VERSION 5.8 ;
BUSBITCHARS "[]" ;
DIVIDERCHAR "/" ;
UNITS
    DATABASE MICRONS 1000 ;
END UNITS

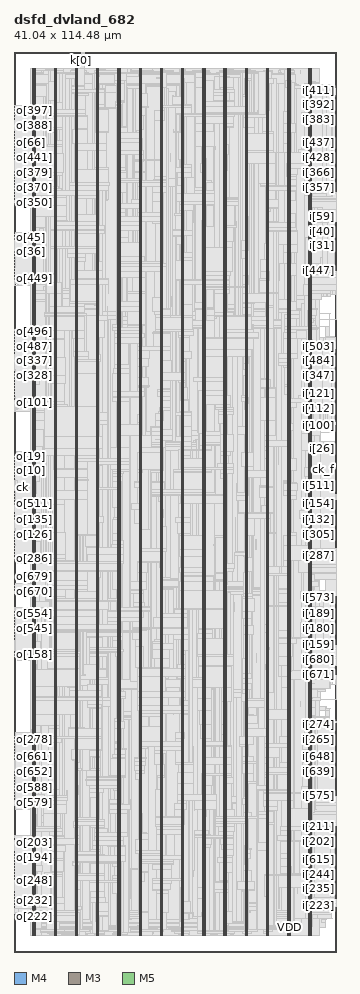
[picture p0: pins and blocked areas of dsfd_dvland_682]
MACRO dsfd_dvland_682
  FOREIGN dsfd_dvland_682 0 0 ;
  CLASS BLOCK ;
  SIZE 41.04 BY 114.48 ;
  PIN ck
    DIRECTION INPUT ;
    USE SIGNAL ;
    PORT
      LAYER M4 ;
        RECT  0 60.048 0.084 60.072 ;
    END
  END ck
  PIN ck_f
    DIRECTION INPUT ;
    USE SIGNAL ;
    PORT
      LAYER M4 ;
        RECT  40.956 61.392 41.04 61.416 ;
    END
  END ck_f
  PIN fault
    DIRECTION OUTPUT ;
    USE SIGNAL ;
    PORT
      LAYER M4 ;
        RECT  0 60.144 0.084 60.168 ;
    END
  END fault
  PIN i[0]
    DIRECTION INPUT ;
    USE SIGNAL ;
    PORT
      LAYER M4 ;
        RECT  40.956 61.488 41.04 61.512 ;
    END
  END i[0]
  PIN i[100]
    DIRECTION INPUT ;
    USE SIGNAL ;
    PORT
      LAYER M4 ;
        RECT  40.956 68.016 41.04 68.04 ;
    END
  END i[100]
  PIN i[101]
    DIRECTION INPUT ;
    USE SIGNAL ;
    PORT
      LAYER M4 ;
        RECT  40.956 68.112 41.04 68.136 ;
    END
  END i[101]
  PIN i[102]
    DIRECTION INPUT ;
    USE SIGNAL ;
    PORT
      LAYER M4 ;
        RECT  40.956 68.208 41.04 68.232 ;
    END
  END i[102]
  PIN i[103]
    DIRECTION INPUT ;
    USE SIGNAL ;
    PORT
      LAYER M4 ;
        RECT  40.956 68.304 41.04 68.328 ;
    END
  END i[103]
  PIN i[104]
    DIRECTION INPUT ;
    USE SIGNAL ;
    PORT
      LAYER M4 ;
        RECT  40.956 68.4 41.04 68.424 ;
    END
  END i[104]
  PIN i[105]
    DIRECTION INPUT ;
    USE SIGNAL ;
    PORT
      LAYER M4 ;
        RECT  40.956 68.496 41.04 68.52 ;
    END
  END i[105]
  PIN i[106]
    DIRECTION INPUT ;
    USE SIGNAL ;
    PORT
      LAYER M4 ;
        RECT  40.956 68.592 41.04 68.616 ;
    END
  END i[106]
  PIN i[107]
    DIRECTION INPUT ;
    USE SIGNAL ;
    PORT
      LAYER M4 ;
        RECT  40.956 68.688 41.04 68.712 ;
    END
  END i[107]
  PIN i[108]
    DIRECTION INPUT ;
    USE SIGNAL ;
    PORT
      LAYER M4 ;
        RECT  40.956 68.784 41.04 68.808 ;
    END
  END i[108]
  PIN i[109]
    DIRECTION INPUT ;
    USE SIGNAL ;
    PORT
      LAYER M4 ;
        RECT  40.956 68.88 41.04 68.904 ;
    END
  END i[109]
  PIN i[10]
    DIRECTION INPUT ;
    USE SIGNAL ;
    PORT
      LAYER M4 ;
        RECT  40.956 62.448 41.04 62.472 ;
    END
  END i[10]
  PIN i[110]
    DIRECTION INPUT ;
    USE SIGNAL ;
    PORT
      LAYER M4 ;
        RECT  40.956 68.976 41.04 69 ;
    END
  END i[110]
  PIN i[111]
    DIRECTION INPUT ;
    USE SIGNAL ;
    PORT
      LAYER M4 ;
        RECT  40.956 69.072 41.04 69.096 ;
    END
  END i[111]
  PIN i[112]
    DIRECTION INPUT ;
    USE SIGNAL ;
    PORT
      LAYER M4 ;
        RECT  40.956 69.168 41.04 69.192 ;
    END
  END i[112]
  PIN i[113]
    DIRECTION INPUT ;
    USE SIGNAL ;
    PORT
      LAYER M4 ;
        RECT  40.956 69.264 41.04 69.288 ;
    END
  END i[113]
  PIN i[114]
    DIRECTION INPUT ;
    USE SIGNAL ;
    PORT
      LAYER M4 ;
        RECT  40.956 69.36 41.04 69.384 ;
    END
  END i[114]
  PIN i[115]
    DIRECTION INPUT ;
    USE SIGNAL ;
    PORT
      LAYER M4 ;
        RECT  40.956 69.456 41.04 69.48 ;
    END
  END i[115]
  PIN i[116]
    DIRECTION INPUT ;
    USE SIGNAL ;
    PORT
      LAYER M4 ;
        RECT  40.956 69.552 41.04 69.576 ;
    END
  END i[116]
  PIN i[117]
    DIRECTION INPUT ;
    USE SIGNAL ;
    PORT
      LAYER M4 ;
        RECT  40.956 69.648 41.04 69.672 ;
    END
  END i[117]
  PIN i[118]
    DIRECTION INPUT ;
    USE SIGNAL ;
    PORT
      LAYER M4 ;
        RECT  40.956 69.744 41.04 69.768 ;
    END
  END i[118]
  PIN i[119]
    DIRECTION INPUT ;
    USE SIGNAL ;
    PORT
      LAYER M4 ;
        RECT  40.956 69.84 41.04 69.864 ;
    END
  END i[119]
  PIN i[11]
    DIRECTION INPUT ;
    USE SIGNAL ;
    PORT
      LAYER M4 ;
        RECT  40.956 62.544 41.04 62.568 ;
    END
  END i[11]
  PIN i[120]
    DIRECTION INPUT ;
    USE SIGNAL ;
    PORT
      LAYER M4 ;
        RECT  40.956 69.936 41.04 69.96 ;
    END
  END i[120]
  PIN i[121]
    DIRECTION INPUT ;
    USE SIGNAL ;
    PORT
      LAYER M4 ;
        RECT  40.956 70.032 41.04 70.056 ;
    END
  END i[121]
  PIN i[122]
    DIRECTION INPUT ;
    USE SIGNAL ;
    PORT
      LAYER M4 ;
        RECT  40.956 70.128 41.04 70.152 ;
    END
  END i[122]
  PIN i[123]
    DIRECTION INPUT ;
    USE SIGNAL ;
    PORT
      LAYER M4 ;
        RECT  40.956 70.224 41.04 70.248 ;
    END
  END i[123]
  PIN i[124]
    DIRECTION INPUT ;
    USE SIGNAL ;
    PORT
      LAYER M4 ;
        RECT  40.956 70.32 41.04 70.344 ;
    END
  END i[124]
  PIN i[125]
    DIRECTION INPUT ;
    USE SIGNAL ;
    PORT
      LAYER M4 ;
        RECT  40.956 70.416 41.04 70.44 ;
    END
  END i[125]
  PIN i[126]
    DIRECTION INPUT ;
    USE SIGNAL ;
    PORT
      LAYER M4 ;
        RECT  40.956 70.512 41.04 70.536 ;
    END
  END i[126]
  PIN i[127]
    DIRECTION INPUT ;
    USE SIGNAL ;
    PORT
      LAYER M4 ;
        RECT  40.956 54.48 41.04 54.504 ;
    END
  END i[127]
  PIN i[128]
    DIRECTION INPUT ;
    USE SIGNAL ;
    PORT
      LAYER M4 ;
        RECT  40.956 54.576 41.04 54.6 ;
    END
  END i[128]
  PIN i[129]
    DIRECTION INPUT ;
    USE SIGNAL ;
    PORT
      LAYER M4 ;
        RECT  40.956 54.672 41.04 54.696 ;
    END
  END i[129]
  PIN i[12]
    DIRECTION INPUT ;
    USE SIGNAL ;
    PORT
      LAYER M4 ;
        RECT  40.956 62.64 41.04 62.664 ;
    END
  END i[12]
  PIN i[130]
    DIRECTION INPUT ;
    USE SIGNAL ;
    PORT
      LAYER M4 ;
        RECT  40.956 54.768 41.04 54.792 ;
    END
  END i[130]
  PIN i[131]
    DIRECTION INPUT ;
    USE SIGNAL ;
    PORT
      LAYER M4 ;
        RECT  40.956 54.864 41.04 54.888 ;
    END
  END i[131]
  PIN i[132]
    DIRECTION INPUT ;
    USE SIGNAL ;
    PORT
      LAYER M4 ;
        RECT  40.956 54.96 41.04 54.984 ;
    END
  END i[132]
  PIN i[133]
    DIRECTION INPUT ;
    USE SIGNAL ;
    PORT
      LAYER M4 ;
        RECT  40.956 55.056 41.04 55.08 ;
    END
  END i[133]
  PIN i[134]
    DIRECTION INPUT ;
    USE SIGNAL ;
    PORT
      LAYER M4 ;
        RECT  40.956 55.152 41.04 55.176 ;
    END
  END i[134]
  PIN i[135]
    DIRECTION INPUT ;
    USE SIGNAL ;
    PORT
      LAYER M4 ;
        RECT  40.956 55.248 41.04 55.272 ;
    END
  END i[135]
  PIN i[136]
    DIRECTION INPUT ;
    USE SIGNAL ;
    PORT
      LAYER M4 ;
        RECT  40.956 55.344 41.04 55.368 ;
    END
  END i[136]
  PIN i[137]
    DIRECTION INPUT ;
    USE SIGNAL ;
    PORT
      LAYER M4 ;
        RECT  40.956 55.44 41.04 55.464 ;
    END
  END i[137]
  PIN i[138]
    DIRECTION INPUT ;
    USE SIGNAL ;
    PORT
      LAYER M4 ;
        RECT  40.956 55.536 41.04 55.56 ;
    END
  END i[138]
  PIN i[139]
    DIRECTION INPUT ;
    USE SIGNAL ;
    PORT
      LAYER M4 ;
        RECT  40.956 55.632 41.04 55.656 ;
    END
  END i[139]
  PIN i[13]
    DIRECTION INPUT ;
    USE SIGNAL ;
    PORT
      LAYER M4 ;
        RECT  40.956 62.736 41.04 62.76 ;
    END
  END i[13]
  PIN i[140]
    DIRECTION INPUT ;
    USE SIGNAL ;
    PORT
      LAYER M4 ;
        RECT  40.956 55.728 41.04 55.752 ;
    END
  END i[140]
  PIN i[141]
    DIRECTION INPUT ;
    USE SIGNAL ;
    PORT
      LAYER M4 ;
        RECT  40.956 55.824 41.04 55.848 ;
    END
  END i[141]
  PIN i[142]
    DIRECTION INPUT ;
    USE SIGNAL ;
    PORT
      LAYER M4 ;
        RECT  40.956 55.92 41.04 55.944 ;
    END
  END i[142]
  PIN i[143]
    DIRECTION INPUT ;
    USE SIGNAL ;
    PORT
      LAYER M4 ;
        RECT  40.956 56.016 41.04 56.04 ;
    END
  END i[143]
  PIN i[144]
    DIRECTION INPUT ;
    USE SIGNAL ;
    PORT
      LAYER M4 ;
        RECT  40.956 56.112 41.04 56.136 ;
    END
  END i[144]
  PIN i[145]
    DIRECTION INPUT ;
    USE SIGNAL ;
    PORT
      LAYER M4 ;
        RECT  40.956 56.208 41.04 56.232 ;
    END
  END i[145]
  PIN i[146]
    DIRECTION INPUT ;
    USE SIGNAL ;
    PORT
      LAYER M4 ;
        RECT  40.956 56.304 41.04 56.328 ;
    END
  END i[146]
  PIN i[147]
    DIRECTION INPUT ;
    USE SIGNAL ;
    PORT
      LAYER M4 ;
        RECT  40.956 56.4 41.04 56.424 ;
    END
  END i[147]
  PIN i[148]
    DIRECTION INPUT ;
    USE SIGNAL ;
    PORT
      LAYER M4 ;
        RECT  40.956 56.496 41.04 56.52 ;
    END
  END i[148]
  PIN i[149]
    DIRECTION INPUT ;
    USE SIGNAL ;
    PORT
      LAYER M4 ;
        RECT  40.956 56.592 41.04 56.616 ;
    END
  END i[149]
  PIN i[14]
    DIRECTION INPUT ;
    USE SIGNAL ;
    PORT
      LAYER M4 ;
        RECT  40.956 62.832 41.04 62.856 ;
    END
  END i[14]
  PIN i[150]
    DIRECTION INPUT ;
    USE SIGNAL ;
    PORT
      LAYER M4 ;
        RECT  40.956 56.688 41.04 56.712 ;
    END
  END i[150]
  PIN i[151]
    DIRECTION INPUT ;
    USE SIGNAL ;
    PORT
      LAYER M4 ;
        RECT  40.956 56.784 41.04 56.808 ;
    END
  END i[151]
  PIN i[152]
    DIRECTION INPUT ;
    USE SIGNAL ;
    PORT
      LAYER M4 ;
        RECT  40.956 56.88 41.04 56.904 ;
    END
  END i[152]
  PIN i[153]
    DIRECTION INPUT ;
    USE SIGNAL ;
    PORT
      LAYER M4 ;
        RECT  40.956 56.976 41.04 57 ;
    END
  END i[153]
  PIN i[154]
    DIRECTION INPUT ;
    USE SIGNAL ;
    PORT
      LAYER M4 ;
        RECT  40.956 57.072 41.04 57.096 ;
    END
  END i[154]
  PIN i[155]
    DIRECTION INPUT ;
    USE SIGNAL ;
    PORT
      LAYER M4 ;
        RECT  40.956 57.168 41.04 57.192 ;
    END
  END i[155]
  PIN i[156]
    DIRECTION INPUT ;
    USE SIGNAL ;
    PORT
      LAYER M4 ;
        RECT  40.956 57.264 41.04 57.288 ;
    END
  END i[156]
  PIN i[157]
    DIRECTION INPUT ;
    USE SIGNAL ;
    PORT
      LAYER M4 ;
        RECT  40.956 57.36 41.04 57.384 ;
    END
  END i[157]
  PIN i[158]
    DIRECTION INPUT ;
    USE SIGNAL ;
    PORT
      LAYER M4 ;
        RECT  40.956 57.456 41.04 57.48 ;
    END
  END i[158]
  PIN i[159]
    DIRECTION INPUT ;
    USE SIGNAL ;
    PORT
      LAYER M4 ;
        RECT  40.956 39.12 41.04 39.144 ;
    END
  END i[159]
  PIN i[15]
    DIRECTION INPUT ;
    USE SIGNAL ;
    PORT
      LAYER M4 ;
        RECT  40.956 62.928 41.04 62.952 ;
    END
  END i[15]
  PIN i[160]
    DIRECTION INPUT ;
    USE SIGNAL ;
    PORT
      LAYER M4 ;
        RECT  40.956 39.216 41.04 39.24 ;
    END
  END i[160]
  PIN i[161]
    DIRECTION INPUT ;
    USE SIGNAL ;
    PORT
      LAYER M4 ;
        RECT  40.956 39.312 41.04 39.336 ;
    END
  END i[161]
  PIN i[162]
    DIRECTION INPUT ;
    USE SIGNAL ;
    PORT
      LAYER M4 ;
        RECT  40.956 39.408 41.04 39.432 ;
    END
  END i[162]
  PIN i[163]
    DIRECTION INPUT ;
    USE SIGNAL ;
    PORT
      LAYER M4 ;
        RECT  40.956 39.504 41.04 39.528 ;
    END
  END i[163]
  PIN i[164]
    DIRECTION INPUT ;
    USE SIGNAL ;
    PORT
      LAYER M4 ;
        RECT  40.956 39.6 41.04 39.624 ;
    END
  END i[164]
  PIN i[165]
    DIRECTION INPUT ;
    USE SIGNAL ;
    PORT
      LAYER M4 ;
        RECT  40.956 39.696 41.04 39.72 ;
    END
  END i[165]
  PIN i[166]
    DIRECTION INPUT ;
    USE SIGNAL ;
    PORT
      LAYER M4 ;
        RECT  40.956 39.792 41.04 39.816 ;
    END
  END i[166]
  PIN i[167]
    DIRECTION INPUT ;
    USE SIGNAL ;
    PORT
      LAYER M4 ;
        RECT  40.956 39.888 41.04 39.912 ;
    END
  END i[167]
  PIN i[168]
    DIRECTION INPUT ;
    USE SIGNAL ;
    PORT
      LAYER M4 ;
        RECT  40.956 39.984 41.04 40.008 ;
    END
  END i[168]
  PIN i[169]
    DIRECTION INPUT ;
    USE SIGNAL ;
    PORT
      LAYER M4 ;
        RECT  40.956 40.08 41.04 40.104 ;
    END
  END i[169]
  PIN i[16]
    DIRECTION INPUT ;
    USE SIGNAL ;
    PORT
      LAYER M4 ;
        RECT  40.956 63.024 41.04 63.048 ;
    END
  END i[16]
  PIN i[170]
    DIRECTION INPUT ;
    USE SIGNAL ;
    PORT
      LAYER M4 ;
        RECT  40.956 40.176 41.04 40.2 ;
    END
  END i[170]
  PIN i[171]
    DIRECTION INPUT ;
    USE SIGNAL ;
    PORT
      LAYER M4 ;
        RECT  40.956 40.272 41.04 40.296 ;
    END
  END i[171]
  PIN i[172]
    DIRECTION INPUT ;
    USE SIGNAL ;
    PORT
      LAYER M4 ;
        RECT  40.956 40.368 41.04 40.392 ;
    END
  END i[172]
  PIN i[173]
    DIRECTION INPUT ;
    USE SIGNAL ;
    PORT
      LAYER M4 ;
        RECT  40.956 40.464 41.04 40.488 ;
    END
  END i[173]
  PIN i[174]
    DIRECTION INPUT ;
    USE SIGNAL ;
    PORT
      LAYER M4 ;
        RECT  40.956 40.56 41.04 40.584 ;
    END
  END i[174]
  PIN i[175]
    DIRECTION INPUT ;
    USE SIGNAL ;
    PORT
      LAYER M4 ;
        RECT  40.956 40.656 41.04 40.68 ;
    END
  END i[175]
  PIN i[176]
    DIRECTION INPUT ;
    USE SIGNAL ;
    PORT
      LAYER M4 ;
        RECT  40.956 40.752 41.04 40.776 ;
    END
  END i[176]
  PIN i[177]
    DIRECTION INPUT ;
    USE SIGNAL ;
    PORT
      LAYER M4 ;
        RECT  40.956 40.848 41.04 40.872 ;
    END
  END i[177]
  PIN i[178]
    DIRECTION INPUT ;
    USE SIGNAL ;
    PORT
      LAYER M4 ;
        RECT  40.956 40.944 41.04 40.968 ;
    END
  END i[178]
  PIN i[179]
    DIRECTION INPUT ;
    USE SIGNAL ;
    PORT
      LAYER M4 ;
        RECT  40.956 41.04 41.04 41.064 ;
    END
  END i[179]
  PIN i[17]
    DIRECTION INPUT ;
    USE SIGNAL ;
    PORT
      LAYER M4 ;
        RECT  40.956 63.12 41.04 63.144 ;
    END
  END i[17]
  PIN i[180]
    DIRECTION INPUT ;
    USE SIGNAL ;
    PORT
      LAYER M4 ;
        RECT  40.956 41.136 41.04 41.16 ;
    END
  END i[180]
  PIN i[181]
    DIRECTION INPUT ;
    USE SIGNAL ;
    PORT
      LAYER M4 ;
        RECT  40.956 41.232 41.04 41.256 ;
    END
  END i[181]
  PIN i[182]
    DIRECTION INPUT ;
    USE SIGNAL ;
    PORT
      LAYER M4 ;
        RECT  40.956 41.328 41.04 41.352 ;
    END
  END i[182]
  PIN i[183]
    DIRECTION INPUT ;
    USE SIGNAL ;
    PORT
      LAYER M4 ;
        RECT  40.956 41.424 41.04 41.448 ;
    END
  END i[183]
  PIN i[184]
    DIRECTION INPUT ;
    USE SIGNAL ;
    PORT
      LAYER M4 ;
        RECT  40.956 41.52 41.04 41.544 ;
    END
  END i[184]
  PIN i[185]
    DIRECTION INPUT ;
    USE SIGNAL ;
    PORT
      LAYER M4 ;
        RECT  40.956 41.616 41.04 41.64 ;
    END
  END i[185]
  PIN i[186]
    DIRECTION INPUT ;
    USE SIGNAL ;
    PORT
      LAYER M4 ;
        RECT  40.956 41.712 41.04 41.736 ;
    END
  END i[186]
  PIN i[187]
    DIRECTION INPUT ;
    USE SIGNAL ;
    PORT
      LAYER M4 ;
        RECT  40.956 41.808 41.04 41.832 ;
    END
  END i[187]
  PIN i[188]
    DIRECTION INPUT ;
    USE SIGNAL ;
    PORT
      LAYER M4 ;
        RECT  40.956 41.904 41.04 41.928 ;
    END
  END i[188]
  PIN i[189]
    DIRECTION INPUT ;
    USE SIGNAL ;
    PORT
      LAYER M4 ;
        RECT  40.956 42 41.04 42.024 ;
    END
  END i[189]
  PIN i[18]
    DIRECTION INPUT ;
    USE SIGNAL ;
    PORT
      LAYER M4 ;
        RECT  40.956 63.216 41.04 63.24 ;
    END
  END i[18]
  PIN i[190]
    DIRECTION INPUT ;
    USE SIGNAL ;
    PORT
      LAYER M4 ;
        RECT  40.956 42.096 41.04 42.12 ;
    END
  END i[190]
  PIN i[191]
    DIRECTION INPUT ;
    USE SIGNAL ;
    PORT
      LAYER M4 ;
        RECT  40.956 13.008 41.04 13.032 ;
    END
  END i[191]
  PIN i[192]
    DIRECTION INPUT ;
    USE SIGNAL ;
    PORT
      LAYER M4 ;
        RECT  40.956 13.104 41.04 13.128 ;
    END
  END i[192]
  PIN i[193]
    DIRECTION INPUT ;
    USE SIGNAL ;
    PORT
      LAYER M4 ;
        RECT  40.956 13.2 41.04 13.224 ;
    END
  END i[193]
  PIN i[194]
    DIRECTION INPUT ;
    USE SIGNAL ;
    PORT
      LAYER M4 ;
        RECT  40.956 13.296 41.04 13.32 ;
    END
  END i[194]
  PIN i[195]
    DIRECTION INPUT ;
    USE SIGNAL ;
    PORT
      LAYER M4 ;
        RECT  40.956 13.392 41.04 13.416 ;
    END
  END i[195]
  PIN i[196]
    DIRECTION INPUT ;
    USE SIGNAL ;
    PORT
      LAYER M4 ;
        RECT  40.956 13.488 41.04 13.512 ;
    END
  END i[196]
  PIN i[197]
    DIRECTION INPUT ;
    USE SIGNAL ;
    PORT
      LAYER M4 ;
        RECT  40.956 13.584 41.04 13.608 ;
    END
  END i[197]
  PIN i[198]
    DIRECTION INPUT ;
    USE SIGNAL ;
    PORT
      LAYER M4 ;
        RECT  40.956 13.68 41.04 13.704 ;
    END
  END i[198]
  PIN i[199]
    DIRECTION INPUT ;
    USE SIGNAL ;
    PORT
      LAYER M4 ;
        RECT  40.956 13.776 41.04 13.8 ;
    END
  END i[199]
  PIN i[19]
    DIRECTION INPUT ;
    USE SIGNAL ;
    PORT
      LAYER M4 ;
        RECT  40.956 63.312 41.04 63.336 ;
    END
  END i[19]
  PIN i[1]
    DIRECTION INPUT ;
    USE SIGNAL ;
    PORT
      LAYER M4 ;
        RECT  40.956 61.584 41.04 61.608 ;
    END
  END i[1]
  PIN i[200]
    DIRECTION INPUT ;
    USE SIGNAL ;
    PORT
      LAYER M4 ;
        RECT  40.956 13.872 41.04 13.896 ;
    END
  END i[200]
  PIN i[201]
    DIRECTION INPUT ;
    USE SIGNAL ;
    PORT
      LAYER M4 ;
        RECT  40.956 13.968 41.04 13.992 ;
    END
  END i[201]
  PIN i[202]
    DIRECTION INPUT ;
    USE SIGNAL ;
    PORT
      LAYER M4 ;
        RECT  40.956 14.064 41.04 14.088 ;
    END
  END i[202]
  PIN i[203]
    DIRECTION INPUT ;
    USE SIGNAL ;
    PORT
      LAYER M4 ;
        RECT  40.956 14.16 41.04 14.184 ;
    END
  END i[203]
  PIN i[204]
    DIRECTION INPUT ;
    USE SIGNAL ;
    PORT
      LAYER M4 ;
        RECT  40.956 14.256 41.04 14.28 ;
    END
  END i[204]
  PIN i[205]
    DIRECTION INPUT ;
    USE SIGNAL ;
    PORT
      LAYER M4 ;
        RECT  40.956 14.352 41.04 14.376 ;
    END
  END i[205]
  PIN i[206]
    DIRECTION INPUT ;
    USE SIGNAL ;
    PORT
      LAYER M4 ;
        RECT  40.956 14.448 41.04 14.472 ;
    END
  END i[206]
  PIN i[207]
    DIRECTION INPUT ;
    USE SIGNAL ;
    PORT
      LAYER M4 ;
        RECT  40.956 14.544 41.04 14.568 ;
    END
  END i[207]
  PIN i[208]
    DIRECTION INPUT ;
    USE SIGNAL ;
    PORT
      LAYER M4 ;
        RECT  40.956 14.64 41.04 14.664 ;
    END
  END i[208]
  PIN i[209]
    DIRECTION INPUT ;
    USE SIGNAL ;
    PORT
      LAYER M4 ;
        RECT  40.956 14.736 41.04 14.76 ;
    END
  END i[209]
  PIN i[20]
    DIRECTION INPUT ;
    USE SIGNAL ;
    PORT
      LAYER M4 ;
        RECT  40.956 63.408 41.04 63.432 ;
    END
  END i[20]
  PIN i[210]
    DIRECTION INPUT ;
    USE SIGNAL ;
    PORT
      LAYER M4 ;
        RECT  40.956 14.832 41.04 14.856 ;
    END
  END i[210]
  PIN i[211]
    DIRECTION INPUT ;
    USE SIGNAL ;
    PORT
      LAYER M4 ;
        RECT  40.956 14.928 41.04 14.952 ;
    END
  END i[211]
  PIN i[212]
    DIRECTION INPUT ;
    USE SIGNAL ;
    PORT
      LAYER M4 ;
        RECT  40.956 15.024 41.04 15.048 ;
    END
  END i[212]
  PIN i[213]
    DIRECTION INPUT ;
    USE SIGNAL ;
    PORT
      LAYER M4 ;
        RECT  40.956 15.12 41.04 15.144 ;
    END
  END i[213]
  PIN i[214]
    DIRECTION INPUT ;
    USE SIGNAL ;
    PORT
      LAYER M4 ;
        RECT  40.956 15.216 41.04 15.24 ;
    END
  END i[214]
  PIN i[215]
    DIRECTION INPUT ;
    USE SIGNAL ;
    PORT
      LAYER M4 ;
        RECT  40.956 15.312 41.04 15.336 ;
    END
  END i[215]
  PIN i[216]
    DIRECTION INPUT ;
    USE SIGNAL ;
    PORT
      LAYER M4 ;
        RECT  40.956 15.408 41.04 15.432 ;
    END
  END i[216]
  PIN i[217]
    DIRECTION INPUT ;
    USE SIGNAL ;
    PORT
      LAYER M4 ;
        RECT  40.956 15.504 41.04 15.528 ;
    END
  END i[217]
  PIN i[218]
    DIRECTION INPUT ;
    USE SIGNAL ;
    PORT
      LAYER M4 ;
        RECT  40.956 15.6 41.04 15.624 ;
    END
  END i[218]
  PIN i[219]
    DIRECTION INPUT ;
    USE SIGNAL ;
    PORT
      LAYER M4 ;
        RECT  40.956 15.696 41.04 15.72 ;
    END
  END i[219]
  PIN i[21]
    DIRECTION INPUT ;
    USE SIGNAL ;
    PORT
      LAYER M4 ;
        RECT  40.956 63.504 41.04 63.528 ;
    END
  END i[21]
  PIN i[220]
    DIRECTION INPUT ;
    USE SIGNAL ;
    PORT
      LAYER M4 ;
        RECT  40.956 15.792 41.04 15.816 ;
    END
  END i[220]
  PIN i[221]
    DIRECTION INPUT ;
    USE SIGNAL ;
    PORT
      LAYER M4 ;
        RECT  40.956 15.888 41.04 15.912 ;
    END
  END i[221]
  PIN i[222]
    DIRECTION INPUT ;
    USE SIGNAL ;
    PORT
      LAYER M4 ;
        RECT  40.956 15.984 41.04 16.008 ;
    END
  END i[222]
  PIN i[223]
    DIRECTION INPUT ;
    USE SIGNAL ;
    PORT
      LAYER M4 ;
        RECT  40.956 6.864 41.04 6.888 ;
    END
  END i[223]
  PIN i[224]
    DIRECTION INPUT ;
    USE SIGNAL ;
    PORT
      LAYER M4 ;
        RECT  40.956 6.96 41.04 6.984 ;
    END
  END i[224]
  PIN i[225]
    DIRECTION INPUT ;
    USE SIGNAL ;
    PORT
      LAYER M4 ;
        RECT  40.956 7.056 41.04 7.08 ;
    END
  END i[225]
  PIN i[226]
    DIRECTION INPUT ;
    USE SIGNAL ;
    PORT
      LAYER M4 ;
        RECT  40.956 7.152 41.04 7.176 ;
    END
  END i[226]
  PIN i[227]
    DIRECTION INPUT ;
    USE SIGNAL ;
    PORT
      LAYER M4 ;
        RECT  40.956 7.248 41.04 7.272 ;
    END
  END i[227]
  PIN i[228]
    DIRECTION INPUT ;
    USE SIGNAL ;
    PORT
      LAYER M4 ;
        RECT  40.956 7.344 41.04 7.368 ;
    END
  END i[228]
  PIN i[229]
    DIRECTION INPUT ;
    USE SIGNAL ;
    PORT
      LAYER M4 ;
        RECT  40.956 7.44 41.04 7.464 ;
    END
  END i[229]
  PIN i[22]
    DIRECTION INPUT ;
    USE SIGNAL ;
    PORT
      LAYER M4 ;
        RECT  40.956 63.6 41.04 63.624 ;
    END
  END i[22]
  PIN i[230]
    DIRECTION INPUT ;
    USE SIGNAL ;
    PORT
      LAYER M4 ;
        RECT  40.956 7.536 41.04 7.56 ;
    END
  END i[230]
  PIN i[231]
    DIRECTION INPUT ;
    USE SIGNAL ;
    PORT
      LAYER M4 ;
        RECT  40.956 7.632 41.04 7.656 ;
    END
  END i[231]
  PIN i[232]
    DIRECTION INPUT ;
    USE SIGNAL ;
    PORT
      LAYER M4 ;
        RECT  40.956 7.728 41.04 7.752 ;
    END
  END i[232]
  PIN i[233]
    DIRECTION INPUT ;
    USE SIGNAL ;
    PORT
      LAYER M4 ;
        RECT  40.956 7.824 41.04 7.848 ;
    END
  END i[233]
  PIN i[234]
    DIRECTION INPUT ;
    USE SIGNAL ;
    PORT
      LAYER M4 ;
        RECT  40.956 7.92 41.04 7.944 ;
    END
  END i[234]
  PIN i[235]
    DIRECTION INPUT ;
    USE SIGNAL ;
    PORT
      LAYER M4 ;
        RECT  40.956 8.016 41.04 8.04 ;
    END
  END i[235]
  PIN i[236]
    DIRECTION INPUT ;
    USE SIGNAL ;
    PORT
      LAYER M4 ;
        RECT  40.956 8.112 41.04 8.136 ;
    END
  END i[236]
  PIN i[237]
    DIRECTION INPUT ;
    USE SIGNAL ;
    PORT
      LAYER M4 ;
        RECT  40.956 8.208 41.04 8.232 ;
    END
  END i[237]
  PIN i[238]
    DIRECTION INPUT ;
    USE SIGNAL ;
    PORT
      LAYER M4 ;
        RECT  40.956 8.304 41.04 8.328 ;
    END
  END i[238]
  PIN i[239]
    DIRECTION INPUT ;
    USE SIGNAL ;
    PORT
      LAYER M4 ;
        RECT  40.956 8.4 41.04 8.424 ;
    END
  END i[239]
  PIN i[23]
    DIRECTION INPUT ;
    USE SIGNAL ;
    PORT
      LAYER M4 ;
        RECT  40.956 63.696 41.04 63.72 ;
    END
  END i[23]
  PIN i[240]
    DIRECTION INPUT ;
    USE SIGNAL ;
    PORT
      LAYER M4 ;
        RECT  40.956 8.496 41.04 8.52 ;
    END
  END i[240]
  PIN i[241]
    DIRECTION INPUT ;
    USE SIGNAL ;
    PORT
      LAYER M4 ;
        RECT  40.956 8.592 41.04 8.616 ;
    END
  END i[241]
  PIN i[242]
    DIRECTION INPUT ;
    USE SIGNAL ;
    PORT
      LAYER M4 ;
        RECT  40.956 8.688 41.04 8.712 ;
    END
  END i[242]
  PIN i[243]
    DIRECTION INPUT ;
    USE SIGNAL ;
    PORT
      LAYER M4 ;
        RECT  40.956 8.784 41.04 8.808 ;
    END
  END i[243]
  PIN i[244]
    DIRECTION INPUT ;
    USE SIGNAL ;
    PORT
      LAYER M4 ;
        RECT  40.956 8.88 41.04 8.904 ;
    END
  END i[244]
  PIN i[245]
    DIRECTION INPUT ;
    USE SIGNAL ;
    PORT
      LAYER M4 ;
        RECT  40.956 8.976 41.04 9 ;
    END
  END i[245]
  PIN i[246]
    DIRECTION INPUT ;
    USE SIGNAL ;
    PORT
      LAYER M4 ;
        RECT  40.956 9.072 41.04 9.096 ;
    END
  END i[246]
  PIN i[247]
    DIRECTION INPUT ;
    USE SIGNAL ;
    PORT
      LAYER M4 ;
        RECT  40.956 9.168 41.04 9.192 ;
    END
  END i[247]
  PIN i[248]
    DIRECTION INPUT ;
    USE SIGNAL ;
    PORT
      LAYER M4 ;
        RECT  40.956 9.264 41.04 9.288 ;
    END
  END i[248]
  PIN i[249]
    DIRECTION INPUT ;
    USE SIGNAL ;
    PORT
      LAYER M4 ;
        RECT  40.956 9.36 41.04 9.384 ;
    END
  END i[249]
  PIN i[24]
    DIRECTION INPUT ;
    USE SIGNAL ;
    PORT
      LAYER M4 ;
        RECT  40.956 63.792 41.04 63.816 ;
    END
  END i[24]
  PIN i[250]
    DIRECTION INPUT ;
    USE SIGNAL ;
    PORT
      LAYER M4 ;
        RECT  40.956 9.456 41.04 9.48 ;
    END
  END i[250]
  PIN i[251]
    DIRECTION INPUT ;
    USE SIGNAL ;
    PORT
      LAYER M4 ;
        RECT  40.956 9.552 41.04 9.576 ;
    END
  END i[251]
  PIN i[252]
    DIRECTION INPUT ;
    USE SIGNAL ;
    PORT
      LAYER M4 ;
        RECT  40.956 9.648 41.04 9.672 ;
    END
  END i[252]
  PIN i[253]
    DIRECTION INPUT ;
    USE SIGNAL ;
    PORT
      LAYER M4 ;
        RECT  40.956 9.744 41.04 9.768 ;
    END
  END i[253]
  PIN i[254]
    DIRECTION INPUT ;
    USE SIGNAL ;
    PORT
      LAYER M4 ;
        RECT  40.956 9.84 41.04 9.864 ;
    END
  END i[254]
  PIN i[255]
    DIRECTION INPUT ;
    USE SIGNAL ;
    PORT
      LAYER M4 ;
        RECT  40.956 26.064 41.04 26.088 ;
    END
  END i[255]
  PIN i[256]
    DIRECTION INPUT ;
    USE SIGNAL ;
    PORT
      LAYER M4 ;
        RECT  40.956 26.16 41.04 26.184 ;
    END
  END i[256]
  PIN i[257]
    DIRECTION INPUT ;
    USE SIGNAL ;
    PORT
      LAYER M4 ;
        RECT  40.956 26.256 41.04 26.28 ;
    END
  END i[257]
  PIN i[258]
    DIRECTION INPUT ;
    USE SIGNAL ;
    PORT
      LAYER M4 ;
        RECT  40.956 26.352 41.04 26.376 ;
    END
  END i[258]
  PIN i[259]
    DIRECTION INPUT ;
    USE SIGNAL ;
    PORT
      LAYER M4 ;
        RECT  40.956 26.448 41.04 26.472 ;
    END
  END i[259]
  PIN i[25]
    DIRECTION INPUT ;
    USE SIGNAL ;
    PORT
      LAYER M4 ;
        RECT  40.956 63.888 41.04 63.912 ;
    END
  END i[25]
  PIN i[260]
    DIRECTION INPUT ;
    USE SIGNAL ;
    PORT
      LAYER M4 ;
        RECT  40.956 26.544 41.04 26.568 ;
    END
  END i[260]
  PIN i[261]
    DIRECTION INPUT ;
    USE SIGNAL ;
    PORT
      LAYER M4 ;
        RECT  40.956 26.64 41.04 26.664 ;
    END
  END i[261]
  PIN i[262]
    DIRECTION INPUT ;
    USE SIGNAL ;
    PORT
      LAYER M4 ;
        RECT  40.956 26.736 41.04 26.76 ;
    END
  END i[262]
  PIN i[263]
    DIRECTION INPUT ;
    USE SIGNAL ;
    PORT
      LAYER M4 ;
        RECT  40.956 26.832 41.04 26.856 ;
    END
  END i[263]
  PIN i[264]
    DIRECTION INPUT ;
    USE SIGNAL ;
    PORT
      LAYER M4 ;
        RECT  40.956 26.928 41.04 26.952 ;
    END
  END i[264]
  PIN i[265]
    DIRECTION INPUT ;
    USE SIGNAL ;
    PORT
      LAYER M4 ;
        RECT  40.956 27.024 41.04 27.048 ;
    END
  END i[265]
  PIN i[266]
    DIRECTION INPUT ;
    USE SIGNAL ;
    PORT
      LAYER M4 ;
        RECT  40.956 27.12 41.04 27.144 ;
    END
  END i[266]
  PIN i[267]
    DIRECTION INPUT ;
    USE SIGNAL ;
    PORT
      LAYER M4 ;
        RECT  40.956 27.216 41.04 27.24 ;
    END
  END i[267]
  PIN i[268]
    DIRECTION INPUT ;
    USE SIGNAL ;
    PORT
      LAYER M4 ;
        RECT  40.956 27.312 41.04 27.336 ;
    END
  END i[268]
  PIN i[269]
    DIRECTION INPUT ;
    USE SIGNAL ;
    PORT
      LAYER M4 ;
        RECT  40.956 27.408 41.04 27.432 ;
    END
  END i[269]
  PIN i[26]
    DIRECTION INPUT ;
    USE SIGNAL ;
    PORT
      LAYER M4 ;
        RECT  40.956 63.984 41.04 64.008 ;
    END
  END i[26]
  PIN i[270]
    DIRECTION INPUT ;
    USE SIGNAL ;
    PORT
      LAYER M4 ;
        RECT  40.956 27.504 41.04 27.528 ;
    END
  END i[270]
  PIN i[271]
    DIRECTION INPUT ;
    USE SIGNAL ;
    PORT
      LAYER M4 ;
        RECT  40.956 27.6 41.04 27.624 ;
    END
  END i[271]
  PIN i[272]
    DIRECTION INPUT ;
    USE SIGNAL ;
    PORT
      LAYER M4 ;
        RECT  40.956 27.696 41.04 27.72 ;
    END
  END i[272]
  PIN i[273]
    DIRECTION INPUT ;
    USE SIGNAL ;
    PORT
      LAYER M4 ;
        RECT  40.956 27.792 41.04 27.816 ;
    END
  END i[273]
  PIN i[274]
    DIRECTION INPUT ;
    USE SIGNAL ;
    PORT
      LAYER M4 ;
        RECT  40.956 27.888 41.04 27.912 ;
    END
  END i[274]
  PIN i[275]
    DIRECTION INPUT ;
    USE SIGNAL ;
    PORT
      LAYER M4 ;
        RECT  40.956 27.984 41.04 28.008 ;
    END
  END i[275]
  PIN i[276]
    DIRECTION INPUT ;
    USE SIGNAL ;
    PORT
      LAYER M4 ;
        RECT  40.956 28.08 41.04 28.104 ;
    END
  END i[276]
  PIN i[277]
    DIRECTION INPUT ;
    USE SIGNAL ;
    PORT
      LAYER M4 ;
        RECT  40.956 28.176 41.04 28.2 ;
    END
  END i[277]
  PIN i[278]
    DIRECTION INPUT ;
    USE SIGNAL ;
    PORT
      LAYER M4 ;
        RECT  40.956 28.272 41.04 28.296 ;
    END
  END i[278]
  PIN i[279]
    DIRECTION INPUT ;
    USE SIGNAL ;
    PORT
      LAYER M4 ;
        RECT  40.956 28.368 41.04 28.392 ;
    END
  END i[279]
  PIN i[27]
    DIRECTION INPUT ;
    USE SIGNAL ;
    PORT
      LAYER M4 ;
        RECT  40.956 64.08 41.04 64.104 ;
    END
  END i[27]
  PIN i[280]
    DIRECTION INPUT ;
    USE SIGNAL ;
    PORT
      LAYER M4 ;
        RECT  40.956 28.464 41.04 28.488 ;
    END
  END i[280]
  PIN i[281]
    DIRECTION INPUT ;
    USE SIGNAL ;
    PORT
      LAYER M4 ;
        RECT  40.956 28.56 41.04 28.584 ;
    END
  END i[281]
  PIN i[282]
    DIRECTION INPUT ;
    USE SIGNAL ;
    PORT
      LAYER M4 ;
        RECT  40.956 28.656 41.04 28.68 ;
    END
  END i[282]
  PIN i[283]
    DIRECTION INPUT ;
    USE SIGNAL ;
    PORT
      LAYER M4 ;
        RECT  40.956 28.752 41.04 28.776 ;
    END
  END i[283]
  PIN i[284]
    DIRECTION INPUT ;
    USE SIGNAL ;
    PORT
      LAYER M4 ;
        RECT  40.956 28.848 41.04 28.872 ;
    END
  END i[284]
  PIN i[285]
    DIRECTION INPUT ;
    USE SIGNAL ;
    PORT
      LAYER M4 ;
        RECT  40.956 28.944 41.04 28.968 ;
    END
  END i[285]
  PIN i[286]
    DIRECTION INPUT ;
    USE SIGNAL ;
    PORT
      LAYER M4 ;
        RECT  40.956 29.04 41.04 29.064 ;
    END
  END i[286]
  PIN i[287]
    DIRECTION INPUT ;
    USE SIGNAL ;
    PORT
      LAYER M4 ;
        RECT  40.956 51.408 41.04 51.432 ;
    END
  END i[287]
  PIN i[288]
    DIRECTION INPUT ;
    USE SIGNAL ;
    PORT
      LAYER M4 ;
        RECT  40.956 51.504 41.04 51.528 ;
    END
  END i[288]
  PIN i[289]
    DIRECTION INPUT ;
    USE SIGNAL ;
    PORT
      LAYER M4 ;
        RECT  40.956 51.6 41.04 51.624 ;
    END
  END i[289]
  PIN i[28]
    DIRECTION INPUT ;
    USE SIGNAL ;
    PORT
      LAYER M4 ;
        RECT  40.956 64.176 41.04 64.2 ;
    END
  END i[28]
  PIN i[290]
    DIRECTION INPUT ;
    USE SIGNAL ;
    PORT
      LAYER M4 ;
        RECT  40.956 51.696 41.04 51.72 ;
    END
  END i[290]
  PIN i[291]
    DIRECTION INPUT ;
    USE SIGNAL ;
    PORT
      LAYER M4 ;
        RECT  40.956 51.792 41.04 51.816 ;
    END
  END i[291]
  PIN i[292]
    DIRECTION INPUT ;
    USE SIGNAL ;
    PORT
      LAYER M4 ;
        RECT  40.956 51.888 41.04 51.912 ;
    END
  END i[292]
  PIN i[293]
    DIRECTION INPUT ;
    USE SIGNAL ;
    PORT
      LAYER M4 ;
        RECT  40.956 51.984 41.04 52.008 ;
    END
  END i[293]
  PIN i[294]
    DIRECTION INPUT ;
    USE SIGNAL ;
    PORT
      LAYER M4 ;
        RECT  40.956 52.08 41.04 52.104 ;
    END
  END i[294]
  PIN i[295]
    DIRECTION INPUT ;
    USE SIGNAL ;
    PORT
      LAYER M4 ;
        RECT  40.956 52.176 41.04 52.2 ;
    END
  END i[295]
  PIN i[296]
    DIRECTION INPUT ;
    USE SIGNAL ;
    PORT
      LAYER M4 ;
        RECT  40.956 52.272 41.04 52.296 ;
    END
  END i[296]
  PIN i[297]
    DIRECTION INPUT ;
    USE SIGNAL ;
    PORT
      LAYER M4 ;
        RECT  40.956 52.368 41.04 52.392 ;
    END
  END i[297]
  PIN i[298]
    DIRECTION INPUT ;
    USE SIGNAL ;
    PORT
      LAYER M4 ;
        RECT  40.956 52.464 41.04 52.488 ;
    END
  END i[298]
  PIN i[299]
    DIRECTION INPUT ;
    USE SIGNAL ;
    PORT
      LAYER M4 ;
        RECT  40.956 52.56 41.04 52.584 ;
    END
  END i[299]
  PIN i[29]
    DIRECTION INPUT ;
    USE SIGNAL ;
    PORT
      LAYER M4 ;
        RECT  40.956 64.272 41.04 64.296 ;
    END
  END i[29]
  PIN i[2]
    DIRECTION INPUT ;
    USE SIGNAL ;
    PORT
      LAYER M4 ;
        RECT  40.956 61.68 41.04 61.704 ;
    END
  END i[2]
  PIN i[300]
    DIRECTION INPUT ;
    USE SIGNAL ;
    PORT
      LAYER M4 ;
        RECT  40.956 52.656 41.04 52.68 ;
    END
  END i[300]
  PIN i[301]
    DIRECTION INPUT ;
    USE SIGNAL ;
    PORT
      LAYER M4 ;
        RECT  40.956 52.752 41.04 52.776 ;
    END
  END i[301]
  PIN i[302]
    DIRECTION INPUT ;
    USE SIGNAL ;
    PORT
      LAYER M4 ;
        RECT  40.956 52.848 41.04 52.872 ;
    END
  END i[302]
  PIN i[303]
    DIRECTION INPUT ;
    USE SIGNAL ;
    PORT
      LAYER M4 ;
        RECT  40.956 52.944 41.04 52.968 ;
    END
  END i[303]
  PIN i[304]
    DIRECTION INPUT ;
    USE SIGNAL ;
    PORT
      LAYER M4 ;
        RECT  40.956 53.04 41.04 53.064 ;
    END
  END i[304]
  PIN i[305]
    DIRECTION INPUT ;
    USE SIGNAL ;
    PORT
      LAYER M4 ;
        RECT  40.956 53.136 41.04 53.16 ;
    END
  END i[305]
  PIN i[306]
    DIRECTION INPUT ;
    USE SIGNAL ;
    PORT
      LAYER M4 ;
        RECT  40.956 53.232 41.04 53.256 ;
    END
  END i[306]
  PIN i[307]
    DIRECTION INPUT ;
    USE SIGNAL ;
    PORT
      LAYER M4 ;
        RECT  40.956 53.328 41.04 53.352 ;
    END
  END i[307]
  PIN i[308]
    DIRECTION INPUT ;
    USE SIGNAL ;
    PORT
      LAYER M4 ;
        RECT  40.956 53.424 41.04 53.448 ;
    END
  END i[308]
  PIN i[309]
    DIRECTION INPUT ;
    USE SIGNAL ;
    PORT
      LAYER M4 ;
        RECT  40.956 53.52 41.04 53.544 ;
    END
  END i[309]
  PIN i[30]
    DIRECTION INPUT ;
    USE SIGNAL ;
    PORT
      LAYER M4 ;
        RECT  40.956 64.368 41.04 64.392 ;
    END
  END i[30]
  PIN i[310]
    DIRECTION INPUT ;
    USE SIGNAL ;
    PORT
      LAYER M4 ;
        RECT  40.956 53.616 41.04 53.64 ;
    END
  END i[310]
  PIN i[311]
    DIRECTION INPUT ;
    USE SIGNAL ;
    PORT
      LAYER M4 ;
        RECT  40.956 53.712 41.04 53.736 ;
    END
  END i[311]
  PIN i[312]
    DIRECTION INPUT ;
    USE SIGNAL ;
    PORT
      LAYER M4 ;
        RECT  40.956 53.808 41.04 53.832 ;
    END
  END i[312]
  PIN i[313]
    DIRECTION INPUT ;
    USE SIGNAL ;
    PORT
      LAYER M4 ;
        RECT  40.956 53.904 41.04 53.928 ;
    END
  END i[313]
  PIN i[314]
    DIRECTION INPUT ;
    USE SIGNAL ;
    PORT
      LAYER M4 ;
        RECT  40.956 54 41.04 54.024 ;
    END
  END i[314]
  PIN i[315]
    DIRECTION INPUT ;
    USE SIGNAL ;
    PORT
      LAYER M4 ;
        RECT  40.956 54.096 41.04 54.12 ;
    END
  END i[315]
  PIN i[316]
    DIRECTION INPUT ;
    USE SIGNAL ;
    PORT
      LAYER M4 ;
        RECT  40.956 54.192 41.04 54.216 ;
    END
  END i[316]
  PIN i[317]
    DIRECTION INPUT ;
    USE SIGNAL ;
    PORT
      LAYER M4 ;
        RECT  40.956 54.288 41.04 54.312 ;
    END
  END i[317]
  PIN i[318]
    DIRECTION INPUT ;
    USE SIGNAL ;
    PORT
      LAYER M4 ;
        RECT  40.956 54.384 41.04 54.408 ;
    END
  END i[318]
  PIN i[319]
    DIRECTION INPUT ;
    USE SIGNAL ;
    PORT
      LAYER M4 ;
        RECT  40.956 70.608 41.04 70.632 ;
    END
  END i[319]
  PIN i[31]
    DIRECTION INPUT ;
    USE SIGNAL ;
    PORT
      LAYER M4 ;
        RECT  40.956 89.808 41.04 89.832 ;
    END
  END i[31]
  PIN i[320]
    DIRECTION INPUT ;
    USE SIGNAL ;
    PORT
      LAYER M4 ;
        RECT  40.956 70.704 41.04 70.728 ;
    END
  END i[320]
  PIN i[321]
    DIRECTION INPUT ;
    USE SIGNAL ;
    PORT
      LAYER M4 ;
        RECT  40.956 70.8 41.04 70.824 ;
    END
  END i[321]
  PIN i[322]
    DIRECTION INPUT ;
    USE SIGNAL ;
    PORT
      LAYER M4 ;
        RECT  40.956 70.896 41.04 70.92 ;
    END
  END i[322]
  PIN i[323]
    DIRECTION INPUT ;
    USE SIGNAL ;
    PORT
      LAYER M4 ;
        RECT  40.956 70.992 41.04 71.016 ;
    END
  END i[323]
  PIN i[324]
    DIRECTION INPUT ;
    USE SIGNAL ;
    PORT
      LAYER M4 ;
        RECT  40.956 71.088 41.04 71.112 ;
    END
  END i[324]
  PIN i[325]
    DIRECTION INPUT ;
    USE SIGNAL ;
    PORT
      LAYER M4 ;
        RECT  40.956 71.184 41.04 71.208 ;
    END
  END i[325]
  PIN i[326]
    DIRECTION INPUT ;
    USE SIGNAL ;
    PORT
      LAYER M4 ;
        RECT  40.956 71.28 41.04 71.304 ;
    END
  END i[326]
  PIN i[327]
    DIRECTION INPUT ;
    USE SIGNAL ;
    PORT
      LAYER M4 ;
        RECT  40.956 71.376 41.04 71.4 ;
    END
  END i[327]
  PIN i[328]
    DIRECTION INPUT ;
    USE SIGNAL ;
    PORT
      LAYER M4 ;
        RECT  40.956 71.472 41.04 71.496 ;
    END
  END i[328]
  PIN i[329]
    DIRECTION INPUT ;
    USE SIGNAL ;
    PORT
      LAYER M4 ;
        RECT  40.956 71.568 41.04 71.592 ;
    END
  END i[329]
  PIN i[32]
    DIRECTION INPUT ;
    USE SIGNAL ;
    PORT
      LAYER M4 ;
        RECT  40.956 89.904 41.04 89.928 ;
    END
  END i[32]
  PIN i[330]
    DIRECTION INPUT ;
    USE SIGNAL ;
    PORT
      LAYER M4 ;
        RECT  40.956 71.664 41.04 71.688 ;
    END
  END i[330]
  PIN i[331]
    DIRECTION INPUT ;
    USE SIGNAL ;
    PORT
      LAYER M4 ;
        RECT  40.956 71.76 41.04 71.784 ;
    END
  END i[331]
  PIN i[332]
    DIRECTION INPUT ;
    USE SIGNAL ;
    PORT
      LAYER M4 ;
        RECT  40.956 71.856 41.04 71.88 ;
    END
  END i[332]
  PIN i[333]
    DIRECTION INPUT ;
    USE SIGNAL ;
    PORT
      LAYER M4 ;
        RECT  40.956 71.952 41.04 71.976 ;
    END
  END i[333]
  PIN i[334]
    DIRECTION INPUT ;
    USE SIGNAL ;
    PORT
      LAYER M4 ;
        RECT  40.956 72.048 41.04 72.072 ;
    END
  END i[334]
  PIN i[335]
    DIRECTION INPUT ;
    USE SIGNAL ;
    PORT
      LAYER M4 ;
        RECT  40.956 72.144 41.04 72.168 ;
    END
  END i[335]
  PIN i[336]
    DIRECTION INPUT ;
    USE SIGNAL ;
    PORT
      LAYER M4 ;
        RECT  40.956 72.24 41.04 72.264 ;
    END
  END i[336]
  PIN i[337]
    DIRECTION INPUT ;
    USE SIGNAL ;
    PORT
      LAYER M4 ;
        RECT  40.956 72.336 41.04 72.36 ;
    END
  END i[337]
  PIN i[338]
    DIRECTION INPUT ;
    USE SIGNAL ;
    PORT
      LAYER M4 ;
        RECT  40.956 72.432 41.04 72.456 ;
    END
  END i[338]
  PIN i[339]
    DIRECTION INPUT ;
    USE SIGNAL ;
    PORT
      LAYER M4 ;
        RECT  40.956 72.528 41.04 72.552 ;
    END
  END i[339]
  PIN i[33]
    DIRECTION INPUT ;
    USE SIGNAL ;
    PORT
      LAYER M4 ;
        RECT  40.956 90 41.04 90.024 ;
    END
  END i[33]
  PIN i[340]
    DIRECTION INPUT ;
    USE SIGNAL ;
    PORT
      LAYER M4 ;
        RECT  40.956 72.624 41.04 72.648 ;
    END
  END i[340]
  PIN i[341]
    DIRECTION INPUT ;
    USE SIGNAL ;
    PORT
      LAYER M4 ;
        RECT  40.956 72.72 41.04 72.744 ;
    END
  END i[341]
  PIN i[342]
    DIRECTION INPUT ;
    USE SIGNAL ;
    PORT
      LAYER M4 ;
        RECT  40.956 72.816 41.04 72.84 ;
    END
  END i[342]
  PIN i[343]
    DIRECTION INPUT ;
    USE SIGNAL ;
    PORT
      LAYER M4 ;
        RECT  40.956 72.912 41.04 72.936 ;
    END
  END i[343]
  PIN i[344]
    DIRECTION INPUT ;
    USE SIGNAL ;
    PORT
      LAYER M4 ;
        RECT  40.956 73.008 41.04 73.032 ;
    END
  END i[344]
  PIN i[345]
    DIRECTION INPUT ;
    USE SIGNAL ;
    PORT
      LAYER M4 ;
        RECT  40.956 73.104 41.04 73.128 ;
    END
  END i[345]
  PIN i[346]
    DIRECTION INPUT ;
    USE SIGNAL ;
    PORT
      LAYER M4 ;
        RECT  40.956 73.2 41.04 73.224 ;
    END
  END i[346]
  PIN i[347]
    DIRECTION INPUT ;
    USE SIGNAL ;
    PORT
      LAYER M4 ;
        RECT  40.956 73.296 41.04 73.32 ;
    END
  END i[347]
  PIN i[348]
    DIRECTION INPUT ;
    USE SIGNAL ;
    PORT
      LAYER M4 ;
        RECT  40.956 73.392 41.04 73.416 ;
    END
  END i[348]
  PIN i[349]
    DIRECTION INPUT ;
    USE SIGNAL ;
    PORT
      LAYER M4 ;
        RECT  40.956 73.488 41.04 73.512 ;
    END
  END i[349]
  PIN i[34]
    DIRECTION INPUT ;
    USE SIGNAL ;
    PORT
      LAYER M4 ;
        RECT  40.956 90.096 41.04 90.12 ;
    END
  END i[34]
  PIN i[350]
    DIRECTION INPUT ;
    USE SIGNAL ;
    PORT
      LAYER M4 ;
        RECT  40.956 73.584 41.04 73.608 ;
    END
  END i[350]
  PIN i[351]
    DIRECTION INPUT ;
    USE SIGNAL ;
    PORT
      LAYER M4 ;
        RECT  40.956 96.72 41.04 96.744 ;
    END
  END i[351]
  PIN i[352]
    DIRECTION INPUT ;
    USE SIGNAL ;
    PORT
      LAYER M4 ;
        RECT  40.956 96.816 41.04 96.84 ;
    END
  END i[352]
  PIN i[353]
    DIRECTION INPUT ;
    USE SIGNAL ;
    PORT
      LAYER M4 ;
        RECT  40.956 96.912 41.04 96.936 ;
    END
  END i[353]
  PIN i[354]
    DIRECTION INPUT ;
    USE SIGNAL ;
    PORT
      LAYER M4 ;
        RECT  40.956 97.008 41.04 97.032 ;
    END
  END i[354]
  PIN i[355]
    DIRECTION INPUT ;
    USE SIGNAL ;
    PORT
      LAYER M4 ;
        RECT  40.956 97.104 41.04 97.128 ;
    END
  END i[355]
  PIN i[356]
    DIRECTION INPUT ;
    USE SIGNAL ;
    PORT
      LAYER M4 ;
        RECT  40.956 97.2 41.04 97.224 ;
    END
  END i[356]
  PIN i[357]
    DIRECTION INPUT ;
    USE SIGNAL ;
    PORT
      LAYER M4 ;
        RECT  40.956 97.296 41.04 97.32 ;
    END
  END i[357]
  PIN i[358]
    DIRECTION INPUT ;
    USE SIGNAL ;
    PORT
      LAYER M4 ;
        RECT  40.956 97.392 41.04 97.416 ;
    END
  END i[358]
  PIN i[359]
    DIRECTION INPUT ;
    USE SIGNAL ;
    PORT
      LAYER M4 ;
        RECT  40.956 97.488 41.04 97.512 ;
    END
  END i[359]
  PIN i[35]
    DIRECTION INPUT ;
    USE SIGNAL ;
    PORT
      LAYER M4 ;
        RECT  40.956 90.192 41.04 90.216 ;
    END
  END i[35]
  PIN i[360]
    DIRECTION INPUT ;
    USE SIGNAL ;
    PORT
      LAYER M4 ;
        RECT  40.956 97.584 41.04 97.608 ;
    END
  END i[360]
  PIN i[361]
    DIRECTION INPUT ;
    USE SIGNAL ;
    PORT
      LAYER M4 ;
        RECT  40.956 97.68 41.04 97.704 ;
    END
  END i[361]
  PIN i[362]
    DIRECTION INPUT ;
    USE SIGNAL ;
    PORT
      LAYER M4 ;
        RECT  40.956 97.776 41.04 97.8 ;
    END
  END i[362]
  PIN i[363]
    DIRECTION INPUT ;
    USE SIGNAL ;
    PORT
      LAYER M4 ;
        RECT  40.956 97.872 41.04 97.896 ;
    END
  END i[363]
  PIN i[364]
    DIRECTION INPUT ;
    USE SIGNAL ;
    PORT
      LAYER M4 ;
        RECT  40.956 97.968 41.04 97.992 ;
    END
  END i[364]
  PIN i[365]
    DIRECTION INPUT ;
    USE SIGNAL ;
    PORT
      LAYER M4 ;
        RECT  40.956 98.064 41.04 98.088 ;
    END
  END i[365]
  PIN i[366]
    DIRECTION INPUT ;
    USE SIGNAL ;
    PORT
      LAYER M4 ;
        RECT  40.956 98.16 41.04 98.184 ;
    END
  END i[366]
  PIN i[367]
    DIRECTION INPUT ;
    USE SIGNAL ;
    PORT
      LAYER M4 ;
        RECT  40.956 98.256 41.04 98.28 ;
    END
  END i[367]
  PIN i[368]
    DIRECTION INPUT ;
    USE SIGNAL ;
    PORT
      LAYER M4 ;
        RECT  40.956 98.352 41.04 98.376 ;
    END
  END i[368]
  PIN i[369]
    DIRECTION INPUT ;
    USE SIGNAL ;
    PORT
      LAYER M4 ;
        RECT  40.956 98.448 41.04 98.472 ;
    END
  END i[369]
  PIN i[36]
    DIRECTION INPUT ;
    USE SIGNAL ;
    PORT
      LAYER M4 ;
        RECT  40.956 90.288 41.04 90.312 ;
    END
  END i[36]
  PIN i[370]
    DIRECTION INPUT ;
    USE SIGNAL ;
    PORT
      LAYER M4 ;
        RECT  40.956 98.544 41.04 98.568 ;
    END
  END i[370]
  PIN i[371]
    DIRECTION INPUT ;
    USE SIGNAL ;
    PORT
      LAYER M4 ;
        RECT  40.956 98.64 41.04 98.664 ;
    END
  END i[371]
  PIN i[372]
    DIRECTION INPUT ;
    USE SIGNAL ;
    PORT
      LAYER M4 ;
        RECT  40.956 98.736 41.04 98.76 ;
    END
  END i[372]
  PIN i[373]
    DIRECTION INPUT ;
    USE SIGNAL ;
    PORT
      LAYER M4 ;
        RECT  40.956 98.832 41.04 98.856 ;
    END
  END i[373]
  PIN i[374]
    DIRECTION INPUT ;
    USE SIGNAL ;
    PORT
      LAYER M4 ;
        RECT  40.956 98.928 41.04 98.952 ;
    END
  END i[374]
  PIN i[375]
    DIRECTION INPUT ;
    USE SIGNAL ;
    PORT
      LAYER M4 ;
        RECT  40.956 99.024 41.04 99.048 ;
    END
  END i[375]
  PIN i[376]
    DIRECTION INPUT ;
    USE SIGNAL ;
    PORT
      LAYER M4 ;
        RECT  40.956 99.12 41.04 99.144 ;
    END
  END i[376]
  PIN i[377]
    DIRECTION INPUT ;
    USE SIGNAL ;
    PORT
      LAYER M4 ;
        RECT  40.956 99.216 41.04 99.24 ;
    END
  END i[377]
  PIN i[378]
    DIRECTION INPUT ;
    USE SIGNAL ;
    PORT
      LAYER M4 ;
        RECT  40.956 99.312 41.04 99.336 ;
    END
  END i[378]
  PIN i[379]
    DIRECTION INPUT ;
    USE SIGNAL ;
    PORT
      LAYER M4 ;
        RECT  40.956 99.408 41.04 99.432 ;
    END
  END i[379]
  PIN i[37]
    DIRECTION INPUT ;
    USE SIGNAL ;
    PORT
      LAYER M4 ;
        RECT  40.956 90.384 41.04 90.408 ;
    END
  END i[37]
  PIN i[380]
    DIRECTION INPUT ;
    USE SIGNAL ;
    PORT
      LAYER M4 ;
        RECT  40.956 99.504 41.04 99.528 ;
    END
  END i[380]
  PIN i[381]
    DIRECTION INPUT ;
    USE SIGNAL ;
    PORT
      LAYER M4 ;
        RECT  40.956 99.6 41.04 99.624 ;
    END
  END i[381]
  PIN i[382]
    DIRECTION INPUT ;
    USE SIGNAL ;
    PORT
      LAYER M4 ;
        RECT  40.956 99.696 41.04 99.72 ;
    END
  END i[382]
  PIN i[383]
    DIRECTION INPUT ;
    USE SIGNAL ;
    PORT
      LAYER M4 ;
        RECT  40.956 105.936 41.04 105.96 ;
    END
  END i[383]
  PIN i[384]
    DIRECTION INPUT ;
    USE SIGNAL ;
    PORT
      LAYER M4 ;
        RECT  40.956 106.032 41.04 106.056 ;
    END
  END i[384]
  PIN i[385]
    DIRECTION INPUT ;
    USE SIGNAL ;
    PORT
      LAYER M4 ;
        RECT  40.956 106.128 41.04 106.152 ;
    END
  END i[385]
  PIN i[386]
    DIRECTION INPUT ;
    USE SIGNAL ;
    PORT
      LAYER M4 ;
        RECT  40.956 106.224 41.04 106.248 ;
    END
  END i[386]
  PIN i[387]
    DIRECTION INPUT ;
    USE SIGNAL ;
    PORT
      LAYER M4 ;
        RECT  40.956 106.32 41.04 106.344 ;
    END
  END i[387]
  PIN i[388]
    DIRECTION INPUT ;
    USE SIGNAL ;
    PORT
      LAYER M4 ;
        RECT  40.956 106.416 41.04 106.44 ;
    END
  END i[388]
  PIN i[389]
    DIRECTION INPUT ;
    USE SIGNAL ;
    PORT
      LAYER M4 ;
        RECT  40.956 106.512 41.04 106.536 ;
    END
  END i[389]
  PIN i[38]
    DIRECTION INPUT ;
    USE SIGNAL ;
    PORT
      LAYER M4 ;
        RECT  40.956 90.48 41.04 90.504 ;
    END
  END i[38]
  PIN i[390]
    DIRECTION INPUT ;
    USE SIGNAL ;
    PORT
      LAYER M4 ;
        RECT  40.956 106.608 41.04 106.632 ;
    END
  END i[390]
  PIN i[391]
    DIRECTION INPUT ;
    USE SIGNAL ;
    PORT
      LAYER M4 ;
        RECT  40.956 106.704 41.04 106.728 ;
    END
  END i[391]
  PIN i[392]
    DIRECTION INPUT ;
    USE SIGNAL ;
    PORT
      LAYER M4 ;
        RECT  40.956 106.8 41.04 106.824 ;
    END
  END i[392]
  PIN i[393]
    DIRECTION INPUT ;
    USE SIGNAL ;
    PORT
      LAYER M4 ;
        RECT  40.956 106.896 41.04 106.92 ;
    END
  END i[393]
  PIN i[394]
    DIRECTION INPUT ;
    USE SIGNAL ;
    PORT
      LAYER M4 ;
        RECT  40.956 106.992 41.04 107.016 ;
    END
  END i[394]
  PIN i[395]
    DIRECTION INPUT ;
    USE SIGNAL ;
    PORT
      LAYER M4 ;
        RECT  40.956 107.088 41.04 107.112 ;
    END
  END i[395]
  PIN i[396]
    DIRECTION INPUT ;
    USE SIGNAL ;
    PORT
      LAYER M4 ;
        RECT  40.956 107.184 41.04 107.208 ;
    END
  END i[396]
  PIN i[397]
    DIRECTION INPUT ;
    USE SIGNAL ;
    PORT
      LAYER M4 ;
        RECT  40.956 107.28 41.04 107.304 ;
    END
  END i[397]
  PIN i[398]
    DIRECTION INPUT ;
    USE SIGNAL ;
    PORT
      LAYER M4 ;
        RECT  40.956 107.376 41.04 107.4 ;
    END
  END i[398]
  PIN i[399]
    DIRECTION INPUT ;
    USE SIGNAL ;
    PORT
      LAYER M4 ;
        RECT  40.956 107.472 41.04 107.496 ;
    END
  END i[399]
  PIN i[39]
    DIRECTION INPUT ;
    USE SIGNAL ;
    PORT
      LAYER M4 ;
        RECT  40.956 90.576 41.04 90.6 ;
    END
  END i[39]
  PIN i[3]
    DIRECTION INPUT ;
    USE SIGNAL ;
    PORT
      LAYER M4 ;
        RECT  40.956 61.776 41.04 61.8 ;
    END
  END i[3]
  PIN i[400]
    DIRECTION INPUT ;
    USE SIGNAL ;
    PORT
      LAYER M4 ;
        RECT  40.956 107.568 41.04 107.592 ;
    END
  END i[400]
  PIN i[401]
    DIRECTION INPUT ;
    USE SIGNAL ;
    PORT
      LAYER M4 ;
        RECT  40.956 107.664 41.04 107.688 ;
    END
  END i[401]
  PIN i[402]
    DIRECTION INPUT ;
    USE SIGNAL ;
    PORT
      LAYER M4 ;
        RECT  40.956 107.76 41.04 107.784 ;
    END
  END i[402]
  PIN i[403]
    DIRECTION INPUT ;
    USE SIGNAL ;
    PORT
      LAYER M4 ;
        RECT  40.956 107.856 41.04 107.88 ;
    END
  END i[403]
  PIN i[404]
    DIRECTION INPUT ;
    USE SIGNAL ;
    PORT
      LAYER M4 ;
        RECT  40.956 107.952 41.04 107.976 ;
    END
  END i[404]
  PIN i[405]
    DIRECTION INPUT ;
    USE SIGNAL ;
    PORT
      LAYER M4 ;
        RECT  40.956 108.048 41.04 108.072 ;
    END
  END i[405]
  PIN i[406]
    DIRECTION INPUT ;
    USE SIGNAL ;
    PORT
      LAYER M4 ;
        RECT  40.956 108.144 41.04 108.168 ;
    END
  END i[406]
  PIN i[407]
    DIRECTION INPUT ;
    USE SIGNAL ;
    PORT
      LAYER M4 ;
        RECT  40.956 108.24 41.04 108.264 ;
    END
  END i[407]
  PIN i[408]
    DIRECTION INPUT ;
    USE SIGNAL ;
    PORT
      LAYER M4 ;
        RECT  40.956 108.336 41.04 108.36 ;
    END
  END i[408]
  PIN i[409]
    DIRECTION INPUT ;
    USE SIGNAL ;
    PORT
      LAYER M4 ;
        RECT  40.956 108.432 41.04 108.456 ;
    END
  END i[409]
  PIN i[40]
    DIRECTION INPUT ;
    USE SIGNAL ;
    PORT
      LAYER M4 ;
        RECT  40.956 90.672 41.04 90.696 ;
    END
  END i[40]
  PIN i[410]
    DIRECTION INPUT ;
    USE SIGNAL ;
    PORT
      LAYER M4 ;
        RECT  40.956 108.528 41.04 108.552 ;
    END
  END i[410]
  PIN i[411]
    DIRECTION INPUT ;
    USE SIGNAL ;
    PORT
      LAYER M4 ;
        RECT  40.956 108.624 41.04 108.648 ;
    END
  END i[411]
  PIN i[412]
    DIRECTION INPUT ;
    USE SIGNAL ;
    PORT
      LAYER M4 ;
        RECT  40.956 108.72 41.04 108.744 ;
    END
  END i[412]
  PIN i[413]
    DIRECTION INPUT ;
    USE SIGNAL ;
    PORT
      LAYER M4 ;
        RECT  40.956 108.816 41.04 108.84 ;
    END
  END i[413]
  PIN i[414]
    DIRECTION INPUT ;
    USE SIGNAL ;
    PORT
      LAYER M4 ;
        RECT  40.956 108.912 41.04 108.936 ;
    END
  END i[414]
  PIN i[415]
    DIRECTION INPUT ;
    USE SIGNAL ;
    PORT
      LAYER M4 ;
        RECT  40.956 99.792 41.04 99.816 ;
    END
  END i[415]
  PIN i[416]
    DIRECTION INPUT ;
    USE SIGNAL ;
    PORT
      LAYER M4 ;
        RECT  40.956 99.888 41.04 99.912 ;
    END
  END i[416]
  PIN i[417]
    DIRECTION INPUT ;
    USE SIGNAL ;
    PORT
      LAYER M4 ;
        RECT  40.956 99.984 41.04 100.008 ;
    END
  END i[417]
  PIN i[418]
    DIRECTION INPUT ;
    USE SIGNAL ;
    PORT
      LAYER M4 ;
        RECT  40.956 100.08 41.04 100.104 ;
    END
  END i[418]
  PIN i[419]
    DIRECTION INPUT ;
    USE SIGNAL ;
    PORT
      LAYER M4 ;
        RECT  40.956 100.176 41.04 100.2 ;
    END
  END i[419]
  PIN i[41]
    DIRECTION INPUT ;
    USE SIGNAL ;
    PORT
      LAYER M4 ;
        RECT  40.956 90.768 41.04 90.792 ;
    END
  END i[41]
  PIN i[420]
    DIRECTION INPUT ;
    USE SIGNAL ;
    PORT
      LAYER M4 ;
        RECT  40.956 100.272 41.04 100.296 ;
    END
  END i[420]
  PIN i[421]
    DIRECTION INPUT ;
    USE SIGNAL ;
    PORT
      LAYER M4 ;
        RECT  40.956 100.368 41.04 100.392 ;
    END
  END i[421]
  PIN i[422]
    DIRECTION INPUT ;
    USE SIGNAL ;
    PORT
      LAYER M4 ;
        RECT  40.956 100.464 41.04 100.488 ;
    END
  END i[422]
  PIN i[423]
    DIRECTION INPUT ;
    USE SIGNAL ;
    PORT
      LAYER M4 ;
        RECT  40.956 100.56 41.04 100.584 ;
    END
  END i[423]
  PIN i[424]
    DIRECTION INPUT ;
    USE SIGNAL ;
    PORT
      LAYER M4 ;
        RECT  40.956 100.656 41.04 100.68 ;
    END
  END i[424]
  PIN i[425]
    DIRECTION INPUT ;
    USE SIGNAL ;
    PORT
      LAYER M4 ;
        RECT  40.956 100.752 41.04 100.776 ;
    END
  END i[425]
  PIN i[426]
    DIRECTION INPUT ;
    USE SIGNAL ;
    PORT
      LAYER M4 ;
        RECT  40.956 100.848 41.04 100.872 ;
    END
  END i[426]
  PIN i[427]
    DIRECTION INPUT ;
    USE SIGNAL ;
    PORT
      LAYER M4 ;
        RECT  40.956 100.944 41.04 100.968 ;
    END
  END i[427]
  PIN i[428]
    DIRECTION INPUT ;
    USE SIGNAL ;
    PORT
      LAYER M4 ;
        RECT  40.956 101.04 41.04 101.064 ;
    END
  END i[428]
  PIN i[429]
    DIRECTION INPUT ;
    USE SIGNAL ;
    PORT
      LAYER M4 ;
        RECT  40.956 101.136 41.04 101.16 ;
    END
  END i[429]
  PIN i[42]
    DIRECTION INPUT ;
    USE SIGNAL ;
    PORT
      LAYER M4 ;
        RECT  40.956 90.864 41.04 90.888 ;
    END
  END i[42]
  PIN i[430]
    DIRECTION INPUT ;
    USE SIGNAL ;
    PORT
      LAYER M4 ;
        RECT  40.956 101.232 41.04 101.256 ;
    END
  END i[430]
  PIN i[431]
    DIRECTION INPUT ;
    USE SIGNAL ;
    PORT
      LAYER M4 ;
        RECT  40.956 101.328 41.04 101.352 ;
    END
  END i[431]
  PIN i[432]
    DIRECTION INPUT ;
    USE SIGNAL ;
    PORT
      LAYER M4 ;
        RECT  40.956 101.424 41.04 101.448 ;
    END
  END i[432]
  PIN i[433]
    DIRECTION INPUT ;
    USE SIGNAL ;
    PORT
      LAYER M4 ;
        RECT  40.956 101.52 41.04 101.544 ;
    END
  END i[433]
  PIN i[434]
    DIRECTION INPUT ;
    USE SIGNAL ;
    PORT
      LAYER M4 ;
        RECT  40.956 101.616 41.04 101.64 ;
    END
  END i[434]
  PIN i[435]
    DIRECTION INPUT ;
    USE SIGNAL ;
    PORT
      LAYER M4 ;
        RECT  40.956 101.712 41.04 101.736 ;
    END
  END i[435]
  PIN i[436]
    DIRECTION INPUT ;
    USE SIGNAL ;
    PORT
      LAYER M4 ;
        RECT  40.956 101.808 41.04 101.832 ;
    END
  END i[436]
  PIN i[437]
    DIRECTION INPUT ;
    USE SIGNAL ;
    PORT
      LAYER M4 ;
        RECT  40.956 101.904 41.04 101.928 ;
    END
  END i[437]
  PIN i[438]
    DIRECTION INPUT ;
    USE SIGNAL ;
    PORT
      LAYER M4 ;
        RECT  40.956 102 41.04 102.024 ;
    END
  END i[438]
  PIN i[439]
    DIRECTION INPUT ;
    USE SIGNAL ;
    PORT
      LAYER M4 ;
        RECT  40.956 102.096 41.04 102.12 ;
    END
  END i[439]
  PIN i[43]
    DIRECTION INPUT ;
    USE SIGNAL ;
    PORT
      LAYER M4 ;
        RECT  40.956 90.96 41.04 90.984 ;
    END
  END i[43]
  PIN i[440]
    DIRECTION INPUT ;
    USE SIGNAL ;
    PORT
      LAYER M4 ;
        RECT  40.956 102.192 41.04 102.216 ;
    END
  END i[440]
  PIN i[441]
    DIRECTION INPUT ;
    USE SIGNAL ;
    PORT
      LAYER M4 ;
        RECT  40.956 102.288 41.04 102.312 ;
    END
  END i[441]
  PIN i[442]
    DIRECTION INPUT ;
    USE SIGNAL ;
    PORT
      LAYER M4 ;
        RECT  40.956 102.384 41.04 102.408 ;
    END
  END i[442]
  PIN i[443]
    DIRECTION INPUT ;
    USE SIGNAL ;
    PORT
      LAYER M4 ;
        RECT  40.956 102.48 41.04 102.504 ;
    END
  END i[443]
  PIN i[444]
    DIRECTION INPUT ;
    USE SIGNAL ;
    PORT
      LAYER M4 ;
        RECT  40.956 102.576 41.04 102.6 ;
    END
  END i[444]
  PIN i[445]
    DIRECTION INPUT ;
    USE SIGNAL ;
    PORT
      LAYER M4 ;
        RECT  40.956 102.672 41.04 102.696 ;
    END
  END i[445]
  PIN i[446]
    DIRECTION INPUT ;
    USE SIGNAL ;
    PORT
      LAYER M4 ;
        RECT  40.956 102.768 41.04 102.792 ;
    END
  END i[446]
  PIN i[447]
    DIRECTION INPUT ;
    USE SIGNAL ;
    PORT
      LAYER M4 ;
        RECT  40.956 86.736 41.04 86.76 ;
    END
  END i[447]
  PIN i[448]
    DIRECTION INPUT ;
    USE SIGNAL ;
    PORT
      LAYER M4 ;
        RECT  40.956 86.832 41.04 86.856 ;
    END
  END i[448]
  PIN i[449]
    DIRECTION INPUT ;
    USE SIGNAL ;
    PORT
      LAYER M4 ;
        RECT  40.956 86.928 41.04 86.952 ;
    END
  END i[449]
  PIN i[44]
    DIRECTION INPUT ;
    USE SIGNAL ;
    PORT
      LAYER M4 ;
        RECT  40.956 91.056 41.04 91.08 ;
    END
  END i[44]
  PIN i[450]
    DIRECTION INPUT ;
    USE SIGNAL ;
    PORT
      LAYER M4 ;
        RECT  40.956 87.024 41.04 87.048 ;
    END
  END i[450]
  PIN i[451]
    DIRECTION INPUT ;
    USE SIGNAL ;
    PORT
      LAYER M4 ;
        RECT  40.956 87.12 41.04 87.144 ;
    END
  END i[451]
  PIN i[452]
    DIRECTION INPUT ;
    USE SIGNAL ;
    PORT
      LAYER M4 ;
        RECT  40.956 87.216 41.04 87.24 ;
    END
  END i[452]
  PIN i[453]
    DIRECTION INPUT ;
    USE SIGNAL ;
    PORT
      LAYER M4 ;
        RECT  40.956 87.312 41.04 87.336 ;
    END
  END i[453]
  PIN i[454]
    DIRECTION INPUT ;
    USE SIGNAL ;
    PORT
      LAYER M4 ;
        RECT  40.956 87.408 41.04 87.432 ;
    END
  END i[454]
  PIN i[455]
    DIRECTION INPUT ;
    USE SIGNAL ;
    PORT
      LAYER M4 ;
        RECT  40.956 87.504 41.04 87.528 ;
    END
  END i[455]
  PIN i[456]
    DIRECTION INPUT ;
    USE SIGNAL ;
    PORT
      LAYER M4 ;
        RECT  40.956 87.6 41.04 87.624 ;
    END
  END i[456]
  PIN i[457]
    DIRECTION INPUT ;
    USE SIGNAL ;
    PORT
      LAYER M4 ;
        RECT  40.956 87.696 41.04 87.72 ;
    END
  END i[457]
  PIN i[458]
    DIRECTION INPUT ;
    USE SIGNAL ;
    PORT
      LAYER M4 ;
        RECT  40.956 87.792 41.04 87.816 ;
    END
  END i[458]
  PIN i[459]
    DIRECTION INPUT ;
    USE SIGNAL ;
    PORT
      LAYER M4 ;
        RECT  40.956 87.888 41.04 87.912 ;
    END
  END i[459]
  PIN i[45]
    DIRECTION INPUT ;
    USE SIGNAL ;
    PORT
      LAYER M4 ;
        RECT  40.956 91.152 41.04 91.176 ;
    END
  END i[45]
  PIN i[460]
    DIRECTION INPUT ;
    USE SIGNAL ;
    PORT
      LAYER M4 ;
        RECT  40.956 87.984 41.04 88.008 ;
    END
  END i[460]
  PIN i[461]
    DIRECTION INPUT ;
    USE SIGNAL ;
    PORT
      LAYER M4 ;
        RECT  40.956 88.08 41.04 88.104 ;
    END
  END i[461]
  PIN i[462]
    DIRECTION INPUT ;
    USE SIGNAL ;
    PORT
      LAYER M4 ;
        RECT  40.956 88.176 41.04 88.2 ;
    END
  END i[462]
  PIN i[463]
    DIRECTION INPUT ;
    USE SIGNAL ;
    PORT
      LAYER M4 ;
        RECT  40.956 88.272 41.04 88.296 ;
    END
  END i[463]
  PIN i[464]
    DIRECTION INPUT ;
    USE SIGNAL ;
    PORT
      LAYER M4 ;
        RECT  40.956 88.368 41.04 88.392 ;
    END
  END i[464]
  PIN i[465]
    DIRECTION INPUT ;
    USE SIGNAL ;
    PORT
      LAYER M4 ;
        RECT  40.956 88.464 41.04 88.488 ;
    END
  END i[465]
  PIN i[466]
    DIRECTION INPUT ;
    USE SIGNAL ;
    PORT
      LAYER M4 ;
        RECT  40.956 88.56 41.04 88.584 ;
    END
  END i[466]
  PIN i[467]
    DIRECTION INPUT ;
    USE SIGNAL ;
    PORT
      LAYER M4 ;
        RECT  40.956 88.656 41.04 88.68 ;
    END
  END i[467]
  PIN i[468]
    DIRECTION INPUT ;
    USE SIGNAL ;
    PORT
      LAYER M4 ;
        RECT  40.956 88.752 41.04 88.776 ;
    END
  END i[468]
  PIN i[469]
    DIRECTION INPUT ;
    USE SIGNAL ;
    PORT
      LAYER M4 ;
        RECT  40.956 88.848 41.04 88.872 ;
    END
  END i[469]
  PIN i[46]
    DIRECTION INPUT ;
    USE SIGNAL ;
    PORT
      LAYER M4 ;
        RECT  40.956 91.248 41.04 91.272 ;
    END
  END i[46]
  PIN i[470]
    DIRECTION INPUT ;
    USE SIGNAL ;
    PORT
      LAYER M4 ;
        RECT  40.956 88.944 41.04 88.968 ;
    END
  END i[470]
  PIN i[471]
    DIRECTION INPUT ;
    USE SIGNAL ;
    PORT
      LAYER M4 ;
        RECT  40.956 89.04 41.04 89.064 ;
    END
  END i[471]
  PIN i[472]
    DIRECTION INPUT ;
    USE SIGNAL ;
    PORT
      LAYER M4 ;
        RECT  40.956 89.136 41.04 89.16 ;
    END
  END i[472]
  PIN i[473]
    DIRECTION INPUT ;
    USE SIGNAL ;
    PORT
      LAYER M4 ;
        RECT  40.956 89.232 41.04 89.256 ;
    END
  END i[473]
  PIN i[474]
    DIRECTION INPUT ;
    USE SIGNAL ;
    PORT
      LAYER M4 ;
        RECT  40.956 89.328 41.04 89.352 ;
    END
  END i[474]
  PIN i[475]
    DIRECTION INPUT ;
    USE SIGNAL ;
    PORT
      LAYER M4 ;
        RECT  40.956 89.424 41.04 89.448 ;
    END
  END i[475]
  PIN i[476]
    DIRECTION INPUT ;
    USE SIGNAL ;
    PORT
      LAYER M4 ;
        RECT  40.956 89.52 41.04 89.544 ;
    END
  END i[476]
  PIN i[477]
    DIRECTION INPUT ;
    USE SIGNAL ;
    PORT
      LAYER M4 ;
        RECT  40.956 89.616 41.04 89.64 ;
    END
  END i[477]
  PIN i[478]
    DIRECTION INPUT ;
    USE SIGNAL ;
    PORT
      LAYER M4 ;
        RECT  40.956 89.712 41.04 89.736 ;
    END
  END i[478]
  PIN i[479]
    DIRECTION INPUT ;
    USE SIGNAL ;
    PORT
      LAYER M4 ;
        RECT  40.956 73.68 41.04 73.704 ;
    END
  END i[479]
  PIN i[47]
    DIRECTION INPUT ;
    USE SIGNAL ;
    PORT
      LAYER M4 ;
        RECT  40.956 91.344 41.04 91.368 ;
    END
  END i[47]
  PIN i[480]
    DIRECTION INPUT ;
    USE SIGNAL ;
    PORT
      LAYER M4 ;
        RECT  40.956 73.776 41.04 73.8 ;
    END
  END i[480]
  PIN i[481]
    DIRECTION INPUT ;
    USE SIGNAL ;
    PORT
      LAYER M4 ;
        RECT  40.956 73.872 41.04 73.896 ;
    END
  END i[481]
  PIN i[482]
    DIRECTION INPUT ;
    USE SIGNAL ;
    PORT
      LAYER M4 ;
        RECT  40.956 73.968 41.04 73.992 ;
    END
  END i[482]
  PIN i[483]
    DIRECTION INPUT ;
    USE SIGNAL ;
    PORT
      LAYER M4 ;
        RECT  40.956 74.064 41.04 74.088 ;
    END
  END i[483]
  PIN i[484]
    DIRECTION INPUT ;
    USE SIGNAL ;
    PORT
      LAYER M4 ;
        RECT  40.956 74.16 41.04 74.184 ;
    END
  END i[484]
  PIN i[485]
    DIRECTION INPUT ;
    USE SIGNAL ;
    PORT
      LAYER M4 ;
        RECT  40.956 74.256 41.04 74.28 ;
    END
  END i[485]
  PIN i[486]
    DIRECTION INPUT ;
    USE SIGNAL ;
    PORT
      LAYER M4 ;
        RECT  40.956 74.352 41.04 74.376 ;
    END
  END i[486]
  PIN i[487]
    DIRECTION INPUT ;
    USE SIGNAL ;
    PORT
      LAYER M4 ;
        RECT  40.956 74.448 41.04 74.472 ;
    END
  END i[487]
  PIN i[488]
    DIRECTION INPUT ;
    USE SIGNAL ;
    PORT
      LAYER M4 ;
        RECT  40.956 74.544 41.04 74.568 ;
    END
  END i[488]
  PIN i[489]
    DIRECTION INPUT ;
    USE SIGNAL ;
    PORT
      LAYER M4 ;
        RECT  40.956 74.64 41.04 74.664 ;
    END
  END i[489]
  PIN i[48]
    DIRECTION INPUT ;
    USE SIGNAL ;
    PORT
      LAYER M4 ;
        RECT  40.956 91.44 41.04 91.464 ;
    END
  END i[48]
  PIN i[490]
    DIRECTION INPUT ;
    USE SIGNAL ;
    PORT
      LAYER M4 ;
        RECT  40.956 74.736 41.04 74.76 ;
    END
  END i[490]
  PIN i[491]
    DIRECTION INPUT ;
    USE SIGNAL ;
    PORT
      LAYER M4 ;
        RECT  40.956 74.832 41.04 74.856 ;
    END
  END i[491]
  PIN i[492]
    DIRECTION INPUT ;
    USE SIGNAL ;
    PORT
      LAYER M4 ;
        RECT  40.956 74.928 41.04 74.952 ;
    END
  END i[492]
  PIN i[493]
    DIRECTION INPUT ;
    USE SIGNAL ;
    PORT
      LAYER M4 ;
        RECT  40.956 75.024 41.04 75.048 ;
    END
  END i[493]
  PIN i[494]
    DIRECTION INPUT ;
    USE SIGNAL ;
    PORT
      LAYER M4 ;
        RECT  40.956 75.12 41.04 75.144 ;
    END
  END i[494]
  PIN i[495]
    DIRECTION INPUT ;
    USE SIGNAL ;
    PORT
      LAYER M4 ;
        RECT  40.956 75.216 41.04 75.24 ;
    END
  END i[495]
  PIN i[496]
    DIRECTION INPUT ;
    USE SIGNAL ;
    PORT
      LAYER M4 ;
        RECT  40.956 75.312 41.04 75.336 ;
    END
  END i[496]
  PIN i[497]
    DIRECTION INPUT ;
    USE SIGNAL ;
    PORT
      LAYER M4 ;
        RECT  40.956 75.408 41.04 75.432 ;
    END
  END i[497]
  PIN i[498]
    DIRECTION INPUT ;
    USE SIGNAL ;
    PORT
      LAYER M4 ;
        RECT  40.956 75.504 41.04 75.528 ;
    END
  END i[498]
  PIN i[499]
    DIRECTION INPUT ;
    USE SIGNAL ;
    PORT
      LAYER M4 ;
        RECT  40.956 75.6 41.04 75.624 ;
    END
  END i[499]
  PIN i[49]
    DIRECTION INPUT ;
    USE SIGNAL ;
    PORT
      LAYER M4 ;
        RECT  40.956 91.536 41.04 91.56 ;
    END
  END i[49]
  PIN i[4]
    DIRECTION INPUT ;
    USE SIGNAL ;
    PORT
      LAYER M4 ;
        RECT  40.956 61.872 41.04 61.896 ;
    END
  END i[4]
  PIN i[500]
    DIRECTION INPUT ;
    USE SIGNAL ;
    PORT
      LAYER M4 ;
        RECT  40.956 75.696 41.04 75.72 ;
    END
  END i[500]
  PIN i[501]
    DIRECTION INPUT ;
    USE SIGNAL ;
    PORT
      LAYER M4 ;
        RECT  40.956 75.792 41.04 75.816 ;
    END
  END i[501]
  PIN i[502]
    DIRECTION INPUT ;
    USE SIGNAL ;
    PORT
      LAYER M4 ;
        RECT  40.956 75.888 41.04 75.912 ;
    END
  END i[502]
  PIN i[503]
    DIRECTION INPUT ;
    USE SIGNAL ;
    PORT
      LAYER M4 ;
        RECT  40.956 75.984 41.04 76.008 ;
    END
  END i[503]
  PIN i[504]
    DIRECTION INPUT ;
    USE SIGNAL ;
    PORT
      LAYER M4 ;
        RECT  40.956 76.08 41.04 76.104 ;
    END
  END i[504]
  PIN i[505]
    DIRECTION INPUT ;
    USE SIGNAL ;
    PORT
      LAYER M4 ;
        RECT  40.956 76.176 41.04 76.2 ;
    END
  END i[505]
  PIN i[506]
    DIRECTION INPUT ;
    USE SIGNAL ;
    PORT
      LAYER M4 ;
        RECT  40.956 76.272 41.04 76.296 ;
    END
  END i[506]
  PIN i[507]
    DIRECTION INPUT ;
    USE SIGNAL ;
    PORT
      LAYER M4 ;
        RECT  40.956 76.368 41.04 76.392 ;
    END
  END i[507]
  PIN i[508]
    DIRECTION INPUT ;
    USE SIGNAL ;
    PORT
      LAYER M4 ;
        RECT  40.956 76.464 41.04 76.488 ;
    END
  END i[508]
  PIN i[509]
    DIRECTION INPUT ;
    USE SIGNAL ;
    PORT
      LAYER M4 ;
        RECT  40.956 76.56 41.04 76.584 ;
    END
  END i[509]
  PIN i[50]
    DIRECTION INPUT ;
    USE SIGNAL ;
    PORT
      LAYER M4 ;
        RECT  40.956 91.632 41.04 91.656 ;
    END
  END i[50]
  PIN i[510]
    DIRECTION INPUT ;
    USE SIGNAL ;
    PORT
      LAYER M4 ;
        RECT  40.956 76.656 41.04 76.68 ;
    END
  END i[510]
  PIN i[511]
    DIRECTION INPUT ;
    USE SIGNAL ;
    PORT
      LAYER M4 ;
        RECT  40.956 58.32 41.04 58.344 ;
    END
  END i[511]
  PIN i[512]
    DIRECTION INPUT ;
    USE SIGNAL ;
    PORT
      LAYER M4 ;
        RECT  40.956 58.416 41.04 58.44 ;
    END
  END i[512]
  PIN i[513]
    DIRECTION INPUT ;
    USE SIGNAL ;
    PORT
      LAYER M4 ;
        RECT  40.956 58.512 41.04 58.536 ;
    END
  END i[513]
  PIN i[514]
    DIRECTION INPUT ;
    USE SIGNAL ;
    PORT
      LAYER M4 ;
        RECT  40.956 58.608 41.04 58.632 ;
    END
  END i[514]
  PIN i[515]
    DIRECTION INPUT ;
    USE SIGNAL ;
    PORT
      LAYER M4 ;
        RECT  40.956 58.704 41.04 58.728 ;
    END
  END i[515]
  PIN i[516]
    DIRECTION INPUT ;
    USE SIGNAL ;
    PORT
      LAYER M4 ;
        RECT  40.956 58.8 41.04 58.824 ;
    END
  END i[516]
  PIN i[517]
    DIRECTION INPUT ;
    USE SIGNAL ;
    PORT
      LAYER M4 ;
        RECT  40.956 58.896 41.04 58.92 ;
    END
  END i[517]
  PIN i[518]
    DIRECTION INPUT ;
    USE SIGNAL ;
    PORT
      LAYER M4 ;
        RECT  40.956 58.992 41.04 59.016 ;
    END
  END i[518]
  PIN i[519]
    DIRECTION INPUT ;
    USE SIGNAL ;
    PORT
      LAYER M4 ;
        RECT  40.956 59.088 41.04 59.112 ;
    END
  END i[519]
  PIN i[51]
    DIRECTION INPUT ;
    USE SIGNAL ;
    PORT
      LAYER M4 ;
        RECT  40.956 91.728 41.04 91.752 ;
    END
  END i[51]
  PIN i[520]
    DIRECTION INPUT ;
    USE SIGNAL ;
    PORT
      LAYER M4 ;
        RECT  40.956 59.184 41.04 59.208 ;
    END
  END i[520]
  PIN i[521]
    DIRECTION INPUT ;
    USE SIGNAL ;
    PORT
      LAYER M4 ;
        RECT  40.956 59.28 41.04 59.304 ;
    END
  END i[521]
  PIN i[522]
    DIRECTION INPUT ;
    USE SIGNAL ;
    PORT
      LAYER M4 ;
        RECT  40.956 59.376 41.04 59.4 ;
    END
  END i[522]
  PIN i[523]
    DIRECTION INPUT ;
    USE SIGNAL ;
    PORT
      LAYER M4 ;
        RECT  40.956 59.472 41.04 59.496 ;
    END
  END i[523]
  PIN i[524]
    DIRECTION INPUT ;
    USE SIGNAL ;
    PORT
      LAYER M4 ;
        RECT  40.956 59.568 41.04 59.592 ;
    END
  END i[524]
  PIN i[525]
    DIRECTION INPUT ;
    USE SIGNAL ;
    PORT
      LAYER M4 ;
        RECT  40.956 59.664 41.04 59.688 ;
    END
  END i[525]
  PIN i[526]
    DIRECTION INPUT ;
    USE SIGNAL ;
    PORT
      LAYER M4 ;
        RECT  40.956 59.76 41.04 59.784 ;
    END
  END i[526]
  PIN i[527]
    DIRECTION INPUT ;
    USE SIGNAL ;
    PORT
      LAYER M4 ;
        RECT  40.956 59.856 41.04 59.88 ;
    END
  END i[527]
  PIN i[528]
    DIRECTION INPUT ;
    USE SIGNAL ;
    PORT
      LAYER M4 ;
        RECT  40.956 59.952 41.04 59.976 ;
    END
  END i[528]
  PIN i[529]
    DIRECTION INPUT ;
    USE SIGNAL ;
    PORT
      LAYER M4 ;
        RECT  40.956 60.048 41.04 60.072 ;
    END
  END i[529]
  PIN i[52]
    DIRECTION INPUT ;
    USE SIGNAL ;
    PORT
      LAYER M4 ;
        RECT  40.956 91.824 41.04 91.848 ;
    END
  END i[52]
  PIN i[530]
    DIRECTION INPUT ;
    USE SIGNAL ;
    PORT
      LAYER M4 ;
        RECT  40.956 60.144 41.04 60.168 ;
    END
  END i[530]
  PIN i[531]
    DIRECTION INPUT ;
    USE SIGNAL ;
    PORT
      LAYER M4 ;
        RECT  40.956 60.24 41.04 60.264 ;
    END
  END i[531]
  PIN i[532]
    DIRECTION INPUT ;
    USE SIGNAL ;
    PORT
      LAYER M4 ;
        RECT  40.956 60.336 41.04 60.36 ;
    END
  END i[532]
  PIN i[533]
    DIRECTION INPUT ;
    USE SIGNAL ;
    PORT
      LAYER M4 ;
        RECT  40.956 60.432 41.04 60.456 ;
    END
  END i[533]
  PIN i[534]
    DIRECTION INPUT ;
    USE SIGNAL ;
    PORT
      LAYER M4 ;
        RECT  40.956 60.528 41.04 60.552 ;
    END
  END i[534]
  PIN i[535]
    DIRECTION INPUT ;
    USE SIGNAL ;
    PORT
      LAYER M4 ;
        RECT  40.956 60.624 41.04 60.648 ;
    END
  END i[535]
  PIN i[536]
    DIRECTION INPUT ;
    USE SIGNAL ;
    PORT
      LAYER M4 ;
        RECT  40.956 60.72 41.04 60.744 ;
    END
  END i[536]
  PIN i[537]
    DIRECTION INPUT ;
    USE SIGNAL ;
    PORT
      LAYER M4 ;
        RECT  40.956 60.816 41.04 60.84 ;
    END
  END i[537]
  PIN i[538]
    DIRECTION INPUT ;
    USE SIGNAL ;
    PORT
      LAYER M4 ;
        RECT  40.956 60.912 41.04 60.936 ;
    END
  END i[538]
  PIN i[539]
    DIRECTION INPUT ;
    USE SIGNAL ;
    PORT
      LAYER M4 ;
        RECT  40.956 61.008 41.04 61.032 ;
    END
  END i[539]
  PIN i[53]
    DIRECTION INPUT ;
    USE SIGNAL ;
    PORT
      LAYER M4 ;
        RECT  40.956 91.92 41.04 91.944 ;
    END
  END i[53]
  PIN i[540]
    DIRECTION INPUT ;
    USE SIGNAL ;
    PORT
      LAYER M4 ;
        RECT  40.956 61.104 41.04 61.128 ;
    END
  END i[540]
  PIN i[541]
    DIRECTION INPUT ;
    USE SIGNAL ;
    PORT
      LAYER M4 ;
        RECT  40.956 61.2 41.04 61.224 ;
    END
  END i[541]
  PIN i[542]
    DIRECTION INPUT ;
    USE SIGNAL ;
    PORT
      LAYER M4 ;
        RECT  40.956 61.296 41.04 61.32 ;
    END
  END i[542]
  PIN i[543]
    DIRECTION INPUT ;
    USE SIGNAL ;
    PORT
      LAYER M4 ;
        RECT  40.956 42.192 41.04 42.216 ;
    END
  END i[543]
  PIN i[544]
    DIRECTION INPUT ;
    USE SIGNAL ;
    PORT
      LAYER M4 ;
        RECT  40.956 42.288 41.04 42.312 ;
    END
  END i[544]
  PIN i[545]
    DIRECTION INPUT ;
    USE SIGNAL ;
    PORT
      LAYER M4 ;
        RECT  40.956 42.384 41.04 42.408 ;
    END
  END i[545]
  PIN i[546]
    DIRECTION INPUT ;
    USE SIGNAL ;
    PORT
      LAYER M4 ;
        RECT  40.956 42.48 41.04 42.504 ;
    END
  END i[546]
  PIN i[547]
    DIRECTION INPUT ;
    USE SIGNAL ;
    PORT
      LAYER M4 ;
        RECT  40.956 42.576 41.04 42.6 ;
    END
  END i[547]
  PIN i[548]
    DIRECTION INPUT ;
    USE SIGNAL ;
    PORT
      LAYER M4 ;
        RECT  40.956 42.672 41.04 42.696 ;
    END
  END i[548]
  PIN i[549]
    DIRECTION INPUT ;
    USE SIGNAL ;
    PORT
      LAYER M4 ;
        RECT  40.956 42.768 41.04 42.792 ;
    END
  END i[549]
  PIN i[54]
    DIRECTION INPUT ;
    USE SIGNAL ;
    PORT
      LAYER M4 ;
        RECT  40.956 92.016 41.04 92.04 ;
    END
  END i[54]
  PIN i[550]
    DIRECTION INPUT ;
    USE SIGNAL ;
    PORT
      LAYER M4 ;
        RECT  40.956 42.864 41.04 42.888 ;
    END
  END i[550]
  PIN i[551]
    DIRECTION INPUT ;
    USE SIGNAL ;
    PORT
      LAYER M4 ;
        RECT  40.956 42.96 41.04 42.984 ;
    END
  END i[551]
  PIN i[552]
    DIRECTION INPUT ;
    USE SIGNAL ;
    PORT
      LAYER M4 ;
        RECT  40.956 43.056 41.04 43.08 ;
    END
  END i[552]
  PIN i[553]
    DIRECTION INPUT ;
    USE SIGNAL ;
    PORT
      LAYER M4 ;
        RECT  40.956 43.152 41.04 43.176 ;
    END
  END i[553]
  PIN i[554]
    DIRECTION INPUT ;
    USE SIGNAL ;
    PORT
      LAYER M4 ;
        RECT  40.956 43.248 41.04 43.272 ;
    END
  END i[554]
  PIN i[555]
    DIRECTION INPUT ;
    USE SIGNAL ;
    PORT
      LAYER M4 ;
        RECT  40.956 43.344 41.04 43.368 ;
    END
  END i[555]
  PIN i[556]
    DIRECTION INPUT ;
    USE SIGNAL ;
    PORT
      LAYER M4 ;
        RECT  40.956 43.44 41.04 43.464 ;
    END
  END i[556]
  PIN i[557]
    DIRECTION INPUT ;
    USE SIGNAL ;
    PORT
      LAYER M4 ;
        RECT  40.956 43.536 41.04 43.56 ;
    END
  END i[557]
  PIN i[558]
    DIRECTION INPUT ;
    USE SIGNAL ;
    PORT
      LAYER M4 ;
        RECT  40.956 43.632 41.04 43.656 ;
    END
  END i[558]
  PIN i[559]
    DIRECTION INPUT ;
    USE SIGNAL ;
    PORT
      LAYER M4 ;
        RECT  40.956 43.728 41.04 43.752 ;
    END
  END i[559]
  PIN i[55]
    DIRECTION INPUT ;
    USE SIGNAL ;
    PORT
      LAYER M4 ;
        RECT  40.956 92.112 41.04 92.136 ;
    END
  END i[55]
  PIN i[560]
    DIRECTION INPUT ;
    USE SIGNAL ;
    PORT
      LAYER M4 ;
        RECT  40.956 43.824 41.04 43.848 ;
    END
  END i[560]
  PIN i[561]
    DIRECTION INPUT ;
    USE SIGNAL ;
    PORT
      LAYER M4 ;
        RECT  40.956 43.92 41.04 43.944 ;
    END
  END i[561]
  PIN i[562]
    DIRECTION INPUT ;
    USE SIGNAL ;
    PORT
      LAYER M4 ;
        RECT  40.956 44.016 41.04 44.04 ;
    END
  END i[562]
  PIN i[563]
    DIRECTION INPUT ;
    USE SIGNAL ;
    PORT
      LAYER M4 ;
        RECT  40.956 44.112 41.04 44.136 ;
    END
  END i[563]
  PIN i[564]
    DIRECTION INPUT ;
    USE SIGNAL ;
    PORT
      LAYER M4 ;
        RECT  40.956 44.208 41.04 44.232 ;
    END
  END i[564]
  PIN i[565]
    DIRECTION INPUT ;
    USE SIGNAL ;
    PORT
      LAYER M4 ;
        RECT  40.956 44.304 41.04 44.328 ;
    END
  END i[565]
  PIN i[566]
    DIRECTION INPUT ;
    USE SIGNAL ;
    PORT
      LAYER M4 ;
        RECT  40.956 44.4 41.04 44.424 ;
    END
  END i[566]
  PIN i[567]
    DIRECTION INPUT ;
    USE SIGNAL ;
    PORT
      LAYER M4 ;
        RECT  40.956 44.496 41.04 44.52 ;
    END
  END i[567]
  PIN i[568]
    DIRECTION INPUT ;
    USE SIGNAL ;
    PORT
      LAYER M4 ;
        RECT  40.956 44.592 41.04 44.616 ;
    END
  END i[568]
  PIN i[569]
    DIRECTION INPUT ;
    USE SIGNAL ;
    PORT
      LAYER M4 ;
        RECT  40.956 44.688 41.04 44.712 ;
    END
  END i[569]
  PIN i[56]
    DIRECTION INPUT ;
    USE SIGNAL ;
    PORT
      LAYER M4 ;
        RECT  40.956 92.208 41.04 92.232 ;
    END
  END i[56]
  PIN i[570]
    DIRECTION INPUT ;
    USE SIGNAL ;
    PORT
      LAYER M4 ;
        RECT  40.956 44.784 41.04 44.808 ;
    END
  END i[570]
  PIN i[571]
    DIRECTION INPUT ;
    USE SIGNAL ;
    PORT
      LAYER M4 ;
        RECT  40.956 44.88 41.04 44.904 ;
    END
  END i[571]
  PIN i[572]
    DIRECTION INPUT ;
    USE SIGNAL ;
    PORT
      LAYER M4 ;
        RECT  40.956 44.976 41.04 45 ;
    END
  END i[572]
  PIN i[573]
    DIRECTION INPUT ;
    USE SIGNAL ;
    PORT
      LAYER M4 ;
        RECT  40.956 45.072 41.04 45.096 ;
    END
  END i[573]
  PIN i[574]
    DIRECTION INPUT ;
    USE SIGNAL ;
    PORT
      LAYER M4 ;
        RECT  40.956 45.168 41.04 45.192 ;
    END
  END i[574]
  PIN i[575]
    DIRECTION INPUT ;
    USE SIGNAL ;
    PORT
      LAYER M4 ;
        RECT  40.956 19.92 41.04 19.944 ;
    END
  END i[575]
  PIN i[576]
    DIRECTION INPUT ;
    USE SIGNAL ;
    PORT
      LAYER M4 ;
        RECT  40.956 20.016 41.04 20.04 ;
    END
  END i[576]
  PIN i[577]
    DIRECTION INPUT ;
    USE SIGNAL ;
    PORT
      LAYER M4 ;
        RECT  40.956 20.112 41.04 20.136 ;
    END
  END i[577]
  PIN i[578]
    DIRECTION INPUT ;
    USE SIGNAL ;
    PORT
      LAYER M4 ;
        RECT  40.956 20.208 41.04 20.232 ;
    END
  END i[578]
  PIN i[579]
    DIRECTION INPUT ;
    USE SIGNAL ;
    PORT
      LAYER M4 ;
        RECT  40.956 20.304 41.04 20.328 ;
    END
  END i[579]
  PIN i[57]
    DIRECTION INPUT ;
    USE SIGNAL ;
    PORT
      LAYER M4 ;
        RECT  40.956 92.304 41.04 92.328 ;
    END
  END i[57]
  PIN i[580]
    DIRECTION INPUT ;
    USE SIGNAL ;
    PORT
      LAYER M4 ;
        RECT  40.956 20.4 41.04 20.424 ;
    END
  END i[580]
  PIN i[581]
    DIRECTION INPUT ;
    USE SIGNAL ;
    PORT
      LAYER M4 ;
        RECT  40.956 20.496 41.04 20.52 ;
    END
  END i[581]
  PIN i[582]
    DIRECTION INPUT ;
    USE SIGNAL ;
    PORT
      LAYER M4 ;
        RECT  40.956 20.592 41.04 20.616 ;
    END
  END i[582]
  PIN i[583]
    DIRECTION INPUT ;
    USE SIGNAL ;
    PORT
      LAYER M4 ;
        RECT  40.956 20.688 41.04 20.712 ;
    END
  END i[583]
  PIN i[584]
    DIRECTION INPUT ;
    USE SIGNAL ;
    PORT
      LAYER M4 ;
        RECT  40.956 20.784 41.04 20.808 ;
    END
  END i[584]
  PIN i[585]
    DIRECTION INPUT ;
    USE SIGNAL ;
    PORT
      LAYER M4 ;
        RECT  40.956 20.88 41.04 20.904 ;
    END
  END i[585]
  PIN i[586]
    DIRECTION INPUT ;
    USE SIGNAL ;
    PORT
      LAYER M4 ;
        RECT  40.956 20.976 41.04 21 ;
    END
  END i[586]
  PIN i[587]
    DIRECTION INPUT ;
    USE SIGNAL ;
    PORT
      LAYER M4 ;
        RECT  40.956 21.072 41.04 21.096 ;
    END
  END i[587]
  PIN i[588]
    DIRECTION INPUT ;
    USE SIGNAL ;
    PORT
      LAYER M4 ;
        RECT  40.956 21.168 41.04 21.192 ;
    END
  END i[588]
  PIN i[589]
    DIRECTION INPUT ;
    USE SIGNAL ;
    PORT
      LAYER M4 ;
        RECT  40.956 21.264 41.04 21.288 ;
    END
  END i[589]
  PIN i[58]
    DIRECTION INPUT ;
    USE SIGNAL ;
    PORT
      LAYER M4 ;
        RECT  40.956 92.4 41.04 92.424 ;
    END
  END i[58]
  PIN i[590]
    DIRECTION INPUT ;
    USE SIGNAL ;
    PORT
      LAYER M4 ;
        RECT  40.956 21.36 41.04 21.384 ;
    END
  END i[590]
  PIN i[591]
    DIRECTION INPUT ;
    USE SIGNAL ;
    PORT
      LAYER M4 ;
        RECT  40.956 21.456 41.04 21.48 ;
    END
  END i[591]
  PIN i[592]
    DIRECTION INPUT ;
    USE SIGNAL ;
    PORT
      LAYER M4 ;
        RECT  40.956 21.552 41.04 21.576 ;
    END
  END i[592]
  PIN i[593]
    DIRECTION INPUT ;
    USE SIGNAL ;
    PORT
      LAYER M4 ;
        RECT  40.956 21.648 41.04 21.672 ;
    END
  END i[593]
  PIN i[594]
    DIRECTION INPUT ;
    USE SIGNAL ;
    PORT
      LAYER M4 ;
        RECT  40.956 21.744 41.04 21.768 ;
    END
  END i[594]
  PIN i[595]
    DIRECTION INPUT ;
    USE SIGNAL ;
    PORT
      LAYER M4 ;
        RECT  40.956 21.84 41.04 21.864 ;
    END
  END i[595]
  PIN i[596]
    DIRECTION INPUT ;
    USE SIGNAL ;
    PORT
      LAYER M4 ;
        RECT  40.956 21.936 41.04 21.96 ;
    END
  END i[596]
  PIN i[597]
    DIRECTION INPUT ;
    USE SIGNAL ;
    PORT
      LAYER M4 ;
        RECT  40.956 22.032 41.04 22.056 ;
    END
  END i[597]
  PIN i[598]
    DIRECTION INPUT ;
    USE SIGNAL ;
    PORT
      LAYER M4 ;
        RECT  40.956 22.128 41.04 22.152 ;
    END
  END i[598]
  PIN i[599]
    DIRECTION INPUT ;
    USE SIGNAL ;
    PORT
      LAYER M4 ;
        RECT  40.956 22.224 41.04 22.248 ;
    END
  END i[599]
  PIN i[59]
    DIRECTION INPUT ;
    USE SIGNAL ;
    PORT
      LAYER M4 ;
        RECT  40.956 92.496 41.04 92.52 ;
    END
  END i[59]
  PIN i[5]
    DIRECTION INPUT ;
    USE SIGNAL ;
    PORT
      LAYER M4 ;
        RECT  40.956 61.968 41.04 61.992 ;
    END
  END i[5]
  PIN i[600]
    DIRECTION INPUT ;
    USE SIGNAL ;
    PORT
      LAYER M4 ;
        RECT  40.956 22.32 41.04 22.344 ;
    END
  END i[600]
  PIN i[601]
    DIRECTION INPUT ;
    USE SIGNAL ;
    PORT
      LAYER M4 ;
        RECT  40.956 22.416 41.04 22.44 ;
    END
  END i[601]
  PIN i[602]
    DIRECTION INPUT ;
    USE SIGNAL ;
    PORT
      LAYER M4 ;
        RECT  40.956 22.512 41.04 22.536 ;
    END
  END i[602]
  PIN i[603]
    DIRECTION INPUT ;
    USE SIGNAL ;
    PORT
      LAYER M4 ;
        RECT  40.956 22.608 41.04 22.632 ;
    END
  END i[603]
  PIN i[604]
    DIRECTION INPUT ;
    USE SIGNAL ;
    PORT
      LAYER M4 ;
        RECT  40.956 22.704 41.04 22.728 ;
    END
  END i[604]
  PIN i[605]
    DIRECTION INPUT ;
    USE SIGNAL ;
    PORT
      LAYER M4 ;
        RECT  40.956 22.8 41.04 22.824 ;
    END
  END i[605]
  PIN i[606]
    DIRECTION INPUT ;
    USE SIGNAL ;
    PORT
      LAYER M4 ;
        RECT  40.956 22.896 41.04 22.92 ;
    END
  END i[606]
  PIN i[607]
    DIRECTION INPUT ;
    USE SIGNAL ;
    PORT
      LAYER M4 ;
        RECT  40.956 9.936 41.04 9.96 ;
    END
  END i[607]
  PIN i[608]
    DIRECTION INPUT ;
    USE SIGNAL ;
    PORT
      LAYER M4 ;
        RECT  40.956 10.032 41.04 10.056 ;
    END
  END i[608]
  PIN i[609]
    DIRECTION INPUT ;
    USE SIGNAL ;
    PORT
      LAYER M4 ;
        RECT  40.956 10.128 41.04 10.152 ;
    END
  END i[609]
  PIN i[60]
    DIRECTION INPUT ;
    USE SIGNAL ;
    PORT
      LAYER M4 ;
        RECT  40.956 92.592 41.04 92.616 ;
    END
  END i[60]
  PIN i[610]
    DIRECTION INPUT ;
    USE SIGNAL ;
    PORT
      LAYER M4 ;
        RECT  40.956 10.224 41.04 10.248 ;
    END
  END i[610]
  PIN i[611]
    DIRECTION INPUT ;
    USE SIGNAL ;
    PORT
      LAYER M4 ;
        RECT  40.956 10.32 41.04 10.344 ;
    END
  END i[611]
  PIN i[612]
    DIRECTION INPUT ;
    USE SIGNAL ;
    PORT
      LAYER M4 ;
        RECT  40.956 10.416 41.04 10.44 ;
    END
  END i[612]
  PIN i[613]
    DIRECTION INPUT ;
    USE SIGNAL ;
    PORT
      LAYER M4 ;
        RECT  40.956 10.512 41.04 10.536 ;
    END
  END i[613]
  PIN i[614]
    DIRECTION INPUT ;
    USE SIGNAL ;
    PORT
      LAYER M4 ;
        RECT  40.956 10.608 41.04 10.632 ;
    END
  END i[614]
  PIN i[615]
    DIRECTION INPUT ;
    USE SIGNAL ;
    PORT
      LAYER M4 ;
        RECT  40.956 10.704 41.04 10.728 ;
    END
  END i[615]
  PIN i[616]
    DIRECTION INPUT ;
    USE SIGNAL ;
    PORT
      LAYER M4 ;
        RECT  40.956 10.8 41.04 10.824 ;
    END
  END i[616]
  PIN i[617]
    DIRECTION INPUT ;
    USE SIGNAL ;
    PORT
      LAYER M4 ;
        RECT  40.956 10.896 41.04 10.92 ;
    END
  END i[617]
  PIN i[618]
    DIRECTION INPUT ;
    USE SIGNAL ;
    PORT
      LAYER M4 ;
        RECT  40.956 10.992 41.04 11.016 ;
    END
  END i[618]
  PIN i[619]
    DIRECTION INPUT ;
    USE SIGNAL ;
    PORT
      LAYER M4 ;
        RECT  40.956 11.088 41.04 11.112 ;
    END
  END i[619]
  PIN i[61]
    DIRECTION INPUT ;
    USE SIGNAL ;
    PORT
      LAYER M4 ;
        RECT  40.956 92.688 41.04 92.712 ;
    END
  END i[61]
  PIN i[620]
    DIRECTION INPUT ;
    USE SIGNAL ;
    PORT
      LAYER M4 ;
        RECT  40.956 11.184 41.04 11.208 ;
    END
  END i[620]
  PIN i[621]
    DIRECTION INPUT ;
    USE SIGNAL ;
    PORT
      LAYER M4 ;
        RECT  40.956 11.28 41.04 11.304 ;
    END
  END i[621]
  PIN i[622]
    DIRECTION INPUT ;
    USE SIGNAL ;
    PORT
      LAYER M4 ;
        RECT  40.956 11.376 41.04 11.4 ;
    END
  END i[622]
  PIN i[623]
    DIRECTION INPUT ;
    USE SIGNAL ;
    PORT
      LAYER M4 ;
        RECT  40.956 11.472 41.04 11.496 ;
    END
  END i[623]
  PIN i[624]
    DIRECTION INPUT ;
    USE SIGNAL ;
    PORT
      LAYER M4 ;
        RECT  40.956 11.568 41.04 11.592 ;
    END
  END i[624]
  PIN i[625]
    DIRECTION INPUT ;
    USE SIGNAL ;
    PORT
      LAYER M4 ;
        RECT  40.956 11.664 41.04 11.688 ;
    END
  END i[625]
  PIN i[626]
    DIRECTION INPUT ;
    USE SIGNAL ;
    PORT
      LAYER M4 ;
        RECT  40.956 11.76 41.04 11.784 ;
    END
  END i[626]
  PIN i[627]
    DIRECTION INPUT ;
    USE SIGNAL ;
    PORT
      LAYER M4 ;
        RECT  40.956 11.856 41.04 11.88 ;
    END
  END i[627]
  PIN i[628]
    DIRECTION INPUT ;
    USE SIGNAL ;
    PORT
      LAYER M4 ;
        RECT  40.956 11.952 41.04 11.976 ;
    END
  END i[628]
  PIN i[629]
    DIRECTION INPUT ;
    USE SIGNAL ;
    PORT
      LAYER M4 ;
        RECT  40.956 12.048 41.04 12.072 ;
    END
  END i[629]
  PIN i[62]
    DIRECTION INPUT ;
    USE SIGNAL ;
    PORT
      LAYER M4 ;
        RECT  40.956 92.784 41.04 92.808 ;
    END
  END i[62]
  PIN i[630]
    DIRECTION INPUT ;
    USE SIGNAL ;
    PORT
      LAYER M4 ;
        RECT  40.956 12.144 41.04 12.168 ;
    END
  END i[630]
  PIN i[631]
    DIRECTION INPUT ;
    USE SIGNAL ;
    PORT
      LAYER M4 ;
        RECT  40.956 12.24 41.04 12.264 ;
    END
  END i[631]
  PIN i[632]
    DIRECTION INPUT ;
    USE SIGNAL ;
    PORT
      LAYER M4 ;
        RECT  40.956 12.336 41.04 12.36 ;
    END
  END i[632]
  PIN i[633]
    DIRECTION INPUT ;
    USE SIGNAL ;
    PORT
      LAYER M4 ;
        RECT  40.956 12.432 41.04 12.456 ;
    END
  END i[633]
  PIN i[634]
    DIRECTION INPUT ;
    USE SIGNAL ;
    PORT
      LAYER M4 ;
        RECT  40.956 12.528 41.04 12.552 ;
    END
  END i[634]
  PIN i[635]
    DIRECTION INPUT ;
    USE SIGNAL ;
    PORT
      LAYER M4 ;
        RECT  40.956 12.624 41.04 12.648 ;
    END
  END i[635]
  PIN i[636]
    DIRECTION INPUT ;
    USE SIGNAL ;
    PORT
      LAYER M4 ;
        RECT  40.956 12.72 41.04 12.744 ;
    END
  END i[636]
  PIN i[637]
    DIRECTION INPUT ;
    USE SIGNAL ;
    PORT
      LAYER M4 ;
        RECT  40.956 12.816 41.04 12.84 ;
    END
  END i[637]
  PIN i[638]
    DIRECTION INPUT ;
    USE SIGNAL ;
    PORT
      LAYER M4 ;
        RECT  40.956 12.912 41.04 12.936 ;
    END
  END i[638]
  PIN i[639]
    DIRECTION INPUT ;
    USE SIGNAL ;
    PORT
      LAYER M4 ;
        RECT  40.956 22.992 41.04 23.016 ;
    END
  END i[639]
  PIN i[63]
    DIRECTION INPUT ;
    USE SIGNAL ;
    PORT
      LAYER M4 ;
        RECT  40.956 102.864 41.04 102.888 ;
    END
  END i[63]
  PIN i[640]
    DIRECTION INPUT ;
    USE SIGNAL ;
    PORT
      LAYER M4 ;
        RECT  40.956 23.088 41.04 23.112 ;
    END
  END i[640]
  PIN i[641]
    DIRECTION INPUT ;
    USE SIGNAL ;
    PORT
      LAYER M4 ;
        RECT  40.956 23.184 41.04 23.208 ;
    END
  END i[641]
  PIN i[642]
    DIRECTION INPUT ;
    USE SIGNAL ;
    PORT
      LAYER M4 ;
        RECT  40.956 23.28 41.04 23.304 ;
    END
  END i[642]
  PIN i[643]
    DIRECTION INPUT ;
    USE SIGNAL ;
    PORT
      LAYER M4 ;
        RECT  40.956 23.376 41.04 23.4 ;
    END
  END i[643]
  PIN i[644]
    DIRECTION INPUT ;
    USE SIGNAL ;
    PORT
      LAYER M4 ;
        RECT  40.956 23.472 41.04 23.496 ;
    END
  END i[644]
  PIN i[645]
    DIRECTION INPUT ;
    USE SIGNAL ;
    PORT
      LAYER M4 ;
        RECT  40.956 23.568 41.04 23.592 ;
    END
  END i[645]
  PIN i[646]
    DIRECTION INPUT ;
    USE SIGNAL ;
    PORT
      LAYER M4 ;
        RECT  40.956 23.664 41.04 23.688 ;
    END
  END i[646]
  PIN i[647]
    DIRECTION INPUT ;
    USE SIGNAL ;
    PORT
      LAYER M4 ;
        RECT  40.956 23.76 41.04 23.784 ;
    END
  END i[647]
  PIN i[648]
    DIRECTION INPUT ;
    USE SIGNAL ;
    PORT
      LAYER M4 ;
        RECT  40.956 23.856 41.04 23.88 ;
    END
  END i[648]
  PIN i[649]
    DIRECTION INPUT ;
    USE SIGNAL ;
    PORT
      LAYER M4 ;
        RECT  40.956 23.952 41.04 23.976 ;
    END
  END i[649]
  PIN i[64]
    DIRECTION INPUT ;
    USE SIGNAL ;
    PORT
      LAYER M4 ;
        RECT  40.956 102.96 41.04 102.984 ;
    END
  END i[64]
  PIN i[650]
    DIRECTION INPUT ;
    USE SIGNAL ;
    PORT
      LAYER M4 ;
        RECT  40.956 24.048 41.04 24.072 ;
    END
  END i[650]
  PIN i[651]
    DIRECTION INPUT ;
    USE SIGNAL ;
    PORT
      LAYER M4 ;
        RECT  40.956 24.144 41.04 24.168 ;
    END
  END i[651]
  PIN i[652]
    DIRECTION INPUT ;
    USE SIGNAL ;
    PORT
      LAYER M4 ;
        RECT  40.956 24.24 41.04 24.264 ;
    END
  END i[652]
  PIN i[653]
    DIRECTION INPUT ;
    USE SIGNAL ;
    PORT
      LAYER M4 ;
        RECT  40.956 24.336 41.04 24.36 ;
    END
  END i[653]
  PIN i[654]
    DIRECTION INPUT ;
    USE SIGNAL ;
    PORT
      LAYER M4 ;
        RECT  40.956 24.432 41.04 24.456 ;
    END
  END i[654]
  PIN i[655]
    DIRECTION INPUT ;
    USE SIGNAL ;
    PORT
      LAYER M4 ;
        RECT  40.956 24.528 41.04 24.552 ;
    END
  END i[655]
  PIN i[656]
    DIRECTION INPUT ;
    USE SIGNAL ;
    PORT
      LAYER M4 ;
        RECT  40.956 24.624 41.04 24.648 ;
    END
  END i[656]
  PIN i[657]
    DIRECTION INPUT ;
    USE SIGNAL ;
    PORT
      LAYER M4 ;
        RECT  40.956 24.72 41.04 24.744 ;
    END
  END i[657]
  PIN i[658]
    DIRECTION INPUT ;
    USE SIGNAL ;
    PORT
      LAYER M4 ;
        RECT  40.956 24.816 41.04 24.84 ;
    END
  END i[658]
  PIN i[659]
    DIRECTION INPUT ;
    USE SIGNAL ;
    PORT
      LAYER M4 ;
        RECT  40.956 24.912 41.04 24.936 ;
    END
  END i[659]
  PIN i[65]
    DIRECTION INPUT ;
    USE SIGNAL ;
    PORT
      LAYER M4 ;
        RECT  40.956 103.056 41.04 103.08 ;
    END
  END i[65]
  PIN i[660]
    DIRECTION INPUT ;
    USE SIGNAL ;
    PORT
      LAYER M4 ;
        RECT  40.956 25.008 41.04 25.032 ;
    END
  END i[660]
  PIN i[661]
    DIRECTION INPUT ;
    USE SIGNAL ;
    PORT
      LAYER M4 ;
        RECT  40.956 25.104 41.04 25.128 ;
    END
  END i[661]
  PIN i[662]
    DIRECTION INPUT ;
    USE SIGNAL ;
    PORT
      LAYER M4 ;
        RECT  40.956 25.2 41.04 25.224 ;
    END
  END i[662]
  PIN i[663]
    DIRECTION INPUT ;
    USE SIGNAL ;
    PORT
      LAYER M4 ;
        RECT  40.956 25.296 41.04 25.32 ;
    END
  END i[663]
  PIN i[664]
    DIRECTION INPUT ;
    USE SIGNAL ;
    PORT
      LAYER M4 ;
        RECT  40.956 25.392 41.04 25.416 ;
    END
  END i[664]
  PIN i[665]
    DIRECTION INPUT ;
    USE SIGNAL ;
    PORT
      LAYER M4 ;
        RECT  40.956 25.488 41.04 25.512 ;
    END
  END i[665]
  PIN i[666]
    DIRECTION INPUT ;
    USE SIGNAL ;
    PORT
      LAYER M4 ;
        RECT  40.956 25.584 41.04 25.608 ;
    END
  END i[666]
  PIN i[667]
    DIRECTION INPUT ;
    USE SIGNAL ;
    PORT
      LAYER M4 ;
        RECT  40.956 25.68 41.04 25.704 ;
    END
  END i[667]
  PIN i[668]
    DIRECTION INPUT ;
    USE SIGNAL ;
    PORT
      LAYER M4 ;
        RECT  40.956 25.776 41.04 25.8 ;
    END
  END i[668]
  PIN i[669]
    DIRECTION INPUT ;
    USE SIGNAL ;
    PORT
      LAYER M4 ;
        RECT  40.956 25.872 41.04 25.896 ;
    END
  END i[669]
  PIN i[66]
    DIRECTION INPUT ;
    USE SIGNAL ;
    PORT
      LAYER M4 ;
        RECT  40.956 103.152 41.04 103.176 ;
    END
  END i[66]
  PIN i[670]
    DIRECTION INPUT ;
    USE SIGNAL ;
    PORT
      LAYER M4 ;
        RECT  40.956 25.968 41.04 25.992 ;
    END
  END i[670]
  PIN i[671]
    DIRECTION INPUT ;
    USE SIGNAL ;
    PORT
      LAYER M4 ;
        RECT  40.956 35.28 41.04 35.304 ;
    END
  END i[671]
  PIN i[672]
    DIRECTION INPUT ;
    USE SIGNAL ;
    PORT
      LAYER M4 ;
        RECT  40.956 35.376 41.04 35.4 ;
    END
  END i[672]
  PIN i[673]
    DIRECTION INPUT ;
    USE SIGNAL ;
    PORT
      LAYER M4 ;
        RECT  40.956 35.472 41.04 35.496 ;
    END
  END i[673]
  PIN i[674]
    DIRECTION INPUT ;
    USE SIGNAL ;
    PORT
      LAYER M4 ;
        RECT  40.956 35.568 41.04 35.592 ;
    END
  END i[674]
  PIN i[675]
    DIRECTION INPUT ;
    USE SIGNAL ;
    PORT
      LAYER M4 ;
        RECT  40.956 35.664 41.04 35.688 ;
    END
  END i[675]
  PIN i[676]
    DIRECTION INPUT ;
    USE SIGNAL ;
    PORT
      LAYER M4 ;
        RECT  40.956 35.76 41.04 35.784 ;
    END
  END i[676]
  PIN i[677]
    DIRECTION INPUT ;
    USE SIGNAL ;
    PORT
      LAYER M4 ;
        RECT  40.956 35.856 41.04 35.88 ;
    END
  END i[677]
  PIN i[678]
    DIRECTION INPUT ;
    USE SIGNAL ;
    PORT
      LAYER M4 ;
        RECT  40.956 35.952 41.04 35.976 ;
    END
  END i[678]
  PIN i[679]
    DIRECTION INPUT ;
    USE SIGNAL ;
    PORT
      LAYER M4 ;
        RECT  40.956 36.048 41.04 36.072 ;
    END
  END i[679]
  PIN i[67]
    DIRECTION INPUT ;
    USE SIGNAL ;
    PORT
      LAYER M4 ;
        RECT  40.956 103.248 41.04 103.272 ;
    END
  END i[67]
  PIN i[680]
    DIRECTION INPUT ;
    USE SIGNAL ;
    PORT
      LAYER M4 ;
        RECT  40.956 36.144 41.04 36.168 ;
    END
  END i[680]
  PIN i[681]
    DIRECTION INPUT ;
    USE SIGNAL ;
    PORT
      LAYER M4 ;
        RECT  40.956 36.24 41.04 36.264 ;
    END
  END i[681]
  PIN i[68]
    DIRECTION INPUT ;
    USE SIGNAL ;
    PORT
      LAYER M4 ;
        RECT  40.956 103.344 41.04 103.368 ;
    END
  END i[68]
  PIN i[69]
    DIRECTION INPUT ;
    USE SIGNAL ;
    PORT
      LAYER M4 ;
        RECT  40.956 103.44 41.04 103.464 ;
    END
  END i[69]
  PIN i[6]
    DIRECTION INPUT ;
    USE SIGNAL ;
    PORT
      LAYER M4 ;
        RECT  40.956 62.064 41.04 62.088 ;
    END
  END i[6]
  PIN i[70]
    DIRECTION INPUT ;
    USE SIGNAL ;
    PORT
      LAYER M4 ;
        RECT  40.956 103.536 41.04 103.56 ;
    END
  END i[70]
  PIN i[71]
    DIRECTION INPUT ;
    USE SIGNAL ;
    PORT
      LAYER M4 ;
        RECT  40.956 103.632 41.04 103.656 ;
    END
  END i[71]
  PIN i[72]
    DIRECTION INPUT ;
    USE SIGNAL ;
    PORT
      LAYER M4 ;
        RECT  40.956 103.728 41.04 103.752 ;
    END
  END i[72]
  PIN i[73]
    DIRECTION INPUT ;
    USE SIGNAL ;
    PORT
      LAYER M4 ;
        RECT  40.956 103.824 41.04 103.848 ;
    END
  END i[73]
  PIN i[74]
    DIRECTION INPUT ;
    USE SIGNAL ;
    PORT
      LAYER M4 ;
        RECT  40.956 103.92 41.04 103.944 ;
    END
  END i[74]
  PIN i[75]
    DIRECTION INPUT ;
    USE SIGNAL ;
    PORT
      LAYER M4 ;
        RECT  40.956 104.016 41.04 104.04 ;
    END
  END i[75]
  PIN i[76]
    DIRECTION INPUT ;
    USE SIGNAL ;
    PORT
      LAYER M4 ;
        RECT  40.956 104.112 41.04 104.136 ;
    END
  END i[76]
  PIN i[77]
    DIRECTION INPUT ;
    USE SIGNAL ;
    PORT
      LAYER M4 ;
        RECT  40.956 104.208 41.04 104.232 ;
    END
  END i[77]
  PIN i[78]
    DIRECTION INPUT ;
    USE SIGNAL ;
    PORT
      LAYER M4 ;
        RECT  40.956 104.304 41.04 104.328 ;
    END
  END i[78]
  PIN i[79]
    DIRECTION INPUT ;
    USE SIGNAL ;
    PORT
      LAYER M4 ;
        RECT  40.956 104.4 41.04 104.424 ;
    END
  END i[79]
  PIN i[7]
    DIRECTION INPUT ;
    USE SIGNAL ;
    PORT
      LAYER M4 ;
        RECT  40.956 62.16 41.04 62.184 ;
    END
  END i[7]
  PIN i[80]
    DIRECTION INPUT ;
    USE SIGNAL ;
    PORT
      LAYER M4 ;
        RECT  40.956 104.496 41.04 104.52 ;
    END
  END i[80]
  PIN i[81]
    DIRECTION INPUT ;
    USE SIGNAL ;
    PORT
      LAYER M4 ;
        RECT  40.956 104.592 41.04 104.616 ;
    END
  END i[81]
  PIN i[82]
    DIRECTION INPUT ;
    USE SIGNAL ;
    PORT
      LAYER M4 ;
        RECT  40.956 104.688 41.04 104.712 ;
    END
  END i[82]
  PIN i[83]
    DIRECTION INPUT ;
    USE SIGNAL ;
    PORT
      LAYER M4 ;
        RECT  40.956 104.784 41.04 104.808 ;
    END
  END i[83]
  PIN i[84]
    DIRECTION INPUT ;
    USE SIGNAL ;
    PORT
      LAYER M4 ;
        RECT  40.956 104.88 41.04 104.904 ;
    END
  END i[84]
  PIN i[85]
    DIRECTION INPUT ;
    USE SIGNAL ;
    PORT
      LAYER M4 ;
        RECT  40.956 104.976 41.04 105 ;
    END
  END i[85]
  PIN i[86]
    DIRECTION INPUT ;
    USE SIGNAL ;
    PORT
      LAYER M4 ;
        RECT  40.956 105.072 41.04 105.096 ;
    END
  END i[86]
  PIN i[87]
    DIRECTION INPUT ;
    USE SIGNAL ;
    PORT
      LAYER M4 ;
        RECT  40.956 105.168 41.04 105.192 ;
    END
  END i[87]
  PIN i[88]
    DIRECTION INPUT ;
    USE SIGNAL ;
    PORT
      LAYER M4 ;
        RECT  40.956 105.264 41.04 105.288 ;
    END
  END i[88]
  PIN i[89]
    DIRECTION INPUT ;
    USE SIGNAL ;
    PORT
      LAYER M4 ;
        RECT  40.956 105.36 41.04 105.384 ;
    END
  END i[89]
  PIN i[8]
    DIRECTION INPUT ;
    USE SIGNAL ;
    PORT
      LAYER M4 ;
        RECT  40.956 62.256 41.04 62.28 ;
    END
  END i[8]
  PIN i[90]
    DIRECTION INPUT ;
    USE SIGNAL ;
    PORT
      LAYER M4 ;
        RECT  40.956 105.456 41.04 105.48 ;
    END
  END i[90]
  PIN i[91]
    DIRECTION INPUT ;
    USE SIGNAL ;
    PORT
      LAYER M4 ;
        RECT  40.956 105.552 41.04 105.576 ;
    END
  END i[91]
  PIN i[92]
    DIRECTION INPUT ;
    USE SIGNAL ;
    PORT
      LAYER M4 ;
        RECT  40.956 105.648 41.04 105.672 ;
    END
  END i[92]
  PIN i[93]
    DIRECTION INPUT ;
    USE SIGNAL ;
    PORT
      LAYER M4 ;
        RECT  40.956 105.744 41.04 105.768 ;
    END
  END i[93]
  PIN i[94]
    DIRECTION INPUT ;
    USE SIGNAL ;
    PORT
      LAYER M4 ;
        RECT  40.956 105.84 41.04 105.864 ;
    END
  END i[94]
  PIN i[95]
    DIRECTION INPUT ;
    USE SIGNAL ;
    PORT
      LAYER M4 ;
        RECT  40.956 67.536 41.04 67.56 ;
    END
  END i[95]
  PIN i[96]
    DIRECTION INPUT ;
    USE SIGNAL ;
    PORT
      LAYER M4 ;
        RECT  40.956 67.632 41.04 67.656 ;
    END
  END i[96]
  PIN i[97]
    DIRECTION INPUT ;
    USE SIGNAL ;
    PORT
      LAYER M4 ;
        RECT  40.956 67.728 41.04 67.752 ;
    END
  END i[97]
  PIN i[98]
    DIRECTION INPUT ;
    USE SIGNAL ;
    PORT
      LAYER M4 ;
        RECT  40.956 67.824 41.04 67.848 ;
    END
  END i[98]
  PIN i[99]
    DIRECTION INPUT ;
    USE SIGNAL ;
    PORT
      LAYER M4 ;
        RECT  40.956 67.92 41.04 67.944 ;
    END
  END i[99]
  PIN i[9]
    DIRECTION INPUT ;
    USE SIGNAL ;
    PORT
      LAYER M4 ;
        RECT  40.956 62.352 41.04 62.376 ;
    END
  END i[9]
  PIN k[0]
    DIRECTION INPUT ;
    USE SIGNAL ;
    PORT
      LAYER M3 ;
        RECT  8.532 114.443 8.55 114.48 ;
    END
  END k[0]
  PIN k[1]
    DIRECTION INPUT ;
    USE SIGNAL ;
    PORT
      LAYER M3 ;
        RECT  8.604 114.443 8.622 114.48 ;
    END
  END k[1]
  PIN k[2]
    DIRECTION INPUT ;
    USE SIGNAL ;
    PORT
      LAYER M3 ;
        RECT  8.676 114.443 8.694 114.48 ;
    END
  END k[2]
  PIN o[0]
    DIRECTION OUTPUT ;
    USE SIGNAL ;
    PORT
      LAYER M4 ;
        RECT  0 60.24 0.084 60.264 ;
    END
  END o[0]
  PIN o[100]
    DIRECTION OUTPUT ;
    USE SIGNAL ;
    PORT
      LAYER M4 ;
        RECT  0 69.84 0.084 69.864 ;
    END
  END o[100]
  PIN o[101]
    DIRECTION OUTPUT ;
    USE SIGNAL ;
    PORT
      LAYER M4 ;
        RECT  0 69.936 0.084 69.96 ;
    END
  END o[101]
  PIN o[102]
    DIRECTION OUTPUT ;
    USE SIGNAL ;
    PORT
      LAYER M4 ;
        RECT  0 70.032 0.084 70.056 ;
    END
  END o[102]
  PIN o[103]
    DIRECTION OUTPUT ;
    USE SIGNAL ;
    PORT
      LAYER M4 ;
        RECT  0 70.128 0.084 70.152 ;
    END
  END o[103]
  PIN o[104]
    DIRECTION OUTPUT ;
    USE SIGNAL ;
    PORT
      LAYER M4 ;
        RECT  0 70.224 0.084 70.248 ;
    END
  END o[104]
  PIN o[105]
    DIRECTION OUTPUT ;
    USE SIGNAL ;
    PORT
      LAYER M4 ;
        RECT  0 70.32 0.084 70.344 ;
    END
  END o[105]
  PIN o[106]
    DIRECTION OUTPUT ;
    USE SIGNAL ;
    PORT
      LAYER M4 ;
        RECT  0 70.416 0.084 70.44 ;
    END
  END o[106]
  PIN o[107]
    DIRECTION OUTPUT ;
    USE SIGNAL ;
    PORT
      LAYER M4 ;
        RECT  0 70.512 0.084 70.536 ;
    END
  END o[107]
  PIN o[108]
    DIRECTION OUTPUT ;
    USE SIGNAL ;
    PORT
      LAYER M4 ;
        RECT  0 70.608 0.084 70.632 ;
    END
  END o[108]
  PIN o[109]
    DIRECTION OUTPUT ;
    USE SIGNAL ;
    PORT
      LAYER M4 ;
        RECT  0 70.704 0.084 70.728 ;
    END
  END o[109]
  PIN o[10]
    DIRECTION OUTPUT ;
    USE SIGNAL ;
    PORT
      LAYER M4 ;
        RECT  0 61.2 0.084 61.224 ;
    END
  END o[10]
  PIN o[110]
    DIRECTION OUTPUT ;
    USE SIGNAL ;
    PORT
      LAYER M4 ;
        RECT  0 70.8 0.084 70.824 ;
    END
  END o[110]
  PIN o[111]
    DIRECTION OUTPUT ;
    USE SIGNAL ;
    PORT
      LAYER M4 ;
        RECT  0 70.896 0.084 70.92 ;
    END
  END o[111]
  PIN o[112]
    DIRECTION OUTPUT ;
    USE SIGNAL ;
    PORT
      LAYER M4 ;
        RECT  0 70.992 0.084 71.016 ;
    END
  END o[112]
  PIN o[113]
    DIRECTION OUTPUT ;
    USE SIGNAL ;
    PORT
      LAYER M4 ;
        RECT  0 71.088 0.084 71.112 ;
    END
  END o[113]
  PIN o[114]
    DIRECTION OUTPUT ;
    USE SIGNAL ;
    PORT
      LAYER M4 ;
        RECT  0 71.184 0.084 71.208 ;
    END
  END o[114]
  PIN o[115]
    DIRECTION OUTPUT ;
    USE SIGNAL ;
    PORT
      LAYER M4 ;
        RECT  0 71.28 0.084 71.304 ;
    END
  END o[115]
  PIN o[116]
    DIRECTION OUTPUT ;
    USE SIGNAL ;
    PORT
      LAYER M4 ;
        RECT  0 71.376 0.084 71.4 ;
    END
  END o[116]
  PIN o[117]
    DIRECTION OUTPUT ;
    USE SIGNAL ;
    PORT
      LAYER M4 ;
        RECT  0 71.472 0.084 71.496 ;
    END
  END o[117]
  PIN o[118]
    DIRECTION OUTPUT ;
    USE SIGNAL ;
    PORT
      LAYER M4 ;
        RECT  0 71.568 0.084 71.592 ;
    END
  END o[118]
  PIN o[119]
    DIRECTION OUTPUT ;
    USE SIGNAL ;
    PORT
      LAYER M4 ;
        RECT  0 71.664 0.084 71.688 ;
    END
  END o[119]
  PIN o[11]
    DIRECTION OUTPUT ;
    USE SIGNAL ;
    PORT
      LAYER M4 ;
        RECT  0 61.296 0.084 61.32 ;
    END
  END o[11]
  PIN o[120]
    DIRECTION OUTPUT ;
    USE SIGNAL ;
    PORT
      LAYER M4 ;
        RECT  0 71.76 0.084 71.784 ;
    END
  END o[120]
  PIN o[121]
    DIRECTION OUTPUT ;
    USE SIGNAL ;
    PORT
      LAYER M4 ;
        RECT  0 71.856 0.084 71.88 ;
    END
  END o[121]
  PIN o[122]
    DIRECTION OUTPUT ;
    USE SIGNAL ;
    PORT
      LAYER M4 ;
        RECT  0 71.952 0.084 71.976 ;
    END
  END o[122]
  PIN o[123]
    DIRECTION OUTPUT ;
    USE SIGNAL ;
    PORT
      LAYER M4 ;
        RECT  0 72.048 0.084 72.072 ;
    END
  END o[123]
  PIN o[124]
    DIRECTION OUTPUT ;
    USE SIGNAL ;
    PORT
      LAYER M4 ;
        RECT  0 72.144 0.084 72.168 ;
    END
  END o[124]
  PIN o[125]
    DIRECTION OUTPUT ;
    USE SIGNAL ;
    PORT
      LAYER M4 ;
        RECT  0 72.24 0.084 72.264 ;
    END
  END o[125]
  PIN o[126]
    DIRECTION OUTPUT ;
    USE SIGNAL ;
    PORT
      LAYER M4 ;
        RECT  0 53.136 0.084 53.16 ;
    END
  END o[126]
  PIN o[127]
    DIRECTION OUTPUT ;
    USE SIGNAL ;
    PORT
      LAYER M4 ;
        RECT  0 53.232 0.084 53.256 ;
    END
  END o[127]
  PIN o[128]
    DIRECTION OUTPUT ;
    USE SIGNAL ;
    PORT
      LAYER M4 ;
        RECT  0 53.328 0.084 53.352 ;
    END
  END o[128]
  PIN o[129]
    DIRECTION OUTPUT ;
    USE SIGNAL ;
    PORT
      LAYER M4 ;
        RECT  0 53.424 0.084 53.448 ;
    END
  END o[129]
  PIN o[12]
    DIRECTION OUTPUT ;
    USE SIGNAL ;
    PORT
      LAYER M4 ;
        RECT  0 61.392 0.084 61.416 ;
    END
  END o[12]
  PIN o[130]
    DIRECTION OUTPUT ;
    USE SIGNAL ;
    PORT
      LAYER M4 ;
        RECT  0 53.52 0.084 53.544 ;
    END
  END o[130]
  PIN o[131]
    DIRECTION OUTPUT ;
    USE SIGNAL ;
    PORT
      LAYER M4 ;
        RECT  0 53.616 0.084 53.64 ;
    END
  END o[131]
  PIN o[132]
    DIRECTION OUTPUT ;
    USE SIGNAL ;
    PORT
      LAYER M4 ;
        RECT  0 53.712 0.084 53.736 ;
    END
  END o[132]
  PIN o[133]
    DIRECTION OUTPUT ;
    USE SIGNAL ;
    PORT
      LAYER M4 ;
        RECT  0 53.808 0.084 53.832 ;
    END
  END o[133]
  PIN o[134]
    DIRECTION OUTPUT ;
    USE SIGNAL ;
    PORT
      LAYER M4 ;
        RECT  0 53.904 0.084 53.928 ;
    END
  END o[134]
  PIN o[135]
    DIRECTION OUTPUT ;
    USE SIGNAL ;
    PORT
      LAYER M4 ;
        RECT  0 54 0.084 54.024 ;
    END
  END o[135]
  PIN o[136]
    DIRECTION OUTPUT ;
    USE SIGNAL ;
    PORT
      LAYER M4 ;
        RECT  0 54.096 0.084 54.12 ;
    END
  END o[136]
  PIN o[137]
    DIRECTION OUTPUT ;
    USE SIGNAL ;
    PORT
      LAYER M4 ;
        RECT  0 54.192 0.084 54.216 ;
    END
  END o[137]
  PIN o[138]
    DIRECTION OUTPUT ;
    USE SIGNAL ;
    PORT
      LAYER M4 ;
        RECT  0 54.288 0.084 54.312 ;
    END
  END o[138]
  PIN o[139]
    DIRECTION OUTPUT ;
    USE SIGNAL ;
    PORT
      LAYER M4 ;
        RECT  0 54.384 0.084 54.408 ;
    END
  END o[139]
  PIN o[13]
    DIRECTION OUTPUT ;
    USE SIGNAL ;
    PORT
      LAYER M4 ;
        RECT  0 61.488 0.084 61.512 ;
    END
  END o[13]
  PIN o[140]
    DIRECTION OUTPUT ;
    USE SIGNAL ;
    PORT
      LAYER M4 ;
        RECT  0 54.48 0.084 54.504 ;
    END
  END o[140]
  PIN o[141]
    DIRECTION OUTPUT ;
    USE SIGNAL ;
    PORT
      LAYER M4 ;
        RECT  0 54.576 0.084 54.6 ;
    END
  END o[141]
  PIN o[142]
    DIRECTION OUTPUT ;
    USE SIGNAL ;
    PORT
      LAYER M4 ;
        RECT  0 54.672 0.084 54.696 ;
    END
  END o[142]
  PIN o[143]
    DIRECTION OUTPUT ;
    USE SIGNAL ;
    PORT
      LAYER M4 ;
        RECT  0 54.768 0.084 54.792 ;
    END
  END o[143]
  PIN o[144]
    DIRECTION OUTPUT ;
    USE SIGNAL ;
    PORT
      LAYER M4 ;
        RECT  0 54.864 0.084 54.888 ;
    END
  END o[144]
  PIN o[145]
    DIRECTION OUTPUT ;
    USE SIGNAL ;
    PORT
      LAYER M4 ;
        RECT  0 54.96 0.084 54.984 ;
    END
  END o[145]
  PIN o[146]
    DIRECTION OUTPUT ;
    USE SIGNAL ;
    PORT
      LAYER M4 ;
        RECT  0 55.056 0.084 55.08 ;
    END
  END o[146]
  PIN o[147]
    DIRECTION OUTPUT ;
    USE SIGNAL ;
    PORT
      LAYER M4 ;
        RECT  0 55.152 0.084 55.176 ;
    END
  END o[147]
  PIN o[148]
    DIRECTION OUTPUT ;
    USE SIGNAL ;
    PORT
      LAYER M4 ;
        RECT  0 55.248 0.084 55.272 ;
    END
  END o[148]
  PIN o[149]
    DIRECTION OUTPUT ;
    USE SIGNAL ;
    PORT
      LAYER M4 ;
        RECT  0 55.344 0.084 55.368 ;
    END
  END o[149]
  PIN o[14]
    DIRECTION OUTPUT ;
    USE SIGNAL ;
    PORT
      LAYER M4 ;
        RECT  0 61.584 0.084 61.608 ;
    END
  END o[14]
  PIN o[150]
    DIRECTION OUTPUT ;
    USE SIGNAL ;
    PORT
      LAYER M4 ;
        RECT  0 55.44 0.084 55.464 ;
    END
  END o[150]
  PIN o[151]
    DIRECTION OUTPUT ;
    USE SIGNAL ;
    PORT
      LAYER M4 ;
        RECT  0 55.536 0.084 55.56 ;
    END
  END o[151]
  PIN o[152]
    DIRECTION OUTPUT ;
    USE SIGNAL ;
    PORT
      LAYER M4 ;
        RECT  0 55.632 0.084 55.656 ;
    END
  END o[152]
  PIN o[153]
    DIRECTION OUTPUT ;
    USE SIGNAL ;
    PORT
      LAYER M4 ;
        RECT  0 55.728 0.084 55.752 ;
    END
  END o[153]
  PIN o[154]
    DIRECTION OUTPUT ;
    USE SIGNAL ;
    PORT
      LAYER M4 ;
        RECT  0 55.824 0.084 55.848 ;
    END
  END o[154]
  PIN o[155]
    DIRECTION OUTPUT ;
    USE SIGNAL ;
    PORT
      LAYER M4 ;
        RECT  0 55.92 0.084 55.944 ;
    END
  END o[155]
  PIN o[156]
    DIRECTION OUTPUT ;
    USE SIGNAL ;
    PORT
      LAYER M4 ;
        RECT  0 56.016 0.084 56.04 ;
    END
  END o[156]
  PIN o[157]
    DIRECTION OUTPUT ;
    USE SIGNAL ;
    PORT
      LAYER M4 ;
        RECT  0 56.112 0.084 56.136 ;
    END
  END o[157]
  PIN o[158]
    DIRECTION OUTPUT ;
    USE SIGNAL ;
    PORT
      LAYER M4 ;
        RECT  0 37.776 0.084 37.8 ;
    END
  END o[158]
  PIN o[159]
    DIRECTION OUTPUT ;
    USE SIGNAL ;
    PORT
      LAYER M4 ;
        RECT  0 37.872 0.084 37.896 ;
    END
  END o[159]
  PIN o[15]
    DIRECTION OUTPUT ;
    USE SIGNAL ;
    PORT
      LAYER M4 ;
        RECT  0 61.68 0.084 61.704 ;
    END
  END o[15]
  PIN o[160]
    DIRECTION OUTPUT ;
    USE SIGNAL ;
    PORT
      LAYER M4 ;
        RECT  0 37.968 0.084 37.992 ;
    END
  END o[160]
  PIN o[161]
    DIRECTION OUTPUT ;
    USE SIGNAL ;
    PORT
      LAYER M4 ;
        RECT  0 38.064 0.084 38.088 ;
    END
  END o[161]
  PIN o[162]
    DIRECTION OUTPUT ;
    USE SIGNAL ;
    PORT
      LAYER M4 ;
        RECT  0 38.16 0.084 38.184 ;
    END
  END o[162]
  PIN o[163]
    DIRECTION OUTPUT ;
    USE SIGNAL ;
    PORT
      LAYER M4 ;
        RECT  0 38.256 0.084 38.28 ;
    END
  END o[163]
  PIN o[164]
    DIRECTION OUTPUT ;
    USE SIGNAL ;
    PORT
      LAYER M4 ;
        RECT  0 38.352 0.084 38.376 ;
    END
  END o[164]
  PIN o[165]
    DIRECTION OUTPUT ;
    USE SIGNAL ;
    PORT
      LAYER M4 ;
        RECT  0 38.448 0.084 38.472 ;
    END
  END o[165]
  PIN o[166]
    DIRECTION OUTPUT ;
    USE SIGNAL ;
    PORT
      LAYER M4 ;
        RECT  0 38.544 0.084 38.568 ;
    END
  END o[166]
  PIN o[167]
    DIRECTION OUTPUT ;
    USE SIGNAL ;
    PORT
      LAYER M4 ;
        RECT  0 38.64 0.084 38.664 ;
    END
  END o[167]
  PIN o[168]
    DIRECTION OUTPUT ;
    USE SIGNAL ;
    PORT
      LAYER M4 ;
        RECT  0 38.736 0.084 38.76 ;
    END
  END o[168]
  PIN o[169]
    DIRECTION OUTPUT ;
    USE SIGNAL ;
    PORT
      LAYER M4 ;
        RECT  0 38.832 0.084 38.856 ;
    END
  END o[169]
  PIN o[16]
    DIRECTION OUTPUT ;
    USE SIGNAL ;
    PORT
      LAYER M4 ;
        RECT  0 61.776 0.084 61.8 ;
    END
  END o[16]
  PIN o[170]
    DIRECTION OUTPUT ;
    USE SIGNAL ;
    PORT
      LAYER M4 ;
        RECT  0 38.928 0.084 38.952 ;
    END
  END o[170]
  PIN o[171]
    DIRECTION OUTPUT ;
    USE SIGNAL ;
    PORT
      LAYER M4 ;
        RECT  0 39.024 0.084 39.048 ;
    END
  END o[171]
  PIN o[172]
    DIRECTION OUTPUT ;
    USE SIGNAL ;
    PORT
      LAYER M4 ;
        RECT  0 39.12 0.084 39.144 ;
    END
  END o[172]
  PIN o[173]
    DIRECTION OUTPUT ;
    USE SIGNAL ;
    PORT
      LAYER M4 ;
        RECT  0 39.216 0.084 39.24 ;
    END
  END o[173]
  PIN o[174]
    DIRECTION OUTPUT ;
    USE SIGNAL ;
    PORT
      LAYER M4 ;
        RECT  0 39.312 0.084 39.336 ;
    END
  END o[174]
  PIN o[175]
    DIRECTION OUTPUT ;
    USE SIGNAL ;
    PORT
      LAYER M4 ;
        RECT  0 39.408 0.084 39.432 ;
    END
  END o[175]
  PIN o[176]
    DIRECTION OUTPUT ;
    USE SIGNAL ;
    PORT
      LAYER M4 ;
        RECT  0 39.504 0.084 39.528 ;
    END
  END o[176]
  PIN o[177]
    DIRECTION OUTPUT ;
    USE SIGNAL ;
    PORT
      LAYER M4 ;
        RECT  0 39.6 0.084 39.624 ;
    END
  END o[177]
  PIN o[178]
    DIRECTION OUTPUT ;
    USE SIGNAL ;
    PORT
      LAYER M4 ;
        RECT  0 39.696 0.084 39.72 ;
    END
  END o[178]
  PIN o[179]
    DIRECTION OUTPUT ;
    USE SIGNAL ;
    PORT
      LAYER M4 ;
        RECT  0 39.792 0.084 39.816 ;
    END
  END o[179]
  PIN o[17]
    DIRECTION OUTPUT ;
    USE SIGNAL ;
    PORT
      LAYER M4 ;
        RECT  0 61.872 0.084 61.896 ;
    END
  END o[17]
  PIN o[180]
    DIRECTION OUTPUT ;
    USE SIGNAL ;
    PORT
      LAYER M4 ;
        RECT  0 39.888 0.084 39.912 ;
    END
  END o[180]
  PIN o[181]
    DIRECTION OUTPUT ;
    USE SIGNAL ;
    PORT
      LAYER M4 ;
        RECT  0 39.984 0.084 40.008 ;
    END
  END o[181]
  PIN o[182]
    DIRECTION OUTPUT ;
    USE SIGNAL ;
    PORT
      LAYER M4 ;
        RECT  0 40.08 0.084 40.104 ;
    END
  END o[182]
  PIN o[183]
    DIRECTION OUTPUT ;
    USE SIGNAL ;
    PORT
      LAYER M4 ;
        RECT  0 40.176 0.084 40.2 ;
    END
  END o[183]
  PIN o[184]
    DIRECTION OUTPUT ;
    USE SIGNAL ;
    PORT
      LAYER M4 ;
        RECT  0 40.272 0.084 40.296 ;
    END
  END o[184]
  PIN o[185]
    DIRECTION OUTPUT ;
    USE SIGNAL ;
    PORT
      LAYER M4 ;
        RECT  0 40.368 0.084 40.392 ;
    END
  END o[185]
  PIN o[186]
    DIRECTION OUTPUT ;
    USE SIGNAL ;
    PORT
      LAYER M4 ;
        RECT  0 40.464 0.084 40.488 ;
    END
  END o[186]
  PIN o[187]
    DIRECTION OUTPUT ;
    USE SIGNAL ;
    PORT
      LAYER M4 ;
        RECT  0 40.56 0.084 40.584 ;
    END
  END o[187]
  PIN o[188]
    DIRECTION OUTPUT ;
    USE SIGNAL ;
    PORT
      LAYER M4 ;
        RECT  0 40.656 0.084 40.68 ;
    END
  END o[188]
  PIN o[189]
    DIRECTION OUTPUT ;
    USE SIGNAL ;
    PORT
      LAYER M4 ;
        RECT  0 40.752 0.084 40.776 ;
    END
  END o[189]
  PIN o[18]
    DIRECTION OUTPUT ;
    USE SIGNAL ;
    PORT
      LAYER M4 ;
        RECT  0 61.968 0.084 61.992 ;
    END
  END o[18]
  PIN o[190]
    DIRECTION OUTPUT ;
    USE SIGNAL ;
    PORT
      LAYER M4 ;
        RECT  0 11.664 0.084 11.688 ;
    END
  END o[190]
  PIN o[191]
    DIRECTION OUTPUT ;
    USE SIGNAL ;
    PORT
      LAYER M4 ;
        RECT  0 11.76 0.084 11.784 ;
    END
  END o[191]
  PIN o[192]
    DIRECTION OUTPUT ;
    USE SIGNAL ;
    PORT
      LAYER M4 ;
        RECT  0 11.856 0.084 11.88 ;
    END
  END o[192]
  PIN o[193]
    DIRECTION OUTPUT ;
    USE SIGNAL ;
    PORT
      LAYER M4 ;
        RECT  0 11.952 0.084 11.976 ;
    END
  END o[193]
  PIN o[194]
    DIRECTION OUTPUT ;
    USE SIGNAL ;
    PORT
      LAYER M4 ;
        RECT  0 12.048 0.084 12.072 ;
    END
  END o[194]
  PIN o[195]
    DIRECTION OUTPUT ;
    USE SIGNAL ;
    PORT
      LAYER M4 ;
        RECT  0 12.144 0.084 12.168 ;
    END
  END o[195]
  PIN o[196]
    DIRECTION OUTPUT ;
    USE SIGNAL ;
    PORT
      LAYER M4 ;
        RECT  0 12.24 0.084 12.264 ;
    END
  END o[196]
  PIN o[197]
    DIRECTION OUTPUT ;
    USE SIGNAL ;
    PORT
      LAYER M4 ;
        RECT  0 12.336 0.084 12.36 ;
    END
  END o[197]
  PIN o[198]
    DIRECTION OUTPUT ;
    USE SIGNAL ;
    PORT
      LAYER M4 ;
        RECT  0 12.432 0.084 12.456 ;
    END
  END o[198]
  PIN o[199]
    DIRECTION OUTPUT ;
    USE SIGNAL ;
    PORT
      LAYER M4 ;
        RECT  0 12.528 0.084 12.552 ;
    END
  END o[199]
  PIN o[19]
    DIRECTION OUTPUT ;
    USE SIGNAL ;
    PORT
      LAYER M4 ;
        RECT  0 62.064 0.084 62.088 ;
    END
  END o[19]
  PIN o[1]
    DIRECTION OUTPUT ;
    USE SIGNAL ;
    PORT
      LAYER M4 ;
        RECT  0 60.336 0.084 60.36 ;
    END
  END o[1]
  PIN o[200]
    DIRECTION OUTPUT ;
    USE SIGNAL ;
    PORT
      LAYER M4 ;
        RECT  0 12.624 0.084 12.648 ;
    END
  END o[200]
  PIN o[201]
    DIRECTION OUTPUT ;
    USE SIGNAL ;
    PORT
      LAYER M4 ;
        RECT  0 12.72 0.084 12.744 ;
    END
  END o[201]
  PIN o[202]
    DIRECTION OUTPUT ;
    USE SIGNAL ;
    PORT
      LAYER M4 ;
        RECT  0 12.816 0.084 12.84 ;
    END
  END o[202]
  PIN o[203]
    DIRECTION OUTPUT ;
    USE SIGNAL ;
    PORT
      LAYER M4 ;
        RECT  0 12.912 0.084 12.936 ;
    END
  END o[203]
  PIN o[204]
    DIRECTION OUTPUT ;
    USE SIGNAL ;
    PORT
      LAYER M4 ;
        RECT  0 13.008 0.084 13.032 ;
    END
  END o[204]
  PIN o[205]
    DIRECTION OUTPUT ;
    USE SIGNAL ;
    PORT
      LAYER M4 ;
        RECT  0 13.104 0.084 13.128 ;
    END
  END o[205]
  PIN o[206]
    DIRECTION OUTPUT ;
    USE SIGNAL ;
    PORT
      LAYER M4 ;
        RECT  0 13.2 0.084 13.224 ;
    END
  END o[206]
  PIN o[207]
    DIRECTION OUTPUT ;
    USE SIGNAL ;
    PORT
      LAYER M4 ;
        RECT  0 13.296 0.084 13.32 ;
    END
  END o[207]
  PIN o[208]
    DIRECTION OUTPUT ;
    USE SIGNAL ;
    PORT
      LAYER M4 ;
        RECT  0 13.392 0.084 13.416 ;
    END
  END o[208]
  PIN o[209]
    DIRECTION OUTPUT ;
    USE SIGNAL ;
    PORT
      LAYER M4 ;
        RECT  0 13.488 0.084 13.512 ;
    END
  END o[209]
  PIN o[20]
    DIRECTION OUTPUT ;
    USE SIGNAL ;
    PORT
      LAYER M4 ;
        RECT  0 62.16 0.084 62.184 ;
    END
  END o[20]
  PIN o[210]
    DIRECTION OUTPUT ;
    USE SIGNAL ;
    PORT
      LAYER M4 ;
        RECT  0 13.584 0.084 13.608 ;
    END
  END o[210]
  PIN o[211]
    DIRECTION OUTPUT ;
    USE SIGNAL ;
    PORT
      LAYER M4 ;
        RECT  0 13.68 0.084 13.704 ;
    END
  END o[211]
  PIN o[212]
    DIRECTION OUTPUT ;
    USE SIGNAL ;
    PORT
      LAYER M4 ;
        RECT  0 13.776 0.084 13.8 ;
    END
  END o[212]
  PIN o[213]
    DIRECTION OUTPUT ;
    USE SIGNAL ;
    PORT
      LAYER M4 ;
        RECT  0 13.872 0.084 13.896 ;
    END
  END o[213]
  PIN o[214]
    DIRECTION OUTPUT ;
    USE SIGNAL ;
    PORT
      LAYER M4 ;
        RECT  0 13.968 0.084 13.992 ;
    END
  END o[214]
  PIN o[215]
    DIRECTION OUTPUT ;
    USE SIGNAL ;
    PORT
      LAYER M4 ;
        RECT  0 14.064 0.084 14.088 ;
    END
  END o[215]
  PIN o[216]
    DIRECTION OUTPUT ;
    USE SIGNAL ;
    PORT
      LAYER M4 ;
        RECT  0 14.16 0.084 14.184 ;
    END
  END o[216]
  PIN o[217]
    DIRECTION OUTPUT ;
    USE SIGNAL ;
    PORT
      LAYER M4 ;
        RECT  0 14.256 0.084 14.28 ;
    END
  END o[217]
  PIN o[218]
    DIRECTION OUTPUT ;
    USE SIGNAL ;
    PORT
      LAYER M4 ;
        RECT  0 14.352 0.084 14.376 ;
    END
  END o[218]
  PIN o[219]
    DIRECTION OUTPUT ;
    USE SIGNAL ;
    PORT
      LAYER M4 ;
        RECT  0 14.448 0.084 14.472 ;
    END
  END o[219]
  PIN o[21]
    DIRECTION OUTPUT ;
    USE SIGNAL ;
    PORT
      LAYER M4 ;
        RECT  0 62.256 0.084 62.28 ;
    END
  END o[21]
  PIN o[220]
    DIRECTION OUTPUT ;
    USE SIGNAL ;
    PORT
      LAYER M4 ;
        RECT  0 14.544 0.084 14.568 ;
    END
  END o[220]
  PIN o[221]
    DIRECTION OUTPUT ;
    USE SIGNAL ;
    PORT
      LAYER M4 ;
        RECT  0 14.64 0.084 14.664 ;
    END
  END o[221]
  PIN o[222]
    DIRECTION OUTPUT ;
    USE SIGNAL ;
    PORT
      LAYER M4 ;
        RECT  0 5.52 0.084 5.544 ;
    END
  END o[222]
  PIN o[223]
    DIRECTION OUTPUT ;
    USE SIGNAL ;
    PORT
      LAYER M4 ;
        RECT  0 5.616 0.084 5.64 ;
    END
  END o[223]
  PIN o[224]
    DIRECTION OUTPUT ;
    USE SIGNAL ;
    PORT
      LAYER M4 ;
        RECT  0 5.712 0.084 5.736 ;
    END
  END o[224]
  PIN o[225]
    DIRECTION OUTPUT ;
    USE SIGNAL ;
    PORT
      LAYER M4 ;
        RECT  0 5.808 0.084 5.832 ;
    END
  END o[225]
  PIN o[226]
    DIRECTION OUTPUT ;
    USE SIGNAL ;
    PORT
      LAYER M4 ;
        RECT  0 5.904 0.084 5.928 ;
    END
  END o[226]
  PIN o[227]
    DIRECTION OUTPUT ;
    USE SIGNAL ;
    PORT
      LAYER M4 ;
        RECT  0 6 0.084 6.024 ;
    END
  END o[227]
  PIN o[228]
    DIRECTION OUTPUT ;
    USE SIGNAL ;
    PORT
      LAYER M4 ;
        RECT  0 6.096 0.084 6.12 ;
    END
  END o[228]
  PIN o[229]
    DIRECTION OUTPUT ;
    USE SIGNAL ;
    PORT
      LAYER M4 ;
        RECT  0 6.192 0.084 6.216 ;
    END
  END o[229]
  PIN o[22]
    DIRECTION OUTPUT ;
    USE SIGNAL ;
    PORT
      LAYER M4 ;
        RECT  0 62.352 0.084 62.376 ;
    END
  END o[22]
  PIN o[230]
    DIRECTION OUTPUT ;
    USE SIGNAL ;
    PORT
      LAYER M4 ;
        RECT  0 6.288 0.084 6.312 ;
    END
  END o[230]
  PIN o[231]
    DIRECTION OUTPUT ;
    USE SIGNAL ;
    PORT
      LAYER M4 ;
        RECT  0 6.384 0.084 6.408 ;
    END
  END o[231]
  PIN o[232]
    DIRECTION OUTPUT ;
    USE SIGNAL ;
    PORT
      LAYER M4 ;
        RECT  0 6.48 0.084 6.504 ;
    END
  END o[232]
  PIN o[233]
    DIRECTION OUTPUT ;
    USE SIGNAL ;
    PORT
      LAYER M4 ;
        RECT  0 6.576 0.084 6.6 ;
    END
  END o[233]
  PIN o[234]
    DIRECTION OUTPUT ;
    USE SIGNAL ;
    PORT
      LAYER M4 ;
        RECT  0 6.672 0.084 6.696 ;
    END
  END o[234]
  PIN o[235]
    DIRECTION OUTPUT ;
    USE SIGNAL ;
    PORT
      LAYER M4 ;
        RECT  0 6.768 0.084 6.792 ;
    END
  END o[235]
  PIN o[236]
    DIRECTION OUTPUT ;
    USE SIGNAL ;
    PORT
      LAYER M4 ;
        RECT  0 6.864 0.084 6.888 ;
    END
  END o[236]
  PIN o[237]
    DIRECTION OUTPUT ;
    USE SIGNAL ;
    PORT
      LAYER M4 ;
        RECT  0 6.96 0.084 6.984 ;
    END
  END o[237]
  PIN o[238]
    DIRECTION OUTPUT ;
    USE SIGNAL ;
    PORT
      LAYER M4 ;
        RECT  0 7.056 0.084 7.08 ;
    END
  END o[238]
  PIN o[239]
    DIRECTION OUTPUT ;
    USE SIGNAL ;
    PORT
      LAYER M4 ;
        RECT  0 7.152 0.084 7.176 ;
    END
  END o[239]
  PIN o[23]
    DIRECTION OUTPUT ;
    USE SIGNAL ;
    PORT
      LAYER M4 ;
        RECT  0 62.448 0.084 62.472 ;
    END
  END o[23]
  PIN o[240]
    DIRECTION OUTPUT ;
    USE SIGNAL ;
    PORT
      LAYER M4 ;
        RECT  0 7.248 0.084 7.272 ;
    END
  END o[240]
  PIN o[241]
    DIRECTION OUTPUT ;
    USE SIGNAL ;
    PORT
      LAYER M4 ;
        RECT  0 7.344 0.084 7.368 ;
    END
  END o[241]
  PIN o[242]
    DIRECTION OUTPUT ;
    USE SIGNAL ;
    PORT
      LAYER M4 ;
        RECT  0 7.44 0.084 7.464 ;
    END
  END o[242]
  PIN o[243]
    DIRECTION OUTPUT ;
    USE SIGNAL ;
    PORT
      LAYER M4 ;
        RECT  0 7.536 0.084 7.56 ;
    END
  END o[243]
  PIN o[244]
    DIRECTION OUTPUT ;
    USE SIGNAL ;
    PORT
      LAYER M4 ;
        RECT  0 7.632 0.084 7.656 ;
    END
  END o[244]
  PIN o[245]
    DIRECTION OUTPUT ;
    USE SIGNAL ;
    PORT
      LAYER M4 ;
        RECT  0 7.728 0.084 7.752 ;
    END
  END o[245]
  PIN o[246]
    DIRECTION OUTPUT ;
    USE SIGNAL ;
    PORT
      LAYER M4 ;
        RECT  0 7.824 0.084 7.848 ;
    END
  END o[246]
  PIN o[247]
    DIRECTION OUTPUT ;
    USE SIGNAL ;
    PORT
      LAYER M4 ;
        RECT  0 7.92 0.084 7.944 ;
    END
  END o[247]
  PIN o[248]
    DIRECTION OUTPUT ;
    USE SIGNAL ;
    PORT
      LAYER M4 ;
        RECT  0 8.016 0.084 8.04 ;
    END
  END o[248]
  PIN o[249]
    DIRECTION OUTPUT ;
    USE SIGNAL ;
    PORT
      LAYER M4 ;
        RECT  0 8.112 0.084 8.136 ;
    END
  END o[249]
  PIN o[24]
    DIRECTION OUTPUT ;
    USE SIGNAL ;
    PORT
      LAYER M4 ;
        RECT  0 62.544 0.084 62.568 ;
    END
  END o[24]
  PIN o[250]
    DIRECTION OUTPUT ;
    USE SIGNAL ;
    PORT
      LAYER M4 ;
        RECT  0 8.208 0.084 8.232 ;
    END
  END o[250]
  PIN o[251]
    DIRECTION OUTPUT ;
    USE SIGNAL ;
    PORT
      LAYER M4 ;
        RECT  0 8.304 0.084 8.328 ;
    END
  END o[251]
  PIN o[252]
    DIRECTION OUTPUT ;
    USE SIGNAL ;
    PORT
      LAYER M4 ;
        RECT  0 8.4 0.084 8.424 ;
    END
  END o[252]
  PIN o[253]
    DIRECTION OUTPUT ;
    USE SIGNAL ;
    PORT
      LAYER M4 ;
        RECT  0 8.496 0.084 8.52 ;
    END
  END o[253]
  PIN o[254]
    DIRECTION OUTPUT ;
    USE SIGNAL ;
    PORT
      LAYER M4 ;
        RECT  0 24.72 0.084 24.744 ;
    END
  END o[254]
  PIN o[255]
    DIRECTION OUTPUT ;
    USE SIGNAL ;
    PORT
      LAYER M4 ;
        RECT  0 24.816 0.084 24.84 ;
    END
  END o[255]
  PIN o[256]
    DIRECTION OUTPUT ;
    USE SIGNAL ;
    PORT
      LAYER M4 ;
        RECT  0 24.912 0.084 24.936 ;
    END
  END o[256]
  PIN o[257]
    DIRECTION OUTPUT ;
    USE SIGNAL ;
    PORT
      LAYER M4 ;
        RECT  0 25.008 0.084 25.032 ;
    END
  END o[257]
  PIN o[258]
    DIRECTION OUTPUT ;
    USE SIGNAL ;
    PORT
      LAYER M4 ;
        RECT  0 25.104 0.084 25.128 ;
    END
  END o[258]
  PIN o[259]
    DIRECTION OUTPUT ;
    USE SIGNAL ;
    PORT
      LAYER M4 ;
        RECT  0 25.2 0.084 25.224 ;
    END
  END o[259]
  PIN o[25]
    DIRECTION OUTPUT ;
    USE SIGNAL ;
    PORT
      LAYER M4 ;
        RECT  0 62.64 0.084 62.664 ;
    END
  END o[25]
  PIN o[260]
    DIRECTION OUTPUT ;
    USE SIGNAL ;
    PORT
      LAYER M4 ;
        RECT  0 25.296 0.084 25.32 ;
    END
  END o[260]
  PIN o[261]
    DIRECTION OUTPUT ;
    USE SIGNAL ;
    PORT
      LAYER M4 ;
        RECT  0 25.392 0.084 25.416 ;
    END
  END o[261]
  PIN o[262]
    DIRECTION OUTPUT ;
    USE SIGNAL ;
    PORT
      LAYER M4 ;
        RECT  0 25.488 0.084 25.512 ;
    END
  END o[262]
  PIN o[263]
    DIRECTION OUTPUT ;
    USE SIGNAL ;
    PORT
      LAYER M4 ;
        RECT  0 25.584 0.084 25.608 ;
    END
  END o[263]
  PIN o[264]
    DIRECTION OUTPUT ;
    USE SIGNAL ;
    PORT
      LAYER M4 ;
        RECT  0 25.68 0.084 25.704 ;
    END
  END o[264]
  PIN o[265]
    DIRECTION OUTPUT ;
    USE SIGNAL ;
    PORT
      LAYER M4 ;
        RECT  0 25.776 0.084 25.8 ;
    END
  END o[265]
  PIN o[266]
    DIRECTION OUTPUT ;
    USE SIGNAL ;
    PORT
      LAYER M4 ;
        RECT  0 25.872 0.084 25.896 ;
    END
  END o[266]
  PIN o[267]
    DIRECTION OUTPUT ;
    USE SIGNAL ;
    PORT
      LAYER M4 ;
        RECT  0 25.968 0.084 25.992 ;
    END
  END o[267]
  PIN o[268]
    DIRECTION OUTPUT ;
    USE SIGNAL ;
    PORT
      LAYER M4 ;
        RECT  0 26.064 0.084 26.088 ;
    END
  END o[268]
  PIN o[269]
    DIRECTION OUTPUT ;
    USE SIGNAL ;
    PORT
      LAYER M4 ;
        RECT  0 26.16 0.084 26.184 ;
    END
  END o[269]
  PIN o[26]
    DIRECTION OUTPUT ;
    USE SIGNAL ;
    PORT
      LAYER M4 ;
        RECT  0 62.736 0.084 62.76 ;
    END
  END o[26]
  PIN o[270]
    DIRECTION OUTPUT ;
    USE SIGNAL ;
    PORT
      LAYER M4 ;
        RECT  0 26.256 0.084 26.28 ;
    END
  END o[270]
  PIN o[271]
    DIRECTION OUTPUT ;
    USE SIGNAL ;
    PORT
      LAYER M4 ;
        RECT  0 26.352 0.084 26.376 ;
    END
  END o[271]
  PIN o[272]
    DIRECTION OUTPUT ;
    USE SIGNAL ;
    PORT
      LAYER M4 ;
        RECT  0 26.448 0.084 26.472 ;
    END
  END o[272]
  PIN o[273]
    DIRECTION OUTPUT ;
    USE SIGNAL ;
    PORT
      LAYER M4 ;
        RECT  0 26.544 0.084 26.568 ;
    END
  END o[273]
  PIN o[274]
    DIRECTION OUTPUT ;
    USE SIGNAL ;
    PORT
      LAYER M4 ;
        RECT  0 26.64 0.084 26.664 ;
    END
  END o[274]
  PIN o[275]
    DIRECTION OUTPUT ;
    USE SIGNAL ;
    PORT
      LAYER M4 ;
        RECT  0 26.736 0.084 26.76 ;
    END
  END o[275]
  PIN o[276]
    DIRECTION OUTPUT ;
    USE SIGNAL ;
    PORT
      LAYER M4 ;
        RECT  0 26.832 0.084 26.856 ;
    END
  END o[276]
  PIN o[277]
    DIRECTION OUTPUT ;
    USE SIGNAL ;
    PORT
      LAYER M4 ;
        RECT  0 26.928 0.084 26.952 ;
    END
  END o[277]
  PIN o[278]
    DIRECTION OUTPUT ;
    USE SIGNAL ;
    PORT
      LAYER M4 ;
        RECT  0 27.024 0.084 27.048 ;
    END
  END o[278]
  PIN o[279]
    DIRECTION OUTPUT ;
    USE SIGNAL ;
    PORT
      LAYER M4 ;
        RECT  0 27.12 0.084 27.144 ;
    END
  END o[279]
  PIN o[27]
    DIRECTION OUTPUT ;
    USE SIGNAL ;
    PORT
      LAYER M4 ;
        RECT  0 62.832 0.084 62.856 ;
    END
  END o[27]
  PIN o[280]
    DIRECTION OUTPUT ;
    USE SIGNAL ;
    PORT
      LAYER M4 ;
        RECT  0 27.216 0.084 27.24 ;
    END
  END o[280]
  PIN o[281]
    DIRECTION OUTPUT ;
    USE SIGNAL ;
    PORT
      LAYER M4 ;
        RECT  0 27.312 0.084 27.336 ;
    END
  END o[281]
  PIN o[282]
    DIRECTION OUTPUT ;
    USE SIGNAL ;
    PORT
      LAYER M4 ;
        RECT  0 27.408 0.084 27.432 ;
    END
  END o[282]
  PIN o[283]
    DIRECTION OUTPUT ;
    USE SIGNAL ;
    PORT
      LAYER M4 ;
        RECT  0 27.504 0.084 27.528 ;
    END
  END o[283]
  PIN o[284]
    DIRECTION OUTPUT ;
    USE SIGNAL ;
    PORT
      LAYER M4 ;
        RECT  0 27.6 0.084 27.624 ;
    END
  END o[284]
  PIN o[285]
    DIRECTION OUTPUT ;
    USE SIGNAL ;
    PORT
      LAYER M4 ;
        RECT  0 27.696 0.084 27.72 ;
    END
  END o[285]
  PIN o[286]
    DIRECTION OUTPUT ;
    USE SIGNAL ;
    PORT
      LAYER M4 ;
        RECT  0 50.064 0.084 50.088 ;
    END
  END o[286]
  PIN o[287]
    DIRECTION OUTPUT ;
    USE SIGNAL ;
    PORT
      LAYER M4 ;
        RECT  0 50.16 0.084 50.184 ;
    END
  END o[287]
  PIN o[288]
    DIRECTION OUTPUT ;
    USE SIGNAL ;
    PORT
      LAYER M4 ;
        RECT  0 50.256 0.084 50.28 ;
    END
  END o[288]
  PIN o[289]
    DIRECTION OUTPUT ;
    USE SIGNAL ;
    PORT
      LAYER M4 ;
        RECT  0 50.352 0.084 50.376 ;
    END
  END o[289]
  PIN o[28]
    DIRECTION OUTPUT ;
    USE SIGNAL ;
    PORT
      LAYER M4 ;
        RECT  0 62.928 0.084 62.952 ;
    END
  END o[28]
  PIN o[290]
    DIRECTION OUTPUT ;
    USE SIGNAL ;
    PORT
      LAYER M4 ;
        RECT  0 50.448 0.084 50.472 ;
    END
  END o[290]
  PIN o[291]
    DIRECTION OUTPUT ;
    USE SIGNAL ;
    PORT
      LAYER M4 ;
        RECT  0 50.544 0.084 50.568 ;
    END
  END o[291]
  PIN o[292]
    DIRECTION OUTPUT ;
    USE SIGNAL ;
    PORT
      LAYER M4 ;
        RECT  0 50.64 0.084 50.664 ;
    END
  END o[292]
  PIN o[293]
    DIRECTION OUTPUT ;
    USE SIGNAL ;
    PORT
      LAYER M4 ;
        RECT  0 50.736 0.084 50.76 ;
    END
  END o[293]
  PIN o[294]
    DIRECTION OUTPUT ;
    USE SIGNAL ;
    PORT
      LAYER M4 ;
        RECT  0 50.832 0.084 50.856 ;
    END
  END o[294]
  PIN o[295]
    DIRECTION OUTPUT ;
    USE SIGNAL ;
    PORT
      LAYER M4 ;
        RECT  0 50.928 0.084 50.952 ;
    END
  END o[295]
  PIN o[296]
    DIRECTION OUTPUT ;
    USE SIGNAL ;
    PORT
      LAYER M4 ;
        RECT  0 51.024 0.084 51.048 ;
    END
  END o[296]
  PIN o[297]
    DIRECTION OUTPUT ;
    USE SIGNAL ;
    PORT
      LAYER M4 ;
        RECT  0 51.12 0.084 51.144 ;
    END
  END o[297]
  PIN o[298]
    DIRECTION OUTPUT ;
    USE SIGNAL ;
    PORT
      LAYER M4 ;
        RECT  0 51.216 0.084 51.24 ;
    END
  END o[298]
  PIN o[299]
    DIRECTION OUTPUT ;
    USE SIGNAL ;
    PORT
      LAYER M4 ;
        RECT  0 51.312 0.084 51.336 ;
    END
  END o[299]
  PIN o[29]
    DIRECTION OUTPUT ;
    USE SIGNAL ;
    PORT
      LAYER M4 ;
        RECT  0 63.024 0.084 63.048 ;
    END
  END o[29]
  PIN o[2]
    DIRECTION OUTPUT ;
    USE SIGNAL ;
    PORT
      LAYER M4 ;
        RECT  0 60.432 0.084 60.456 ;
    END
  END o[2]
  PIN o[300]
    DIRECTION OUTPUT ;
    USE SIGNAL ;
    PORT
      LAYER M4 ;
        RECT  0 51.408 0.084 51.432 ;
    END
  END o[300]
  PIN o[301]
    DIRECTION OUTPUT ;
    USE SIGNAL ;
    PORT
      LAYER M4 ;
        RECT  0 51.504 0.084 51.528 ;
    END
  END o[301]
  PIN o[302]
    DIRECTION OUTPUT ;
    USE SIGNAL ;
    PORT
      LAYER M4 ;
        RECT  0 51.6 0.084 51.624 ;
    END
  END o[302]
  PIN o[303]
    DIRECTION OUTPUT ;
    USE SIGNAL ;
    PORT
      LAYER M4 ;
        RECT  0 51.696 0.084 51.72 ;
    END
  END o[303]
  PIN o[304]
    DIRECTION OUTPUT ;
    USE SIGNAL ;
    PORT
      LAYER M4 ;
        RECT  0 51.792 0.084 51.816 ;
    END
  END o[304]
  PIN o[305]
    DIRECTION OUTPUT ;
    USE SIGNAL ;
    PORT
      LAYER M4 ;
        RECT  0 51.888 0.084 51.912 ;
    END
  END o[305]
  PIN o[306]
    DIRECTION OUTPUT ;
    USE SIGNAL ;
    PORT
      LAYER M4 ;
        RECT  0 51.984 0.084 52.008 ;
    END
  END o[306]
  PIN o[307]
    DIRECTION OUTPUT ;
    USE SIGNAL ;
    PORT
      LAYER M4 ;
        RECT  0 52.08 0.084 52.104 ;
    END
  END o[307]
  PIN o[308]
    DIRECTION OUTPUT ;
    USE SIGNAL ;
    PORT
      LAYER M4 ;
        RECT  0 52.176 0.084 52.2 ;
    END
  END o[308]
  PIN o[309]
    DIRECTION OUTPUT ;
    USE SIGNAL ;
    PORT
      LAYER M4 ;
        RECT  0 52.272 0.084 52.296 ;
    END
  END o[309]
  PIN o[30]
    DIRECTION OUTPUT ;
    USE SIGNAL ;
    PORT
      LAYER M4 ;
        RECT  0 88.464 0.084 88.488 ;
    END
  END o[30]
  PIN o[310]
    DIRECTION OUTPUT ;
    USE SIGNAL ;
    PORT
      LAYER M4 ;
        RECT  0 52.368 0.084 52.392 ;
    END
  END o[310]
  PIN o[311]
    DIRECTION OUTPUT ;
    USE SIGNAL ;
    PORT
      LAYER M4 ;
        RECT  0 52.464 0.084 52.488 ;
    END
  END o[311]
  PIN o[312]
    DIRECTION OUTPUT ;
    USE SIGNAL ;
    PORT
      LAYER M4 ;
        RECT  0 52.56 0.084 52.584 ;
    END
  END o[312]
  PIN o[313]
    DIRECTION OUTPUT ;
    USE SIGNAL ;
    PORT
      LAYER M4 ;
        RECT  0 52.656 0.084 52.68 ;
    END
  END o[313]
  PIN o[314]
    DIRECTION OUTPUT ;
    USE SIGNAL ;
    PORT
      LAYER M4 ;
        RECT  0 52.752 0.084 52.776 ;
    END
  END o[314]
  PIN o[315]
    DIRECTION OUTPUT ;
    USE SIGNAL ;
    PORT
      LAYER M4 ;
        RECT  0 52.848 0.084 52.872 ;
    END
  END o[315]
  PIN o[316]
    DIRECTION OUTPUT ;
    USE SIGNAL ;
    PORT
      LAYER M4 ;
        RECT  0 52.944 0.084 52.968 ;
    END
  END o[316]
  PIN o[317]
    DIRECTION OUTPUT ;
    USE SIGNAL ;
    PORT
      LAYER M4 ;
        RECT  0 53.04 0.084 53.064 ;
    END
  END o[317]
  PIN o[318]
    DIRECTION OUTPUT ;
    USE SIGNAL ;
    PORT
      LAYER M4 ;
        RECT  0 72.336 0.084 72.36 ;
    END
  END o[318]
  PIN o[319]
    DIRECTION OUTPUT ;
    USE SIGNAL ;
    PORT
      LAYER M4 ;
        RECT  0 72.432 0.084 72.456 ;
    END
  END o[319]
  PIN o[31]
    DIRECTION OUTPUT ;
    USE SIGNAL ;
    PORT
      LAYER M4 ;
        RECT  0 88.56 0.084 88.584 ;
    END
  END o[31]
  PIN o[320]
    DIRECTION OUTPUT ;
    USE SIGNAL ;
    PORT
      LAYER M4 ;
        RECT  0 72.528 0.084 72.552 ;
    END
  END o[320]
  PIN o[321]
    DIRECTION OUTPUT ;
    USE SIGNAL ;
    PORT
      LAYER M4 ;
        RECT  0 72.624 0.084 72.648 ;
    END
  END o[321]
  PIN o[322]
    DIRECTION OUTPUT ;
    USE SIGNAL ;
    PORT
      LAYER M4 ;
        RECT  0 72.72 0.084 72.744 ;
    END
  END o[322]
  PIN o[323]
    DIRECTION OUTPUT ;
    USE SIGNAL ;
    PORT
      LAYER M4 ;
        RECT  0 72.816 0.084 72.84 ;
    END
  END o[323]
  PIN o[324]
    DIRECTION OUTPUT ;
    USE SIGNAL ;
    PORT
      LAYER M4 ;
        RECT  0 72.912 0.084 72.936 ;
    END
  END o[324]
  PIN o[325]
    DIRECTION OUTPUT ;
    USE SIGNAL ;
    PORT
      LAYER M4 ;
        RECT  0 73.008 0.084 73.032 ;
    END
  END o[325]
  PIN o[326]
    DIRECTION OUTPUT ;
    USE SIGNAL ;
    PORT
      LAYER M4 ;
        RECT  0 73.104 0.084 73.128 ;
    END
  END o[326]
  PIN o[327]
    DIRECTION OUTPUT ;
    USE SIGNAL ;
    PORT
      LAYER M4 ;
        RECT  0 73.2 0.084 73.224 ;
    END
  END o[327]
  PIN o[328]
    DIRECTION OUTPUT ;
    USE SIGNAL ;
    PORT
      LAYER M4 ;
        RECT  0 73.296 0.084 73.32 ;
    END
  END o[328]
  PIN o[329]
    DIRECTION OUTPUT ;
    USE SIGNAL ;
    PORT
      LAYER M4 ;
        RECT  0 73.392 0.084 73.416 ;
    END
  END o[329]
  PIN o[32]
    DIRECTION OUTPUT ;
    USE SIGNAL ;
    PORT
      LAYER M4 ;
        RECT  0 88.656 0.084 88.68 ;
    END
  END o[32]
  PIN o[330]
    DIRECTION OUTPUT ;
    USE SIGNAL ;
    PORT
      LAYER M4 ;
        RECT  0 73.488 0.084 73.512 ;
    END
  END o[330]
  PIN o[331]
    DIRECTION OUTPUT ;
    USE SIGNAL ;
    PORT
      LAYER M4 ;
        RECT  0 73.584 0.084 73.608 ;
    END
  END o[331]
  PIN o[332]
    DIRECTION OUTPUT ;
    USE SIGNAL ;
    PORT
      LAYER M4 ;
        RECT  0 73.68 0.084 73.704 ;
    END
  END o[332]
  PIN o[333]
    DIRECTION OUTPUT ;
    USE SIGNAL ;
    PORT
      LAYER M4 ;
        RECT  0 73.776 0.084 73.8 ;
    END
  END o[333]
  PIN o[334]
    DIRECTION OUTPUT ;
    USE SIGNAL ;
    PORT
      LAYER M4 ;
        RECT  0 73.872 0.084 73.896 ;
    END
  END o[334]
  PIN o[335]
    DIRECTION OUTPUT ;
    USE SIGNAL ;
    PORT
      LAYER M4 ;
        RECT  0 73.968 0.084 73.992 ;
    END
  END o[335]
  PIN o[336]
    DIRECTION OUTPUT ;
    USE SIGNAL ;
    PORT
      LAYER M4 ;
        RECT  0 74.064 0.084 74.088 ;
    END
  END o[336]
  PIN o[337]
    DIRECTION OUTPUT ;
    USE SIGNAL ;
    PORT
      LAYER M4 ;
        RECT  0 74.16 0.084 74.184 ;
    END
  END o[337]
  PIN o[338]
    DIRECTION OUTPUT ;
    USE SIGNAL ;
    PORT
      LAYER M4 ;
        RECT  0 74.256 0.084 74.28 ;
    END
  END o[338]
  PIN o[339]
    DIRECTION OUTPUT ;
    USE SIGNAL ;
    PORT
      LAYER M4 ;
        RECT  0 74.352 0.084 74.376 ;
    END
  END o[339]
  PIN o[33]
    DIRECTION OUTPUT ;
    USE SIGNAL ;
    PORT
      LAYER M4 ;
        RECT  0 88.752 0.084 88.776 ;
    END
  END o[33]
  PIN o[340]
    DIRECTION OUTPUT ;
    USE SIGNAL ;
    PORT
      LAYER M4 ;
        RECT  0 74.448 0.084 74.472 ;
    END
  END o[340]
  PIN o[341]
    DIRECTION OUTPUT ;
    USE SIGNAL ;
    PORT
      LAYER M4 ;
        RECT  0 74.544 0.084 74.568 ;
    END
  END o[341]
  PIN o[342]
    DIRECTION OUTPUT ;
    USE SIGNAL ;
    PORT
      LAYER M4 ;
        RECT  0 74.64 0.084 74.664 ;
    END
  END o[342]
  PIN o[343]
    DIRECTION OUTPUT ;
    USE SIGNAL ;
    PORT
      LAYER M4 ;
        RECT  0 74.736 0.084 74.76 ;
    END
  END o[343]
  PIN o[344]
    DIRECTION OUTPUT ;
    USE SIGNAL ;
    PORT
      LAYER M4 ;
        RECT  0 74.832 0.084 74.856 ;
    END
  END o[344]
  PIN o[345]
    DIRECTION OUTPUT ;
    USE SIGNAL ;
    PORT
      LAYER M4 ;
        RECT  0 74.928 0.084 74.952 ;
    END
  END o[345]
  PIN o[346]
    DIRECTION OUTPUT ;
    USE SIGNAL ;
    PORT
      LAYER M4 ;
        RECT  0 75.024 0.084 75.048 ;
    END
  END o[346]
  PIN o[347]
    DIRECTION OUTPUT ;
    USE SIGNAL ;
    PORT
      LAYER M4 ;
        RECT  0 75.12 0.084 75.144 ;
    END
  END o[347]
  PIN o[348]
    DIRECTION OUTPUT ;
    USE SIGNAL ;
    PORT
      LAYER M4 ;
        RECT  0 75.216 0.084 75.24 ;
    END
  END o[348]
  PIN o[349]
    DIRECTION OUTPUT ;
    USE SIGNAL ;
    PORT
      LAYER M4 ;
        RECT  0 75.312 0.084 75.336 ;
    END
  END o[349]
  PIN o[34]
    DIRECTION OUTPUT ;
    USE SIGNAL ;
    PORT
      LAYER M4 ;
        RECT  0 88.848 0.084 88.872 ;
    END
  END o[34]
  PIN o[350]
    DIRECTION OUTPUT ;
    USE SIGNAL ;
    PORT
      LAYER M4 ;
        RECT  0 95.376 0.084 95.4 ;
    END
  END o[350]
  PIN o[351]
    DIRECTION OUTPUT ;
    USE SIGNAL ;
    PORT
      LAYER M4 ;
        RECT  0 95.472 0.084 95.496 ;
    END
  END o[351]
  PIN o[352]
    DIRECTION OUTPUT ;
    USE SIGNAL ;
    PORT
      LAYER M4 ;
        RECT  0 95.568 0.084 95.592 ;
    END
  END o[352]
  PIN o[353]
    DIRECTION OUTPUT ;
    USE SIGNAL ;
    PORT
      LAYER M4 ;
        RECT  0 95.664 0.084 95.688 ;
    END
  END o[353]
  PIN o[354]
    DIRECTION OUTPUT ;
    USE SIGNAL ;
    PORT
      LAYER M4 ;
        RECT  0 95.76 0.084 95.784 ;
    END
  END o[354]
  PIN o[355]
    DIRECTION OUTPUT ;
    USE SIGNAL ;
    PORT
      LAYER M4 ;
        RECT  0 95.856 0.084 95.88 ;
    END
  END o[355]
  PIN o[356]
    DIRECTION OUTPUT ;
    USE SIGNAL ;
    PORT
      LAYER M4 ;
        RECT  0 95.952 0.084 95.976 ;
    END
  END o[356]
  PIN o[357]
    DIRECTION OUTPUT ;
    USE SIGNAL ;
    PORT
      LAYER M4 ;
        RECT  0 96.048 0.084 96.072 ;
    END
  END o[357]
  PIN o[358]
    DIRECTION OUTPUT ;
    USE SIGNAL ;
    PORT
      LAYER M4 ;
        RECT  0 96.144 0.084 96.168 ;
    END
  END o[358]
  PIN o[359]
    DIRECTION OUTPUT ;
    USE SIGNAL ;
    PORT
      LAYER M4 ;
        RECT  0 96.24 0.084 96.264 ;
    END
  END o[359]
  PIN o[35]
    DIRECTION OUTPUT ;
    USE SIGNAL ;
    PORT
      LAYER M4 ;
        RECT  0 88.944 0.084 88.968 ;
    END
  END o[35]
  PIN o[360]
    DIRECTION OUTPUT ;
    USE SIGNAL ;
    PORT
      LAYER M4 ;
        RECT  0 96.336 0.084 96.36 ;
    END
  END o[360]
  PIN o[361]
    DIRECTION OUTPUT ;
    USE SIGNAL ;
    PORT
      LAYER M4 ;
        RECT  0 96.432 0.084 96.456 ;
    END
  END o[361]
  PIN o[362]
    DIRECTION OUTPUT ;
    USE SIGNAL ;
    PORT
      LAYER M4 ;
        RECT  0 96.528 0.084 96.552 ;
    END
  END o[362]
  PIN o[363]
    DIRECTION OUTPUT ;
    USE SIGNAL ;
    PORT
      LAYER M4 ;
        RECT  0 96.624 0.084 96.648 ;
    END
  END o[363]
  PIN o[364]
    DIRECTION OUTPUT ;
    USE SIGNAL ;
    PORT
      LAYER M4 ;
        RECT  0 96.72 0.084 96.744 ;
    END
  END o[364]
  PIN o[365]
    DIRECTION OUTPUT ;
    USE SIGNAL ;
    PORT
      LAYER M4 ;
        RECT  0 96.816 0.084 96.84 ;
    END
  END o[365]
  PIN o[366]
    DIRECTION OUTPUT ;
    USE SIGNAL ;
    PORT
      LAYER M4 ;
        RECT  0 96.912 0.084 96.936 ;
    END
  END o[366]
  PIN o[367]
    DIRECTION OUTPUT ;
    USE SIGNAL ;
    PORT
      LAYER M4 ;
        RECT  0 97.008 0.084 97.032 ;
    END
  END o[367]
  PIN o[368]
    DIRECTION OUTPUT ;
    USE SIGNAL ;
    PORT
      LAYER M4 ;
        RECT  0 97.104 0.084 97.128 ;
    END
  END o[368]
  PIN o[369]
    DIRECTION OUTPUT ;
    USE SIGNAL ;
    PORT
      LAYER M4 ;
        RECT  0 97.2 0.084 97.224 ;
    END
  END o[369]
  PIN o[36]
    DIRECTION OUTPUT ;
    USE SIGNAL ;
    PORT
      LAYER M4 ;
        RECT  0 89.04 0.084 89.064 ;
    END
  END o[36]
  PIN o[370]
    DIRECTION OUTPUT ;
    USE SIGNAL ;
    PORT
      LAYER M4 ;
        RECT  0 97.296 0.084 97.32 ;
    END
  END o[370]
  PIN o[371]
    DIRECTION OUTPUT ;
    USE SIGNAL ;
    PORT
      LAYER M4 ;
        RECT  0 97.392 0.084 97.416 ;
    END
  END o[371]
  PIN o[372]
    DIRECTION OUTPUT ;
    USE SIGNAL ;
    PORT
      LAYER M4 ;
        RECT  0 97.488 0.084 97.512 ;
    END
  END o[372]
  PIN o[373]
    DIRECTION OUTPUT ;
    USE SIGNAL ;
    PORT
      LAYER M4 ;
        RECT  0 97.584 0.084 97.608 ;
    END
  END o[373]
  PIN o[374]
    DIRECTION OUTPUT ;
    USE SIGNAL ;
    PORT
      LAYER M4 ;
        RECT  0 97.68 0.084 97.704 ;
    END
  END o[374]
  PIN o[375]
    DIRECTION OUTPUT ;
    USE SIGNAL ;
    PORT
      LAYER M4 ;
        RECT  0 97.776 0.084 97.8 ;
    END
  END o[375]
  PIN o[376]
    DIRECTION OUTPUT ;
    USE SIGNAL ;
    PORT
      LAYER M4 ;
        RECT  0 97.872 0.084 97.896 ;
    END
  END o[376]
  PIN o[377]
    DIRECTION OUTPUT ;
    USE SIGNAL ;
    PORT
      LAYER M4 ;
        RECT  0 97.968 0.084 97.992 ;
    END
  END o[377]
  PIN o[378]
    DIRECTION OUTPUT ;
    USE SIGNAL ;
    PORT
      LAYER M4 ;
        RECT  0 98.064 0.084 98.088 ;
    END
  END o[378]
  PIN o[379]
    DIRECTION OUTPUT ;
    USE SIGNAL ;
    PORT
      LAYER M4 ;
        RECT  0 98.16 0.084 98.184 ;
    END
  END o[379]
  PIN o[37]
    DIRECTION OUTPUT ;
    USE SIGNAL ;
    PORT
      LAYER M4 ;
        RECT  0 89.136 0.084 89.16 ;
    END
  END o[37]
  PIN o[380]
    DIRECTION OUTPUT ;
    USE SIGNAL ;
    PORT
      LAYER M4 ;
        RECT  0 98.256 0.084 98.28 ;
    END
  END o[380]
  PIN o[381]
    DIRECTION OUTPUT ;
    USE SIGNAL ;
    PORT
      LAYER M4 ;
        RECT  0 98.352 0.084 98.376 ;
    END
  END o[381]
  PIN o[382]
    DIRECTION OUTPUT ;
    USE SIGNAL ;
    PORT
      LAYER M4 ;
        RECT  0 104.592 0.084 104.616 ;
    END
  END o[382]
  PIN o[383]
    DIRECTION OUTPUT ;
    USE SIGNAL ;
    PORT
      LAYER M4 ;
        RECT  0 104.688 0.084 104.712 ;
    END
  END o[383]
  PIN o[384]
    DIRECTION OUTPUT ;
    USE SIGNAL ;
    PORT
      LAYER M4 ;
        RECT  0 104.784 0.084 104.808 ;
    END
  END o[384]
  PIN o[385]
    DIRECTION OUTPUT ;
    USE SIGNAL ;
    PORT
      LAYER M4 ;
        RECT  0 104.88 0.084 104.904 ;
    END
  END o[385]
  PIN o[386]
    DIRECTION OUTPUT ;
    USE SIGNAL ;
    PORT
      LAYER M4 ;
        RECT  0 104.976 0.084 105 ;
    END
  END o[386]
  PIN o[387]
    DIRECTION OUTPUT ;
    USE SIGNAL ;
    PORT
      LAYER M4 ;
        RECT  0 105.072 0.084 105.096 ;
    END
  END o[387]
  PIN o[388]
    DIRECTION OUTPUT ;
    USE SIGNAL ;
    PORT
      LAYER M4 ;
        RECT  0 105.168 0.084 105.192 ;
    END
  END o[388]
  PIN o[389]
    DIRECTION OUTPUT ;
    USE SIGNAL ;
    PORT
      LAYER M4 ;
        RECT  0 105.264 0.084 105.288 ;
    END
  END o[389]
  PIN o[38]
    DIRECTION OUTPUT ;
    USE SIGNAL ;
    PORT
      LAYER M4 ;
        RECT  0 89.232 0.084 89.256 ;
    END
  END o[38]
  PIN o[390]
    DIRECTION OUTPUT ;
    USE SIGNAL ;
    PORT
      LAYER M4 ;
        RECT  0 105.36 0.084 105.384 ;
    END
  END o[390]
  PIN o[391]
    DIRECTION OUTPUT ;
    USE SIGNAL ;
    PORT
      LAYER M4 ;
        RECT  0 105.456 0.084 105.48 ;
    END
  END o[391]
  PIN o[392]
    DIRECTION OUTPUT ;
    USE SIGNAL ;
    PORT
      LAYER M4 ;
        RECT  0 105.552 0.084 105.576 ;
    END
  END o[392]
  PIN o[393]
    DIRECTION OUTPUT ;
    USE SIGNAL ;
    PORT
      LAYER M4 ;
        RECT  0 105.648 0.084 105.672 ;
    END
  END o[393]
  PIN o[394]
    DIRECTION OUTPUT ;
    USE SIGNAL ;
    PORT
      LAYER M4 ;
        RECT  0 105.744 0.084 105.768 ;
    END
  END o[394]
  PIN o[395]
    DIRECTION OUTPUT ;
    USE SIGNAL ;
    PORT
      LAYER M4 ;
        RECT  0 105.84 0.084 105.864 ;
    END
  END o[395]
  PIN o[396]
    DIRECTION OUTPUT ;
    USE SIGNAL ;
    PORT
      LAYER M4 ;
        RECT  0 105.936 0.084 105.96 ;
    END
  END o[396]
  PIN o[397]
    DIRECTION OUTPUT ;
    USE SIGNAL ;
    PORT
      LAYER M4 ;
        RECT  0 106.032 0.084 106.056 ;
    END
  END o[397]
  PIN o[398]
    DIRECTION OUTPUT ;
    USE SIGNAL ;
    PORT
      LAYER M4 ;
        RECT  0 106.128 0.084 106.152 ;
    END
  END o[398]
  PIN o[399]
    DIRECTION OUTPUT ;
    USE SIGNAL ;
    PORT
      LAYER M4 ;
        RECT  0 106.224 0.084 106.248 ;
    END
  END o[399]
  PIN o[39]
    DIRECTION OUTPUT ;
    USE SIGNAL ;
    PORT
      LAYER M4 ;
        RECT  0 89.328 0.084 89.352 ;
    END
  END o[39]
  PIN o[3]
    DIRECTION OUTPUT ;
    USE SIGNAL ;
    PORT
      LAYER M4 ;
        RECT  0 60.528 0.084 60.552 ;
    END
  END o[3]
  PIN o[400]
    DIRECTION OUTPUT ;
    USE SIGNAL ;
    PORT
      LAYER M4 ;
        RECT  0 106.32 0.084 106.344 ;
    END
  END o[400]
  PIN o[401]
    DIRECTION OUTPUT ;
    USE SIGNAL ;
    PORT
      LAYER M4 ;
        RECT  0 106.416 0.084 106.44 ;
    END
  END o[401]
  PIN o[402]
    DIRECTION OUTPUT ;
    USE SIGNAL ;
    PORT
      LAYER M4 ;
        RECT  0 106.512 0.084 106.536 ;
    END
  END o[402]
  PIN o[403]
    DIRECTION OUTPUT ;
    USE SIGNAL ;
    PORT
      LAYER M4 ;
        RECT  0 106.608 0.084 106.632 ;
    END
  END o[403]
  PIN o[404]
    DIRECTION OUTPUT ;
    USE SIGNAL ;
    PORT
      LAYER M4 ;
        RECT  0 106.704 0.084 106.728 ;
    END
  END o[404]
  PIN o[405]
    DIRECTION OUTPUT ;
    USE SIGNAL ;
    PORT
      LAYER M4 ;
        RECT  0 106.8 0.084 106.824 ;
    END
  END o[405]
  PIN o[406]
    DIRECTION OUTPUT ;
    USE SIGNAL ;
    PORT
      LAYER M4 ;
        RECT  0 106.896 0.084 106.92 ;
    END
  END o[406]
  PIN o[407]
    DIRECTION OUTPUT ;
    USE SIGNAL ;
    PORT
      LAYER M4 ;
        RECT  0 106.992 0.084 107.016 ;
    END
  END o[407]
  PIN o[408]
    DIRECTION OUTPUT ;
    USE SIGNAL ;
    PORT
      LAYER M4 ;
        RECT  0 107.088 0.084 107.112 ;
    END
  END o[408]
  PIN o[409]
    DIRECTION OUTPUT ;
    USE SIGNAL ;
    PORT
      LAYER M4 ;
        RECT  0 107.184 0.084 107.208 ;
    END
  END o[409]
  PIN o[40]
    DIRECTION OUTPUT ;
    USE SIGNAL ;
    PORT
      LAYER M4 ;
        RECT  0 89.424 0.084 89.448 ;
    END
  END o[40]
  PIN o[410]
    DIRECTION OUTPUT ;
    USE SIGNAL ;
    PORT
      LAYER M4 ;
        RECT  0 107.28 0.084 107.304 ;
    END
  END o[410]
  PIN o[411]
    DIRECTION OUTPUT ;
    USE SIGNAL ;
    PORT
      LAYER M4 ;
        RECT  0 107.376 0.084 107.4 ;
    END
  END o[411]
  PIN o[412]
    DIRECTION OUTPUT ;
    USE SIGNAL ;
    PORT
      LAYER M4 ;
        RECT  0 107.472 0.084 107.496 ;
    END
  END o[412]
  PIN o[413]
    DIRECTION OUTPUT ;
    USE SIGNAL ;
    PORT
      LAYER M4 ;
        RECT  0 107.568 0.084 107.592 ;
    END
  END o[413]
  PIN o[414]
    DIRECTION OUTPUT ;
    USE SIGNAL ;
    PORT
      LAYER M4 ;
        RECT  0 98.448 0.084 98.472 ;
    END
  END o[414]
  PIN o[415]
    DIRECTION OUTPUT ;
    USE SIGNAL ;
    PORT
      LAYER M4 ;
        RECT  0 98.544 0.084 98.568 ;
    END
  END o[415]
  PIN o[416]
    DIRECTION OUTPUT ;
    USE SIGNAL ;
    PORT
      LAYER M4 ;
        RECT  0 98.64 0.084 98.664 ;
    END
  END o[416]
  PIN o[417]
    DIRECTION OUTPUT ;
    USE SIGNAL ;
    PORT
      LAYER M4 ;
        RECT  0 98.736 0.084 98.76 ;
    END
  END o[417]
  PIN o[418]
    DIRECTION OUTPUT ;
    USE SIGNAL ;
    PORT
      LAYER M4 ;
        RECT  0 98.832 0.084 98.856 ;
    END
  END o[418]
  PIN o[419]
    DIRECTION OUTPUT ;
    USE SIGNAL ;
    PORT
      LAYER M4 ;
        RECT  0 98.928 0.084 98.952 ;
    END
  END o[419]
  PIN o[41]
    DIRECTION OUTPUT ;
    USE SIGNAL ;
    PORT
      LAYER M4 ;
        RECT  0 89.52 0.084 89.544 ;
    END
  END o[41]
  PIN o[420]
    DIRECTION OUTPUT ;
    USE SIGNAL ;
    PORT
      LAYER M4 ;
        RECT  0 99.024 0.084 99.048 ;
    END
  END o[420]
  PIN o[421]
    DIRECTION OUTPUT ;
    USE SIGNAL ;
    PORT
      LAYER M4 ;
        RECT  0 99.12 0.084 99.144 ;
    END
  END o[421]
  PIN o[422]
    DIRECTION OUTPUT ;
    USE SIGNAL ;
    PORT
      LAYER M4 ;
        RECT  0 99.216 0.084 99.24 ;
    END
  END o[422]
  PIN o[423]
    DIRECTION OUTPUT ;
    USE SIGNAL ;
    PORT
      LAYER M4 ;
        RECT  0 99.312 0.084 99.336 ;
    END
  END o[423]
  PIN o[424]
    DIRECTION OUTPUT ;
    USE SIGNAL ;
    PORT
      LAYER M4 ;
        RECT  0 99.408 0.084 99.432 ;
    END
  END o[424]
  PIN o[425]
    DIRECTION OUTPUT ;
    USE SIGNAL ;
    PORT
      LAYER M4 ;
        RECT  0 99.504 0.084 99.528 ;
    END
  END o[425]
  PIN o[426]
    DIRECTION OUTPUT ;
    USE SIGNAL ;
    PORT
      LAYER M4 ;
        RECT  0 99.6 0.084 99.624 ;
    END
  END o[426]
  PIN o[427]
    DIRECTION OUTPUT ;
    USE SIGNAL ;
    PORT
      LAYER M4 ;
        RECT  0 99.696 0.084 99.72 ;
    END
  END o[427]
  PIN o[428]
    DIRECTION OUTPUT ;
    USE SIGNAL ;
    PORT
      LAYER M4 ;
        RECT  0 99.792 0.084 99.816 ;
    END
  END o[428]
  PIN o[429]
    DIRECTION OUTPUT ;
    USE SIGNAL ;
    PORT
      LAYER M4 ;
        RECT  0 99.888 0.084 99.912 ;
    END
  END o[429]
  PIN o[42]
    DIRECTION OUTPUT ;
    USE SIGNAL ;
    PORT
      LAYER M4 ;
        RECT  0 89.616 0.084 89.64 ;
    END
  END o[42]
  PIN o[430]
    DIRECTION OUTPUT ;
    USE SIGNAL ;
    PORT
      LAYER M4 ;
        RECT  0 99.984 0.084 100.008 ;
    END
  END o[430]
  PIN o[431]
    DIRECTION OUTPUT ;
    USE SIGNAL ;
    PORT
      LAYER M4 ;
        RECT  0 100.08 0.084 100.104 ;
    END
  END o[431]
  PIN o[432]
    DIRECTION OUTPUT ;
    USE SIGNAL ;
    PORT
      LAYER M4 ;
        RECT  0 100.176 0.084 100.2 ;
    END
  END o[432]
  PIN o[433]
    DIRECTION OUTPUT ;
    USE SIGNAL ;
    PORT
      LAYER M4 ;
        RECT  0 100.272 0.084 100.296 ;
    END
  END o[433]
  PIN o[434]
    DIRECTION OUTPUT ;
    USE SIGNAL ;
    PORT
      LAYER M4 ;
        RECT  0 100.368 0.084 100.392 ;
    END
  END o[434]
  PIN o[435]
    DIRECTION OUTPUT ;
    USE SIGNAL ;
    PORT
      LAYER M4 ;
        RECT  0 100.464 0.084 100.488 ;
    END
  END o[435]
  PIN o[436]
    DIRECTION OUTPUT ;
    USE SIGNAL ;
    PORT
      LAYER M4 ;
        RECT  0 100.56 0.084 100.584 ;
    END
  END o[436]
  PIN o[437]
    DIRECTION OUTPUT ;
    USE SIGNAL ;
    PORT
      LAYER M4 ;
        RECT  0 100.656 0.084 100.68 ;
    END
  END o[437]
  PIN o[438]
    DIRECTION OUTPUT ;
    USE SIGNAL ;
    PORT
      LAYER M4 ;
        RECT  0 100.752 0.084 100.776 ;
    END
  END o[438]
  PIN o[439]
    DIRECTION OUTPUT ;
    USE SIGNAL ;
    PORT
      LAYER M4 ;
        RECT  0 100.848 0.084 100.872 ;
    END
  END o[439]
  PIN o[43]
    DIRECTION OUTPUT ;
    USE SIGNAL ;
    PORT
      LAYER M4 ;
        RECT  0 89.712 0.084 89.736 ;
    END
  END o[43]
  PIN o[440]
    DIRECTION OUTPUT ;
    USE SIGNAL ;
    PORT
      LAYER M4 ;
        RECT  0 100.944 0.084 100.968 ;
    END
  END o[440]
  PIN o[441]
    DIRECTION OUTPUT ;
    USE SIGNAL ;
    PORT
      LAYER M4 ;
        RECT  0 101.04 0.084 101.064 ;
    END
  END o[441]
  PIN o[442]
    DIRECTION OUTPUT ;
    USE SIGNAL ;
    PORT
      LAYER M4 ;
        RECT  0 101.136 0.084 101.16 ;
    END
  END o[442]
  PIN o[443]
    DIRECTION OUTPUT ;
    USE SIGNAL ;
    PORT
      LAYER M4 ;
        RECT  0 101.232 0.084 101.256 ;
    END
  END o[443]
  PIN o[444]
    DIRECTION OUTPUT ;
    USE SIGNAL ;
    PORT
      LAYER M4 ;
        RECT  0 101.328 0.084 101.352 ;
    END
  END o[444]
  PIN o[445]
    DIRECTION OUTPUT ;
    USE SIGNAL ;
    PORT
      LAYER M4 ;
        RECT  0 101.424 0.084 101.448 ;
    END
  END o[445]
  PIN o[446]
    DIRECTION OUTPUT ;
    USE SIGNAL ;
    PORT
      LAYER M4 ;
        RECT  0 85.392 0.084 85.416 ;
    END
  END o[446]
  PIN o[447]
    DIRECTION OUTPUT ;
    USE SIGNAL ;
    PORT
      LAYER M4 ;
        RECT  0 85.488 0.084 85.512 ;
    END
  END o[447]
  PIN o[448]
    DIRECTION OUTPUT ;
    USE SIGNAL ;
    PORT
      LAYER M4 ;
        RECT  0 85.584 0.084 85.608 ;
    END
  END o[448]
  PIN o[449]
    DIRECTION OUTPUT ;
    USE SIGNAL ;
    PORT
      LAYER M4 ;
        RECT  0 85.68 0.084 85.704 ;
    END
  END o[449]
  PIN o[44]
    DIRECTION OUTPUT ;
    USE SIGNAL ;
    PORT
      LAYER M4 ;
        RECT  0 89.808 0.084 89.832 ;
    END
  END o[44]
  PIN o[450]
    DIRECTION OUTPUT ;
    USE SIGNAL ;
    PORT
      LAYER M4 ;
        RECT  0 85.776 0.084 85.8 ;
    END
  END o[450]
  PIN o[451]
    DIRECTION OUTPUT ;
    USE SIGNAL ;
    PORT
      LAYER M4 ;
        RECT  0 85.872 0.084 85.896 ;
    END
  END o[451]
  PIN o[452]
    DIRECTION OUTPUT ;
    USE SIGNAL ;
    PORT
      LAYER M4 ;
        RECT  0 85.968 0.084 85.992 ;
    END
  END o[452]
  PIN o[453]
    DIRECTION OUTPUT ;
    USE SIGNAL ;
    PORT
      LAYER M4 ;
        RECT  0 86.064 0.084 86.088 ;
    END
  END o[453]
  PIN o[454]
    DIRECTION OUTPUT ;
    USE SIGNAL ;
    PORT
      LAYER M4 ;
        RECT  0 86.16 0.084 86.184 ;
    END
  END o[454]
  PIN o[455]
    DIRECTION OUTPUT ;
    USE SIGNAL ;
    PORT
      LAYER M4 ;
        RECT  0 86.256 0.084 86.28 ;
    END
  END o[455]
  PIN o[456]
    DIRECTION OUTPUT ;
    USE SIGNAL ;
    PORT
      LAYER M4 ;
        RECT  0 86.352 0.084 86.376 ;
    END
  END o[456]
  PIN o[457]
    DIRECTION OUTPUT ;
    USE SIGNAL ;
    PORT
      LAYER M4 ;
        RECT  0 86.448 0.084 86.472 ;
    END
  END o[457]
  PIN o[458]
    DIRECTION OUTPUT ;
    USE SIGNAL ;
    PORT
      LAYER M4 ;
        RECT  0 86.544 0.084 86.568 ;
    END
  END o[458]
  PIN o[459]
    DIRECTION OUTPUT ;
    USE SIGNAL ;
    PORT
      LAYER M4 ;
        RECT  0 86.64 0.084 86.664 ;
    END
  END o[459]
  PIN o[45]
    DIRECTION OUTPUT ;
    USE SIGNAL ;
    PORT
      LAYER M4 ;
        RECT  0 89.904 0.084 89.928 ;
    END
  END o[45]
  PIN o[460]
    DIRECTION OUTPUT ;
    USE SIGNAL ;
    PORT
      LAYER M4 ;
        RECT  0 86.736 0.084 86.76 ;
    END
  END o[460]
  PIN o[461]
    DIRECTION OUTPUT ;
    USE SIGNAL ;
    PORT
      LAYER M4 ;
        RECT  0 86.832 0.084 86.856 ;
    END
  END o[461]
  PIN o[462]
    DIRECTION OUTPUT ;
    USE SIGNAL ;
    PORT
      LAYER M4 ;
        RECT  0 86.928 0.084 86.952 ;
    END
  END o[462]
  PIN o[463]
    DIRECTION OUTPUT ;
    USE SIGNAL ;
    PORT
      LAYER M4 ;
        RECT  0 87.024 0.084 87.048 ;
    END
  END o[463]
  PIN o[464]
    DIRECTION OUTPUT ;
    USE SIGNAL ;
    PORT
      LAYER M4 ;
        RECT  0 87.12 0.084 87.144 ;
    END
  END o[464]
  PIN o[465]
    DIRECTION OUTPUT ;
    USE SIGNAL ;
    PORT
      LAYER M4 ;
        RECT  0 87.216 0.084 87.24 ;
    END
  END o[465]
  PIN o[466]
    DIRECTION OUTPUT ;
    USE SIGNAL ;
    PORT
      LAYER M4 ;
        RECT  0 87.312 0.084 87.336 ;
    END
  END o[466]
  PIN o[467]
    DIRECTION OUTPUT ;
    USE SIGNAL ;
    PORT
      LAYER M4 ;
        RECT  0 87.408 0.084 87.432 ;
    END
  END o[467]
  PIN o[468]
    DIRECTION OUTPUT ;
    USE SIGNAL ;
    PORT
      LAYER M4 ;
        RECT  0 87.504 0.084 87.528 ;
    END
  END o[468]
  PIN o[469]
    DIRECTION OUTPUT ;
    USE SIGNAL ;
    PORT
      LAYER M4 ;
        RECT  0 87.6 0.084 87.624 ;
    END
  END o[469]
  PIN o[46]
    DIRECTION OUTPUT ;
    USE SIGNAL ;
    PORT
      LAYER M4 ;
        RECT  0 90 0.084 90.024 ;
    END
  END o[46]
  PIN o[470]
    DIRECTION OUTPUT ;
    USE SIGNAL ;
    PORT
      LAYER M4 ;
        RECT  0 87.696 0.084 87.72 ;
    END
  END o[470]
  PIN o[471]
    DIRECTION OUTPUT ;
    USE SIGNAL ;
    PORT
      LAYER M4 ;
        RECT  0 87.792 0.084 87.816 ;
    END
  END o[471]
  PIN o[472]
    DIRECTION OUTPUT ;
    USE SIGNAL ;
    PORT
      LAYER M4 ;
        RECT  0 87.888 0.084 87.912 ;
    END
  END o[472]
  PIN o[473]
    DIRECTION OUTPUT ;
    USE SIGNAL ;
    PORT
      LAYER M4 ;
        RECT  0 87.984 0.084 88.008 ;
    END
  END o[473]
  PIN o[474]
    DIRECTION OUTPUT ;
    USE SIGNAL ;
    PORT
      LAYER M4 ;
        RECT  0 88.08 0.084 88.104 ;
    END
  END o[474]
  PIN o[475]
    DIRECTION OUTPUT ;
    USE SIGNAL ;
    PORT
      LAYER M4 ;
        RECT  0 88.176 0.084 88.2 ;
    END
  END o[475]
  PIN o[476]
    DIRECTION OUTPUT ;
    USE SIGNAL ;
    PORT
      LAYER M4 ;
        RECT  0 88.272 0.084 88.296 ;
    END
  END o[476]
  PIN o[477]
    DIRECTION OUTPUT ;
    USE SIGNAL ;
    PORT
      LAYER M4 ;
        RECT  0 88.368 0.084 88.392 ;
    END
  END o[477]
  PIN o[478]
    DIRECTION OUTPUT ;
    USE SIGNAL ;
    PORT
      LAYER M4 ;
        RECT  0 76.176 0.084 76.2 ;
    END
  END o[478]
  PIN o[479]
    DIRECTION OUTPUT ;
    USE SIGNAL ;
    PORT
      LAYER M4 ;
        RECT  0 76.272 0.084 76.296 ;
    END
  END o[479]
  PIN o[47]
    DIRECTION OUTPUT ;
    USE SIGNAL ;
    PORT
      LAYER M4 ;
        RECT  0 90.096 0.084 90.12 ;
    END
  END o[47]
  PIN o[480]
    DIRECTION OUTPUT ;
    USE SIGNAL ;
    PORT
      LAYER M4 ;
        RECT  0 76.368 0.084 76.392 ;
    END
  END o[480]
  PIN o[481]
    DIRECTION OUTPUT ;
    USE SIGNAL ;
    PORT
      LAYER M4 ;
        RECT  0 76.464 0.084 76.488 ;
    END
  END o[481]
  PIN o[482]
    DIRECTION OUTPUT ;
    USE SIGNAL ;
    PORT
      LAYER M4 ;
        RECT  0 76.56 0.084 76.584 ;
    END
  END o[482]
  PIN o[483]
    DIRECTION OUTPUT ;
    USE SIGNAL ;
    PORT
      LAYER M4 ;
        RECT  0 76.656 0.084 76.68 ;
    END
  END o[483]
  PIN o[484]
    DIRECTION OUTPUT ;
    USE SIGNAL ;
    PORT
      LAYER M4 ;
        RECT  0 76.752 0.084 76.776 ;
    END
  END o[484]
  PIN o[485]
    DIRECTION OUTPUT ;
    USE SIGNAL ;
    PORT
      LAYER M4 ;
        RECT  0 76.848 0.084 76.872 ;
    END
  END o[485]
  PIN o[486]
    DIRECTION OUTPUT ;
    USE SIGNAL ;
    PORT
      LAYER M4 ;
        RECT  0 76.944 0.084 76.968 ;
    END
  END o[486]
  PIN o[487]
    DIRECTION OUTPUT ;
    USE SIGNAL ;
    PORT
      LAYER M4 ;
        RECT  0 77.04 0.084 77.064 ;
    END
  END o[487]
  PIN o[488]
    DIRECTION OUTPUT ;
    USE SIGNAL ;
    PORT
      LAYER M4 ;
        RECT  0 77.136 0.084 77.16 ;
    END
  END o[488]
  PIN o[489]
    DIRECTION OUTPUT ;
    USE SIGNAL ;
    PORT
      LAYER M4 ;
        RECT  0 77.232 0.084 77.256 ;
    END
  END o[489]
  PIN o[48]
    DIRECTION OUTPUT ;
    USE SIGNAL ;
    PORT
      LAYER M4 ;
        RECT  0 90.192 0.084 90.216 ;
    END
  END o[48]
  PIN o[490]
    DIRECTION OUTPUT ;
    USE SIGNAL ;
    PORT
      LAYER M4 ;
        RECT  0 77.328 0.084 77.352 ;
    END
  END o[490]
  PIN o[491]
    DIRECTION OUTPUT ;
    USE SIGNAL ;
    PORT
      LAYER M4 ;
        RECT  0 77.424 0.084 77.448 ;
    END
  END o[491]
  PIN o[492]
    DIRECTION OUTPUT ;
    USE SIGNAL ;
    PORT
      LAYER M4 ;
        RECT  0 77.52 0.084 77.544 ;
    END
  END o[492]
  PIN o[493]
    DIRECTION OUTPUT ;
    USE SIGNAL ;
    PORT
      LAYER M4 ;
        RECT  0 77.616 0.084 77.64 ;
    END
  END o[493]
  PIN o[494]
    DIRECTION OUTPUT ;
    USE SIGNAL ;
    PORT
      LAYER M4 ;
        RECT  0 77.712 0.084 77.736 ;
    END
  END o[494]
  PIN o[495]
    DIRECTION OUTPUT ;
    USE SIGNAL ;
    PORT
      LAYER M4 ;
        RECT  0 77.808 0.084 77.832 ;
    END
  END o[495]
  PIN o[496]
    DIRECTION OUTPUT ;
    USE SIGNAL ;
    PORT
      LAYER M4 ;
        RECT  0 77.904 0.084 77.928 ;
    END
  END o[496]
  PIN o[497]
    DIRECTION OUTPUT ;
    USE SIGNAL ;
    PORT
      LAYER M4 ;
        RECT  0 78 0.084 78.024 ;
    END
  END o[497]
  PIN o[498]
    DIRECTION OUTPUT ;
    USE SIGNAL ;
    PORT
      LAYER M4 ;
        RECT  0 78.096 0.084 78.12 ;
    END
  END o[498]
  PIN o[499]
    DIRECTION OUTPUT ;
    USE SIGNAL ;
    PORT
      LAYER M4 ;
        RECT  0 78.192 0.084 78.216 ;
    END
  END o[499]
  PIN o[49]
    DIRECTION OUTPUT ;
    USE SIGNAL ;
    PORT
      LAYER M4 ;
        RECT  0 90.288 0.084 90.312 ;
    END
  END o[49]
  PIN o[4]
    DIRECTION OUTPUT ;
    USE SIGNAL ;
    PORT
      LAYER M4 ;
        RECT  0 60.624 0.084 60.648 ;
    END
  END o[4]
  PIN o[500]
    DIRECTION OUTPUT ;
    USE SIGNAL ;
    PORT
      LAYER M4 ;
        RECT  0 78.288 0.084 78.312 ;
    END
  END o[500]
  PIN o[501]
    DIRECTION OUTPUT ;
    USE SIGNAL ;
    PORT
      LAYER M4 ;
        RECT  0 78.384 0.084 78.408 ;
    END
  END o[501]
  PIN o[502]
    DIRECTION OUTPUT ;
    USE SIGNAL ;
    PORT
      LAYER M4 ;
        RECT  0 78.48 0.084 78.504 ;
    END
  END o[502]
  PIN o[503]
    DIRECTION OUTPUT ;
    USE SIGNAL ;
    PORT
      LAYER M4 ;
        RECT  0 78.576 0.084 78.6 ;
    END
  END o[503]
  PIN o[504]
    DIRECTION OUTPUT ;
    USE SIGNAL ;
    PORT
      LAYER M4 ;
        RECT  0 78.672 0.084 78.696 ;
    END
  END o[504]
  PIN o[505]
    DIRECTION OUTPUT ;
    USE SIGNAL ;
    PORT
      LAYER M4 ;
        RECT  0 78.768 0.084 78.792 ;
    END
  END o[505]
  PIN o[506]
    DIRECTION OUTPUT ;
    USE SIGNAL ;
    PORT
      LAYER M4 ;
        RECT  0 78.864 0.084 78.888 ;
    END
  END o[506]
  PIN o[507]
    DIRECTION OUTPUT ;
    USE SIGNAL ;
    PORT
      LAYER M4 ;
        RECT  0 78.96 0.084 78.984 ;
    END
  END o[507]
  PIN o[508]
    DIRECTION OUTPUT ;
    USE SIGNAL ;
    PORT
      LAYER M4 ;
        RECT  0 79.056 0.084 79.08 ;
    END
  END o[508]
  PIN o[509]
    DIRECTION OUTPUT ;
    USE SIGNAL ;
    PORT
      LAYER M4 ;
        RECT  0 79.152 0.084 79.176 ;
    END
  END o[509]
  PIN o[50]
    DIRECTION OUTPUT ;
    USE SIGNAL ;
    PORT
      LAYER M4 ;
        RECT  0 90.384 0.084 90.408 ;
    END
  END o[50]
  PIN o[510]
    DIRECTION OUTPUT ;
    USE SIGNAL ;
    PORT
      LAYER M4 ;
        RECT  0 56.976 0.084 57 ;
    END
  END o[510]
  PIN o[511]
    DIRECTION OUTPUT ;
    USE SIGNAL ;
    PORT
      LAYER M4 ;
        RECT  0 57.072 0.084 57.096 ;
    END
  END o[511]
  PIN o[512]
    DIRECTION OUTPUT ;
    USE SIGNAL ;
    PORT
      LAYER M4 ;
        RECT  0 57.168 0.084 57.192 ;
    END
  END o[512]
  PIN o[513]
    DIRECTION OUTPUT ;
    USE SIGNAL ;
    PORT
      LAYER M4 ;
        RECT  0 57.264 0.084 57.288 ;
    END
  END o[513]
  PIN o[514]
    DIRECTION OUTPUT ;
    USE SIGNAL ;
    PORT
      LAYER M4 ;
        RECT  0 57.36 0.084 57.384 ;
    END
  END o[514]
  PIN o[515]
    DIRECTION OUTPUT ;
    USE SIGNAL ;
    PORT
      LAYER M4 ;
        RECT  0 57.456 0.084 57.48 ;
    END
  END o[515]
  PIN o[516]
    DIRECTION OUTPUT ;
    USE SIGNAL ;
    PORT
      LAYER M4 ;
        RECT  0 57.552 0.084 57.576 ;
    END
  END o[516]
  PIN o[517]
    DIRECTION OUTPUT ;
    USE SIGNAL ;
    PORT
      LAYER M4 ;
        RECT  0 57.648 0.084 57.672 ;
    END
  END o[517]
  PIN o[518]
    DIRECTION OUTPUT ;
    USE SIGNAL ;
    PORT
      LAYER M4 ;
        RECT  0 57.744 0.084 57.768 ;
    END
  END o[518]
  PIN o[519]
    DIRECTION OUTPUT ;
    USE SIGNAL ;
    PORT
      LAYER M4 ;
        RECT  0 57.84 0.084 57.864 ;
    END
  END o[519]
  PIN o[51]
    DIRECTION OUTPUT ;
    USE SIGNAL ;
    PORT
      LAYER M4 ;
        RECT  0 90.48 0.084 90.504 ;
    END
  END o[51]
  PIN o[520]
    DIRECTION OUTPUT ;
    USE SIGNAL ;
    PORT
      LAYER M4 ;
        RECT  0 57.936 0.084 57.96 ;
    END
  END o[520]
  PIN o[521]
    DIRECTION OUTPUT ;
    USE SIGNAL ;
    PORT
      LAYER M4 ;
        RECT  0 58.032 0.084 58.056 ;
    END
  END o[521]
  PIN o[522]
    DIRECTION OUTPUT ;
    USE SIGNAL ;
    PORT
      LAYER M4 ;
        RECT  0 58.128 0.084 58.152 ;
    END
  END o[522]
  PIN o[523]
    DIRECTION OUTPUT ;
    USE SIGNAL ;
    PORT
      LAYER M4 ;
        RECT  0 58.224 0.084 58.248 ;
    END
  END o[523]
  PIN o[524]
    DIRECTION OUTPUT ;
    USE SIGNAL ;
    PORT
      LAYER M4 ;
        RECT  0 58.32 0.084 58.344 ;
    END
  END o[524]
  PIN o[525]
    DIRECTION OUTPUT ;
    USE SIGNAL ;
    PORT
      LAYER M4 ;
        RECT  0 58.416 0.084 58.44 ;
    END
  END o[525]
  PIN o[526]
    DIRECTION OUTPUT ;
    USE SIGNAL ;
    PORT
      LAYER M4 ;
        RECT  0 58.512 0.084 58.536 ;
    END
  END o[526]
  PIN o[527]
    DIRECTION OUTPUT ;
    USE SIGNAL ;
    PORT
      LAYER M4 ;
        RECT  0 58.608 0.084 58.632 ;
    END
  END o[527]
  PIN o[528]
    DIRECTION OUTPUT ;
    USE SIGNAL ;
    PORT
      LAYER M4 ;
        RECT  0 58.704 0.084 58.728 ;
    END
  END o[528]
  PIN o[529]
    DIRECTION OUTPUT ;
    USE SIGNAL ;
    PORT
      LAYER M4 ;
        RECT  0 58.8 0.084 58.824 ;
    END
  END o[529]
  PIN o[52]
    DIRECTION OUTPUT ;
    USE SIGNAL ;
    PORT
      LAYER M4 ;
        RECT  0 90.576 0.084 90.6 ;
    END
  END o[52]
  PIN o[530]
    DIRECTION OUTPUT ;
    USE SIGNAL ;
    PORT
      LAYER M4 ;
        RECT  0 58.896 0.084 58.92 ;
    END
  END o[530]
  PIN o[531]
    DIRECTION OUTPUT ;
    USE SIGNAL ;
    PORT
      LAYER M4 ;
        RECT  0 58.992 0.084 59.016 ;
    END
  END o[531]
  PIN o[532]
    DIRECTION OUTPUT ;
    USE SIGNAL ;
    PORT
      LAYER M4 ;
        RECT  0 59.088 0.084 59.112 ;
    END
  END o[532]
  PIN o[533]
    DIRECTION OUTPUT ;
    USE SIGNAL ;
    PORT
      LAYER M4 ;
        RECT  0 59.184 0.084 59.208 ;
    END
  END o[533]
  PIN o[534]
    DIRECTION OUTPUT ;
    USE SIGNAL ;
    PORT
      LAYER M4 ;
        RECT  0 59.28 0.084 59.304 ;
    END
  END o[534]
  PIN o[535]
    DIRECTION OUTPUT ;
    USE SIGNAL ;
    PORT
      LAYER M4 ;
        RECT  0 59.376 0.084 59.4 ;
    END
  END o[535]
  PIN o[536]
    DIRECTION OUTPUT ;
    USE SIGNAL ;
    PORT
      LAYER M4 ;
        RECT  0 59.472 0.084 59.496 ;
    END
  END o[536]
  PIN o[537]
    DIRECTION OUTPUT ;
    USE SIGNAL ;
    PORT
      LAYER M4 ;
        RECT  0 59.568 0.084 59.592 ;
    END
  END o[537]
  PIN o[538]
    DIRECTION OUTPUT ;
    USE SIGNAL ;
    PORT
      LAYER M4 ;
        RECT  0 59.664 0.084 59.688 ;
    END
  END o[538]
  PIN o[539]
    DIRECTION OUTPUT ;
    USE SIGNAL ;
    PORT
      LAYER M4 ;
        RECT  0 59.76 0.084 59.784 ;
    END
  END o[539]
  PIN o[53]
    DIRECTION OUTPUT ;
    USE SIGNAL ;
    PORT
      LAYER M4 ;
        RECT  0 90.672 0.084 90.696 ;
    END
  END o[53]
  PIN o[540]
    DIRECTION OUTPUT ;
    USE SIGNAL ;
    PORT
      LAYER M4 ;
        RECT  0 59.856 0.084 59.88 ;
    END
  END o[540]
  PIN o[541]
    DIRECTION OUTPUT ;
    USE SIGNAL ;
    PORT
      LAYER M4 ;
        RECT  0 59.952 0.084 59.976 ;
    END
  END o[541]
  PIN o[542]
    DIRECTION OUTPUT ;
    USE SIGNAL ;
    PORT
      LAYER M4 ;
        RECT  0 40.848 0.084 40.872 ;
    END
  END o[542]
  PIN o[543]
    DIRECTION OUTPUT ;
    USE SIGNAL ;
    PORT
      LAYER M4 ;
        RECT  0 40.944 0.084 40.968 ;
    END
  END o[543]
  PIN o[544]
    DIRECTION OUTPUT ;
    USE SIGNAL ;
    PORT
      LAYER M4 ;
        RECT  0 41.04 0.084 41.064 ;
    END
  END o[544]
  PIN o[545]
    DIRECTION OUTPUT ;
    USE SIGNAL ;
    PORT
      LAYER M4 ;
        RECT  0 41.136 0.084 41.16 ;
    END
  END o[545]
  PIN o[546]
    DIRECTION OUTPUT ;
    USE SIGNAL ;
    PORT
      LAYER M4 ;
        RECT  0 41.232 0.084 41.256 ;
    END
  END o[546]
  PIN o[547]
    DIRECTION OUTPUT ;
    USE SIGNAL ;
    PORT
      LAYER M4 ;
        RECT  0 41.328 0.084 41.352 ;
    END
  END o[547]
  PIN o[548]
    DIRECTION OUTPUT ;
    USE SIGNAL ;
    PORT
      LAYER M4 ;
        RECT  0 41.424 0.084 41.448 ;
    END
  END o[548]
  PIN o[549]
    DIRECTION OUTPUT ;
    USE SIGNAL ;
    PORT
      LAYER M4 ;
        RECT  0 41.52 0.084 41.544 ;
    END
  END o[549]
  PIN o[54]
    DIRECTION OUTPUT ;
    USE SIGNAL ;
    PORT
      LAYER M4 ;
        RECT  0 90.768 0.084 90.792 ;
    END
  END o[54]
  PIN o[550]
    DIRECTION OUTPUT ;
    USE SIGNAL ;
    PORT
      LAYER M4 ;
        RECT  0 41.616 0.084 41.64 ;
    END
  END o[550]
  PIN o[551]
    DIRECTION OUTPUT ;
    USE SIGNAL ;
    PORT
      LAYER M4 ;
        RECT  0 41.712 0.084 41.736 ;
    END
  END o[551]
  PIN o[552]
    DIRECTION OUTPUT ;
    USE SIGNAL ;
    PORT
      LAYER M4 ;
        RECT  0 41.808 0.084 41.832 ;
    END
  END o[552]
  PIN o[553]
    DIRECTION OUTPUT ;
    USE SIGNAL ;
    PORT
      LAYER M4 ;
        RECT  0 41.904 0.084 41.928 ;
    END
  END o[553]
  PIN o[554]
    DIRECTION OUTPUT ;
    USE SIGNAL ;
    PORT
      LAYER M4 ;
        RECT  0 42 0.084 42.024 ;
    END
  END o[554]
  PIN o[555]
    DIRECTION OUTPUT ;
    USE SIGNAL ;
    PORT
      LAYER M4 ;
        RECT  0 42.096 0.084 42.12 ;
    END
  END o[555]
  PIN o[556]
    DIRECTION OUTPUT ;
    USE SIGNAL ;
    PORT
      LAYER M4 ;
        RECT  0 42.192 0.084 42.216 ;
    END
  END o[556]
  PIN o[557]
    DIRECTION OUTPUT ;
    USE SIGNAL ;
    PORT
      LAYER M4 ;
        RECT  0 42.288 0.084 42.312 ;
    END
  END o[557]
  PIN o[558]
    DIRECTION OUTPUT ;
    USE SIGNAL ;
    PORT
      LAYER M4 ;
        RECT  0 42.384 0.084 42.408 ;
    END
  END o[558]
  PIN o[559]
    DIRECTION OUTPUT ;
    USE SIGNAL ;
    PORT
      LAYER M4 ;
        RECT  0 42.48 0.084 42.504 ;
    END
  END o[559]
  PIN o[55]
    DIRECTION OUTPUT ;
    USE SIGNAL ;
    PORT
      LAYER M4 ;
        RECT  0 90.864 0.084 90.888 ;
    END
  END o[55]
  PIN o[560]
    DIRECTION OUTPUT ;
    USE SIGNAL ;
    PORT
      LAYER M4 ;
        RECT  0 42.576 0.084 42.6 ;
    END
  END o[560]
  PIN o[561]
    DIRECTION OUTPUT ;
    USE SIGNAL ;
    PORT
      LAYER M4 ;
        RECT  0 42.672 0.084 42.696 ;
    END
  END o[561]
  PIN o[562]
    DIRECTION OUTPUT ;
    USE SIGNAL ;
    PORT
      LAYER M4 ;
        RECT  0 42.768 0.084 42.792 ;
    END
  END o[562]
  PIN o[563]
    DIRECTION OUTPUT ;
    USE SIGNAL ;
    PORT
      LAYER M4 ;
        RECT  0 42.864 0.084 42.888 ;
    END
  END o[563]
  PIN o[564]
    DIRECTION OUTPUT ;
    USE SIGNAL ;
    PORT
      LAYER M4 ;
        RECT  0 42.96 0.084 42.984 ;
    END
  END o[564]
  PIN o[565]
    DIRECTION OUTPUT ;
    USE SIGNAL ;
    PORT
      LAYER M4 ;
        RECT  0 43.056 0.084 43.08 ;
    END
  END o[565]
  PIN o[566]
    DIRECTION OUTPUT ;
    USE SIGNAL ;
    PORT
      LAYER M4 ;
        RECT  0 43.152 0.084 43.176 ;
    END
  END o[566]
  PIN o[567]
    DIRECTION OUTPUT ;
    USE SIGNAL ;
    PORT
      LAYER M4 ;
        RECT  0 43.248 0.084 43.272 ;
    END
  END o[567]
  PIN o[568]
    DIRECTION OUTPUT ;
    USE SIGNAL ;
    PORT
      LAYER M4 ;
        RECT  0 43.344 0.084 43.368 ;
    END
  END o[568]
  PIN o[569]
    DIRECTION OUTPUT ;
    USE SIGNAL ;
    PORT
      LAYER M4 ;
        RECT  0 43.44 0.084 43.464 ;
    END
  END o[569]
  PIN o[56]
    DIRECTION OUTPUT ;
    USE SIGNAL ;
    PORT
      LAYER M4 ;
        RECT  0 90.96 0.084 90.984 ;
    END
  END o[56]
  PIN o[570]
    DIRECTION OUTPUT ;
    USE SIGNAL ;
    PORT
      LAYER M4 ;
        RECT  0 43.536 0.084 43.56 ;
    END
  END o[570]
  PIN o[571]
    DIRECTION OUTPUT ;
    USE SIGNAL ;
    PORT
      LAYER M4 ;
        RECT  0 43.632 0.084 43.656 ;
    END
  END o[571]
  PIN o[572]
    DIRECTION OUTPUT ;
    USE SIGNAL ;
    PORT
      LAYER M4 ;
        RECT  0 43.728 0.084 43.752 ;
    END
  END o[572]
  PIN o[573]
    DIRECTION OUTPUT ;
    USE SIGNAL ;
    PORT
      LAYER M4 ;
        RECT  0 43.824 0.084 43.848 ;
    END
  END o[573]
  PIN o[574]
    DIRECTION OUTPUT ;
    USE SIGNAL ;
    PORT
      LAYER M4 ;
        RECT  0 18.576 0.084 18.6 ;
    END
  END o[574]
  PIN o[575]
    DIRECTION OUTPUT ;
    USE SIGNAL ;
    PORT
      LAYER M4 ;
        RECT  0 18.672 0.084 18.696 ;
    END
  END o[575]
  PIN o[576]
    DIRECTION OUTPUT ;
    USE SIGNAL ;
    PORT
      LAYER M4 ;
        RECT  0 18.768 0.084 18.792 ;
    END
  END o[576]
  PIN o[577]
    DIRECTION OUTPUT ;
    USE SIGNAL ;
    PORT
      LAYER M4 ;
        RECT  0 18.864 0.084 18.888 ;
    END
  END o[577]
  PIN o[578]
    DIRECTION OUTPUT ;
    USE SIGNAL ;
    PORT
      LAYER M4 ;
        RECT  0 18.96 0.084 18.984 ;
    END
  END o[578]
  PIN o[579]
    DIRECTION OUTPUT ;
    USE SIGNAL ;
    PORT
      LAYER M4 ;
        RECT  0 19.056 0.084 19.08 ;
    END
  END o[579]
  PIN o[57]
    DIRECTION OUTPUT ;
    USE SIGNAL ;
    PORT
      LAYER M4 ;
        RECT  0 91.056 0.084 91.08 ;
    END
  END o[57]
  PIN o[580]
    DIRECTION OUTPUT ;
    USE SIGNAL ;
    PORT
      LAYER M4 ;
        RECT  0 19.152 0.084 19.176 ;
    END
  END o[580]
  PIN o[581]
    DIRECTION OUTPUT ;
    USE SIGNAL ;
    PORT
      LAYER M4 ;
        RECT  0 19.248 0.084 19.272 ;
    END
  END o[581]
  PIN o[582]
    DIRECTION OUTPUT ;
    USE SIGNAL ;
    PORT
      LAYER M4 ;
        RECT  0 19.344 0.084 19.368 ;
    END
  END o[582]
  PIN o[583]
    DIRECTION OUTPUT ;
    USE SIGNAL ;
    PORT
      LAYER M4 ;
        RECT  0 19.44 0.084 19.464 ;
    END
  END o[583]
  PIN o[584]
    DIRECTION OUTPUT ;
    USE SIGNAL ;
    PORT
      LAYER M4 ;
        RECT  0 19.536 0.084 19.56 ;
    END
  END o[584]
  PIN o[585]
    DIRECTION OUTPUT ;
    USE SIGNAL ;
    PORT
      LAYER M4 ;
        RECT  0 19.632 0.084 19.656 ;
    END
  END o[585]
  PIN o[586]
    DIRECTION OUTPUT ;
    USE SIGNAL ;
    PORT
      LAYER M4 ;
        RECT  0 19.728 0.084 19.752 ;
    END
  END o[586]
  PIN o[587]
    DIRECTION OUTPUT ;
    USE SIGNAL ;
    PORT
      LAYER M4 ;
        RECT  0 19.824 0.084 19.848 ;
    END
  END o[587]
  PIN o[588]
    DIRECTION OUTPUT ;
    USE SIGNAL ;
    PORT
      LAYER M4 ;
        RECT  0 19.92 0.084 19.944 ;
    END
  END o[588]
  PIN o[589]
    DIRECTION OUTPUT ;
    USE SIGNAL ;
    PORT
      LAYER M4 ;
        RECT  0 20.016 0.084 20.04 ;
    END
  END o[589]
  PIN o[58]
    DIRECTION OUTPUT ;
    USE SIGNAL ;
    PORT
      LAYER M4 ;
        RECT  0 91.152 0.084 91.176 ;
    END
  END o[58]
  PIN o[590]
    DIRECTION OUTPUT ;
    USE SIGNAL ;
    PORT
      LAYER M4 ;
        RECT  0 20.112 0.084 20.136 ;
    END
  END o[590]
  PIN o[591]
    DIRECTION OUTPUT ;
    USE SIGNAL ;
    PORT
      LAYER M4 ;
        RECT  0 20.208 0.084 20.232 ;
    END
  END o[591]
  PIN o[592]
    DIRECTION OUTPUT ;
    USE SIGNAL ;
    PORT
      LAYER M4 ;
        RECT  0 20.304 0.084 20.328 ;
    END
  END o[592]
  PIN o[593]
    DIRECTION OUTPUT ;
    USE SIGNAL ;
    PORT
      LAYER M4 ;
        RECT  0 20.4 0.084 20.424 ;
    END
  END o[593]
  PIN o[594]
    DIRECTION OUTPUT ;
    USE SIGNAL ;
    PORT
      LAYER M4 ;
        RECT  0 20.496 0.084 20.52 ;
    END
  END o[594]
  PIN o[595]
    DIRECTION OUTPUT ;
    USE SIGNAL ;
    PORT
      LAYER M4 ;
        RECT  0 20.592 0.084 20.616 ;
    END
  END o[595]
  PIN o[596]
    DIRECTION OUTPUT ;
    USE SIGNAL ;
    PORT
      LAYER M4 ;
        RECT  0 20.688 0.084 20.712 ;
    END
  END o[596]
  PIN o[597]
    DIRECTION OUTPUT ;
    USE SIGNAL ;
    PORT
      LAYER M4 ;
        RECT  0 20.784 0.084 20.808 ;
    END
  END o[597]
  PIN o[598]
    DIRECTION OUTPUT ;
    USE SIGNAL ;
    PORT
      LAYER M4 ;
        RECT  0 20.88 0.084 20.904 ;
    END
  END o[598]
  PIN o[599]
    DIRECTION OUTPUT ;
    USE SIGNAL ;
    PORT
      LAYER M4 ;
        RECT  0 20.976 0.084 21 ;
    END
  END o[599]
  PIN o[59]
    DIRECTION OUTPUT ;
    USE SIGNAL ;
    PORT
      LAYER M4 ;
        RECT  0 91.248 0.084 91.272 ;
    END
  END o[59]
  PIN o[5]
    DIRECTION OUTPUT ;
    USE SIGNAL ;
    PORT
      LAYER M4 ;
        RECT  0 60.72 0.084 60.744 ;
    END
  END o[5]
  PIN o[600]
    DIRECTION OUTPUT ;
    USE SIGNAL ;
    PORT
      LAYER M4 ;
        RECT  0 21.072 0.084 21.096 ;
    END
  END o[600]
  PIN o[601]
    DIRECTION OUTPUT ;
    USE SIGNAL ;
    PORT
      LAYER M4 ;
        RECT  0 21.168 0.084 21.192 ;
    END
  END o[601]
  PIN o[602]
    DIRECTION OUTPUT ;
    USE SIGNAL ;
    PORT
      LAYER M4 ;
        RECT  0 21.264 0.084 21.288 ;
    END
  END o[602]
  PIN o[603]
    DIRECTION OUTPUT ;
    USE SIGNAL ;
    PORT
      LAYER M4 ;
        RECT  0 21.36 0.084 21.384 ;
    END
  END o[603]
  PIN o[604]
    DIRECTION OUTPUT ;
    USE SIGNAL ;
    PORT
      LAYER M4 ;
        RECT  0 21.456 0.084 21.48 ;
    END
  END o[604]
  PIN o[605]
    DIRECTION OUTPUT ;
    USE SIGNAL ;
    PORT
      LAYER M4 ;
        RECT  0 21.552 0.084 21.576 ;
    END
  END o[605]
  PIN o[606]
    DIRECTION OUTPUT ;
    USE SIGNAL ;
    PORT
      LAYER M4 ;
        RECT  0 8.592 0.084 8.616 ;
    END
  END o[606]
  PIN o[607]
    DIRECTION OUTPUT ;
    USE SIGNAL ;
    PORT
      LAYER M4 ;
        RECT  0 8.688 0.084 8.712 ;
    END
  END o[607]
  PIN o[608]
    DIRECTION OUTPUT ;
    USE SIGNAL ;
    PORT
      LAYER M4 ;
        RECT  0 8.784 0.084 8.808 ;
    END
  END o[608]
  PIN o[609]
    DIRECTION OUTPUT ;
    USE SIGNAL ;
    PORT
      LAYER M4 ;
        RECT  0 8.88 0.084 8.904 ;
    END
  END o[609]
  PIN o[60]
    DIRECTION OUTPUT ;
    USE SIGNAL ;
    PORT
      LAYER M4 ;
        RECT  0 91.344 0.084 91.368 ;
    END
  END o[60]
  PIN o[610]
    DIRECTION OUTPUT ;
    USE SIGNAL ;
    PORT
      LAYER M4 ;
        RECT  0 8.976 0.084 9 ;
    END
  END o[610]
  PIN o[611]
    DIRECTION OUTPUT ;
    USE SIGNAL ;
    PORT
      LAYER M4 ;
        RECT  0 9.072 0.084 9.096 ;
    END
  END o[611]
  PIN o[612]
    DIRECTION OUTPUT ;
    USE SIGNAL ;
    PORT
      LAYER M4 ;
        RECT  0 9.168 0.084 9.192 ;
    END
  END o[612]
  PIN o[613]
    DIRECTION OUTPUT ;
    USE SIGNAL ;
    PORT
      LAYER M4 ;
        RECT  0 9.264 0.084 9.288 ;
    END
  END o[613]
  PIN o[614]
    DIRECTION OUTPUT ;
    USE SIGNAL ;
    PORT
      LAYER M4 ;
        RECT  0 9.36 0.084 9.384 ;
    END
  END o[614]
  PIN o[615]
    DIRECTION OUTPUT ;
    USE SIGNAL ;
    PORT
      LAYER M4 ;
        RECT  0 9.456 0.084 9.48 ;
    END
  END o[615]
  PIN o[616]
    DIRECTION OUTPUT ;
    USE SIGNAL ;
    PORT
      LAYER M4 ;
        RECT  0 9.552 0.084 9.576 ;
    END
  END o[616]
  PIN o[617]
    DIRECTION OUTPUT ;
    USE SIGNAL ;
    PORT
      LAYER M4 ;
        RECT  0 9.648 0.084 9.672 ;
    END
  END o[617]
  PIN o[618]
    DIRECTION OUTPUT ;
    USE SIGNAL ;
    PORT
      LAYER M4 ;
        RECT  0 9.744 0.084 9.768 ;
    END
  END o[618]
  PIN o[619]
    DIRECTION OUTPUT ;
    USE SIGNAL ;
    PORT
      LAYER M4 ;
        RECT  0 9.84 0.084 9.864 ;
    END
  END o[619]
  PIN o[61]
    DIRECTION OUTPUT ;
    USE SIGNAL ;
    PORT
      LAYER M4 ;
        RECT  0 91.44 0.084 91.464 ;
    END
  END o[61]
  PIN o[620]
    DIRECTION OUTPUT ;
    USE SIGNAL ;
    PORT
      LAYER M4 ;
        RECT  0 9.936 0.084 9.96 ;
    END
  END o[620]
  PIN o[621]
    DIRECTION OUTPUT ;
    USE SIGNAL ;
    PORT
      LAYER M4 ;
        RECT  0 10.032 0.084 10.056 ;
    END
  END o[621]
  PIN o[622]
    DIRECTION OUTPUT ;
    USE SIGNAL ;
    PORT
      LAYER M4 ;
        RECT  0 10.128 0.084 10.152 ;
    END
  END o[622]
  PIN o[623]
    DIRECTION OUTPUT ;
    USE SIGNAL ;
    PORT
      LAYER M4 ;
        RECT  0 10.224 0.084 10.248 ;
    END
  END o[623]
  PIN o[624]
    DIRECTION OUTPUT ;
    USE SIGNAL ;
    PORT
      LAYER M4 ;
        RECT  0 10.32 0.084 10.344 ;
    END
  END o[624]
  PIN o[625]
    DIRECTION OUTPUT ;
    USE SIGNAL ;
    PORT
      LAYER M4 ;
        RECT  0 10.416 0.084 10.44 ;
    END
  END o[625]
  PIN o[626]
    DIRECTION OUTPUT ;
    USE SIGNAL ;
    PORT
      LAYER M4 ;
        RECT  0 10.512 0.084 10.536 ;
    END
  END o[626]
  PIN o[627]
    DIRECTION OUTPUT ;
    USE SIGNAL ;
    PORT
      LAYER M4 ;
        RECT  0 10.608 0.084 10.632 ;
    END
  END o[627]
  PIN o[628]
    DIRECTION OUTPUT ;
    USE SIGNAL ;
    PORT
      LAYER M4 ;
        RECT  0 10.704 0.084 10.728 ;
    END
  END o[628]
  PIN o[629]
    DIRECTION OUTPUT ;
    USE SIGNAL ;
    PORT
      LAYER M4 ;
        RECT  0 10.8 0.084 10.824 ;
    END
  END o[629]
  PIN o[62]
    DIRECTION OUTPUT ;
    USE SIGNAL ;
    PORT
      LAYER M4 ;
        RECT  0 101.52 0.084 101.544 ;
    END
  END o[62]
  PIN o[630]
    DIRECTION OUTPUT ;
    USE SIGNAL ;
    PORT
      LAYER M4 ;
        RECT  0 10.896 0.084 10.92 ;
    END
  END o[630]
  PIN o[631]
    DIRECTION OUTPUT ;
    USE SIGNAL ;
    PORT
      LAYER M4 ;
        RECT  0 10.992 0.084 11.016 ;
    END
  END o[631]
  PIN o[632]
    DIRECTION OUTPUT ;
    USE SIGNAL ;
    PORT
      LAYER M4 ;
        RECT  0 11.088 0.084 11.112 ;
    END
  END o[632]
  PIN o[633]
    DIRECTION OUTPUT ;
    USE SIGNAL ;
    PORT
      LAYER M4 ;
        RECT  0 11.184 0.084 11.208 ;
    END
  END o[633]
  PIN o[634]
    DIRECTION OUTPUT ;
    USE SIGNAL ;
    PORT
      LAYER M4 ;
        RECT  0 11.28 0.084 11.304 ;
    END
  END o[634]
  PIN o[635]
    DIRECTION OUTPUT ;
    USE SIGNAL ;
    PORT
      LAYER M4 ;
        RECT  0 11.376 0.084 11.4 ;
    END
  END o[635]
  PIN o[636]
    DIRECTION OUTPUT ;
    USE SIGNAL ;
    PORT
      LAYER M4 ;
        RECT  0 11.472 0.084 11.496 ;
    END
  END o[636]
  PIN o[637]
    DIRECTION OUTPUT ;
    USE SIGNAL ;
    PORT
      LAYER M4 ;
        RECT  0 11.568 0.084 11.592 ;
    END
  END o[637]
  PIN o[638]
    DIRECTION OUTPUT ;
    USE SIGNAL ;
    PORT
      LAYER M4 ;
        RECT  0 21.648 0.084 21.672 ;
    END
  END o[638]
  PIN o[639]
    DIRECTION OUTPUT ;
    USE SIGNAL ;
    PORT
      LAYER M4 ;
        RECT  0 21.744 0.084 21.768 ;
    END
  END o[639]
  PIN o[63]
    DIRECTION OUTPUT ;
    USE SIGNAL ;
    PORT
      LAYER M4 ;
        RECT  0 101.616 0.084 101.64 ;
    END
  END o[63]
  PIN o[640]
    DIRECTION OUTPUT ;
    USE SIGNAL ;
    PORT
      LAYER M4 ;
        RECT  0 21.84 0.084 21.864 ;
    END
  END o[640]
  PIN o[641]
    DIRECTION OUTPUT ;
    USE SIGNAL ;
    PORT
      LAYER M4 ;
        RECT  0 21.936 0.084 21.96 ;
    END
  END o[641]
  PIN o[642]
    DIRECTION OUTPUT ;
    USE SIGNAL ;
    PORT
      LAYER M4 ;
        RECT  0 22.032 0.084 22.056 ;
    END
  END o[642]
  PIN o[643]
    DIRECTION OUTPUT ;
    USE SIGNAL ;
    PORT
      LAYER M4 ;
        RECT  0 22.128 0.084 22.152 ;
    END
  END o[643]
  PIN o[644]
    DIRECTION OUTPUT ;
    USE SIGNAL ;
    PORT
      LAYER M4 ;
        RECT  0 22.224 0.084 22.248 ;
    END
  END o[644]
  PIN o[645]
    DIRECTION OUTPUT ;
    USE SIGNAL ;
    PORT
      LAYER M4 ;
        RECT  0 22.32 0.084 22.344 ;
    END
  END o[645]
  PIN o[646]
    DIRECTION OUTPUT ;
    USE SIGNAL ;
    PORT
      LAYER M4 ;
        RECT  0 22.416 0.084 22.44 ;
    END
  END o[646]
  PIN o[647]
    DIRECTION OUTPUT ;
    USE SIGNAL ;
    PORT
      LAYER M4 ;
        RECT  0 22.512 0.084 22.536 ;
    END
  END o[647]
  PIN o[648]
    DIRECTION OUTPUT ;
    USE SIGNAL ;
    PORT
      LAYER M4 ;
        RECT  0 22.608 0.084 22.632 ;
    END
  END o[648]
  PIN o[649]
    DIRECTION OUTPUT ;
    USE SIGNAL ;
    PORT
      LAYER M4 ;
        RECT  0 22.704 0.084 22.728 ;
    END
  END o[649]
  PIN o[64]
    DIRECTION OUTPUT ;
    USE SIGNAL ;
    PORT
      LAYER M4 ;
        RECT  0 101.712 0.084 101.736 ;
    END
  END o[64]
  PIN o[650]
    DIRECTION OUTPUT ;
    USE SIGNAL ;
    PORT
      LAYER M4 ;
        RECT  0 22.8 0.084 22.824 ;
    END
  END o[650]
  PIN o[651]
    DIRECTION OUTPUT ;
    USE SIGNAL ;
    PORT
      LAYER M4 ;
        RECT  0 22.896 0.084 22.92 ;
    END
  END o[651]
  PIN o[652]
    DIRECTION OUTPUT ;
    USE SIGNAL ;
    PORT
      LAYER M4 ;
        RECT  0 22.992 0.084 23.016 ;
    END
  END o[652]
  PIN o[653]
    DIRECTION OUTPUT ;
    USE SIGNAL ;
    PORT
      LAYER M4 ;
        RECT  0 23.088 0.084 23.112 ;
    END
  END o[653]
  PIN o[654]
    DIRECTION OUTPUT ;
    USE SIGNAL ;
    PORT
      LAYER M4 ;
        RECT  0 23.184 0.084 23.208 ;
    END
  END o[654]
  PIN o[655]
    DIRECTION OUTPUT ;
    USE SIGNAL ;
    PORT
      LAYER M4 ;
        RECT  0 23.28 0.084 23.304 ;
    END
  END o[655]
  PIN o[656]
    DIRECTION OUTPUT ;
    USE SIGNAL ;
    PORT
      LAYER M4 ;
        RECT  0 23.376 0.084 23.4 ;
    END
  END o[656]
  PIN o[657]
    DIRECTION OUTPUT ;
    USE SIGNAL ;
    PORT
      LAYER M4 ;
        RECT  0 23.472 0.084 23.496 ;
    END
  END o[657]
  PIN o[658]
    DIRECTION OUTPUT ;
    USE SIGNAL ;
    PORT
      LAYER M4 ;
        RECT  0 23.568 0.084 23.592 ;
    END
  END o[658]
  PIN o[659]
    DIRECTION OUTPUT ;
    USE SIGNAL ;
    PORT
      LAYER M4 ;
        RECT  0 23.664 0.084 23.688 ;
    END
  END o[659]
  PIN o[65]
    DIRECTION OUTPUT ;
    USE SIGNAL ;
    PORT
      LAYER M4 ;
        RECT  0 101.808 0.084 101.832 ;
    END
  END o[65]
  PIN o[660]
    DIRECTION OUTPUT ;
    USE SIGNAL ;
    PORT
      LAYER M4 ;
        RECT  0 23.76 0.084 23.784 ;
    END
  END o[660]
  PIN o[661]
    DIRECTION OUTPUT ;
    USE SIGNAL ;
    PORT
      LAYER M4 ;
        RECT  0 23.856 0.084 23.88 ;
    END
  END o[661]
  PIN o[662]
    DIRECTION OUTPUT ;
    USE SIGNAL ;
    PORT
      LAYER M4 ;
        RECT  0 23.952 0.084 23.976 ;
    END
  END o[662]
  PIN o[663]
    DIRECTION OUTPUT ;
    USE SIGNAL ;
    PORT
      LAYER M4 ;
        RECT  0 24.048 0.084 24.072 ;
    END
  END o[663]
  PIN o[664]
    DIRECTION OUTPUT ;
    USE SIGNAL ;
    PORT
      LAYER M4 ;
        RECT  0 24.144 0.084 24.168 ;
    END
  END o[664]
  PIN o[665]
    DIRECTION OUTPUT ;
    USE SIGNAL ;
    PORT
      LAYER M4 ;
        RECT  0 24.24 0.084 24.264 ;
    END
  END o[665]
  PIN o[666]
    DIRECTION OUTPUT ;
    USE SIGNAL ;
    PORT
      LAYER M4 ;
        RECT  0 24.336 0.084 24.36 ;
    END
  END o[666]
  PIN o[667]
    DIRECTION OUTPUT ;
    USE SIGNAL ;
    PORT
      LAYER M4 ;
        RECT  0 24.432 0.084 24.456 ;
    END
  END o[667]
  PIN o[668]
    DIRECTION OUTPUT ;
    USE SIGNAL ;
    PORT
      LAYER M4 ;
        RECT  0 24.528 0.084 24.552 ;
    END
  END o[668]
  PIN o[669]
    DIRECTION OUTPUT ;
    USE SIGNAL ;
    PORT
      LAYER M4 ;
        RECT  0 24.624 0.084 24.648 ;
    END
  END o[669]
  PIN o[66]
    DIRECTION OUTPUT ;
    USE SIGNAL ;
    PORT
      LAYER M4 ;
        RECT  0 101.904 0.084 101.928 ;
    END
  END o[66]
  PIN o[670]
    DIRECTION OUTPUT ;
    USE SIGNAL ;
    PORT
      LAYER M4 ;
        RECT  0 45.84 0.084 45.864 ;
    END
  END o[670]
  PIN o[671]
    DIRECTION OUTPUT ;
    USE SIGNAL ;
    PORT
      LAYER M4 ;
        RECT  0 45.936 0.084 45.96 ;
    END
  END o[671]
  PIN o[672]
    DIRECTION OUTPUT ;
    USE SIGNAL ;
    PORT
      LAYER M4 ;
        RECT  0 46.032 0.084 46.056 ;
    END
  END o[672]
  PIN o[673]
    DIRECTION OUTPUT ;
    USE SIGNAL ;
    PORT
      LAYER M4 ;
        RECT  0 46.128 0.084 46.152 ;
    END
  END o[673]
  PIN o[674]
    DIRECTION OUTPUT ;
    USE SIGNAL ;
    PORT
      LAYER M4 ;
        RECT  0 46.224 0.084 46.248 ;
    END
  END o[674]
  PIN o[675]
    DIRECTION OUTPUT ;
    USE SIGNAL ;
    PORT
      LAYER M4 ;
        RECT  0 46.32 0.084 46.344 ;
    END
  END o[675]
  PIN o[676]
    DIRECTION OUTPUT ;
    USE SIGNAL ;
    PORT
      LAYER M4 ;
        RECT  0 46.416 0.084 46.44 ;
    END
  END o[676]
  PIN o[677]
    DIRECTION OUTPUT ;
    USE SIGNAL ;
    PORT
      LAYER M4 ;
        RECT  0 46.512 0.084 46.536 ;
    END
  END o[677]
  PIN o[678]
    DIRECTION OUTPUT ;
    USE SIGNAL ;
    PORT
      LAYER M4 ;
        RECT  0 46.608 0.084 46.632 ;
    END
  END o[678]
  PIN o[679]
    DIRECTION OUTPUT ;
    USE SIGNAL ;
    PORT
      LAYER M4 ;
        RECT  0 46.704 0.084 46.728 ;
    END
  END o[679]
  PIN o[67]
    DIRECTION OUTPUT ;
    USE SIGNAL ;
    PORT
      LAYER M4 ;
        RECT  0 102 0.084 102.024 ;
    END
  END o[67]
  PIN o[680]
    DIRECTION OUTPUT ;
    USE SIGNAL ;
    PORT
      LAYER M4 ;
        RECT  0 46.8 0.084 46.824 ;
    END
  END o[680]
  PIN o[681]
    DIRECTION OUTPUT ;
    USE SIGNAL ;
    PORT
      LAYER M4 ;
        RECT  0 46.896 0.084 46.92 ;
    END
  END o[681]
  PIN o[68]
    DIRECTION OUTPUT ;
    USE SIGNAL ;
    PORT
      LAYER M4 ;
        RECT  0 102.096 0.084 102.12 ;
    END
  END o[68]
  PIN o[69]
    DIRECTION OUTPUT ;
    USE SIGNAL ;
    PORT
      LAYER M4 ;
        RECT  0 102.192 0.084 102.216 ;
    END
  END o[69]
  PIN o[6]
    DIRECTION OUTPUT ;
    USE SIGNAL ;
    PORT
      LAYER M4 ;
        RECT  0 60.816 0.084 60.84 ;
    END
  END o[6]
  PIN o[70]
    DIRECTION OUTPUT ;
    USE SIGNAL ;
    PORT
      LAYER M4 ;
        RECT  0 102.288 0.084 102.312 ;
    END
  END o[70]
  PIN o[71]
    DIRECTION OUTPUT ;
    USE SIGNAL ;
    PORT
      LAYER M4 ;
        RECT  0 102.384 0.084 102.408 ;
    END
  END o[71]
  PIN o[72]
    DIRECTION OUTPUT ;
    USE SIGNAL ;
    PORT
      LAYER M4 ;
        RECT  0 102.48 0.084 102.504 ;
    END
  END o[72]
  PIN o[73]
    DIRECTION OUTPUT ;
    USE SIGNAL ;
    PORT
      LAYER M4 ;
        RECT  0 102.576 0.084 102.6 ;
    END
  END o[73]
  PIN o[74]
    DIRECTION OUTPUT ;
    USE SIGNAL ;
    PORT
      LAYER M4 ;
        RECT  0 102.672 0.084 102.696 ;
    END
  END o[74]
  PIN o[75]
    DIRECTION OUTPUT ;
    USE SIGNAL ;
    PORT
      LAYER M4 ;
        RECT  0 102.768 0.084 102.792 ;
    END
  END o[75]
  PIN o[76]
    DIRECTION OUTPUT ;
    USE SIGNAL ;
    PORT
      LAYER M4 ;
        RECT  0 102.864 0.084 102.888 ;
    END
  END o[76]
  PIN o[77]
    DIRECTION OUTPUT ;
    USE SIGNAL ;
    PORT
      LAYER M4 ;
        RECT  0 102.96 0.084 102.984 ;
    END
  END o[77]
  PIN o[78]
    DIRECTION OUTPUT ;
    USE SIGNAL ;
    PORT
      LAYER M4 ;
        RECT  0 103.056 0.084 103.08 ;
    END
  END o[78]
  PIN o[79]
    DIRECTION OUTPUT ;
    USE SIGNAL ;
    PORT
      LAYER M4 ;
        RECT  0 103.152 0.084 103.176 ;
    END
  END o[79]
  PIN o[7]
    DIRECTION OUTPUT ;
    USE SIGNAL ;
    PORT
      LAYER M4 ;
        RECT  0 60.912 0.084 60.936 ;
    END
  END o[7]
  PIN o[80]
    DIRECTION OUTPUT ;
    USE SIGNAL ;
    PORT
      LAYER M4 ;
        RECT  0 103.248 0.084 103.272 ;
    END
  END o[80]
  PIN o[81]
    DIRECTION OUTPUT ;
    USE SIGNAL ;
    PORT
      LAYER M4 ;
        RECT  0 103.344 0.084 103.368 ;
    END
  END o[81]
  PIN o[82]
    DIRECTION OUTPUT ;
    USE SIGNAL ;
    PORT
      LAYER M4 ;
        RECT  0 103.44 0.084 103.464 ;
    END
  END o[82]
  PIN o[83]
    DIRECTION OUTPUT ;
    USE SIGNAL ;
    PORT
      LAYER M4 ;
        RECT  0 103.536 0.084 103.56 ;
    END
  END o[83]
  PIN o[84]
    DIRECTION OUTPUT ;
    USE SIGNAL ;
    PORT
      LAYER M4 ;
        RECT  0 103.632 0.084 103.656 ;
    END
  END o[84]
  PIN o[85]
    DIRECTION OUTPUT ;
    USE SIGNAL ;
    PORT
      LAYER M4 ;
        RECT  0 103.728 0.084 103.752 ;
    END
  END o[85]
  PIN o[86]
    DIRECTION OUTPUT ;
    USE SIGNAL ;
    PORT
      LAYER M4 ;
        RECT  0 103.824 0.084 103.848 ;
    END
  END o[86]
  PIN o[87]
    DIRECTION OUTPUT ;
    USE SIGNAL ;
    PORT
      LAYER M4 ;
        RECT  0 103.92 0.084 103.944 ;
    END
  END o[87]
  PIN o[88]
    DIRECTION OUTPUT ;
    USE SIGNAL ;
    PORT
      LAYER M4 ;
        RECT  0 104.016 0.084 104.04 ;
    END
  END o[88]
  PIN o[89]
    DIRECTION OUTPUT ;
    USE SIGNAL ;
    PORT
      LAYER M4 ;
        RECT  0 104.112 0.084 104.136 ;
    END
  END o[89]
  PIN o[8]
    DIRECTION OUTPUT ;
    USE SIGNAL ;
    PORT
      LAYER M4 ;
        RECT  0 61.008 0.084 61.032 ;
    END
  END o[8]
  PIN o[90]
    DIRECTION OUTPUT ;
    USE SIGNAL ;
    PORT
      LAYER M4 ;
        RECT  0 104.208 0.084 104.232 ;
    END
  END o[90]
  PIN o[91]
    DIRECTION OUTPUT ;
    USE SIGNAL ;
    PORT
      LAYER M4 ;
        RECT  0 104.304 0.084 104.328 ;
    END
  END o[91]
  PIN o[92]
    DIRECTION OUTPUT ;
    USE SIGNAL ;
    PORT
      LAYER M4 ;
        RECT  0 104.4 0.084 104.424 ;
    END
  END o[92]
  PIN o[93]
    DIRECTION OUTPUT ;
    USE SIGNAL ;
    PORT
      LAYER M4 ;
        RECT  0 104.496 0.084 104.52 ;
    END
  END o[93]
  PIN o[94]
    DIRECTION OUTPUT ;
    USE SIGNAL ;
    PORT
      LAYER M4 ;
        RECT  0 69.264 0.084 69.288 ;
    END
  END o[94]
  PIN o[95]
    DIRECTION OUTPUT ;
    USE SIGNAL ;
    PORT
      LAYER M4 ;
        RECT  0 69.36 0.084 69.384 ;
    END
  END o[95]
  PIN o[96]
    DIRECTION OUTPUT ;
    USE SIGNAL ;
    PORT
      LAYER M4 ;
        RECT  0 69.456 0.084 69.48 ;
    END
  END o[96]
  PIN o[97]
    DIRECTION OUTPUT ;
    USE SIGNAL ;
    PORT
      LAYER M4 ;
        RECT  0 69.552 0.084 69.576 ;
    END
  END o[97]
  PIN o[98]
    DIRECTION OUTPUT ;
    USE SIGNAL ;
    PORT
      LAYER M4 ;
        RECT  0 69.648 0.084 69.672 ;
    END
  END o[98]
  PIN o[99]
    DIRECTION OUTPUT ;
    USE SIGNAL ;
    PORT
      LAYER M4 ;
        RECT  0 69.744 0.084 69.768 ;
    END
  END o[99]
  PIN o[9]
    DIRECTION OUTPUT ;
    USE SIGNAL ;
    PORT
      LAYER M4 ;
        RECT  0 61.104 0.084 61.128 ;
    END
  END o[9]
  PIN rs
    DIRECTION INPUT ;
    USE SIGNAL ;
    PORT
      LAYER M3 ;
        RECT  8.748 114.443 8.766 114.48 ;
    END
  END rs
  PIN VDD
    DIRECTION INOUT ;
    USE POWER ;
    PORT
      LAYER M5 ;
        RECT  37.692 2.151 37.812 112.329 ;
        RECT  34.992 2.151 35.112 112.329 ;
        RECT  32.292 2.151 32.412 112.329 ;
        RECT  29.592 2.151 29.712 112.329 ;
        RECT  26.892 2.151 27.012 112.329 ;
        RECT  24.192 2.151 24.312 112.329 ;
        RECT  21.492 2.151 21.612 112.329 ;
        RECT  18.792 2.151 18.912 112.329 ;
        RECT  16.092 2.151 16.212 112.329 ;
        RECT  13.392 2.151 13.512 112.329 ;
        RECT  10.692 2.151 10.812 112.329 ;
        RECT  7.992 2.151 8.112 112.329 ;
        RECT  5.292 2.151 5.412 112.329 ;
        RECT  2.592 2.151 2.712 112.329 ;
    END
  END VDD
  PIN VSS
    DIRECTION INOUT ;
    USE GROUND ;
    PORT
      LAYER M5 ;
        RECT  37.5 2.137 37.62 112.343 ;
        RECT  34.8 2.137 34.92 112.343 ;
        RECT  32.1 2.137 32.22 112.343 ;
        RECT  29.4 2.137 29.52 112.343 ;
        RECT  26.7 2.137 26.82 112.343 ;
        RECT  24 2.137 24.12 112.343 ;
        RECT  21.3 2.137 21.42 112.343 ;
        RECT  18.6 2.137 18.72 112.343 ;
        RECT  15.9 2.137 16.02 112.343 ;
        RECT  13.2 2.137 13.32 112.343 ;
        RECT  10.5 2.137 10.62 112.343 ;
        RECT  7.8 2.137 7.92 112.343 ;
        RECT  5.1 2.137 5.22 112.343 ;
        RECT  2.4 2.137 2.52 112.343 ;
    END
  END VSS
  OBS
    LAYER RVTN ;
     RECT  2.16 2.16 38.88 2.295 ;
     RECT  2.16 2.565 38.88 2.835 ;
     RECT  2.16 3.105 38.88 3.375 ;
     RECT  2.16 3.645 38.88 3.915 ;
     RECT  2.16 4.185 38.88 4.455 ;
     RECT  2.16 4.725 38.88 4.995 ;
     RECT  2.16 5.265 38.88 5.535 ;
     RECT  2.16 5.805 38.88 6.075 ;
     RECT  2.16 6.345 38.88 6.615 ;
     RECT  2.16 6.885 38.88 7.155 ;
     RECT  2.16 7.425 38.88 7.695 ;
     RECT  2.16 7.965 38.88 8.235 ;
     RECT  2.16 8.505 38.88 8.775 ;
     RECT  2.16 9.045 38.88 9.315 ;
     RECT  2.16 9.585 38.88 9.855 ;
     RECT  2.16 10.125 38.88 10.395 ;
     RECT  2.16 10.665 38.88 10.935 ;
     RECT  2.16 11.205 38.88 11.475 ;
     RECT  2.16 11.745 38.88 12.015 ;
     RECT  2.16 12.285 38.88 12.555 ;
     RECT  2.16 12.825 38.88 13.095 ;
     RECT  2.16 13.365 38.88 13.635 ;
     RECT  2.16 13.905 38.88 14.175 ;
     RECT  2.16 14.445 38.88 14.715 ;
     RECT  2.16 14.985 38.88 15.255 ;
     RECT  2.16 15.525 38.88 15.795 ;
     RECT  2.16 16.065 38.88 16.335 ;
     RECT  2.16 16.605 38.88 16.875 ;
     RECT  2.16 17.145 38.88 17.415 ;
     RECT  2.16 17.685 38.88 17.955 ;
     RECT  2.16 18.225 38.88 18.495 ;
     RECT  2.16 18.765 38.88 19.035 ;
     RECT  2.16 19.305 38.88 19.575 ;
     RECT  2.16 19.845 38.88 20.115 ;
     RECT  2.16 20.385 38.88 20.655 ;
     RECT  2.16 20.925 38.88 21.195 ;
     RECT  2.16 21.465 38.88 21.735 ;
     RECT  2.16 22.005 38.88 22.275 ;
     RECT  2.16 22.545 38.88 22.815 ;
     RECT  2.16 23.085 38.88 23.355 ;
     RECT  2.16 23.625 38.88 23.895 ;
     RECT  2.16 24.165 38.88 24.435 ;
     RECT  2.16 24.705 38.88 24.975 ;
     RECT  2.16 25.245 38.88 25.515 ;
     RECT  2.16 25.785 38.88 26.055 ;
     RECT  2.16 26.325 38.88 26.595 ;
     RECT  2.16 26.865 38.88 27.135 ;
     RECT  2.16 27.405 38.88 27.675 ;
     RECT  2.16 27.945 38.88 28.215 ;
     RECT  2.16 28.485 38.88 28.755 ;
     RECT  2.16 29.025 38.88 29.295 ;
     RECT  2.16 29.565 38.88 29.835 ;
     RECT  2.16 30.105 38.88 30.375 ;
     RECT  2.16 30.645 38.88 30.915 ;
     RECT  2.16 31.185 38.88 31.455 ;
     RECT  2.16 31.725 38.88 31.995 ;
     RECT  2.16 32.265 38.88 32.535 ;
     RECT  2.16 32.805 38.88 33.075 ;
     RECT  2.16 33.345 38.88 33.615 ;
     RECT  2.16 33.885 38.88 34.155 ;
     RECT  2.16 34.425 38.88 34.695 ;
     RECT  2.16 34.965 38.88 35.235 ;
     RECT  2.16 35.505 38.88 35.775 ;
     RECT  2.16 36.045 38.88 36.315 ;
     RECT  2.16 36.585 38.88 36.855 ;
     RECT  2.16 37.125 38.88 37.395 ;
     RECT  2.16 37.665 38.88 37.935 ;
     RECT  2.16 38.205 38.88 38.475 ;
     RECT  2.16 38.745 38.88 39.015 ;
     RECT  2.16 39.285 38.88 39.555 ;
     RECT  2.16 39.825 38.88 40.095 ;
     RECT  2.16 40.365 38.88 40.635 ;
     RECT  2.16 40.905 38.88 41.175 ;
     RECT  2.16 41.445 38.88 41.715 ;
     RECT  2.16 41.985 38.88 42.255 ;
     RECT  2.16 42.525 38.88 42.795 ;
     RECT  2.16 43.065 38.88 43.335 ;
     RECT  2.16 43.605 38.88 43.875 ;
     RECT  2.16 44.145 38.88 44.415 ;
     RECT  2.16 44.685 38.88 44.955 ;
     RECT  2.16 45.225 38.88 45.495 ;
     RECT  2.16 45.765 38.88 46.035 ;
     RECT  2.16 46.305 38.88 46.575 ;
     RECT  2.16 46.845 38.88 47.115 ;
     RECT  2.16 47.385 38.88 47.655 ;
     RECT  2.16 47.925 38.88 48.195 ;
     RECT  2.16 48.465 38.88 48.735 ;
     RECT  2.16 49.005 38.88 49.275 ;
     RECT  2.16 49.545 38.88 49.815 ;
     RECT  2.16 50.085 38.88 50.355 ;
     RECT  2.16 50.625 38.88 50.895 ;
     RECT  2.16 51.165 38.88 51.435 ;
     RECT  2.16 51.705 38.88 51.975 ;
     RECT  2.16 52.245 38.88 52.515 ;
     RECT  2.16 52.785 38.88 53.055 ;
     RECT  2.16 53.325 38.88 53.595 ;
     RECT  2.16 53.865 38.88 54.135 ;
     RECT  2.16 54.405 38.88 54.675 ;
     RECT  2.16 54.945 38.88 55.215 ;
     RECT  2.16 55.485 38.88 55.755 ;
     RECT  2.16 56.025 38.88 56.295 ;
     RECT  2.16 56.565 38.88 56.835 ;
     RECT  2.16 57.105 38.88 57.375 ;
     RECT  2.16 57.645 38.88 57.915 ;
     RECT  2.16 58.185 38.88 58.455 ;
     RECT  2.16 58.725 38.88 58.995 ;
     RECT  2.16 59.265 38.88 59.535 ;
     RECT  2.16 59.805 38.88 60.075 ;
     RECT  2.16 60.345 38.88 60.615 ;
     RECT  2.16 60.885 38.88 61.155 ;
     RECT  2.16 61.425 38.88 61.695 ;
     RECT  2.16 61.965 38.88 62.235 ;
     RECT  2.16 62.505 38.88 62.775 ;
     RECT  2.16 63.045 38.88 63.315 ;
     RECT  2.16 63.585 38.88 63.855 ;
     RECT  2.16 64.125 38.88 64.395 ;
     RECT  2.16 64.665 38.88 64.935 ;
     RECT  2.16 65.205 38.88 65.475 ;
     RECT  2.16 65.745 38.88 66.015 ;
     RECT  2.16 66.285 38.88 66.555 ;
     RECT  2.16 66.825 38.88 67.095 ;
     RECT  2.16 67.365 38.88 67.635 ;
     RECT  2.16 67.905 38.88 68.175 ;
     RECT  2.16 68.445 38.88 68.715 ;
     RECT  2.16 68.985 38.88 69.255 ;
     RECT  2.16 69.525 38.88 69.795 ;
     RECT  2.16 70.065 38.88 70.335 ;
     RECT  2.16 70.605 38.88 70.875 ;
     RECT  2.16 71.145 38.88 71.415 ;
     RECT  2.16 71.685 38.88 71.955 ;
     RECT  2.16 72.225 38.88 72.495 ;
     RECT  2.16 72.765 38.88 73.035 ;
     RECT  2.16 73.305 38.88 73.575 ;
     RECT  2.16 73.845 38.88 74.115 ;
     RECT  2.16 74.385 38.88 74.655 ;
     RECT  2.16 74.925 38.88 75.195 ;
     RECT  2.16 75.465 38.88 75.735 ;
     RECT  2.16 76.005 38.88 76.275 ;
     RECT  2.16 76.545 38.88 76.815 ;
     RECT  2.16 77.085 38.88 77.355 ;
     RECT  2.16 77.625 38.88 77.895 ;
     RECT  2.16 78.165 38.88 78.435 ;
     RECT  2.16 78.705 38.88 78.975 ;
     RECT  2.16 79.245 38.88 79.515 ;
     RECT  2.16 79.785 38.88 80.055 ;
     RECT  2.16 80.325 38.88 80.595 ;
     RECT  2.16 80.865 38.88 81.135 ;
     RECT  2.16 81.405 38.88 81.675 ;
     RECT  2.16 81.945 38.88 82.215 ;
     RECT  2.16 82.485 38.88 82.755 ;
     RECT  2.16 83.025 38.88 83.295 ;
     RECT  2.16 83.565 38.88 83.835 ;
     RECT  2.16 84.105 38.88 84.375 ;
     RECT  2.16 84.645 38.88 84.915 ;
     RECT  2.16 85.185 38.88 85.455 ;
     RECT  2.16 85.725 38.88 85.995 ;
     RECT  2.16 86.265 38.88 86.535 ;
     RECT  2.16 86.805 38.88 87.075 ;
     RECT  2.16 87.345 38.88 87.615 ;
     RECT  2.16 87.885 38.88 88.155 ;
     RECT  2.16 88.425 38.88 88.695 ;
     RECT  2.16 88.965 38.88 89.235 ;
     RECT  2.16 89.505 38.88 89.775 ;
     RECT  2.16 90.045 38.88 90.315 ;
     RECT  2.16 90.585 38.88 90.855 ;
     RECT  2.16 91.125 38.88 91.395 ;
     RECT  2.16 91.665 38.88 91.935 ;
     RECT  2.16 92.205 38.88 92.475 ;
     RECT  2.16 92.745 38.88 93.015 ;
     RECT  2.16 93.285 38.88 93.555 ;
     RECT  2.16 93.825 38.88 94.095 ;
     RECT  2.16 94.365 38.88 94.635 ;
     RECT  2.16 94.905 38.88 95.175 ;
     RECT  2.16 95.445 38.88 95.715 ;
     RECT  2.16 95.985 38.88 96.255 ;
     RECT  2.16 96.525 38.88 96.795 ;
     RECT  2.16 97.065 38.88 97.335 ;
     RECT  2.16 97.605 38.88 97.875 ;
     RECT  2.16 98.145 38.88 98.415 ;
     RECT  2.16 98.685 38.88 98.955 ;
     RECT  2.16 99.225 38.88 99.495 ;
     RECT  2.16 99.765 38.88 100.035 ;
     RECT  2.16 100.305 38.88 100.575 ;
     RECT  2.16 100.845 38.88 101.115 ;
     RECT  2.16 101.385 38.88 101.655 ;
     RECT  2.16 101.925 38.88 102.195 ;
     RECT  2.16 102.465 38.88 102.735 ;
     RECT  2.16 103.005 38.88 103.275 ;
     RECT  2.16 103.545 38.88 103.815 ;
     RECT  2.16 104.085 38.88 104.355 ;
     RECT  2.16 104.625 38.88 104.895 ;
     RECT  2.16 105.165 38.88 105.435 ;
     RECT  2.16 105.705 38.88 105.975 ;
     RECT  2.16 106.245 38.88 106.515 ;
     RECT  2.16 106.785 38.88 107.055 ;
     RECT  2.16 107.325 38.88 107.595 ;
     RECT  2.16 107.865 38.88 108.135 ;
     RECT  2.16 108.405 38.88 108.675 ;
     RECT  2.16 108.945 38.88 109.215 ;
     RECT  2.16 109.485 38.88 109.755 ;
     RECT  2.16 110.025 38.88 110.295 ;
     RECT  2.16 110.565 38.88 110.835 ;
     RECT  2.16 111.105 38.88 111.375 ;
     RECT  2.16 111.645 38.88 111.915 ;
     RECT  2.16 112.185 38.88 112.32 ;
    LAYER RVTP ;
     RECT  2.16 2.295 38.88 2.565 ;
     RECT  2.16 2.835 38.88 3.105 ;
     RECT  2.16 3.375 38.88 3.645 ;
     RECT  2.16 3.915 38.88 4.185 ;
     RECT  2.16 4.455 38.88 4.725 ;
     RECT  2.16 4.995 38.88 5.265 ;
     RECT  2.16 5.535 38.88 5.805 ;
     RECT  2.16 6.075 38.88 6.345 ;
     RECT  2.16 6.615 38.88 6.885 ;
     RECT  2.16 7.155 38.88 7.425 ;
     RECT  2.16 7.695 38.88 7.965 ;
     RECT  2.16 8.235 38.88 8.505 ;
     RECT  2.16 8.775 38.88 9.045 ;
     RECT  2.16 9.315 38.88 9.585 ;
     RECT  2.16 9.855 38.88 10.125 ;
     RECT  2.16 10.395 38.88 10.665 ;
     RECT  2.16 10.935 38.88 11.205 ;
     RECT  2.16 11.475 38.88 11.745 ;
     RECT  2.16 12.015 38.88 12.285 ;
     RECT  2.16 12.555 38.88 12.825 ;
     RECT  2.16 13.095 38.88 13.365 ;
     RECT  2.16 13.635 38.88 13.905 ;
     RECT  2.16 14.175 38.88 14.445 ;
     RECT  2.16 14.715 38.88 14.985 ;
     RECT  2.16 15.255 38.88 15.525 ;
     RECT  2.16 15.795 38.88 16.065 ;
     RECT  2.16 16.335 38.88 16.605 ;
     RECT  2.16 16.875 38.88 17.145 ;
     RECT  2.16 17.415 38.88 17.685 ;
     RECT  2.16 17.955 38.88 18.225 ;
     RECT  2.16 18.495 38.88 18.765 ;
     RECT  2.16 19.035 38.88 19.305 ;
     RECT  2.16 19.575 38.88 19.845 ;
     RECT  2.16 20.115 38.88 20.385 ;
     RECT  2.16 20.655 38.88 20.925 ;
     RECT  2.16 21.195 38.88 21.465 ;
     RECT  2.16 21.735 38.88 22.005 ;
     RECT  2.16 22.275 38.88 22.545 ;
     RECT  2.16 22.815 38.88 23.085 ;
     RECT  2.16 23.355 38.88 23.625 ;
     RECT  2.16 23.895 38.88 24.165 ;
     RECT  2.16 24.435 38.88 24.705 ;
     RECT  2.16 24.975 38.88 25.245 ;
     RECT  2.16 25.515 38.88 25.785 ;
     RECT  2.16 26.055 38.88 26.325 ;
     RECT  2.16 26.595 38.88 26.865 ;
     RECT  2.16 27.135 38.88 27.405 ;
     RECT  2.16 27.675 38.88 27.945 ;
     RECT  2.16 28.215 38.88 28.485 ;
     RECT  2.16 28.755 38.88 29.025 ;
     RECT  2.16 29.295 38.88 29.565 ;
     RECT  2.16 29.835 38.88 30.105 ;
     RECT  2.16 30.375 38.88 30.645 ;
     RECT  2.16 30.915 38.88 31.185 ;
     RECT  2.16 31.455 38.88 31.725 ;
     RECT  2.16 31.995 38.88 32.265 ;
     RECT  2.16 32.535 38.88 32.805 ;
     RECT  2.16 33.075 38.88 33.345 ;
     RECT  2.16 33.615 38.88 33.885 ;
     RECT  2.16 34.155 38.88 34.425 ;
     RECT  2.16 34.695 38.88 34.965 ;
     RECT  2.16 35.235 38.88 35.505 ;
     RECT  2.16 35.775 38.88 36.045 ;
     RECT  2.16 36.315 38.88 36.585 ;
     RECT  2.16 36.855 38.88 37.125 ;
     RECT  2.16 37.395 38.88 37.665 ;
     RECT  2.16 37.935 38.88 38.205 ;
     RECT  2.16 38.475 38.88 38.745 ;
     RECT  2.16 39.015 38.88 39.285 ;
     RECT  2.16 39.555 38.88 39.825 ;
     RECT  2.16 40.095 38.88 40.365 ;
     RECT  2.16 40.635 38.88 40.905 ;
     RECT  2.16 41.175 38.88 41.445 ;
     RECT  2.16 41.715 38.88 41.985 ;
     RECT  2.16 42.255 38.88 42.525 ;
     RECT  2.16 42.795 38.88 43.065 ;
     RECT  2.16 43.335 38.88 43.605 ;
     RECT  2.16 43.875 38.88 44.145 ;
     RECT  2.16 44.415 38.88 44.685 ;
     RECT  2.16 44.955 38.88 45.225 ;
     RECT  2.16 45.495 38.88 45.765 ;
     RECT  2.16 46.035 38.88 46.305 ;
     RECT  2.16 46.575 38.88 46.845 ;
     RECT  2.16 47.115 38.88 47.385 ;
     RECT  2.16 47.655 38.88 47.925 ;
     RECT  2.16 48.195 38.88 48.465 ;
     RECT  2.16 48.735 38.88 49.005 ;
     RECT  2.16 49.275 38.88 49.545 ;
     RECT  2.16 49.815 38.88 50.085 ;
     RECT  2.16 50.355 38.88 50.625 ;
     RECT  2.16 50.895 38.88 51.165 ;
     RECT  2.16 51.435 38.88 51.705 ;
     RECT  2.16 51.975 38.88 52.245 ;
     RECT  2.16 52.515 38.88 52.785 ;
     RECT  2.16 53.055 38.88 53.325 ;
     RECT  2.16 53.595 38.88 53.865 ;
     RECT  2.16 54.135 38.88 54.405 ;
     RECT  2.16 54.675 38.88 54.945 ;
     RECT  2.16 55.215 38.88 55.485 ;
     RECT  2.16 55.755 38.88 56.025 ;
     RECT  2.16 56.295 38.88 56.565 ;
     RECT  2.16 56.835 38.88 57.105 ;
     RECT  2.16 57.375 38.88 57.645 ;
     RECT  2.16 57.915 38.88 58.185 ;
     RECT  2.16 58.455 38.88 58.725 ;
     RECT  2.16 58.995 38.88 59.265 ;
     RECT  2.16 59.535 38.88 59.805 ;
     RECT  2.16 60.075 38.88 60.345 ;
     RECT  2.16 60.615 38.88 60.885 ;
     RECT  2.16 61.155 38.88 61.425 ;
     RECT  2.16 61.695 38.88 61.965 ;
     RECT  2.16 62.235 38.88 62.505 ;
     RECT  2.16 62.775 38.88 63.045 ;
     RECT  2.16 63.315 38.88 63.585 ;
     RECT  2.16 63.855 38.88 64.125 ;
     RECT  2.16 64.395 38.88 64.665 ;
     RECT  2.16 64.935 38.88 65.205 ;
     RECT  2.16 65.475 38.88 65.745 ;
     RECT  2.16 66.015 38.88 66.285 ;
     RECT  2.16 66.555 38.88 66.825 ;
     RECT  2.16 67.095 38.88 67.365 ;
     RECT  2.16 67.635 38.88 67.905 ;
     RECT  2.16 68.175 38.88 68.445 ;
     RECT  2.16 68.715 38.88 68.985 ;
     RECT  2.16 69.255 38.88 69.525 ;
     RECT  2.16 69.795 38.88 70.065 ;
     RECT  2.16 70.335 38.88 70.605 ;
     RECT  2.16 70.875 38.88 71.145 ;
     RECT  2.16 71.415 38.88 71.685 ;
     RECT  2.16 71.955 38.88 72.225 ;
     RECT  2.16 72.495 38.88 72.765 ;
     RECT  2.16 73.035 38.88 73.305 ;
     RECT  2.16 73.575 38.88 73.845 ;
     RECT  2.16 74.115 38.88 74.385 ;
     RECT  2.16 74.655 38.88 74.925 ;
     RECT  2.16 75.195 38.88 75.465 ;
     RECT  2.16 75.735 38.88 76.005 ;
     RECT  2.16 76.275 38.88 76.545 ;
     RECT  2.16 76.815 38.88 77.085 ;
     RECT  2.16 77.355 38.88 77.625 ;
     RECT  2.16 77.895 38.88 78.165 ;
     RECT  2.16 78.435 38.88 78.705 ;
     RECT  2.16 78.975 38.88 79.245 ;
     RECT  2.16 79.515 38.88 79.785 ;
     RECT  2.16 80.055 38.88 80.325 ;
     RECT  2.16 80.595 38.88 80.865 ;
     RECT  2.16 81.135 38.88 81.405 ;
     RECT  2.16 81.675 38.88 81.945 ;
     RECT  2.16 82.215 38.88 82.485 ;
     RECT  2.16 82.755 38.88 83.025 ;
     RECT  2.16 83.295 38.88 83.565 ;
     RECT  2.16 83.835 38.88 84.105 ;
     RECT  2.16 84.375 38.88 84.645 ;
     RECT  2.16 84.915 38.88 85.185 ;
     RECT  2.16 85.455 38.88 85.725 ;
     RECT  2.16 85.995 38.88 86.265 ;
     RECT  2.16 86.535 38.88 86.805 ;
     RECT  2.16 87.075 38.88 87.345 ;
     RECT  2.16 87.615 38.88 87.885 ;
     RECT  2.16 88.155 38.88 88.425 ;
     RECT  2.16 88.695 38.88 88.965 ;
     RECT  2.16 89.235 38.88 89.505 ;
     RECT  2.16 89.775 38.88 90.045 ;
     RECT  2.16 90.315 38.88 90.585 ;
     RECT  2.16 90.855 38.88 91.125 ;
     RECT  2.16 91.395 38.88 91.665 ;
     RECT  2.16 91.935 38.88 92.205 ;
     RECT  2.16 92.475 38.88 92.745 ;
     RECT  2.16 93.015 38.88 93.285 ;
     RECT  2.16 93.555 38.88 93.825 ;
     RECT  2.16 94.095 38.88 94.365 ;
     RECT  2.16 94.635 38.88 94.905 ;
     RECT  2.16 95.175 38.88 95.445 ;
     RECT  2.16 95.715 38.88 95.985 ;
     RECT  2.16 96.255 38.88 96.525 ;
     RECT  2.16 96.795 38.88 97.065 ;
     RECT  2.16 97.335 38.88 97.605 ;
     RECT  2.16 97.875 38.88 98.145 ;
     RECT  2.16 98.415 38.88 98.685 ;
     RECT  2.16 98.955 38.88 99.225 ;
     RECT  2.16 99.495 38.88 99.765 ;
     RECT  2.16 100.035 38.88 100.305 ;
     RECT  2.16 100.575 38.88 100.845 ;
     RECT  2.16 101.115 38.88 101.385 ;
     RECT  2.16 101.655 38.88 101.925 ;
     RECT  2.16 102.195 38.88 102.465 ;
     RECT  2.16 102.735 38.88 103.005 ;
     RECT  2.16 103.275 38.88 103.545 ;
     RECT  2.16 103.815 38.88 104.085 ;
     RECT  2.16 104.355 38.88 104.625 ;
     RECT  2.16 104.895 38.88 105.165 ;
     RECT  2.16 105.435 38.88 105.705 ;
     RECT  2.16 105.975 38.88 106.245 ;
     RECT  2.16 106.515 38.88 106.785 ;
     RECT  2.16 107.055 38.88 107.325 ;
     RECT  2.16 107.595 38.88 107.865 ;
     RECT  2.16 108.135 38.88 108.405 ;
     RECT  2.16 108.675 38.88 108.945 ;
     RECT  2.16 109.215 38.88 109.485 ;
     RECT  2.16 109.755 38.88 110.025 ;
     RECT  2.16 110.295 38.88 110.565 ;
     RECT  2.16 110.835 38.88 111.105 ;
     RECT  2.16 111.375 38.88 111.645 ;
     RECT  2.16 111.915 38.88 112.185 ;
    LAYER M1 ;
     RECT  2.16 2.151 38.88 112.329 ;
    LAYER M2 ;
     RECT  0.031 70.65 0.103 71.172 ;
     RECT  0.103 69.966 0.131 71.172 ;
     RECT  0.103 18.738 0.139 18.756 ;
     RECT  0.103 20.781 0.139 20.799 ;
     RECT  0.103 59.661 0.139 60.264 ;
     RECT  0.103 68.796 0.139 68.814 ;
     RECT  0.131 69.966 0.139 71.1 ;
     RECT  0.103 72.846 0.139 72.864 ;
     RECT  0.103 87.588 0.139 88.344 ;
     RECT  0.103 95.724 0.139 95.742 ;
     RECT  0.103 100.206 0.139 100.224 ;
     RECT  0.103 103.482 0.139 104.004 ;
     RECT  0.103 104.796 0.139 105.624 ;
     RECT  0.139 75.636 0.175 75.654 ;
     RECT  0.103 76.482 0.175 78.084 ;
     RECT  0.103 86.616 0.175 86.634 ;
     RECT  0.139 87.516 0.175 88.344 ;
     RECT  0.103 98.586 0.175 99.324 ;
     RECT  0.139 100.206 0.175 100.944 ;
     RECT  0.103 12.996 0.203 13.194 ;
     RECT  0.103 21.816 0.203 21.834 ;
     RECT  0.103 55.188 0.203 55.899 ;
     RECT  0.139 68.796 0.203 71.1 ;
     RECT  0.175 75.636 0.203 78.084 ;
     RECT  0.103 102.402 0.203 102.654 ;
     RECT  0.139 20.394 0.211 20.799 ;
     RECT  0.139 51.786 0.211 51.804 ;
     RECT  0.211 51.444 0.239 51.804 ;
     RECT  0.203 55.188 0.239 55.206 ;
     RECT  0.175 86.616 0.239 88.344 ;
     RECT  0.103 6.246 0.247 6.264 ;
     RECT  0.239 51.444 0.311 51.624 ;
     RECT  0.211 19.854 0.347 20.799 ;
     RECT  0.103 27.612 0.383 27.63 ;
     RECT  0.247 6.246 0.391 6.759 ;
     RECT  0.103 37.566 0.463 38.664 ;
     RECT  0.427 49.986 0.463 50.004 ;
     RECT  0.175 98.586 0.463 100.944 ;
     RECT  0.103 4.896 0.499 4.914 ;
     RECT  0.103 24.642 0.499 24.66 ;
     RECT  0.463 37.566 0.499 39.204 ;
     RECT  0.103 45.666 0.499 45.684 ;
     RECT  0.463 49.716 0.499 50.004 ;
     RECT  0.103 57.816 0.499 57.834 ;
     RECT  0.139 59.508 0.499 60.264 ;
     RECT  0.103 84.816 0.499 84.834 ;
     RECT  0.499 4.896 0.535 5.454 ;
     RECT  0.391 6.246 0.535 6.804 ;
     RECT  0.499 11.214 0.535 11.232 ;
     RECT  0.499 24.642 0.535 25.164 ;
     RECT  0.499 37.026 0.535 39.204 ;
     RECT  0.499 45.666 0.535 45.954 ;
     RECT  0.499 49.446 0.535 50.004 ;
     RECT  0.103 58.698 0.535 58.716 ;
     RECT  0.499 59.508 0.535 60.984 ;
     RECT  0.139 72.126 0.535 73.368 ;
     RECT  0.103 74.358 0.535 74.376 ;
     RECT  0.499 84.816 0.535 85.104 ;
     RECT  0.239 86.616 0.535 86.994 ;
     RECT  0.239 88.128 0.535 88.344 ;
     RECT  0.463 98.226 0.535 100.944 ;
     RECT  0.463 41.994 0.563 42.588 ;
     RECT  0.535 11.214 0.571 11.304 ;
     RECT  0.535 58.698 0.635 61.794 ;
     RECT  0.535 97.956 0.635 101.844 ;
     RECT  0.535 97.074 1.147 97.092 ;
     RECT  0.535 22.716 1.175 23.184 ;
     RECT  1.147 97.074 1.175 97.164 ;
     RECT  0.535 4.896 2.16 7.722 ;
     RECT  0.535 9.666 2.16 9.684 ;
     RECT  0.571 10.836 2.16 11.304 ;
     RECT  0.203 12.996 2.16 13.014 ;
     RECT  0.139 18.126 2.16 18.756 ;
     RECT  0.347 19.854 2.16 19.872 ;
     RECT  0.535 20.826 2.16 20.844 ;
     RECT  0.535 21.636 2.16 21.654 ;
     RECT  1.175 22.716 2.16 23.112 ;
     RECT  0.535 24.408 2.16 26.784 ;
     RECT  0.535 37.026 2.16 39.888 ;
     RECT  0.563 41.994 2.16 42.048 ;
     RECT  0.535 45.576 2.16 45.954 ;
     RECT  0.535 49.446 2.16 50.076 ;
     RECT  0.311 51.606 2.16 51.624 ;
     RECT  0.535 52.992 2.16 53.01 ;
     RECT  0.535 56.466 2.16 56.484 ;
     RECT  0.499 57.456 2.16 57.834 ;
     RECT  0.635 58.698 2.16 61.074 ;
     RECT  0.103 62.676 2.16 62.694 ;
     RECT  0.283 63.594 2.16 63.612 ;
     RECT  0.203 68.796 2.16 71.064 ;
     RECT  0.535 72.126 2.16 74.376 ;
     RECT  0.203 75.636 2.16 76.644 ;
     RECT  0.203 77.904 2.16 78.084 ;
     RECT  0.535 84.816 2.16 85.176 ;
     RECT  0.535 85.968 2.16 86.994 ;
     RECT  0.535 88.128 2.16 88.686 ;
     RECT  0.535 90.558 2.16 90.576 ;
     RECT  0.139 95.076 2.16 95.742 ;
     RECT  1.175 97.146 2.16 97.164 ;
     RECT  0.635 97.956 2.16 101.448 ;
     RECT  0.535 102.672 2.16 102.69 ;
     RECT  0.139 103.482 2.16 105.624 ;
     RECT  8.635 114.426 8.671 114.444 ;
     RECT  8.671 114.354 8.771 114.444 ;
     RECT  2.16 2.151 11.263 112.329 ;
     RECT  11.263 2.106 14.495 112.329 ;
     RECT  14.495 2.151 27.607 112.329 ;
     RECT  27.607 2.106 27.887 112.329 ;
     RECT  27.887 2.151 38.88 112.329 ;
     RECT  38.88 32.04 39.047 32.094 ;
     RECT  38.88 47.394 39.083 47.484 ;
     RECT  38.88 82.998 39.083 90.342 ;
     RECT  38.88 19.044 39.119 29.898 ;
     RECT  38.88 91.098 39.191 95.706 ;
     RECT  38.88 67.14 39.335 78.228 ;
     RECT  39.083 83.34 39.335 90.342 ;
     RECT  38.88 58.536 39.371 64.926 ;
     RECT  38.88 3.15 39.623 6.336 ;
     RECT  38.88 30.69 39.623 31.176 ;
     RECT  38.88 33.156 39.623 37.422 ;
     RECT  38.88 79.596 39.623 79.614 ;
     RECT  39.623 3.69 39.659 6.336 ;
     RECT  39.623 30.888 39.659 31.176 ;
     RECT  39.335 67.14 39.659 74.106 ;
     RECT  39.659 4.086 39.695 6.336 ;
     RECT  39.119 19.044 39.695 29.358 ;
     RECT  39.335 83.34 39.695 88.92 ;
     RECT  39.659 30.96 39.731 31.176 ;
     RECT  39.695 19.044 39.767 25.506 ;
     RECT  39.191 91.098 39.767 94.932 ;
     RECT  39.659 73.08 39.839 74.106 ;
     RECT  38.88 7.2 39.875 16.974 ;
     RECT  38.88 38.286 39.875 45.954 ;
     RECT  39.659 67.14 39.875 72.324 ;
     RECT  39.767 19.044 39.911 21.798 ;
     RECT  39.767 22.788 39.911 25.506 ;
     RECT  39.875 40.266 39.911 45.954 ;
     RECT  38.88 49.356 39.911 57.708 ;
     RECT  39.695 83.34 39.911 87.642 ;
     RECT  39.695 88.398 39.911 88.92 ;
     RECT  39.335 89.82 39.911 90.342 ;
     RECT  38.88 96.606 39.911 110.394 ;
     RECT  39.695 4.266 39.947 6.336 ;
     RECT  39.875 7.2 39.947 9.846 ;
     RECT  39.875 10.674 39.947 16.974 ;
     RECT  39.911 19.044 39.947 21.528 ;
     RECT  39.911 57.114 39.947 57.708 ;
     RECT  39.767 91.098 39.947 92.196 ;
     RECT  39.911 96.606 39.947 104.724 ;
     RECT  39.947 97.38 39.983 104.724 ;
     RECT  39.947 4.77 40.019 6.336 ;
     RECT  39.947 7.2 40.199 7.299 ;
     RECT  39.731 30.96 40.199 30.978 ;
     RECT  39.623 33.552 40.199 37.422 ;
     RECT  38.88 81.216 40.199 81.234 ;
     RECT  39.911 49.356 40.235 56.286 ;
     RECT  39.911 83.34 40.235 86.328 ;
     RECT  40.019 5.238 40.271 6.336 ;
     RECT  38.88 17.928 40.271 18.252 ;
     RECT  40.235 50.598 40.307 56.286 ;
     RECT  39.767 93.06 40.307 94.932 ;
     RECT  39.911 22.788 40.343 25.344 ;
     RECT  39.875 70.074 40.415 72.324 ;
     RECT  39.911 105.786 40.415 110.394 ;
     RECT  39.947 20.16 40.451 21.528 ;
     RECT  39.875 38.286 40.451 39.312 ;
     RECT  39.947 8.046 40.487 9.846 ;
     RECT  39.947 10.71 40.487 16.974 ;
     RECT  40.343 23.022 40.487 25.344 ;
     RECT  39.695 26.298 40.487 29.358 ;
     RECT  40.199 34.056 40.487 37.422 ;
     RECT  40.451 38.286 40.487 38.844 ;
     RECT  39.911 40.266 40.487 41.544 ;
     RECT  39.911 42.336 40.487 45.954 ;
     RECT  40.307 50.634 40.487 56.286 ;
     RECT  39.371 58.536 40.487 60.372 ;
     RECT  39.371 61.164 40.487 64.926 ;
     RECT  38.88 66.096 40.487 66.114 ;
     RECT  40.415 70.074 40.487 72.288 ;
     RECT  39.839 73.08 40.487 73.908 ;
     RECT  40.235 83.646 40.487 86.328 ;
     RECT  39.911 88.434 40.487 88.92 ;
     RECT  39.947 96.606 40.487 96.624 ;
     RECT  39.983 97.614 40.487 104.724 ;
     RECT  40.415 105.786 40.487 109.782 ;
     RECT  40.487 11.52 40.523 14.544 ;
     RECT  40.487 23.022 40.523 23.382 ;
     RECT  40.487 26.298 40.523 26.964 ;
     RECT  40.487 27.756 40.523 28.206 ;
     RECT  40.487 35.046 40.523 37.422 ;
     RECT  40.487 43.65 40.523 45.954 ;
     RECT  40.487 51.48 40.523 56.286 ;
     RECT  39.875 67.14 40.523 69.084 ;
     RECT  40.487 88.47 40.523 88.794 ;
     RECT  40.307 93.06 40.523 94.734 ;
     RECT  39.191 95.688 40.523 95.706 ;
     RECT  40.487 97.686 40.523 104.724 ;
     RECT  40.487 106.146 40.523 106.812 ;
     RECT  40.523 11.646 40.559 13.122 ;
     RECT  40.487 38.286 40.559 38.808 ;
     RECT  40.523 51.48 40.559 55.854 ;
     RECT  39.911 87.201 40.559 87.642 ;
     RECT  40.523 97.686 40.559 98.91 ;
     RECT  40.523 100.008 40.559 104.688 ;
     RECT  40.487 40.878 40.595 41.544 ;
     RECT  40.523 67.14 40.595 69.048 ;
     RECT  39.335 75.006 40.595 78.228 ;
     RECT  40.559 87.624 40.595 87.642 ;
     RECT  40.451 20.16 40.631 21.456 ;
     RECT  40.487 24.372 40.631 25.344 ;
     RECT  40.595 41.454 40.631 41.544 ;
     RECT  40.559 51.48 40.631 54.702 ;
     RECT  40.523 88.776 40.631 88.794 ;
     RECT  39.947 91.098 40.631 91.962 ;
     RECT  40.271 18.234 40.639 18.252 ;
     RECT  39.947 19.044 40.639 19.224 ;
     RECT  40.487 8.172 40.667 9.846 ;
     RECT  40.235 49.356 40.667 49.77 ;
     RECT  40.631 51.48 40.667 53.424 ;
     RECT  40.631 54.414 40.667 54.702 ;
     RECT  40.487 16.956 40.675 16.974 ;
     RECT  40.631 41.526 40.703 41.544 ;
     RECT  40.667 53.406 40.703 53.424 ;
     RECT  40.595 75.168 40.703 78.228 ;
     RECT  40.487 50.634 40.739 50.652 ;
     RECT  40.667 51.48 40.739 52.659 ;
     RECT  40.487 64.908 40.739 64.926 ;
     RECT  40.703 76.518 40.739 78.228 ;
     RECT  40.667 8.442 40.775 9.846 ;
     RECT  40.523 14.526 40.775 14.544 ;
     RECT  40.675 16.956 40.775 17.208 ;
     RECT  40.667 49.356 40.775 49.374 ;
     RECT  40.487 63.09 40.775 63.918 ;
     RECT  40.739 78.102 40.775 78.192 ;
     RECT  40.523 93.87 40.775 94.734 ;
     RECT  40.639 18.234 40.783 19.224 ;
     RECT  40.631 20.16 40.783 21.258 ;
     RECT  40.487 61.164 40.783 62.262 ;
     RECT  40.271 5.814 40.811 6.336 ;
     RECT  40.523 35.748 40.811 37.422 ;
     RECT  40.739 51.48 40.811 52.578 ;
     RECT  40.783 61.011 40.811 62.262 ;
     RECT  40.703 75.168 40.811 75.726 ;
     RECT  40.487 85.392 40.811 86.328 ;
     RECT  40.775 8.55 40.847 9.846 ;
     RECT  40.559 13.104 40.847 13.122 ;
     RECT  40.775 17.118 40.847 17.208 ;
     RECT  40.811 37.368 40.847 37.422 ;
     RECT  40.559 38.286 40.847 38.304 ;
     RECT  40.487 58.536 40.847 59.832 ;
     RECT  40.595 67.14 40.847 68.634 ;
     RECT  40.775 93.87 40.847 94.194 ;
     RECT  40.487 107.676 40.847 109.782 ;
     RECT  40.523 26.298 40.855 26.469 ;
     RECT  40.487 42.336 40.855 42.75 ;
     RECT  39.947 57.114 40.855 57.294 ;
     RECT  40.847 58.536 40.855 59.328 ;
     RECT  40.783 18.234 40.883 21.258 ;
     RECT  40.631 24.372 40.883 24.498 ;
     RECT  40.523 28.188 40.883 28.206 ;
     RECT  40.847 37.404 40.883 37.422 ;
     RECT  40.523 44.001 40.883 45.954 ;
     RECT  39.083 47.43 40.883 47.484 ;
     RECT  40.847 67.374 40.883 68.634 ;
     RECT  40.739 76.518 40.883 77.184 ;
     RECT  40.811 85.392 40.883 85.41 ;
     RECT  40.523 106.218 40.883 106.812 ;
     RECT  40.847 109.188 40.883 109.782 ;
     RECT  40.199 7.236 40.919 7.299 ;
     RECT  40.847 8.55 40.919 9.144 ;
     RECT  40.487 10.71 40.919 10.728 ;
     RECT  40.487 15.57 40.919 15.984 ;
     RECT  40.847 17.19 40.919 17.208 ;
     RECT  40.883 18.234 40.919 18.252 ;
     RECT  40.883 19.746 40.919 21.258 ;
     RECT  40.811 35.748 40.919 36.108 ;
     RECT  40.883 44.001 40.919 45.756 ;
     RECT  40.783 49.014 40.919 49.032 ;
     RECT  40.811 51.48 40.919 51.894 ;
     RECT  40.667 54.684 40.919 54.702 ;
     RECT  40.811 61.011 40.919 61.569 ;
     RECT  40.487 70.146 40.919 72.288 ;
     RECT  40.487 73.08 40.919 73.332 ;
     RECT  40.883 76.518 40.919 76.806 ;
     RECT  40.775 78.102 40.919 78.12 ;
     RECT  40.487 83.646 40.919 84.636 ;
     RECT  40.631 91.17 40.919 91.962 ;
     RECT  40.559 104.598 40.919 104.688 ;
     RECT  40.847 107.676 40.919 108.198 ;
     RECT  40.883 109.188 40.919 109.44 ;
     RECT  39.911 89.946 40.927 90.342 ;
     RECT  40.919 9.09 40.955 9.108 ;
     RECT  40.559 11.646 40.955 12.078 ;
     RECT  40.919 15.876 40.955 15.984 ;
     RECT  40.919 19.746 40.955 19.764 ;
     RECT  40.919 21.168 40.955 21.258 ;
     RECT  40.523 23.166 40.955 23.382 ;
     RECT  40.883 24.48 40.955 24.498 ;
     RECT  40.855 25.524 40.955 26.469 ;
     RECT  40.487 34.056 40.955 34.074 ;
     RECT  40.919 35.748 40.955 35.838 ;
     RECT  40.855 41.796 40.955 42.75 ;
     RECT  40.919 44.001 40.955 44.982 ;
     RECT  40.559 55.458 40.955 55.854 ;
     RECT  40.855 57.114 40.955 57.366 ;
     RECT  40.855 58.5 40.955 59.328 ;
     RECT  40.919 61.056 40.955 61.299 ;
     RECT  40.775 63.09 40.955 63.108 ;
     RECT  40.775 63.9 40.955 63.918 ;
     RECT  40.883 68.184 40.955 68.634 ;
     RECT  40.919 70.146 40.955 71.748 ;
     RECT  40.919 73.08 40.955 73.098 ;
     RECT  40.811 75.168 40.955 75.186 ;
     RECT  40.919 76.626 40.955 76.806 ;
     RECT  40.919 84.618 40.955 84.636 ;
     RECT  40.927 89.712 40.955 90.342 ;
     RECT  40.919 91.404 40.955 91.962 ;
     RECT  40.523 93.06 40.955 93.078 ;
     RECT  40.847 93.87 40.955 93.888 ;
     RECT  40.783 96.336 40.955 96.354 ;
     RECT  40.559 97.686 40.955 98.784 ;
     RECT  40.559 100.008 40.955 100.026 ;
     RECT  40.559 100.926 40.955 101.574 ;
     RECT  40.559 102.546 40.955 103.842 ;
     RECT  40.883 106.794 40.955 106.812 ;
     RECT  40.919 109.422 40.955 109.44 ;
     RECT  40.919 7.281 40.991 7.299 ;
     RECT  40.955 21.24 40.991 21.258 ;
     RECT  40.955 26.451 40.991 26.469 ;
     RECT  40.487 29.34 40.991 29.358 ;
     RECT  40.883 47.466 40.991 47.484 ;
     RECT  40.919 83.646 40.991 83.664 ;
     RECT  40.891 86.706 40.991 86.724 ;
     RECT  40.955 102.546 40.991 102.564 ;
     RECT  40.811 5.814 41.027 5.832 ;
     RECT  40.955 23.364 41.027 23.382 ;
     RECT  39.047 32.076 41.027 32.094 ;
     RECT  40.955 41.796 41.027 41.814 ;
     RECT  40.955 42.732 41.027 42.75 ;
     RECT  40.955 44.001 41.027 44.019 ;
     RECT  40.955 44.928 41.027 44.946 ;
     RECT  40.955 61.281 41.027 61.299 ;
     RECT  40.955 68.616 41.027 68.634 ;
     RECT  40.955 76.626 41.027 76.644 ;
     RECT  38.88 80.406 41.027 80.424 ;
     RECT  40.955 89.712 41.027 89.73 ;
     RECT  40.955 91.944 41.027 91.962 ;
     RECT  40.955 100.926 41.027 100.944 ;
     RECT  40.919 104.598 41.027 104.616 ;
     RECT  40.919 108.18 41.027 108.198 ;
    LAYER M3 ;
     RECT  11.268 2.101 11.286 2.143 ;
     RECT  5.115 2.143 5.205 2.191 ;
     RECT  7.815 2.143 7.905 2.191 ;
     RECT  10.515 2.143 11.286 2.191 ;
     RECT  21.315 2.143 21.405 2.191 ;
     RECT  27.612 2.101 27.882 2.191 ;
     RECT  29.415 2.143 29.505 2.191 ;
     RECT  5.115 2.191 5.274 2.227 ;
     RECT  7.272 2.191 7.905 2.227 ;
     RECT  9.288 2.191 9.306 2.227 ;
     RECT  13.215 2.143 13.305 2.227 ;
     RECT  14.472 2.101 14.49 2.227 ;
     RECT  13.215 2.227 13.374 2.251 ;
     RECT  14.148 2.227 14.49 2.251 ;
     RECT  6.012 2.227 6.534 2.263 ;
     RECT  7.272 2.227 8.37 2.263 ;
     RECT  25.668 2.191 25.686 2.263 ;
     RECT  9.108 2.227 9.306 2.299 ;
     RECT  10.296 2.191 11.502 2.299 ;
     RECT  27.576 2.191 27.882 2.299 ;
     RECT  29.376 2.191 29.505 2.299 ;
     RECT  25.056 2.263 25.866 2.335 ;
     RECT  26.715 2.143 26.805 2.335 ;
     RECT  29.304 2.299 29.505 2.335 ;
     RECT  4.464 2.227 5.274 2.371 ;
     RECT  15.915 2.143 16.005 2.371 ;
     RECT  17.604 2.263 17.622 2.371 ;
     RECT  20.916 2.191 21.405 2.371 ;
     RECT  22.248 2.227 22.266 2.371 ;
     RECT  24.015 2.143 24.105 2.371 ;
     RECT  24.876 2.335 26.805 2.371 ;
     RECT  29.052 2.335 30.078 2.371 ;
     RECT  32.115 2.143 32.205 2.371 ;
     RECT  2.415 2.143 2.505 2.413 ;
     RECT  4.32 2.371 5.274 2.413 ;
     RECT  6.012 2.263 8.37 2.413 ;
     RECT  18.615 2.143 18.705 2.413 ;
     RECT  23.4 2.371 26.805 2.413 ;
     RECT  27.576 2.299 28.062 2.413 ;
     RECT  31.752 2.371 32.205 2.413 ;
     RECT  34.815 2.143 34.905 2.413 ;
     RECT  37.515 2.143 37.605 2.413 ;
     RECT  3.456 2.227 3.474 2.461 ;
     RECT  4.32 2.413 8.37 2.461 ;
     RECT  12.6 2.251 14.49 2.491 ;
     RECT  12.6 2.491 14.814 2.497 ;
     RECT  15.915 2.371 16.254 2.497 ;
     RECT  23.4 2.413 28.062 2.569 ;
     RECT  29.052 2.371 30.15 2.569 ;
     RECT  12.6 2.497 16.254 2.605 ;
     RECT  17.604 2.371 17.766 2.605 ;
     RECT  23.4 2.569 28.134 2.605 ;
     RECT  29.052 2.569 30.438 2.605 ;
     RECT  3.42 2.461 8.37 2.641 ;
     RECT  9.108 2.299 11.502 2.641 ;
     RECT  12.6 2.605 16.794 2.641 ;
     RECT  17.604 2.605 17.802 2.641 ;
     RECT  18.615 2.413 18.897 2.641 ;
     RECT  20.412 2.371 22.266 2.641 ;
     RECT  23.4 2.605 30.438 2.641 ;
     RECT  31.752 2.413 32.397 2.641 ;
     RECT  20.088 2.641 22.266 2.767 ;
     RECT  3.42 2.641 18.954 2.803 ;
     RECT  20.088 2.767 22.518 2.803 ;
     RECT  23.328 2.641 30.978 2.803 ;
     RECT  31.752 2.641 32.886 2.803 ;
     RECT  2.415 2.413 2.697 2.875 ;
     RECT  3.42 2.803 32.886 2.875 ;
     RECT  2.415 2.875 32.886 2.911 ;
     RECT  2.415 2.911 33.39 3.029 ;
     RECT  3.492 3.029 33.39 3.145 ;
     RECT  34.815 2.413 35.097 3.145 ;
     RECT  3.492 3.145 33.534 3.181 ;
     RECT  34.524 3.145 35.097 3.181 ;
     RECT  37.515 2.413 37.797 3.181 ;
     RECT  35.892 3.451 35.91 3.541 ;
     RECT  3.492 3.181 35.097 3.605 ;
     RECT  3.528 3.605 35.097 3.643 ;
     RECT  35.892 3.541 35.946 3.643 ;
     RECT  39.6 3.145 39.618 3.685 ;
     RECT  39.6 3.685 39.654 3.721 ;
     RECT  3.528 3.643 35.946 3.811 ;
     RECT  37.515 3.181 37.926 3.955 ;
     RECT  39.06 3.721 39.654 4.081 ;
     RECT  39.06 4.081 39.69 4.225 ;
     RECT  3.528 3.811 36.594 4.261 ;
     RECT  37.476 3.955 37.926 4.261 ;
     RECT  38.664 4.225 39.69 4.261 ;
     RECT  40.428 4.219 40.446 4.261 ;
     RECT  3.528 4.261 37.926 4.531 ;
     RECT  3.42 4.531 37.926 4.765 ;
     RECT  38.664 4.261 40.446 4.765 ;
     RECT  0.108 4.891 0.126 4.963 ;
     RECT  2.415 3.029 2.697 5.035 ;
     RECT  3.42 4.765 40.446 5.035 ;
     RECT  2.415 5.035 40.446 5.341 ;
     RECT  2.304 5.341 40.446 5.809 ;
     RECT  2.304 5.809 41.022 6.221 ;
     RECT  0.108 4.963 0.558 6.317 ;
     RECT  0.108 6.317 0.414 6.509 ;
     RECT  2.415 6.221 41.022 7.051 ;
     RECT  0.144 6.509 0.414 7.087 ;
     RECT  0.144 7.087 0.558 7.133 ;
     RECT  2.304 7.051 41.022 7.321 ;
     RECT  2.196 7.321 41.022 7.373 ;
     RECT  0.54 7.133 0.558 7.435 ;
     RECT  2.412 7.373 41.022 8.107 ;
     RECT  0.54 7.435 0.666 8.429 ;
     RECT  2.304 8.107 41.022 8.587 ;
     RECT  2.268 8.587 41.022 8.699 ;
     RECT  0.144 8.539 0.342 8.813 ;
     RECT  0.144 8.813 0.162 9.533 ;
     RECT  0.54 9.661 0.558 9.773 ;
     RECT  2.304 8.699 41.022 9.931 ;
     RECT  1.152 9.787 1.17 10.061 ;
     RECT  1.98 9.931 41.022 10.109 ;
     RECT  2.268 10.109 41.022 10.939 ;
     RECT  0.576 10.795 0.594 11.137 ;
     RECT  0.576 11.137 1.17 11.209 ;
     RECT  2.232 10.939 41.022 11.213 ;
     RECT  2.268 11.213 41.022 11.408 ;
     RECT  0.504 11.209 1.17 11.563 ;
     RECT  2.304 11.408 41.022 11.669 ;
     RECT  0.144 11.563 1.17 11.741 ;
     RECT  0.504 11.741 0.522 11.885 ;
     RECT  2.415 11.669 41.022 12.427 ;
     RECT  1.368 12.619 1.386 12.811 ;
     RECT  1.152 12.811 1.386 12.845 ;
     RECT  1.152 12.845 1.314 13.037 ;
     RECT  1.152 13.037 1.17 13.085 ;
     RECT  0.108 12.991 0.126 13.147 ;
     RECT  0.108 13.147 0.198 13.229 ;
     RECT  0.144 13.229 0.198 13.339 ;
     RECT  0.144 13.339 0.234 14.059 ;
     RECT  1.476 14.347 1.494 14.525 ;
     RECT  0.144 14.059 0.342 14.635 ;
     RECT  0.108 14.635 0.342 14.669 ;
     RECT  2.304 12.427 41.022 14.711 ;
     RECT  0.108 14.669 0.126 14.765 ;
     RECT  2.34 14.711 41.022 14.909 ;
     RECT  2.415 14.909 41.022 15.979 ;
     RECT  2.376 15.979 41.022 16.529 ;
     RECT  2.415 16.529 41.022 17.455 ;
     RECT  2.376 17.455 41.022 17.879 ;
     RECT  2.415 17.879 41.022 18.661 ;
     RECT  0.144 18.121 0.162 18.733 ;
     RECT  0.108 18.733 0.162 18.893 ;
     RECT  2.412 18.661 41.022 19.051 ;
     RECT  0.144 18.893 0.162 19.085 ;
     RECT  2.304 19.051 41.022 19.813 ;
     RECT  2.268 19.813 41.022 19.849 ;
     RECT  2.196 19.849 41.022 19.901 ;
     RECT  2.268 19.901 41.022 20.048 ;
     RECT  0.216 19.849 0.234 20.203 ;
     RECT  0.216 20.203 0.342 20.299 ;
     RECT  0.144 20.299 0.342 20.683 ;
     RECT  0.108 20.683 0.342 20.779 ;
     RECT  0.108 20.779 0.414 20.804 ;
     RECT  0.144 20.804 0.414 20.821 ;
     RECT  0.144 20.821 0.558 21.547 ;
     RECT  0.108 21.547 0.558 21.677 ;
     RECT  0.108 21.677 0.198 21.839 ;
     RECT  0.144 21.839 0.162 22.013 ;
     RECT  1.152 21.787 1.17 22.219 ;
     RECT  1.152 22.219 1.278 22.699 ;
     RECT  0.54 22.699 1.278 22.891 ;
     RECT  0.144 22.891 1.278 23.069 ;
     RECT  2.304 20.048 41.022 23.387 ;
     RECT  2.304 23.387 40.95 23.405 ;
     RECT  0.54 23.069 1.278 23.693 ;
     RECT  2.304 23.405 40.914 23.851 ;
     RECT  2.232 23.851 40.914 23.891 ;
     RECT  0.54 23.693 1.17 24.091 ;
     RECT  0.144 24.091 1.17 24.221 ;
     RECT  2.268 23.891 40.914 24.331 ;
     RECT  2.268 24.331 40.95 24.368 ;
     RECT  2.304 24.368 40.95 24.503 ;
     RECT  2.304 24.503 40.914 24.557 ;
     RECT  0.144 24.221 0.558 24.619 ;
     RECT  0.108 24.619 0.558 24.665 ;
     RECT  0.216 24.665 0.558 24.701 ;
     RECT  2.304 24.557 40.878 25.387 ;
     RECT  1.98 25.387 40.878 25.483 ;
     RECT  1.98 25.483 40.95 25.565 ;
     RECT  0.504 24.701 0.558 25.819 ;
     RECT  2.304 25.565 40.95 26.446 ;
     RECT  0.144 25.819 0.558 26.765 ;
     RECT  0.54 26.765 0.558 26.827 ;
     RECT  0.54 26.827 1.17 26.861 ;
     RECT  1.152 26.861 1.17 26.957 ;
     RECT  0.324 27.499 0.342 27.595 ;
     RECT  0.108 27.595 0.342 27.607 ;
     RECT  0.108 27.607 0.378 27.635 ;
     RECT  0.144 27.635 0.378 27.725 ;
     RECT  2.304 26.446 40.986 27.883 ;
     RECT  0.144 27.725 0.162 27.917 ;
     RECT  2.268 27.883 40.986 28.319 ;
     RECT  2.304 28.319 40.986 28.445 ;
     RECT  2.415 28.445 40.986 28.973 ;
     RECT  2.415 28.973 40.194 29.021 ;
     RECT  40.932 28.973 40.986 29.357 ;
     RECT  40.968 29.357 40.986 29.363 ;
     RECT  29.16 29.021 40.194 29.755 ;
     RECT  2.415 29.021 28.35 29.767 ;
     RECT  29.088 29.755 40.194 29.767 ;
     RECT  2.415 29.767 40.194 29.903 ;
     RECT  2.415 29.903 38.61 29.939 ;
     RECT  2.415 29.939 38.394 30.043 ;
     RECT  39.6 29.903 40.194 30.713 ;
     RECT  39.636 30.713 40.194 30.911 ;
     RECT  39.708 30.911 40.194 30.983 ;
     RECT  39.708 30.983 39.726 31.181 ;
     RECT  2.376 30.043 38.394 32.035 ;
     RECT  2.376 32.035 39.042 32.369 ;
     RECT  2.376 32.369 37.797 33.035 ;
     RECT  38.628 32.369 39.042 33.151 ;
     RECT  2.415 33.035 37.797 33.349 ;
     RECT  38.628 33.151 39.618 33.349 ;
     RECT  2.415 33.349 39.618 33.547 ;
     RECT  41.004 32.071 41.022 34.051 ;
     RECT  2.415 33.547 40.194 34.663 ;
     RECT  40.932 34.051 41.022 34.663 ;
     RECT  2.415 34.663 41.022 37.291 ;
     RECT  0.504 37.021 0.522 37.471 ;
     RECT  0.504 37.471 0.558 37.561 ;
     RECT  2.304 37.291 41.022 37.625 ;
     RECT  2.415 37.625 41.022 38.539 ;
     RECT  0.108 37.561 0.558 38.957 ;
     RECT  0.468 38.957 0.558 39.883 ;
     RECT  2.304 38.539 41.022 39.917 ;
     RECT  0.144 39.883 0.558 40.061 ;
     RECT  0.54 40.061 0.558 40.109 ;
     RECT  2.304 39.917 39.078 40.559 ;
     RECT  40.176 39.917 41.022 40.675 ;
     RECT  2.415 40.559 39.078 40.685 ;
     RECT  39.924 40.675 41.022 40.936 ;
     RECT  39.888 40.936 41.022 40.973 ;
     RECT  2.415 40.685 38.79 41.341 ;
     RECT  1.152 41.035 1.17 41.405 ;
     RECT  39.924 40.973 41.022 41.707 ;
     RECT  39.888 41.707 41.022 41.819 ;
     RECT  2.268 41.341 38.79 42.061 ;
     RECT  2.232 42.061 38.79 42.125 ;
     RECT  39.888 41.819 40.986 42.323 ;
     RECT  0.468 41.989 0.558 42.605 ;
     RECT  2.268 42.125 38.79 42.701 ;
     RECT  39.924 42.323 40.986 42.727 ;
     RECT  1.152 42.907 1.17 42.955 ;
     RECT  1.152 42.955 1.386 43.085 ;
     RECT  1.296 43.085 1.314 43.277 ;
     RECT  2.304 42.701 38.79 43.303 ;
     RECT  39.924 42.727 41.022 43.303 ;
     RECT  2.304 43.303 41.022 43.469 ;
     RECT  2.304 43.469 38.682 43.771 ;
     RECT  2.196 43.771 38.682 43.799 ;
     RECT  2.196 43.799 38.466 43.853 ;
     RECT  2.415 43.853 38.466 43.871 ;
     RECT  39.6 43.469 41.022 44.024 ;
     RECT  2.415 43.871 38.358 44.609 ;
     RECT  39.6 44.024 40.986 44.653 ;
     RECT  4.068 44.609 38.286 44.717 ;
     RECT  39.384 44.653 40.986 44.725 ;
     RECT  39.348 44.725 40.986 44.813 ;
     RECT  4.068 44.717 38.214 44.879 ;
     RECT  39.384 44.813 40.986 44.909 ;
     RECT  39.6 44.909 40.986 44.923 ;
     RECT  2.415 44.609 3.294 45.463 ;
     RECT  4.068 44.879 38.07 45.463 ;
     RECT  0.54 45.571 0.558 45.661 ;
     RECT  2.415 45.463 38.07 45.832 ;
     RECT  0.108 45.661 0.558 45.965 ;
     RECT  2.304 45.832 38.07 46.111 ;
     RECT  0.108 45.965 0.522 46.253 ;
     RECT  2.304 46.111 38.214 46.265 ;
     RECT  3.96 46.265 38.214 46.373 ;
     RECT  0.108 46.253 0.126 46.445 ;
     RECT  4.032 46.373 38.214 46.471 ;
     RECT  2.304 46.265 3.078 46.841 ;
     RECT  2.415 46.841 3.078 47.219 ;
     RECT  4.032 46.471 38.718 47.272 ;
     RECT  3.492 47.272 38.718 47.309 ;
     RECT  3.708 47.309 38.718 47.389 ;
     RECT  39.6 44.923 41.022 47.389 ;
     RECT  3.708 47.389 41.022 48.155 ;
     RECT  3.924 48.155 41.022 48.227 ;
     RECT  3.924 48.227 14.058 48.509 ;
     RECT  3.996 48.509 14.058 48.955 ;
     RECT  14.796 48.227 41.022 48.955 ;
     RECT  2.415 47.219 2.697 49.351 ;
     RECT  3.996 48.955 41.022 49.351 ;
     RECT  0.504 49.441 0.522 49.711 ;
     RECT  0.468 49.711 0.522 49.981 ;
     RECT  0.432 49.981 0.522 50.053 ;
     RECT  0.432 50.053 0.558 50.189 ;
     RECT  0.432 50.189 0.522 50.285 ;
     RECT  0.432 50.285 0.486 50.573 ;
     RECT  0.432 50.573 0.45 50.765 ;
     RECT  2.415 49.351 41.022 51.019 ;
     RECT  0.216 51.403 0.306 51.595 ;
     RECT  0.216 51.595 0.342 51.601 ;
     RECT  0.216 51.601 0.558 51.781 ;
     RECT  0.144 51.781 0.558 51.821 ;
     RECT  0.54 51.821 0.558 51.917 ;
     RECT  2.304 51.019 41.022 52.321 ;
     RECT  2.268 52.321 41.022 52.795 ;
     RECT  1.98 52.795 41.022 52.973 ;
     RECT  0.54 52.987 0.558 53.323 ;
     RECT  0.54 53.323 1.17 53.549 ;
     RECT  1.152 53.549 1.17 53.563 ;
     RECT  1.152 53.563 1.278 53.803 ;
     RECT  0.324 53.707 0.342 53.837 ;
     RECT  2.304 52.973 41.022 53.851 ;
     RECT  1.152 53.803 1.314 53.933 ;
     RECT  2.268 53.851 41.022 54.029 ;
     RECT  1.152 53.933 1.278 54.701 ;
     RECT  2.304 54.029 41.022 54.797 ;
     RECT  0.324 54.859 0.342 55.147 ;
     RECT  0.108 55.147 0.342 55.181 ;
     RECT  0.108 55.181 0.234 55.229 ;
     RECT  2.304 54.797 39.042 55.373 ;
     RECT  2.304 55.373 38.214 55.445 ;
     RECT  2.304 55.445 38.106 55.751 ;
     RECT  0.108 55.229 0.198 55.916 ;
     RECT  0.144 55.916 0.198 56.093 ;
     RECT  2.304 55.751 37.926 56.219 ;
     RECT  39.888 54.797 41.022 56.332 ;
     RECT  2.415 56.219 37.926 56.641 ;
     RECT  39.024 55.373 39.042 56.641 ;
     RECT  39.852 56.332 41.022 56.831 ;
     RECT  2.415 56.641 39.042 56.875 ;
     RECT  2.415 56.875 39.33 56.912 ;
     RECT  2.415 56.912 39.042 57.067 ;
     RECT  2.304 57.067 39.042 57.101 ;
     RECT  0.54 56.461 0.558 57.451 ;
     RECT  0.504 57.451 0.558 57.677 ;
     RECT  40.176 56.831 41.022 57.685 ;
     RECT  0.504 57.677 0.522 57.773 ;
     RECT  2.304 57.101 38.574 58.225 ;
     RECT  2.304 58.225 38.754 58.379 ;
     RECT  39.924 57.685 41.022 58.693 ;
     RECT  0.108 57.811 0.162 58.733 ;
     RECT  2.304 58.379 38.682 58.891 ;
     RECT  2.268 58.891 38.682 59.161 ;
     RECT  39.888 58.693 41.022 59.179 ;
     RECT  2.16 59.161 38.682 59.213 ;
     RECT  39.852 59.179 41.022 59.261 ;
     RECT  0.324 59.233 0.558 59.467 ;
     RECT  2.304 59.213 38.682 59.563 ;
     RECT  0.144 59.467 0.558 59.656 ;
     RECT  40.464 59.261 41.022 60.043 ;
     RECT  40.356 60.043 41.022 60.079 ;
     RECT  39.888 60.079 41.022 60.269 ;
     RECT  0.108 59.656 0.558 60.557 ;
     RECT  40.284 60.269 41.022 60.557 ;
     RECT  2.304 59.563 39.078 60.619 ;
     RECT  2.304 60.619 39.366 61.037 ;
     RECT  40.428 60.557 41.022 61.304 ;
     RECT  2.304 61.037 39.078 61.387 ;
     RECT  40.428 61.304 40.95 61.465 ;
     RECT  2.268 61.387 39.078 61.493 ;
     RECT  0.288 60.557 0.558 61.723 ;
     RECT  0.288 61.723 0.63 61.799 ;
     RECT  0.288 61.799 0.558 61.808 ;
     RECT  39.924 61.465 40.95 61.901 ;
     RECT  2.304 61.493 39.078 62.251 ;
     RECT  0.288 61.808 0.306 62.491 ;
     RECT  0.144 62.491 0.306 62.668 ;
     RECT  2.304 62.251 39.33 62.731 ;
     RECT  0.108 62.668 0.306 62.765 ;
     RECT  40.464 61.901 40.95 62.969 ;
     RECT  2.304 62.731 39.69 63.112 ;
     RECT  40.716 62.969 40.95 63.113 ;
     RECT  2.304 63.112 39.906 63.149 ;
     RECT  2.304 63.149 39.69 63.509 ;
     RECT  2.304 63.509 2.697 63.545 ;
     RECT  0.288 62.765 0.306 63.617 ;
     RECT  3.564 63.509 39.69 63.851 ;
     RECT  40.716 63.113 40.878 63.895 ;
     RECT  39.852 63.883 39.87 63.931 ;
     RECT  40.716 63.895 40.95 63.931 ;
     RECT  39.852 63.931 40.95 64.205 ;
     RECT  39.852 64.205 40.734 64.301 ;
     RECT  2.415 63.545 2.697 64.315 ;
     RECT  3.564 63.851 39.078 64.315 ;
     RECT  2.415 64.315 39.078 64.355 ;
     RECT  3.564 64.355 39.078 64.499 ;
     RECT  39.852 64.301 39.87 64.661 ;
     RECT  39.024 64.499 39.078 64.733 ;
     RECT  3.564 64.499 38.178 64.859 ;
     RECT  3.564 64.859 16.254 64.931 ;
     RECT  40.716 64.301 40.734 64.931 ;
     RECT  3.564 64.931 16.197 65.083 ;
     RECT  2.415 64.355 2.697 65.551 ;
     RECT  3.456 65.083 16.197 65.551 ;
     RECT  2.415 65.551 16.197 65.659 ;
     RECT  17.1 64.859 38.178 65.659 ;
     RECT  2.415 65.659 38.178 65.713 ;
     RECT  39.024 64.733 39.042 65.713 ;
     RECT  40.464 66.091 40.482 67.135 ;
     RECT  40.464 67.135 40.842 67.369 ;
     RECT  2.415 65.713 39.042 67.559 ;
     RECT  40.464 67.369 40.878 67.639 ;
     RECT  40.392 67.639 40.878 67.757 ;
     RECT  40.428 67.757 40.878 68.107 ;
     RECT  40.428 68.107 40.95 68.333 ;
     RECT  40.464 68.333 40.95 68.611 ;
     RECT  2.415 67.559 38.034 68.683 ;
     RECT  39.024 67.559 39.042 68.683 ;
     RECT  2.415 68.683 39.042 68.971 ;
     RECT  0.108 68.791 0.126 69.061 ;
     RECT  0.108 69.061 0.486 69.151 ;
     RECT  2.415 68.971 39.33 69.355 ;
     RECT  40.464 68.611 41.022 69.355 ;
     RECT  2.415 69.355 41.022 69.493 ;
     RECT  2.412 69.493 41.022 69.533 ;
     RECT  2.415 69.533 41.022 69.869 ;
     RECT  0.108 69.151 0.558 70.141 ;
     RECT  0.108 70.141 1.17 70.253 ;
     RECT  2.415 69.869 38.178 70.609 ;
     RECT  39.024 69.869 41.022 70.609 ;
     RECT  0.108 70.253 0.342 70.645 ;
     RECT  2.415 70.609 41.022 70.699 ;
     RECT  0.036 70.645 0.342 71.041 ;
     RECT  1.152 70.253 1.17 71.041 ;
     RECT  0.036 71.041 1.17 71.177 ;
     RECT  0.108 71.177 1.17 71.309 ;
     RECT  1.152 71.309 1.17 71.371 ;
     RECT  1.152 71.371 1.386 71.693 ;
     RECT  1.296 71.693 1.314 71.789 ;
     RECT  2.304 70.699 41.022 72.221 ;
     RECT  0.108 71.309 0.234 72.229 ;
     RECT  40.392 72.221 41.022 72.461 ;
     RECT  0.108 72.229 0.558 72.571 ;
     RECT  0.108 72.571 1.17 72.653 ;
     RECT  2.304 72.221 39.654 72.749 ;
     RECT  2.34 72.749 39.654 72.845 ;
     RECT  1.152 72.653 1.17 72.869 ;
     RECT  39.852 73.099 39.87 73.195 ;
     RECT  40.86 72.461 41.022 73.195 ;
     RECT  2.34 72.845 39.042 73.471 ;
     RECT  2.304 73.471 39.042 73.517 ;
     RECT  2.376 73.517 39.042 73.579 ;
     RECT  39.852 73.195 41.022 73.579 ;
     RECT  0.108 72.653 0.198 73.651 ;
     RECT  1.152 73.627 1.17 73.651 ;
     RECT  0.108 73.651 1.17 73.805 ;
     RECT  0.108 73.805 0.558 74.189 ;
     RECT  0.108 74.189 0.378 74.381 ;
     RECT  0.144 74.381 0.378 74.669 ;
     RECT  2.376 73.579 41.022 74.731 ;
     RECT  1.152 74.923 1.17 75.197 ;
     RECT  0.144 74.669 0.162 75.307 ;
     RECT  0.108 75.307 0.162 75.437 ;
     RECT  0.144 75.437 0.162 75.659 ;
     RECT  2.304 74.731 41.022 76.073 ;
     RECT  0.18 75.703 0.27 76.363 ;
     RECT  0.18 76.363 0.342 76.441 ;
     RECT  1.152 76.243 1.17 76.441 ;
     RECT  0.18 76.441 1.17 76.459 ;
     RECT  0.108 76.459 1.17 76.507 ;
     RECT  39.6 76.073 41.022 76.649 ;
     RECT  0.108 76.507 1.278 76.781 ;
     RECT  39.6 76.649 40.95 76.811 ;
     RECT  0.108 76.781 1.17 77.069 ;
     RECT  0.108 77.069 0.198 77.899 ;
     RECT  1.152 77.069 1.17 77.899 ;
     RECT  0.108 77.899 1.17 78.125 ;
     RECT  39.6 76.811 40.914 78.125 ;
     RECT  39.6 78.125 40.77 78.197 ;
     RECT  0.108 78.125 0.162 78.221 ;
     RECT  39.6 78.197 40.734 78.233 ;
     RECT  1.152 78.125 1.17 78.653 ;
     RECT  0.144 78.221 0.162 78.941 ;
     RECT  2.304 76.073 38.466 79.141 ;
     RECT  2.304 79.141 38.61 79.285 ;
     RECT  2.304 79.285 38.754 79.439 ;
     RECT  39.6 78.233 40.194 79.619 ;
     RECT  2.415 79.439 38.466 79.745 ;
     RECT  2.415 79.745 38.394 80.365 ;
     RECT  2.376 80.365 38.394 80.905 ;
     RECT  40.176 79.619 40.194 81.239 ;
     RECT  2.376 80.905 38.502 81.715 ;
     RECT  2.376 81.715 38.61 81.869 ;
     RECT  2.376 81.869 38.502 81.905 ;
     RECT  2.376 81.905 38.394 82.993 ;
     RECT  41.004 80.401 41.022 83.641 ;
     RECT  2.376 82.993 39.078 83.767 ;
     RECT  40.212 83.335 40.23 83.767 ;
     RECT  2.376 83.767 40.23 83.795 ;
     RECT  2.415 83.795 40.23 84.145 ;
     RECT  40.968 83.641 41.022 84.145 ;
     RECT  2.415 84.145 41.022 84.941 ;
     RECT  0.108 84.811 0.126 85.081 ;
     RECT  0.108 85.081 0.522 85.153 ;
     RECT  2.415 84.941 36.09 85.351 ;
     RECT  0.108 85.153 0.558 85.709 ;
     RECT  2.304 85.351 36.09 85.801 ;
     RECT  36.936 84.941 41.022 85.801 ;
     RECT  2.304 85.801 41.022 86.161 ;
     RECT  2.268 86.161 41.022 86.203 ;
     RECT  1.98 86.203 41.022 86.381 ;
     RECT  2.268 86.381 41.022 86.477 ;
     RECT  0.504 85.709 0.558 86.611 ;
     RECT  0.108 86.611 0.558 86.669 ;
     RECT  0.18 86.669 0.558 87.245 ;
     RECT  0.18 87.245 0.234 87.499 ;
     RECT  0.144 87.499 0.234 87.58 ;
     RECT  0.108 87.58 0.234 88.123 ;
     RECT  0.108 88.123 0.558 88.493 ;
     RECT  0.54 88.493 0.558 88.987 ;
     RECT  0.54 88.987 1.242 89.165 ;
     RECT  0.54 89.165 1.17 89.213 ;
     RECT  0.54 89.213 0.558 89.549 ;
     RECT  2.304 86.477 41.022 89.735 ;
     RECT  0.144 89.755 0.162 89.933 ;
     RECT  2.304 89.735 40.95 90.347 ;
     RECT  0.54 90.553 0.558 90.701 ;
     RECT  2.304 90.347 40.914 91.229 ;
     RECT  0.324 91.243 0.342 91.339 ;
     RECT  31.68 91.229 40.914 91.339 ;
     RECT  0.108 91.339 0.342 91.373 ;
     RECT  0.108 91.373 0.126 91.565 ;
     RECT  31.68 91.339 40.95 91.939 ;
     RECT  2.304 91.229 30.906 91.975 ;
     RECT  31.68 91.939 41.022 91.975 ;
     RECT  0.144 95.071 0.162 95.251 ;
     RECT  1.152 95.179 1.17 95.251 ;
     RECT  0.144 95.251 1.17 95.279 ;
     RECT  2.304 91.975 41.022 95.521 ;
     RECT  0.144 95.279 0.558 95.719 ;
     RECT  2.268 95.521 41.022 95.719 ;
     RECT  0.108 95.719 0.558 95.789 ;
     RECT  2.196 95.719 41.022 95.819 ;
     RECT  0.108 95.789 0.522 95.885 ;
     RECT  0.144 95.885 0.522 95.981 ;
     RECT  0.144 95.981 0.162 96.509 ;
     RECT  2.268 95.819 41.022 96.997 ;
     RECT  2.232 96.997 41.022 97.037 ;
     RECT  0.54 97.069 1.17 97.627 ;
     RECT  0.54 97.627 1.242 97.997 ;
     RECT  0.54 97.997 0.558 98.221 ;
     RECT  2.268 97.037 41.022 98.339 ;
     RECT  0.468 98.221 0.558 98.395 ;
     RECT  0.144 98.395 0.558 98.572 ;
     RECT  0.108 98.572 0.558 98.731 ;
     RECT  0.108 98.731 1.17 98.909 ;
     RECT  2.304 98.339 41.022 99.307 ;
     RECT  2.268 99.307 41.022 99.403 ;
     RECT  2.232 99.403 41.022 99.491 ;
     RECT  0.108 98.909 0.558 99.821 ;
     RECT  2.268 99.491 41.022 100.013 ;
     RECT  0.108 99.821 0.522 100.555 ;
     RECT  0.108 100.555 1.17 100.589 ;
     RECT  0.144 100.589 1.17 100.781 ;
     RECT  2.304 100.013 41.022 100.949 ;
     RECT  0.144 100.781 0.558 100.973 ;
     RECT  0.504 100.973 0.558 101.821 ;
     RECT  0.504 101.821 0.63 101.885 ;
     RECT  0.504 101.885 0.522 101.933 ;
     RECT  2.304 100.949 40.986 102.091 ;
     RECT  2.268 102.091 40.986 102.191 ;
     RECT  0.18 102.235 0.198 102.283 ;
     RECT  2.304 102.191 40.986 102.389 ;
     RECT  2.415 102.389 40.986 102.569 ;
     RECT  0.108 102.283 0.198 102.667 ;
     RECT  0.108 102.667 0.558 102.701 ;
     RECT  2.415 102.569 40.95 103.147 ;
     RECT  0.144 102.701 0.558 103.277 ;
     RECT  0.144 103.277 0.342 103.468 ;
     RECT  2.304 103.147 40.95 103.649 ;
     RECT  2.304 103.649 38.286 103.739 ;
     RECT  39.06 103.649 40.95 103.847 ;
     RECT  2.304 103.739 38.034 104.009 ;
     RECT  39.06 103.847 40.914 104.429 ;
     RECT  0.108 103.468 0.342 104.525 ;
     RECT  39.06 104.429 39.366 104.525 ;
     RECT  40.176 104.429 40.914 104.584 ;
     RECT  40.176 104.584 40.95 104.593 ;
     RECT  2.304 104.009 37.998 104.701 ;
     RECT  2.268 104.701 37.998 104.791 ;
     RECT  2.268 104.791 38.178 104.875 ;
     RECT  39.06 104.525 39.078 104.891 ;
     RECT  1.728 104.875 38.178 105.205 ;
     RECT  1.728 105.205 38.286 105.241 ;
     RECT  0.108 104.525 0.162 105.293 ;
     RECT  40.176 104.593 41.022 105.355 ;
     RECT  1.728 105.241 38.394 105.539 ;
     RECT  2.232 105.539 38.394 105.629 ;
     RECT  1.44 105.547 1.458 105.643 ;
     RECT  39.852 105.355 41.022 105.701 ;
     RECT  1.368 105.643 1.458 105.725 ;
     RECT  1.368 105.725 1.386 105.739 ;
     RECT  1.152 105.739 1.386 105.773 ;
     RECT  2.232 105.629 38.322 105.773 ;
     RECT  2.232 105.773 38.286 105.869 ;
     RECT  2.304 105.869 38.286 105.899 ;
     RECT  0.108 105.293 0.126 106.253 ;
     RECT  1.152 105.773 1.17 106.349 ;
     RECT  40.176 105.701 41.022 106.507 ;
     RECT  0.324 106.411 0.342 106.541 ;
     RECT  39.852 106.507 41.022 107.275 ;
     RECT  2.304 105.899 38.214 107.401 ;
     RECT  2.304 107.401 38.682 107.519 ;
     RECT  0.324 107.467 0.342 107.563 ;
     RECT  0.108 107.563 0.342 107.597 ;
     RECT  0.108 107.597 0.126 107.693 ;
     RECT  2.34 107.519 38.682 108.043 ;
     RECT  39.636 107.275 41.022 108.043 ;
     RECT  2.34 108.043 41.022 108.059 ;
     RECT  2.415 108.059 41.022 108.203 ;
     RECT  2.415 108.203 40.95 108.401 ;
     RECT  39.672 108.401 40.95 108.473 ;
     RECT  40.32 108.473 40.95 108.701 ;
     RECT  40.356 108.701 40.95 109.277 ;
     RECT  40.392 109.277 40.95 109.445 ;
     RECT  40.392 109.445 40.878 109.787 ;
     RECT  2.415 108.401 38.682 110.219 ;
     RECT  2.415 110.219 36.198 110.399 ;
     RECT  40.392 109.787 40.41 110.399 ;
     RECT  2.415 110.399 35.91 110.489 ;
     RECT  36.936 110.219 38.682 110.489 ;
     RECT  37.515 110.489 38.682 110.533 ;
     RECT  37.515 110.533 38.754 110.633 ;
     RECT  37.515 110.633 38.358 110.669 ;
     RECT  2.415 110.489 35.766 111.641 ;
     RECT  2.415 111.641 35.622 111.713 ;
     RECT  33.66 111.713 35.622 111.725 ;
     RECT  2.415 111.713 9.486 111.839 ;
     RECT  10.224 111.713 24.966 111.839 ;
     RECT  25.776 111.713 32.886 111.839 ;
     RECT  33.66 111.725 34.002 111.839 ;
     RECT  34.776 111.725 35.622 111.839 ;
     RECT  3.492 111.839 9.342 111.875 ;
     RECT  10.224 111.839 20.25 111.875 ;
     RECT  10.224 111.875 13.878 111.911 ;
     RECT  26.136 111.839 32.886 111.965 ;
     RECT  21.024 111.839 24.822 111.983 ;
     RECT  14.868 111.875 20.25 112.019 ;
     RECT  2.415 111.839 2.697 112.067 ;
     RECT  10.224 111.911 13.497 112.067 ;
     RECT  37.515 110.669 37.797 112.067 ;
     RECT  3.492 111.875 6.354 112.109 ;
     RECT  7.164 111.875 9.198 112.109 ;
     RECT  10.224 112.067 13.338 112.109 ;
     RECT  14.868 112.019 17.694 112.109 ;
     RECT  18.615 112.019 20.25 112.109 ;
     RECT  21.024 111.983 21.87 112.109 ;
     RECT  22.68 111.983 24.822 112.109 ;
     RECT  26.136 111.965 30.726 112.109 ;
     RECT  31.716 111.965 32.886 112.109 ;
     RECT  33.66 111.839 33.858 112.109 ;
     RECT  34.815 111.839 35.622 112.109 ;
     RECT  36.396 111.685 36.414 112.109 ;
     RECT  6.3 112.109 6.354 112.145 ;
     RECT  10.224 112.109 11.61 112.145 ;
     RECT  12.636 112.109 13.305 112.145 ;
     RECT  18.615 112.109 19.746 112.145 ;
     RECT  26.715 112.109 28.494 112.145 ;
     RECT  29.415 112.109 30.654 112.145 ;
     RECT  31.716 112.109 32.706 112.145 ;
     RECT  3.492 112.109 5.454 112.157 ;
     RECT  4.032 112.157 5.454 112.217 ;
     RECT  10.515 112.145 11.61 112.217 ;
     RECT  21.096 112.109 21.87 112.217 ;
     RECT  26.715 112.145 27.81 112.217 ;
     RECT  4.716 112.217 5.454 112.253 ;
     RECT  7.308 112.109 7.905 112.253 ;
     RECT  8.64 112.109 8.91 112.253 ;
     RECT  10.515 112.217 10.674 112.253 ;
     RECT  14.868 112.109 14.886 112.253 ;
     RECT  15.912 112.109 16.005 112.253 ;
     RECT  17.568 112.109 17.586 112.253 ;
     RECT  23.796 112.109 24.105 112.253 ;
     RECT  33.84 112.109 33.858 112.253 ;
     RECT  34.815 112.109 35.478 112.253 ;
     RECT  6.336 112.145 6.354 112.289 ;
     RECT  11.592 112.217 11.61 112.289 ;
     RECT  18.615 112.145 19.134 112.289 ;
     RECT  21.24 112.217 21.405 112.289 ;
     RECT  26.715 112.217 27.054 112.289 ;
     RECT  27.792 112.217 27.81 112.289 ;
     RECT  29.415 112.145 30.114 112.289 ;
     RECT  2.415 112.067 2.505 112.337 ;
     RECT  5.115 112.253 5.205 112.337 ;
     RECT  7.815 112.253 7.905 112.337 ;
     RECT  10.515 112.253 10.605 112.337 ;
     RECT  13.215 112.145 13.305 112.337 ;
     RECT  15.915 112.253 16.005 112.337 ;
     RECT  18.615 112.289 18.705 112.337 ;
     RECT  21.315 112.289 21.405 112.337 ;
     RECT  24.015 112.253 24.105 112.337 ;
     RECT  26.715 112.289 26.805 112.337 ;
     RECT  29.415 112.289 29.505 112.337 ;
     RECT  32.115 112.145 32.205 112.337 ;
     RECT  34.815 112.253 34.905 112.337 ;
     RECT  37.515 112.067 37.605 112.337 ;
     RECT  8.64 112.253 8.766 113.419 ;
     RECT  8.532 113.419 8.766 114.461 ;
    LAYER M4 ;
     RECT  0.06 5.52 0.097 14.664 ;
     RECT  0.06 85.392 0.097 91.464 ;
     RECT  0.06 95.376 0.097 107.592 ;
     RECT  0.06 18.576 0.133 27.72 ;
     RECT  0.06 37.776 0.137 43.848 ;
     RECT  0.097 5.52 2.408 14.76 ;
     RECT  2.365 15.984 2.408 16.008 ;
     RECT  2.401 17.472 2.408 17.496 ;
     RECT  0.133 18.576 2.408 27.912 ;
     RECT  2.365 30.048 2.408 30.072 ;
     RECT  2.365 32.304 2.408 32.328 ;
     RECT  0.137 37.872 2.408 43.848 ;
     RECT  0.06 45.84 2.408 46.92 ;
     RECT  0.06 50.064 2.408 63.048 ;
     RECT  0.06 69.264 2.408 79.176 ;
     RECT  0.097 85.392 2.408 91.56 ;
     RECT  0.097 95.376 2.408 107.688 ;
     RECT  2.408 2.148 2.512 112.332 ;
     RECT  2.512 2.418 2.704 112.152 ;
     RECT  2.704 4.512 2.819 4.536 ;
     RECT  2.704 5.616 2.981 43.848 ;
     RECT  2.704 48.48 3.443 63.24 ;
     RECT  2.981 5.616 3.485 43.8 ;
     RECT  3.485 5.616 3.557 16.008 ;
     RECT  3.443 50.016 3.697 63.24 ;
     RECT  2.704 64.32 3.697 66.504 ;
     RECT  2.704 85.968 3.733 91.368 ;
     RECT  2.704 92.352 3.733 108.792 ;
     RECT  2.704 84.144 3.769 84.168 ;
     RECT  2.704 112.128 3.805 112.152 ;
     RECT  2.704 110.352 3.877 110.376 ;
     RECT  3.443 48.48 3.925 48.984 ;
     RECT  3.769 4.608 3.949 4.632 ;
     RECT  2.704 45.936 3.949 47.304 ;
     RECT  3.769 84.144 3.949 84.696 ;
     RECT  3.733 85.968 3.949 108.84 ;
     RECT  3.697 50.016 4.021 66.504 ;
     RECT  2.704 68.88 4.057 82.776 ;
     RECT  3.949 84.048 4.057 108.84 ;
     RECT  2.704 2.88 4.076 3 ;
     RECT  3.949 4.128 4.076 4.632 ;
     RECT  4.076 2.88 4.117 4.632 ;
     RECT  4.057 68.88 4.124 108.84 ;
     RECT  4.124 68.208 4.129 108.84 ;
     RECT  3.877 110.352 4.129 110.52 ;
     RECT  4.021 50.016 4.165 67.032 ;
     RECT  4.129 68.208 4.165 110.52 ;
     RECT  4.165 50.016 4.357 110.52 ;
     RECT  3.805 111.6 4.357 112.152 ;
     RECT  3.949 45.792 4.453 47.304 ;
     RECT  3.485 17.376 4.489 43.8 ;
     RECT  4.453 45.312 4.489 47.304 ;
     RECT  4.489 17.376 4.525 47.304 ;
     RECT  3.925 48.336 4.604 48.984 ;
     RECT  4.357 50.016 4.604 112.152 ;
     RECT  3.557 5.712 4.693 16.008 ;
     RECT  4.525 17.04 4.693 47.304 ;
     RECT  4.117 2.832 4.777 4.632 ;
     RECT  4.693 5.712 4.777 47.304 ;
     RECT  4.777 2.832 5.108 47.304 ;
     RECT  4.604 48.336 5.108 112.152 ;
     RECT  5.108 2.148 5.212 112.332 ;
     RECT  5.212 2.418 5.404 112.062 ;
     RECT  5.404 2.832 5.753 111.768 ;
     RECT  5.753 3.888 6.113 111.768 ;
     RECT  6.113 3.888 6.221 83.064 ;
     RECT  5.753 2.832 6.397 2.856 ;
     RECT  6.221 3.888 6.401 65.4 ;
     RECT  6.113 84.432 6.545 111.768 ;
     RECT  6.221 66.576 7.081 83.064 ;
     RECT  6.545 84.432 7.081 111.096 ;
     RECT  7.081 66.576 7.369 111.096 ;
     RECT  6.397 2.592 7.729 2.856 ;
     RECT  6.401 3.888 7.729 65.16 ;
     RECT  7.369 66.336 7.729 111.096 ;
     RECT  7.729 2.256 7.808 2.856 ;
     RECT  7.729 3.888 7.808 111.096 ;
     RECT  7.808 2.148 7.912 112.332 ;
     RECT  7.912 2.256 8.104 112.062 ;
     RECT  8.104 2.256 8.301 110.568 ;
     RECT  8.301 2.256 8.381 110.52 ;
     RECT  8.381 2.832 8.387 110.52 ;
     RECT  8.387 2.832 8.417 110.424 ;
     RECT  8.437 113.424 8.561 113.448 ;
     RECT  8.417 2.832 8.705 33.96 ;
     RECT  8.417 35.232 8.741 110.424 ;
     RECT  8.741 35.232 8.777 81.144 ;
     RECT  8.593 114.384 8.915 114.408 ;
     RECT  8.777 35.232 9.065 35.256 ;
     RECT  8.777 36.576 9.251 81.144 ;
     RECT  8.705 2.832 9.565 2.856 ;
     RECT  8.705 4.176 9.565 33.96 ;
     RECT  9.565 2.784 9.745 2.856 ;
     RECT  9.565 4.176 9.745 34.68 ;
     RECT  9.745 2.304 9.961 2.856 ;
     RECT  9.745 3.936 9.961 34.68 ;
     RECT  8.741 82.416 9.997 110.424 ;
     RECT  9.313 111.744 9.997 111.768 ;
     RECT  9.997 82.416 10.285 111.768 ;
     RECT  10.285 82.272 10.429 111.768 ;
     RECT  9.961 2.304 10.508 34.68 ;
     RECT  9.251 36.576 10.508 80.904 ;
     RECT  10.429 82.224 10.508 111.768 ;
     RECT  10.508 2.148 10.612 112.332 ;
     RECT  10.612 2.304 10.757 112.062 ;
     RECT  10.757 2.418 10.804 112.062 ;
     RECT  10.804 2.784 10.865 110.328 ;
     RECT  10.804 111.36 10.937 111.768 ;
     RECT  10.865 68.688 11.197 110.328 ;
     RECT  10.865 2.784 11.267 67.08 ;
     RECT  11.197 81.456 11.693 110.328 ;
     RECT  11.267 32.352 11.905 67.08 ;
     RECT  11.197 68.688 11.905 80.472 ;
     RECT  11.267 2.784 12.017 31.224 ;
     RECT  12.017 3.36 12.035 31.224 ;
     RECT  11.905 32.352 12.053 80.472 ;
     RECT  12.035 3.408 12.265 31.224 ;
     RECT  12.053 32.352 12.265 80.424 ;
     RECT  11.693 110.256 12.764 110.328 ;
     RECT  12.764 110.256 12.805 110.568 ;
     RECT  10.937 111.6 12.805 111.768 ;
     RECT  11.693 81.456 12.985 109.272 ;
     RECT  12.805 110.256 12.985 111.768 ;
     RECT  12.265 3.408 13.093 80.424 ;
     RECT  12.985 81.456 13.093 111.768 ;
     RECT  12.589 2.256 13.208 2.376 ;
     RECT  13.093 3.408 13.208 111.768 ;
     RECT  13.208 2.148 13.312 112.332 ;
     RECT  13.312 2.256 13.504 112.062 ;
     RECT  13.504 34.656 13.619 111.864 ;
     RECT  13.504 2.256 13.709 33.384 ;
     RECT  13.619 34.656 13.745 111.768 ;
     RECT  13.745 80.832 13.781 111.768 ;
     RECT  13.709 2.496 13.961 33.384 ;
     RECT  13.781 80.832 14.243 81.624 ;
     RECT  13.781 82.656 14.291 111.768 ;
     RECT  14.291 82.656 14.393 109.944 ;
     RECT  13.961 2.496 14.501 29.544 ;
     RECT  14.243 80.832 14.537 81.48 ;
     RECT  14.537 80.832 14.581 81 ;
     RECT  14.501 4.128 14.645 29.544 ;
     RECT  13.745 34.656 14.717 79.8 ;
     RECT  14.717 34.656 14.821 79.752 ;
     RECT  14.501 2.496 14.825 3.144 ;
     RECT  14.645 4.128 14.897 4.248 ;
     RECT  14.581 80.832 14.897 80.904 ;
     RECT  14.645 5.28 14.929 29.544 ;
     RECT  13.961 30.576 14.929 33.384 ;
     RECT  14.393 82.656 15.061 109.8 ;
     RECT  15.061 82.608 15.205 109.8 ;
     RECT  15.205 82.416 15.505 109.8 ;
     RECT  14.929 5.28 15.781 33.384 ;
     RECT  14.291 111.312 15.793 111.768 ;
     RECT  14.897 80.832 15.865 80.856 ;
     RECT  15.865 80.832 15.901 80.904 ;
     RECT  15.685 3.312 15.908 3.336 ;
     RECT  15.781 4.944 15.908 33.384 ;
     RECT  14.821 34.464 15.908 79.752 ;
     RECT  15.901 80.784 15.908 80.904 ;
     RECT  15.505 81.936 15.908 109.8 ;
     RECT  15.793 111.312 15.908 111.96 ;
     RECT  15.908 2.148 16.012 112.332 ;
     RECT  16.012 2.418 16.204 112.062 ;
     RECT  16.204 111.936 16.337 111.96 ;
     RECT  16.204 65.664 16.739 110.52 ;
     RECT  16.739 66.24 16.913 110.52 ;
     RECT  16.204 2.832 17.123 64.68 ;
     RECT  17.123 2.832 17.129 32.808 ;
     RECT  17.123 33.792 17.365 64.68 ;
     RECT  17.365 33.792 17.461 64.968 ;
     RECT  17.129 4.128 18.169 32.808 ;
     RECT  17.461 33.792 18.169 64.152 ;
     RECT  17.129 2.832 18.205 2.856 ;
     RECT  18.205 2.832 18.608 3.096 ;
     RECT  18.169 4.128 18.608 64.152 ;
     RECT  17.953 65.136 18.608 65.16 ;
     RECT  16.913 66.24 18.608 110.088 ;
     RECT  18.097 111.168 18.608 111.192 ;
     RECT  18.608 2.148 18.712 112.332 ;
     RECT  18.712 2.418 18.904 112.062 ;
     RECT  18.904 2.832 19.324 46.104 ;
     RECT  18.904 47.616 19.325 65.016 ;
     RECT  18.904 81.888 19.379 111.864 ;
     RECT  19.324 2.832 19.427 33.672 ;
     RECT  19.324 34.752 19.613 46.104 ;
     RECT  19.379 81.888 19.613 109.8 ;
     RECT  19.427 2.832 19.649 3.096 ;
     RECT  19.613 98.4 19.649 109.8 ;
     RECT  19.649 3.024 19.793 3.096 ;
     RECT  19.379 111.696 19.865 111.768 ;
     RECT  19.325 47.616 19.897 63.816 ;
     RECT  18.904 66.48 19.909 80.712 ;
     RECT  19.613 81.888 19.909 97.368 ;
     RECT  19.793 3.024 20.045 3.048 ;
     RECT  19.325 64.944 20.185 65.016 ;
     RECT  19.909 66.48 20.185 97.368 ;
     RECT  19.613 35.04 20.257 46.104 ;
     RECT  20.185 64.944 20.581 97.368 ;
     RECT  19.649 98.4 20.581 109.416 ;
     RECT  20.581 64.944 20.725 109.416 ;
     RECT  20.257 35.04 20.732 46.344 ;
     RECT  20.732 34.752 20.869 46.344 ;
     RECT  19.897 47.472 20.869 63.816 ;
     RECT  20.869 34.752 20.941 63.816 ;
     RECT  20.725 64.944 21.049 110.28 ;
     RECT  21.013 3.12 21.085 3.144 ;
     RECT  19.427 4.128 21.085 33.672 ;
     RECT  20.941 34.752 21.121 63.864 ;
     RECT  21.121 34.704 21.157 63.864 ;
     RECT  21.049 64.944 21.157 110.52 ;
     RECT  21.157 34.704 21.193 110.568 ;
     RECT  19.865 111.696 21.193 111.72 ;
     RECT  21.085 3.12 21.308 33.672 ;
     RECT  21.193 34.704 21.308 111.72 ;
     RECT  21.308 2.148 21.412 112.332 ;
     RECT  21.412 2.418 21.604 112.062 ;
     RECT  21.604 66.048 21.701 111.144 ;
     RECT  21.701 66.288 21.923 110.616 ;
     RECT  21.604 4.128 22.205 63.864 ;
     RECT  21.923 66.288 22.307 80.472 ;
     RECT  22.205 4.128 22.313 63.816 ;
     RECT  22.313 4.224 22.745 63.816 ;
     RECT  21.604 64.848 22.849 64.872 ;
     RECT  21.923 81.456 22.921 110.616 ;
     RECT  22.921 81.456 22.961 111.48 ;
     RECT  22.849 64.848 23.065 65.016 ;
     RECT  22.307 80.304 23.065 80.472 ;
     RECT  22.961 81.456 23.065 81.672 ;
     RECT  22.961 82.656 23.137 111.48 ;
     RECT  22.745 34.896 23.209 63.816 ;
     RECT  23.065 64.848 23.209 65.16 ;
     RECT  22.307 66.288 23.281 79.32 ;
     RECT  21.604 2.784 23.317 3.144 ;
     RECT  22.745 4.224 23.317 33.672 ;
     RECT  23.281 66.24 23.353 79.32 ;
     RECT  23.209 34.896 23.425 65.16 ;
     RECT  23.353 66.144 23.425 79.32 ;
     RECT  23.317 2.784 24.008 33.672 ;
     RECT  23.425 34.896 24.008 79.32 ;
     RECT  23.065 80.304 24.008 81.672 ;
     RECT  23.137 82.656 24.008 111.864 ;
     RECT  24.008 2.148 24.112 112.332 ;
     RECT  24.112 2.418 24.304 112.062 ;
     RECT  24.304 81.984 24.401 110.904 ;
     RECT  24.304 66.24 24.515 81 ;
     RECT  24.304 2.736 24.833 33.384 ;
     RECT  24.833 2.784 25.369 33.384 ;
     RECT  24.304 34.368 25.369 34.92 ;
     RECT  24.401 81.984 25.405 110.856 ;
     RECT  24.515 66.24 25.477 80.904 ;
     RECT  25.405 81.984 25.477 110.904 ;
     RECT  25.369 2.784 25.513 34.92 ;
     RECT  24.304 35.904 25.513 64.392 ;
     RECT  25.477 66.24 25.513 110.904 ;
     RECT  25.513 2.784 25.667 64.392 ;
     RECT  25.513 66.24 26.101 111.336 ;
     RECT  25.667 2.784 26.161 47.16 ;
     RECT  26.101 66.24 26.665 111.816 ;
     RECT  26.161 2.736 26.708 47.16 ;
     RECT  25.667 48.24 26.708 64.392 ;
     RECT  26.665 65.472 26.708 111.816 ;
     RECT  26.708 2.148 26.812 112.332 ;
     RECT  26.812 2.418 27.004 112.062 ;
     RECT  27.004 46.8 27.101 81.432 ;
     RECT  27.004 2.64 27.173 45.72 ;
     RECT  27.101 46.8 27.173 79.512 ;
     RECT  27.173 2.64 27.325 18.84 ;
     RECT  27.004 96 27.389 111.336 ;
     RECT  27.173 19.824 27.497 45.72 ;
     RECT  27.173 47.136 27.821 79.512 ;
     RECT  27.325 3.696 27.827 18.84 ;
     RECT  27.497 19.824 27.929 45.432 ;
     RECT  27.101 80.832 28.105 81.432 ;
     RECT  27.004 82.416 28.105 94.968 ;
     RECT  28.105 80.832 28.141 94.968 ;
     RECT  27.827 3.888 28.321 18.84 ;
     RECT  27.929 19.824 28.321 32.328 ;
     RECT  27.821 47.136 28.397 79.32 ;
     RECT  28.141 80.352 28.537 94.968 ;
     RECT  27.389 96 28.537 111.192 ;
     RECT  28.537 80.352 28.825 111.192 ;
     RECT  28.321 3.888 28.981 32.328 ;
     RECT  27.929 33.36 28.981 45.432 ;
     RECT  28.397 66.816 29.041 79.32 ;
     RECT  28.825 80.352 29.041 111.912 ;
     RECT  28.981 3.888 29.185 45.432 ;
     RECT  28.397 47.136 29.257 65.784 ;
     RECT  27.325 2.64 29.329 2.664 ;
     RECT  29.329 2.64 29.365 2.856 ;
     RECT  29.185 3.888 29.365 45.528 ;
     RECT  29.365 2.64 29.408 45.528 ;
     RECT  29.257 46.848 29.408 65.784 ;
     RECT  29.041 66.816 29.408 111.912 ;
     RECT  29.408 2.148 29.512 112.332 ;
     RECT  29.512 2.418 29.704 112.062 ;
     RECT  29.704 2.832 29.765 31.128 ;
     RECT  29.704 32.304 30.017 111.912 ;
     RECT  30.017 32.304 30.227 111.72 ;
     RECT  30.227 32.304 30.349 79.8 ;
     RECT  30.349 46.368 30.413 79.8 ;
     RECT  30.227 80.88 30.521 111.72 ;
     RECT  30.521 82.56 30.652 111.72 ;
     RECT  29.765 2.832 30.841 5.304 ;
     RECT  29.765 6.288 30.841 31.128 ;
     RECT  30.841 2.832 30.989 31.128 ;
     RECT  30.989 13.872 31.097 31.128 ;
     RECT  30.652 82.656 31.129 111.72 ;
     RECT  30.349 32.304 31.381 45.288 ;
     RECT  30.413 46.368 31.381 79.32 ;
     RECT  31.097 17.904 31.813 31.128 ;
     RECT  31.381 32.304 31.813 79.32 ;
     RECT  30.521 80.88 31.957 81.48 ;
     RECT  31.129 82.656 31.957 111.96 ;
     RECT  31.813 17.904 32.065 79.32 ;
     RECT  31.957 80.88 32.065 111.96 ;
     RECT  30.989 2.832 32.108 12.888 ;
     RECT  31.097 13.872 32.108 16.92 ;
     RECT  32.065 17.904 32.108 111.96 ;
     RECT  32.108 2.148 32.212 112.332 ;
     RECT  32.212 2.418 32.404 112.062 ;
     RECT  32.404 97.536 32.717 111.96 ;
     RECT  32.404 3.36 33.059 96.552 ;
     RECT  33.059 3.36 33.077 79.368 ;
     RECT  33.077 3.36 33.329 79.32 ;
     RECT  32.717 97.536 33.329 111.048 ;
     RECT  33.059 80.496 33.397 96.552 ;
     RECT  33.329 97.536 33.397 110.52 ;
     RECT  33.329 3.36 33.437 4.248 ;
     RECT  33.397 80.496 33.689 110.52 ;
     RECT  33.329 5.28 34.045 79.32 ;
     RECT  33.689 80.496 34.045 81.384 ;
     RECT  33.829 112.224 34.405 112.248 ;
     RECT  33.689 82.944 34.453 110.52 ;
     RECT  34.405 111.696 34.453 112.248 ;
     RECT  33.437 3.408 34.808 4.248 ;
     RECT  34.045 5.28 34.808 81.384 ;
     RECT  34.453 82.944 34.808 112.248 ;
     RECT  34.808 2.148 34.912 112.332 ;
     RECT  34.912 2.418 35.104 112.248 ;
     RECT  35.104 82.656 35.165 112.248 ;
     RECT  35.165 82.656 35.273 110.904 ;
     RECT  35.104 35.712 35.309 81.576 ;
     RECT  35.273 82.656 35.345 110.616 ;
     RECT  35.104 3.648 35.489 34.68 ;
     RECT  35.165 112.224 35.489 112.248 ;
     RECT  35.309 35.808 35.597 81.576 ;
     RECT  35.489 3.936 35.705 34.68 ;
     RECT  35.345 82.656 35.705 110.568 ;
     RECT  35.705 82.656 35.893 109.8 ;
     RECT  35.597 79.008 36.325 81.576 ;
     RECT  36.325 79.008 36.529 81.624 ;
     RECT  35.597 35.808 36.533 77.976 ;
     RECT  36.529 79.008 36.997 82.44 ;
     RECT  35.893 83.568 36.997 109.8 ;
     RECT  35.705 4.224 37.033 34.68 ;
     RECT  36.533 35.808 37.033 64.92 ;
     RECT  37.033 4.224 37.508 64.92 ;
     RECT  36.533 65.904 37.508 77.976 ;
     RECT  36.997 79.008 37.508 109.8 ;
     RECT  37.508 2.148 37.612 112.332 ;
     RECT  37.612 2.418 37.804 112.062 ;
     RECT  37.804 36.816 37.829 44.904 ;
     RECT  37.804 81.6 37.829 81.624 ;
     RECT  37.804 47.04 37.865 47.976 ;
     RECT  37.804 85.728 37.901 87.624 ;
     RECT  37.804 89.184 37.901 96.84 ;
     RECT  37.804 32.304 37.937 32.328 ;
     RECT  37.804 67.632 37.937 68.76 ;
     RECT  37.804 84.096 37.937 84.12 ;
     RECT  37.901 96.048 37.937 96.84 ;
     RECT  37.804 35.28 37.955 35.304 ;
     RECT  37.829 36.816 37.955 43.944 ;
     RECT  37.804 6.816 37.973 29.88 ;
     RECT  37.804 77.904 37.973 77.928 ;
     RECT  37.901 89.184 37.973 94.68 ;
     RECT  37.955 36.816 38.045 36.936 ;
     RECT  37.804 80.016 38.045 80.568 ;
     RECT  37.804 64.896 38.081 64.92 ;
     RECT  37.973 17.808 38.189 29.88 ;
     RECT  37.973 6.912 38.225 16.296 ;
     RECT  37.804 34.128 38.225 34.152 ;
     RECT  37.865 47.136 38.225 47.976 ;
     RECT  38.045 80.544 38.225 80.568 ;
     RECT  37.901 86.592 38.225 87.624 ;
     RECT  37.973 89.328 38.225 94.68 ;
     RECT  38.189 18.144 38.369 29.88 ;
     RECT  37.804 31.104 38.369 31.128 ;
     RECT  37.955 38.496 38.405 43.944 ;
     RECT  38.369 18.144 38.513 18.168 ;
     RECT  38.045 36.912 38.513 36.936 ;
     RECT  38.225 47.136 38.585 47.16 ;
     RECT  38.369 19.824 38.621 29.88 ;
     RECT  38.225 94.08 38.621 94.68 ;
     RECT  38.225 86.784 38.693 87.624 ;
     RECT  37.804 50.352 38.801 50.376 ;
     RECT  37.804 51.36 39.013 63.816 ;
     RECT  38.693 87.12 39.049 87.624 ;
     RECT  37.804 5.28 39.197 5.304 ;
     RECT  37.937 68.736 39.265 68.76 ;
     RECT  37.804 69.84 39.265 76.872 ;
     RECT  38.621 94.416 39.269 94.68 ;
     RECT  39.049 87.12 39.301 88.296 ;
     RECT  38.225 89.328 39.301 92.808 ;
     RECT  37.804 97.872 39.301 109.272 ;
     RECT  38.405 38.736 39.337 43.944 ;
     RECT  39.337 38.736 39.373 44.808 ;
     RECT  37.937 96.048 39.733 96.456 ;
     RECT  39.301 97.776 39.733 109.272 ;
     RECT  39.301 87.12 39.877 92.808 ;
     RECT  39.877 86.832 39.913 92.808 ;
     RECT  39.373 38.736 40.201 44.904 ;
     RECT  38.225 6.912 40.309 15.912 ;
     RECT  37.937 67.632 40.381 67.656 ;
     RECT  39.733 96.048 40.385 109.272 ;
     RECT  40.381 67.632 40.417 67.752 ;
     RECT  39.265 68.736 40.417 76.872 ;
     RECT  39.301 35.664 40.453 35.976 ;
     RECT  37.804 4.224 40.457 4.248 ;
     RECT  40.385 96.048 40.457 109.032 ;
     RECT  40.453 35.28 40.489 35.976 ;
     RECT  40.309 6.912 40.741 16.008 ;
     RECT  40.417 67.632 40.741 76.872 ;
     RECT  40.489 35.28 40.777 36.072 ;
     RECT  39.913 86.736 40.813 92.808 ;
     RECT  39.013 51.36 40.853 64.392 ;
     RECT  40.741 67.536 40.853 76.872 ;
     RECT  40.777 35.28 40.885 36.168 ;
     RECT  40.201 38.736 40.925 45.192 ;
     RECT  40.853 67.536 40.925 76.776 ;
     RECT  40.813 86.64 40.925 92.808 ;
     RECT  40.457 96.432 40.931 109.032 ;
     RECT  38.621 19.824 40.961 29.352 ;
     RECT  40.931 96.432 40.961 108.936 ;
     RECT  40.885 35.28 40.997 36.456 ;
     RECT  39.269 94.416 40.997 94.44 ;
     RECT  40.741 6.864 41.004 16.008 ;
     RECT  40.961 19.92 41.004 29.064 ;
     RECT  40.997 35.28 41.004 36.264 ;
     RECT  40.925 39.12 41.004 45.192 ;
     RECT  40.853 51.408 41.004 64.392 ;
     RECT  40.925 67.536 41.004 76.68 ;
     RECT  40.925 86.736 41.004 92.808 ;
     RECT  40.961 96.72 41.004 108.936 ;
    LAYER M5 ;
     RECT  2.4 2.137 2.52 2.151 ;
     RECT  5.1 2.137 5.22 2.151 ;
     RECT  7.8 2.137 7.92 2.151 ;
     RECT  10.5 2.137 10.62 2.151 ;
     RECT  13.2 2.137 13.32 2.151 ;
     RECT  15.9 2.137 16.02 2.151 ;
     RECT  18.6 2.137 18.72 2.151 ;
     RECT  21.3 2.137 21.42 2.151 ;
     RECT  24 2.137 24.12 2.151 ;
     RECT  26.7 2.137 26.82 2.151 ;
     RECT  29.4 2.137 29.52 2.151 ;
     RECT  32.1 2.137 32.22 2.151 ;
     RECT  34.8 2.137 34.92 2.151 ;
     RECT  37.5 2.137 37.62 2.151 ;
     RECT  24 2.151 24.312 2.773 ;
     RECT  5.1 2.151 5.412 2.821 ;
     RECT  18.6 2.151 18.912 2.821 ;
     RECT  26.7 2.151 27.012 3.397 ;
     RECT  26.7 3.397 27.288 3.685 ;
     RECT  7.8 2.151 8.112 3.877 ;
     RECT  4.128 2.821 5.412 3.925 ;
     RECT  6.912 3.877 8.112 3.925 ;
     RECT  10.5 2.151 10.812 3.925 ;
     RECT  21.3 2.151 21.612 3.925 ;
     RECT  25.488 3.925 25.512 4.405 ;
     RECT  10.368 3.925 10.812 4.453 ;
     RECT  12 3.349 12.024 4.453 ;
     RECT  2.4 2.151 2.712 4.501 ;
     RECT  23.328 2.773 24.312 4.501 ;
     RECT  22.8 4.501 24.312 4.547 ;
     RECT  10.368 4.453 12.024 4.597 ;
     RECT  4.128 3.925 8.112 4.643 ;
     RECT  25.488 4.405 25.56 4.691 ;
     RECT  15.9 2.151 16.212 4.933 ;
     RECT  21.168 3.925 21.612 4.933 ;
     RECT  22.8 4.547 22.824 4.933 ;
     RECT  18.6 2.821 19.416 4.981 ;
     RECT  5.1 4.643 8.112 5.029 ;
     RECT  15.792 4.933 16.212 5.029 ;
     RECT  18.6 4.981 19.464 5.029 ;
     RECT  29.4 2.151 29.712 5.029 ;
     RECT  21.072 4.933 22.824 5.075 ;
     RECT  23.904 4.547 24.312 5.075 ;
     RECT  10.32 4.597 12.024 5.171 ;
     RECT  15.792 5.029 17.112 5.171 ;
     RECT  26.7 3.685 27.816 5.171 ;
     RECT  29.4 5.029 30.024 5.171 ;
     RECT  13.2 2.151 13.512 5.269 ;
     RECT  5.1 5.029 8.52 5.315 ;
     RECT  7.8 5.315 8.52 5.461 ;
     RECT  13.104 5.269 13.512 5.507 ;
     RECT  2.4 4.501 2.808 5.605 ;
     RECT  7.8 5.461 8.568 5.747 ;
     RECT  15.792 5.171 16.212 5.747 ;
     RECT  25.536 4.691 25.56 5.749 ;
     RECT  25.44 5.749 25.56 6.085 ;
     RECT  5.1 5.315 6.36 6.229 ;
     RECT  10.368 5.171 12.024 6.277 ;
     RECT  2.4 5.605 3.288 6.323 ;
     RECT  9.792 6.277 12.024 6.323 ;
     RECT  21.168 5.075 22.392 6.371 ;
     RECT  25.44 6.085 25.656 6.755 ;
     RECT  24 5.075 24.312 6.805 ;
     RECT  13.2 5.507 13.512 6.853 ;
     RECT  9.792 6.323 11.64 6.899 ;
     RECT  4.992 6.229 6.36 6.947 ;
     RECT  32.1 2.151 32.412 7.093 ;
     RECT  13.104 6.853 13.512 7.189 ;
     RECT  40.848 7.093 40.872 7.379 ;
     RECT  13.104 7.189 13.656 7.381 ;
     RECT  18.6 5.029 19.656 7.381 ;
     RECT  33.696 5.557 33.72 7.381 ;
     RECT  25.488 6.755 25.656 7.573 ;
     RECT  26.7 5.171 27.288 7.573 ;
     RECT  29.4 5.171 29.712 7.573 ;
     RECT  9.792 6.899 11.448 7.669 ;
     RECT  29.28 7.573 29.712 7.669 ;
     RECT  18.144 7.381 19.656 7.765 ;
     RECT  29.088 7.669 29.712 7.861 ;
     RECT  25.488 7.573 27.288 7.909 ;
     RECT  7.8 5.747 8.52 7.957 ;
     RECT  17.568 7.765 19.656 7.957 ;
     RECT  29.088 7.861 30.6 7.957 ;
     RECT  23.376 6.805 24.312 8.147 ;
     RECT  34.8 2.151 35.112 8.149 ;
     RECT  36.096 7.381 36.12 8.149 ;
     RECT  37.5 2.151 37.812 8.149 ;
     RECT  21.168 6.371 21.612 8.195 ;
     RECT  33.648 7.381 33.72 8.197 ;
     RECT  34.8 8.149 37.812 8.197 ;
     RECT  33.648 8.197 37.812 8.243 ;
     RECT  17.568 7.957 19.896 8.725 ;
     RECT  25.488 7.909 27.336 8.867 ;
     RECT  9.6 7.669 11.448 8.869 ;
     RECT  12.48 7.381 13.656 8.869 ;
     RECT  25.632 8.867 27.336 9.011 ;
     RECT  28.464 7.957 30.6 9.011 ;
     RECT  15.9 5.747 16.212 9.013 ;
     RECT  9.6 8.869 13.656 9.059 ;
     RECT  12.48 9.059 13.656 9.107 ;
     RECT  26.208 9.011 27.336 9.155 ;
     RECT  7.68 7.957 8.52 9.157 ;
     RECT  9.6 9.059 11.448 9.157 ;
     RECT  17.568 8.725 19.992 9.157 ;
     RECT  21.3 8.195 21.612 9.157 ;
     RECT  17.568 9.157 21.612 9.299 ;
     RECT  40.8 9.109 40.824 9.299 ;
     RECT  12.48 9.107 13.608 9.395 ;
     RECT  17.568 9.299 19.992 9.395 ;
     RECT  4.992 6.947 6.216 9.589 ;
     RECT  12.48 9.395 13.512 9.683 ;
     RECT  7.68 9.157 11.448 9.731 ;
     RECT  31.92 7.093 32.412 9.733 ;
     RECT  33.696 8.243 37.812 9.733 ;
     RECT  31.92 9.733 37.812 9.875 ;
     RECT  4.8 9.589 6.216 9.877 ;
     RECT  33.888 9.875 37.812 9.923 ;
     RECT  7.8 9.731 11.448 10.019 ;
     RECT  15.9 9.013 16.536 10.069 ;
     RECT  26.7 9.155 27.336 10.069 ;
     RECT  3.936 9.877 6.216 10.115 ;
     RECT  2.4 6.323 2.808 10.213 ;
     RECT  15.9 10.069 17.16 10.259 ;
     RECT  4.8 10.115 6.216 10.261 ;
     RECT  22.8 9.589 22.824 10.309 ;
     RECT  22.8 10.309 22.92 10.355 ;
     RECT  29.184 9.011 30.264 10.355 ;
     RECT  18.144 9.395 19.992 10.501 ;
     RECT  14.832 6.805 14.856 10.549 ;
     RECT  15.9 10.259 16.212 10.549 ;
     RECT  14.832 10.549 16.212 10.595 ;
     RECT  33.888 9.923 35.256 10.835 ;
     RECT  12.816 9.683 13.512 10.933 ;
     RECT  2.4 10.213 3.576 10.979 ;
     RECT  7.8 10.019 8.232 10.981 ;
     RECT  7.392 10.981 8.232 11.029 ;
     RECT  29.184 10.355 29.712 11.171 ;
     RECT  17.616 10.501 19.992 11.173 ;
     RECT  15.792 10.595 16.212 11.221 ;
     RECT  17.616 11.173 20.328 11.221 ;
     RECT  9.696 10.019 11.448 11.269 ;
     RECT  12.528 10.933 13.512 11.269 ;
     RECT  7.392 11.029 8.328 11.365 ;
     RECT  9.696 11.269 13.512 11.365 ;
     RECT  26.7 10.069 27.816 11.365 ;
     RECT  15.792 11.221 20.328 11.459 ;
     RECT  7.392 11.365 13.512 11.507 ;
     RECT  7.8 11.507 13.512 11.509 ;
     RECT  4.8 10.261 6.264 11.701 ;
     RECT  15.9 11.459 20.328 11.749 ;
     RECT  21.3 9.299 21.612 11.749 ;
     RECT  4.464 11.701 6.264 11.891 ;
     RECT  29.4 11.171 29.712 11.941 ;
     RECT  33.888 10.835 35.112 11.941 ;
     RECT  25.92 11.365 27.816 12.035 ;
     RECT  26.592 12.035 27.816 12.229 ;
     RECT  15.9 11.749 21.612 12.275 ;
     RECT  7.8 11.509 14.232 12.323 ;
     RECT  7.8 12.323 11.448 12.371 ;
     RECT  15.9 12.275 18.912 12.517 ;
     RECT  29.4 11.941 30.072 12.517 ;
     RECT  33.84 11.941 35.112 12.563 ;
     RECT  7.8 12.371 10.968 12.755 ;
     RECT  4.8 11.891 6.264 12.805 ;
     RECT  15.408 12.517 18.912 12.947 ;
     RECT  26.592 12.229 27.912 12.997 ;
     RECT  29.28 12.517 30.072 12.997 ;
     RECT  9.744 12.755 10.968 13.091 ;
     RECT  29.28 12.997 30.264 13.139 ;
     RECT  24 8.147 24.312 13.285 ;
     RECT  12.816 12.323 14.232 13.477 ;
     RECT  11.952 13.477 14.232 13.523 ;
     RECT  10.032 13.091 10.968 13.525 ;
     RECT  11.952 13.523 13.944 13.525 ;
     RECT  29.28 13.139 29.712 13.525 ;
     RECT  4.8 12.805 6.6 13.573 ;
     RECT  4.704 13.573 6.6 13.621 ;
     RECT  7.8 12.755 8.28 13.621 ;
     RECT  24 13.285 24.936 13.621 ;
     RECT  26.448 12.997 27.912 13.669 ;
     RECT  33.888 12.563 35.112 14.101 ;
     RECT  36.288 9.923 37.812 14.101 ;
     RECT  33.888 14.101 37.812 14.147 ;
     RECT  33.888 14.147 35.352 14.149 ;
     RECT  10.032 13.525 13.944 14.195 ;
     RECT  15.408 12.947 17.064 14.291 ;
     RECT  4.704 13.621 8.28 14.435 ;
     RECT  24 13.621 25.08 14.437 ;
     RECT  26.208 13.669 27.912 14.437 ;
     RECT  22.896 10.355 22.92 14.533 ;
     RECT  24 14.437 27.912 14.533 ;
     RECT  10.224 14.195 13.944 14.629 ;
     RECT  4.704 14.435 6.36 14.675 ;
     RECT  33.552 14.149 35.352 14.819 ;
     RECT  7.68 14.435 8.28 14.821 ;
     RECT  4.704 14.675 6.264 14.867 ;
     RECT  22.896 14.533 27.912 14.867 ;
     RECT  4.704 14.867 6.168 14.869 ;
     RECT  22.896 14.867 24.936 14.915 ;
     RECT  18.144 12.947 18.912 14.965 ;
     RECT  20.448 12.275 21.612 14.965 ;
     RECT  15.9 14.291 17.064 15.011 ;
     RECT  10.224 14.629 14.376 15.155 ;
     RECT  15.9 15.011 16.872 15.155 ;
     RECT  40.848 15.013 40.872 15.299 ;
     RECT  2.4 10.979 3.48 15.301 ;
     RECT  4.512 14.869 6.168 15.301 ;
     RECT  26.016 14.867 27.912 15.349 ;
     RECT  22.896 14.915 24.744 15.443 ;
     RECT  33.888 14.819 35.352 15.493 ;
     RECT  36.576 14.147 37.812 15.493 ;
     RECT  18.144 14.965 21.612 15.589 ;
     RECT  2.4 15.301 6.168 15.683 ;
     RECT  10.224 15.155 11.88 15.683 ;
     RECT  7.68 14.821 8.328 15.829 ;
     RECT  10.224 15.683 11.448 15.829 ;
     RECT  18.096 15.589 21.612 15.925 ;
     RECT  26.016 15.349 28.056 15.925 ;
     RECT  33.888 15.493 37.812 15.971 ;
     RECT  2.4 15.683 5.976 16.019 ;
     RECT  7.584 15.829 8.328 16.069 ;
     RECT  9.792 15.829 11.448 16.069 ;
     RECT  30.96 15.589 30.984 16.163 ;
     RECT  17.952 15.925 21.612 16.261 ;
     RECT  32.1 9.875 32.412 16.261 ;
     RECT  25.632 15.925 28.056 16.405 ;
     RECT  29.232 13.525 29.712 16.405 ;
     RECT  32.1 16.261 33.096 16.451 ;
     RECT  7.584 16.069 11.448 16.547 ;
     RECT  25.632 16.405 29.712 16.595 ;
     RECT  7.8 16.547 11.448 16.835 ;
     RECT  25.68 16.595 29.712 16.933 ;
     RECT  30.912 16.645 30.936 16.933 ;
     RECT  7.8 16.835 10.812 17.171 ;
     RECT  17.952 16.261 21.72 17.171 ;
     RECT  24 15.443 24.312 17.173 ;
     RECT  18 17.171 21.72 17.219 ;
     RECT  25.68 16.933 30.936 17.219 ;
     RECT  25.68 17.219 28.056 17.267 ;
     RECT  2.4 16.019 2.808 17.507 ;
     RECT  3.792 16.019 5.976 17.605 ;
     RECT  12.96 15.155 14.376 17.605 ;
     RECT  15.9 15.155 16.344 17.651 ;
     RECT  29.232 17.219 30.168 17.699 ;
     RECT  32.1 16.451 33 17.845 ;
     RECT  32.1 17.845 33.048 17.989 ;
     RECT  22.992 17.989 23.016 18.133 ;
     RECT  24 17.173 24.504 18.133 ;
     RECT  25.68 17.267 25.704 18.133 ;
     RECT  26.7 17.267 28.056 18.179 ;
     RECT  12.144 17.605 14.376 18.181 ;
     RECT  20.448 17.219 21.72 18.181 ;
     RECT  34.8 15.971 37.812 18.275 ;
     RECT  32.1 17.989 33.48 18.565 ;
     RECT  2.4 17.507 2.712 18.709 ;
     RECT  3.792 17.605 6.648 18.709 ;
     RECT  15.9 17.651 16.212 18.709 ;
     RECT  12.144 18.181 14.808 18.755 ;
     RECT  29.232 17.699 29.712 18.805 ;
     RECT  12.144 18.755 13.8 18.851 ;
     RECT  20.448 18.181 21.912 18.851 ;
     RECT  12.144 18.851 13.704 18.947 ;
     RECT  2.4 18.709 6.648 19.285 ;
     RECT  20.832 18.851 21.912 19.333 ;
     RECT  22.992 18.133 25.704 19.333 ;
     RECT  31.776 18.565 33.48 19.333 ;
     RECT  34.8 18.275 35.592 19.333 ;
     RECT  12.144 18.947 13.512 19.427 ;
     RECT  14.784 18.755 14.808 19.427 ;
     RECT  29.04 18.805 29.712 19.523 ;
     RECT  2.4 19.285 6.744 19.667 ;
     RECT  9.696 17.171 10.812 19.669 ;
     RECT  29.232 19.523 29.712 19.811 ;
     RECT  4.8 19.667 6.744 19.907 ;
     RECT  2.4 19.667 3.816 20.003 ;
     RECT  7.8 17.171 8.328 20.003 ;
     RECT  20.832 19.333 25.704 20.003 ;
     RECT  23.904 20.003 25.704 20.051 ;
     RECT  15.792 18.709 16.212 20.099 ;
     RECT  31.776 19.333 35.592 20.101 ;
     RECT  36.576 18.275 37.812 20.101 ;
     RECT  31.776 20.101 37.812 20.243 ;
     RECT  9.552 19.669 10.812 20.341 ;
     RECT  2.4 20.003 3.144 20.435 ;
     RECT  31.776 20.243 35.112 20.485 ;
     RECT  12.768 19.427 13.512 20.533 ;
     RECT  6.72 19.907 6.744 20.579 ;
     RECT  18 17.219 18.912 20.627 ;
     RECT  30.816 20.485 35.112 20.723 ;
     RECT  4.8 19.907 5.736 20.725 ;
     RECT  9.552 20.341 11.4 20.821 ;
     RECT  12.672 20.533 13.512 20.821 ;
     RECT  36.576 20.243 37.812 21.107 ;
     RECT  7.8 20.003 8.232 21.155 ;
     RECT  30.816 20.723 32.412 21.155 ;
     RECT  9.552 20.821 13.512 21.157 ;
     RECT  23.904 20.051 25.176 21.157 ;
     RECT  26.7 18.179 27.624 21.445 ;
     RECT  20.832 20.003 22.872 21.491 ;
     RECT  29.4 19.811 29.712 21.493 ;
     RECT  30.816 21.155 30.84 21.493 ;
     RECT  29.4 21.493 30.84 21.683 ;
     RECT  9.216 21.157 13.512 21.781 ;
     RECT  15.9 20.099 16.212 21.925 ;
     RECT  9.12 21.781 13.512 21.971 ;
     RECT  9.168 21.971 13.512 22.165 ;
     RECT  32.1 21.155 32.412 22.165 ;
     RECT  18.192 20.627 18.912 22.213 ;
     RECT  26.7 21.445 27.912 22.259 ;
     RECT  9.168 22.165 14.232 22.355 ;
     RECT  18.192 22.213 19.176 22.453 ;
     RECT  12 22.355 14.232 22.499 ;
     RECT  23.904 21.157 25.224 22.501 ;
     RECT  26.7 22.259 27.624 22.501 ;
     RECT  31.872 22.165 32.412 22.597 ;
     RECT  33.456 20.723 35.112 22.597 ;
     RECT  23.904 22.501 27.624 22.643 ;
     RECT  23.904 22.643 25.464 22.739 ;
     RECT  15.456 21.925 16.212 22.741 ;
     RECT  29.4 21.683 30.456 22.741 ;
     RECT  1.152 22.357 1.176 22.787 ;
     RECT  20.832 21.491 22.824 22.787 ;
     RECT  31.872 22.597 35.112 22.883 ;
     RECT  7.8 21.155 8.112 23.029 ;
     RECT  9.168 22.355 10.968 23.029 ;
     RECT  15.456 22.741 16.536 23.029 ;
     RECT  7.8 23.029 10.968 23.075 ;
     RECT  15.456 23.029 16.632 23.125 ;
     RECT  7.8 23.075 8.616 23.315 ;
     RECT  9.792 23.075 10.968 23.363 ;
     RECT  32.1 22.883 35.112 23.411 ;
     RECT  2.4 20.435 2.712 23.701 ;
     RECT  15.36 23.125 16.632 23.701 ;
     RECT  18.144 22.453 19.176 23.843 ;
     RECT  20.976 22.787 22.824 23.845 ;
     RECT  18.144 23.843 19.032 23.893 ;
     RECT  24 22.739 25.464 23.893 ;
     RECT  26.7 22.643 27.624 23.893 ;
     RECT  29.088 22.741 30.456 23.941 ;
     RECT  32.1 23.411 32.412 23.941 ;
     RECT  33.792 23.411 35.112 24.083 ;
     RECT  36.72 21.107 37.812 24.083 ;
     RECT  7.8 23.315 8.52 24.131 ;
     RECT  20.544 23.845 22.824 24.131 ;
     RECT  29.088 23.941 30.792 24.227 ;
     RECT  15.36 23.701 16.68 24.229 ;
     RECT  7.8 24.131 8.112 24.373 ;
     RECT  7.44 24.373 8.112 24.469 ;
     RECT  15.36 24.229 16.728 24.613 ;
     RECT  12.288 22.499 14.232 24.659 ;
     RECT  12.528 24.659 14.232 24.707 ;
     RECT  31.872 23.941 32.412 24.709 ;
     RECT  33.792 24.083 33.816 24.709 ;
     RECT  15.36 24.613 16.824 24.755 ;
     RECT  24 23.893 27.624 24.755 ;
     RECT  10.176 23.363 10.968 24.757 ;
     RECT  15.36 24.755 16.728 24.803 ;
     RECT  10.032 24.757 10.968 24.805 ;
     RECT  29.088 24.227 30.456 24.899 ;
     RECT  12.528 24.707 14.184 25.091 ;
     RECT  2.4 23.701 3.192 25.235 ;
     RECT  17.904 23.893 19.032 25.237 ;
     RECT  17.904 25.237 19.368 25.573 ;
     RECT  20.544 24.131 21.612 25.573 ;
     RECT  9.648 24.805 10.968 25.621 ;
     RECT  7.296 24.469 8.112 25.715 ;
     RECT  7.68 25.715 8.112 25.717 ;
     RECT  9.648 25.621 11.16 25.717 ;
     RECT  12.816 25.091 14.184 25.717 ;
     RECT  36.816 24.083 37.812 25.717 ;
     RECT  12.816 25.717 14.28 25.859 ;
     RECT  15.9 24.803 16.728 25.909 ;
     RECT  31.872 24.709 33.816 26.005 ;
     RECT  34.8 24.083 35.112 26.005 ;
     RECT  15.9 25.909 16.92 26.101 ;
     RECT  17.904 25.573 21.612 26.101 ;
     RECT  29.088 24.899 29.712 26.101 ;
     RECT  22.8 24.131 22.824 26.147 ;
     RECT  24 24.755 25.176 26.149 ;
     RECT  26.16 24.755 27.624 26.149 ;
     RECT  24 26.149 27.624 26.291 ;
     RECT  28.656 26.101 29.712 26.341 ;
     RECT  12.816 25.859 13.704 26.579 ;
     RECT  31.872 26.005 35.112 26.579 ;
     RECT  12.816 26.579 13.512 26.629 ;
     RECT  4.416 20.725 5.736 26.677 ;
     RECT  12.768 26.629 13.512 26.771 ;
     RECT  24 26.291 27.012 26.771 ;
     RECT  15.9 26.101 21.612 26.819 ;
     RECT  4.416 26.677 6.072 27.205 ;
     RECT  7.68 25.717 11.16 27.205 ;
     RECT  20.544 26.819 21.612 27.205 ;
     RECT  24 26.771 25.176 27.205 ;
     RECT  4.416 27.205 11.16 27.395 ;
     RECT  28.656 26.341 30.504 27.395 ;
     RECT  33.792 26.579 35.112 27.395 ;
     RECT  29.4 27.395 30.504 27.445 ;
     RECT  31.872 26.579 32.412 27.445 ;
     RECT  26.352 26.771 27.012 27.637 ;
     RECT  36.72 25.717 37.812 27.731 ;
     RECT  2.4 25.235 3.144 27.877 ;
     RECT  20.544 27.205 21.72 27.971 ;
     RECT  29.4 27.445 32.412 28.403 ;
     RECT  4.416 27.395 5.736 28.405 ;
     RECT  6.912 27.395 11.16 28.451 ;
     RECT  12.816 26.771 13.512 28.453 ;
     RECT  6.912 28.451 9 28.547 ;
     RECT  15.9 26.819 18.912 28.691 ;
     RECT  40.848 28.501 40.872 28.787 ;
     RECT  2.4 27.877 3.432 28.837 ;
     RECT  4.416 28.405 5.784 28.837 ;
     RECT  26.352 27.637 27.144 28.883 ;
     RECT  37.008 27.731 37.812 28.979 ;
     RECT  23.664 27.205 25.176 28.981 ;
     RECT  29.4 28.403 31.08 29.075 ;
     RECT  37.392 28.979 37.812 29.123 ;
     RECT  12.816 28.453 13.992 29.315 ;
     RECT  32.1 28.403 32.412 29.605 ;
     RECT  33.984 27.395 35.112 29.605 ;
     RECT  12.816 29.315 13.512 29.699 ;
     RECT  13.056 29.699 13.512 29.843 ;
     RECT  15.9 28.691 16.212 29.893 ;
     RECT  17.232 28.691 18.912 29.893 ;
     RECT  29.4 29.075 31.032 30.035 ;
     RECT  29.4 30.035 30.504 30.133 ;
     RECT  29.28 30.133 30.504 30.179 ;
     RECT  2.4 28.837 5.784 30.181 ;
     RECT  7.2 28.547 8.112 30.181 ;
     RECT  21.3 27.971 21.612 30.181 ;
     RECT  20.256 30.181 20.28 30.325 ;
     RECT  21.3 30.181 22.152 30.325 ;
     RECT  15.9 29.893 18.912 30.373 ;
     RECT  20.256 30.325 22.152 30.373 ;
     RECT  15.9 30.373 22.152 30.757 ;
     RECT  23.568 28.981 25.176 30.757 ;
     RECT  32.1 29.605 35.112 30.803 ;
     RECT  10.032 28.451 11.16 30.997 ;
     RECT  9.648 30.997 11.16 31.141 ;
     RECT  15.744 30.757 22.152 31.379 ;
     RECT  9.36 31.141 11.16 31.525 ;
     RECT  13.2 29.843 13.512 31.669 ;
     RECT  26.352 28.883 27.012 31.861 ;
     RECT  29.28 30.179 29.712 31.861 ;
     RECT  36.432 31.285 36.456 31.907 ;
     RECT  21.12 31.379 22.152 32.051 ;
     RECT  2.4 30.181 8.112 32.053 ;
     RECT  9.36 31.525 11.256 32.053 ;
     RECT  23.376 30.757 25.176 32.195 ;
     RECT  13.104 31.669 13.512 32.293 ;
     RECT  15.744 31.379 19.608 32.341 ;
     RECT  21.12 32.051 21.816 32.341 ;
     RECT  2.4 32.053 11.256 32.387 ;
     RECT  2.4 32.387 11.16 32.483 ;
     RECT  13.104 32.293 14.232 32.531 ;
     RECT  28.992 31.861 29.712 32.819 ;
     RECT  32.1 30.803 33.192 33.011 ;
     RECT  13.2 32.531 14.232 33.107 ;
     RECT  15.744 32.341 21.816 33.107 ;
     RECT  7.056 32.483 11.16 33.299 ;
     RECT  29.088 32.819 29.712 33.397 ;
     RECT  24 32.195 25.176 33.589 ;
     RECT  26.352 31.861 27.624 33.589 ;
     RECT  34.8 30.803 35.112 33.589 ;
     RECT  7.056 33.299 8.112 33.637 ;
     RECT  2.4 32.483 5.544 33.829 ;
     RECT  6.816 33.637 8.112 33.829 ;
     RECT  9.408 33.299 11.16 33.971 ;
     RECT  10.224 33.971 11.16 33.973 ;
     RECT  29.088 33.397 30.216 34.117 ;
     RECT  13.2 33.107 13.512 34.357 ;
     RECT  10.224 33.973 12.072 34.691 ;
     RECT  21.12 33.107 21.816 34.741 ;
     RECT  29.088 34.117 30.312 34.835 ;
     RECT  10.5 34.691 12.072 34.979 ;
     RECT  13.104 34.357 13.512 34.981 ;
     RECT  15.744 33.107 19.32 35.029 ;
     RECT  20.784 34.741 21.816 35.029 ;
     RECT  34.08 33.589 35.112 35.029 ;
     RECT  33.648 35.029 35.112 35.075 ;
     RECT  37.5 29.123 37.812 35.269 ;
     RECT  29.088 34.835 30.216 35.411 ;
     RECT  13.104 34.981 13.656 35.797 ;
     RECT  2.4 33.829 8.112 35.987 ;
     RECT  10.5 34.979 11.736 35.989 ;
     RECT  32.1 33.011 32.412 35.989 ;
     RECT  10.5 35.989 11.832 36.035 ;
     RECT  15.744 35.029 21.816 36.083 ;
     RECT  4.272 35.987 8.112 36.085 ;
     RECT  15.744 36.083 19.752 36.131 ;
     RECT  15.744 36.131 16.488 36.181 ;
     RECT  24 33.589 27.624 36.325 ;
     RECT  23.472 36.325 27.624 36.469 ;
     RECT  33.648 35.075 33.672 36.469 ;
     RECT  34.8 35.075 35.112 36.469 ;
     RECT  20.784 36.083 21.816 36.515 ;
     RECT  31.968 35.989 32.412 36.515 ;
     RECT  2.4 35.987 2.856 36.563 ;
     RECT  10.5 36.035 10.812 36.613 ;
     RECT  29.088 35.411 29.712 37.331 ;
     RECT  17.808 36.131 19.752 37.381 ;
     RECT  9.648 36.613 10.812 37.573 ;
     RECT  11.808 36.035 11.832 37.573 ;
     RECT  13.008 35.797 13.656 37.573 ;
     RECT  23.472 36.469 27.912 37.573 ;
     RECT  33.648 36.469 35.112 37.573 ;
     RECT  4.272 36.085 8.28 37.619 ;
     RECT  21.12 36.515 21.816 37.859 ;
     RECT  23.376 37.573 27.912 37.859 ;
     RECT  30.864 36.805 30.888 38.003 ;
     RECT  4.512 37.619 8.28 38.005 ;
     RECT  9.648 37.573 11.832 38.005 ;
     RECT  9.648 38.005 11.928 38.149 ;
     RECT  12.96 37.573 13.656 38.149 ;
     RECT  4.512 38.005 8.52 38.243 ;
     RECT  9.648 38.149 13.656 38.245 ;
     RECT  21.3 37.859 21.816 38.389 ;
     RECT  4.512 38.243 8.232 38.435 ;
     RECT  32.1 36.515 32.412 38.485 ;
     RECT  9.648 38.245 13.944 38.531 ;
     RECT  2.4 36.563 2.712 38.533 ;
     RECT  17.664 37.381 19.752 38.533 ;
     RECT  37.5 35.269 37.944 38.533 ;
     RECT  32.1 38.485 32.52 38.675 ;
     RECT  9.648 38.531 13.512 38.771 ;
     RECT  15.408 36.181 16.488 38.867 ;
     RECT  33.648 37.573 35.448 39.205 ;
     RECT  17.664 38.533 20.328 39.251 ;
     RECT  2.4 38.533 3.432 39.491 ;
     RECT  17.664 39.251 18.912 39.539 ;
     RECT  12.528 38.771 13.512 39.589 ;
     RECT  15.408 38.867 16.212 39.733 ;
     RECT  20.304 39.251 20.328 39.733 ;
     RECT  21.3 38.389 22.248 39.733 ;
     RECT  17.904 39.539 18.912 39.779 ;
     RECT  33.648 39.205 35.88 39.829 ;
     RECT  36.96 38.533 37.944 39.829 ;
     RECT  23.376 37.859 27.012 39.923 ;
     RECT  33.648 39.829 37.944 40.019 ;
     RECT  9.648 38.771 11.304 40.021 ;
     RECT  9.264 40.021 11.304 40.165 ;
     RECT  12.528 39.589 13.848 40.165 ;
     RECT  18.6 39.779 18.912 40.405 ;
     RECT  20.304 39.733 22.248 40.405 ;
     RECT  29.136 37.331 29.712 40.405 ;
     RECT  23.376 39.923 25.224 40.451 ;
     RECT  36.48 40.019 37.944 40.451 ;
     RECT  4.752 38.435 8.232 40.595 ;
     RECT  9.264 40.165 13.848 40.693 ;
     RECT  15.072 39.733 16.212 40.693 ;
     RECT  32.1 38.675 32.412 40.693 ;
     RECT  4.992 40.595 8.232 40.789 ;
     RECT  9.264 40.693 16.212 40.789 ;
     RECT  4.992 40.789 16.212 40.835 ;
     RECT  15.072 40.835 16.212 40.837 ;
     RECT  33.648 40.019 35.208 40.883 ;
     RECT  15.072 40.837 16.824 40.981 ;
     RECT  23.472 40.451 25.224 41.029 ;
     RECT  4.992 40.835 13.848 41.075 ;
     RECT  15.072 40.981 17.112 41.077 ;
     RECT  18.6 40.405 22.248 41.123 ;
     RECT  23.472 41.029 25.272 41.125 ;
     RECT  26.352 39.923 27.012 41.125 ;
     RECT  15.072 41.077 17.208 41.173 ;
     RECT  18.6 41.123 22.056 41.173 ;
     RECT  15.072 41.173 22.056 41.219 ;
     RECT  29.136 40.405 30.456 41.555 ;
     RECT  4.992 41.075 13.608 41.651 ;
     RECT  31.872 40.693 32.412 41.651 ;
     RECT  36.48 40.451 37.812 41.651 ;
     RECT  2.4 39.491 2.712 41.749 ;
     RECT  36.48 41.651 36.504 41.939 ;
     RECT  11.904 41.651 13.608 42.037 ;
     RECT  2.304 41.749 2.712 42.083 ;
     RECT  11.904 42.037 13.656 42.085 ;
     RECT  15.072 41.219 16.212 42.085 ;
     RECT  29.136 41.555 30.216 42.469 ;
     RECT  11.904 42.085 16.212 42.565 ;
     RECT  17.712 41.219 22.056 42.611 ;
     RECT  3.936 40.885 3.96 42.709 ;
     RECT  4.992 41.651 10.812 42.709 ;
     RECT  18.6 42.611 22.056 42.995 ;
     RECT  11.904 42.565 16.44 43.285 ;
     RECT  29.088 42.469 30.216 43.285 ;
     RECT  3.936 42.709 10.812 43.379 ;
     RECT  11.904 43.285 17.304 43.379 ;
     RECT  5.1 43.379 10.812 43.573 ;
     RECT  11.904 43.379 11.976 43.573 ;
     RECT  20.4 42.995 22.056 43.621 ;
     RECT  23.472 41.125 27.012 43.621 ;
     RECT  20.4 43.621 27.012 43.667 ;
     RECT  13.104 43.379 17.304 43.859 ;
     RECT  32.1 41.651 32.412 43.909 ;
     RECT  33.648 40.883 35.112 43.909 ;
     RECT  15.168 43.859 17.304 44.003 ;
     RECT  32.1 43.909 35.112 44.099 ;
     RECT  33.696 44.099 35.112 44.437 ;
     RECT  15.168 44.003 16.536 44.483 ;
     RECT  28.032 43.285 28.056 44.483 ;
     RECT  5.1 43.573 11.976 44.629 ;
     RECT  13.104 43.859 13.608 44.629 ;
     RECT  5.1 44.629 13.608 44.675 ;
     RECT  5.1 44.675 10.812 45.011 ;
     RECT  11.952 44.675 13.608 45.011 ;
     RECT  29.088 43.285 30.648 45.011 ;
     RECT  5.1 45.011 6.552 45.157 ;
     RECT  29.088 45.011 30.312 45.251 ;
     RECT  11.952 45.011 11.976 45.299 ;
     RECT  13.104 45.011 13.608 45.491 ;
     RECT  15.168 44.483 16.44 45.541 ;
     RECT  33.696 44.437 35.208 45.541 ;
     RECT  29.136 45.251 30.312 45.635 ;
     RECT  36.48 44.965 36.504 45.781 ;
     RECT  37.5 41.651 37.812 45.781 ;
     RECT  7.8 45.011 10.812 45.827 ;
     RECT  36.48 45.781 37.812 45.827 ;
     RECT  21.072 43.667 27.012 46.019 ;
     RECT  14.832 45.541 16.44 46.021 ;
     RECT  4.512 45.157 6.552 46.069 ;
     RECT  7.8 45.827 9.336 46.069 ;
     RECT  14.832 46.021 16.488 46.069 ;
     RECT  33.696 45.541 35.256 46.069 ;
     RECT  13.104 45.491 13.512 46.117 ;
     RECT  33.648 46.069 35.256 46.259 ;
     RECT  4.512 46.069 9.336 46.645 ;
     RECT  21.072 46.019 25.368 47.075 ;
     RECT  14.832 46.069 16.872 47.171 ;
     RECT  4.224 46.645 9.336 47.269 ;
     RECT  10.5 45.827 10.812 47.605 ;
     RECT  21.3 47.075 25.368 47.701 ;
     RECT  21.3 47.701 25.56 47.843 ;
     RECT  25.344 47.843 25.56 47.845 ;
     RECT  32.1 44.099 32.412 47.845 ;
     RECT  33.648 46.259 35.112 47.845 ;
     RECT  25.344 47.845 25.656 47.891 ;
     RECT  32.1 47.845 35.112 48.083 ;
     RECT  29.136 45.635 29.712 48.275 ;
     RECT  15.648 47.171 16.872 48.277 ;
     RECT  21.3 47.843 24.312 48.277 ;
     RECT  36.768 45.827 37.812 48.277 ;
     RECT  3.936 47.269 9.336 48.373 ;
     RECT  10.5 47.605 10.968 48.373 ;
     RECT  3.936 48.373 10.968 48.421 ;
     RECT  12.528 46.117 13.512 48.421 ;
     RECT  26.7 46.019 27.012 48.421 ;
     RECT  29.4 48.275 29.712 48.421 ;
     RECT  2.4 42.083 2.712 48.469 ;
     RECT  3.936 48.421 13.512 48.469 ;
     RECT  26.7 48.421 27.96 48.757 ;
     RECT  21.072 48.277 24.312 48.947 ;
     RECT  18.6 42.995 18.912 48.949 ;
     RECT  32.1 48.083 33.72 49.045 ;
     RECT  34.8 48.083 35.112 49.045 ;
     RECT  32.1 49.045 35.112 49.091 ;
     RECT  25.488 47.891 25.656 49.235 ;
     RECT  26.7 48.757 28.008 49.379 ;
     RECT  2.4 48.469 13.512 49.381 ;
     RECT  2.4 49.381 13.944 49.475 ;
     RECT  15.648 48.277 17.016 49.525 ;
     RECT  18.48 48.949 18.912 49.525 ;
     RECT  4.224 49.475 13.944 49.619 ;
     RECT  15.648 49.525 18.912 49.619 ;
     RECT  4.224 49.619 8.112 49.763 ;
     RECT  34.224 49.091 35.112 49.861 ;
     RECT  36.144 48.277 37.812 49.861 ;
     RECT  4.224 49.763 6.552 50.051 ;
     RECT  29.4 48.421 30.36 50.195 ;
     RECT  21.168 48.947 24.312 50.293 ;
     RECT  29.4 50.195 29.712 50.293 ;
     RECT  27.984 49.379 28.008 50.485 ;
     RECT  29.232 50.293 29.712 50.485 ;
     RECT  4.512 50.051 6.552 50.579 ;
     RECT  9.312 49.619 13.944 50.581 ;
     RECT  2.4 49.475 2.712 50.677 ;
     RECT  25.536 49.235 25.656 50.677 ;
     RECT  27.984 50.485 29.712 50.819 ;
     RECT  28.128 50.819 29.712 50.915 ;
     RECT  15.9 49.619 18.912 50.965 ;
     RECT  21.072 50.293 24.312 51.205 ;
     RECT  15.9 50.965 19.416 51.347 ;
     RECT  9.264 50.581 13.944 51.443 ;
     RECT  9.264 51.443 10.812 51.637 ;
     RECT  25.44 50.677 25.656 51.685 ;
     RECT  34.224 49.861 37.812 51.731 ;
     RECT  25.392 51.685 25.656 51.827 ;
     RECT  0.144 51.685 0.168 51.875 ;
     RECT  12.432 51.443 13.944 51.875 ;
     RECT  37.392 51.731 37.812 51.923 ;
     RECT  2.4 50.677 3.336 52.211 ;
     RECT  12.528 51.875 13.944 52.307 ;
     RECT  30.768 51.205 30.792 52.499 ;
     RECT  25.536 51.827 25.656 52.741 ;
     RECT  26.7 49.379 27.012 52.741 ;
     RECT  34.224 51.731 35.88 52.979 ;
     RECT  7.8 49.763 8.112 52.981 ;
     RECT  9.12 51.637 10.812 52.981 ;
     RECT  25.536 52.741 27.012 52.981 ;
     RECT  21.024 51.205 24.312 53.027 ;
     RECT  29.4 50.915 29.712 53.029 ;
     RECT  7.8 52.981 10.812 53.123 ;
     RECT  12.528 52.307 13.704 53.171 ;
     RECT  21.024 53.027 22.488 53.173 ;
     RECT  32.1 49.091 33 53.269 ;
     RECT  4.896 50.579 6.552 53.363 ;
     RECT  32.1 53.269 33.432 53.411 ;
     RECT  34.8 52.979 35.88 53.411 ;
     RECT  15.9 51.347 17.352 53.699 ;
     RECT  37.5 51.923 37.812 53.701 ;
     RECT  0.144 53.653 0.168 53.843 ;
     RECT  18.6 51.347 19.416 54.179 ;
     RECT  15.9 53.699 16.212 54.469 ;
     RECT  2.4 52.211 2.712 54.613 ;
     RECT  20.784 53.173 22.488 54.613 ;
     RECT  10.5 53.123 10.812 54.661 ;
     RECT  40.368 54.661 40.392 54.899 ;
     RECT  12.528 53.171 13.512 54.995 ;
     RECT  0.144 54.949 0.168 55.139 ;
     RECT  29.4 53.029 30.6 55.141 ;
     RECT  32.1 53.411 32.616 55.141 ;
     RECT  36.336 55.093 36.36 55.189 ;
     RECT  37.392 53.701 37.812 55.189 ;
     RECT  12.624 54.995 13.512 55.283 ;
     RECT  18.6 54.179 18.912 55.285 ;
     RECT  20.496 54.613 22.488 55.331 ;
     RECT  28.128 50.915 28.152 55.331 ;
     RECT  10.5 54.661 11.4 55.427 ;
     RECT  34.8 53.411 35.112 55.429 ;
     RECT  29.4 55.141 32.616 55.717 ;
     RECT  2.4 54.613 3.288 55.859 ;
     RECT  28.56 55.717 33.048 55.907 ;
     RECT  28.56 55.907 32.412 55.955 ;
     RECT  36.336 55.189 37.812 56.099 ;
     RECT  34.8 55.429 35.352 56.243 ;
     RECT  15.264 54.469 16.212 56.245 ;
     RECT  18.6 55.285 19.032 56.291 ;
     RECT  12.768 55.283 13.512 56.533 ;
     RECT  31.44 55.955 32.412 56.771 ;
     RECT  4.896 53.363 6.36 56.915 ;
     RECT  20.976 55.331 22.488 57.013 ;
     RECT  23.472 53.027 24.312 57.013 ;
     RECT  25.44 52.981 27.012 57.013 ;
     RECT  14.976 56.245 16.212 57.059 ;
     RECT  20.976 57.013 27.012 57.059 ;
     RECT  18.6 56.291 18.912 57.301 ;
     RECT  36.96 56.099 37.812 57.395 ;
     RECT  28.56 55.955 29.712 57.445 ;
     RECT  5.1 56.915 6.36 57.541 ;
     RECT  7.8 53.123 9.336 57.541 ;
     RECT  34.8 56.243 35.304 57.589 ;
     RECT  32.1 56.771 32.412 57.781 ;
     RECT  17.328 53.699 17.352 57.877 ;
     RECT  18.432 57.301 18.912 57.877 ;
     RECT  17.328 57.877 18.912 57.923 ;
     RECT  21.12 57.059 27.012 58.021 ;
     RECT  17.472 57.923 18.912 58.117 ;
     RECT  20.688 58.021 27.012 58.117 ;
     RECT  28.32 57.445 29.712 58.117 ;
     RECT  34.8 57.589 35.928 58.117 ;
     RECT  17.472 58.117 27.012 58.211 ;
     RECT  2.4 55.859 2.712 58.357 ;
     RECT  26.7 58.211 27.012 58.405 ;
     RECT  17.472 58.211 25.656 58.451 ;
     RECT  28.32 58.117 29.832 58.451 ;
     RECT  2.4 58.357 2.904 58.499 ;
     RECT  34.272 58.117 35.928 58.693 ;
     RECT  5.1 57.541 9.336 58.739 ;
     RECT  17.472 58.451 24.312 58.787 ;
     RECT  10.5 55.427 10.812 58.885 ;
     RECT  12.576 56.533 13.512 58.885 ;
     RECT  10.5 58.885 13.512 59.027 ;
     RECT  2.4 58.499 2.808 59.029 ;
     RECT  31.248 57.781 32.412 59.029 ;
     RECT  15.696 57.059 16.212 59.077 ;
     RECT  2.304 59.029 2.808 59.219 ;
     RECT  26.7 58.405 27.144 59.267 ;
     RECT  31.248 59.029 33.192 59.267 ;
     RECT  31.248 59.267 32.412 59.315 ;
     RECT  25.632 58.451 25.656 59.459 ;
     RECT  0.192 56.773 0.216 59.509 ;
     RECT  28.32 58.451 28.344 59.603 ;
     RECT  34.272 58.693 36.024 59.651 ;
     RECT  15.36 59.077 16.212 59.701 ;
     RECT  34.272 59.651 35.928 59.747 ;
     RECT  17.472 58.787 19.176 59.749 ;
     RECT  17.376 59.749 19.176 59.795 ;
     RECT  15.312 59.701 16.212 59.843 ;
     RECT  2.4 59.219 2.808 59.845 ;
     RECT  12.528 59.027 13.512 59.845 ;
     RECT  18.432 59.795 19.176 59.891 ;
     RECT  34.272 59.747 35.256 59.891 ;
     RECT  0.192 59.509 0.408 59.939 ;
     RECT  7.8 58.739 9.336 59.941 ;
     RECT  34.272 59.891 35.112 59.987 ;
     RECT  0.192 59.939 0.216 60.083 ;
     RECT  7.8 59.941 9.48 60.131 ;
     RECT  26.7 59.267 27.012 60.277 ;
     RECT  5.1 58.739 6.36 60.373 ;
     RECT  7.8 60.131 9.384 60.373 ;
     RECT  29.4 58.451 29.832 60.373 ;
     RECT  31.296 59.315 32.412 60.373 ;
     RECT  12.528 59.845 13.752 60.467 ;
     RECT  37.5 57.395 37.812 60.517 ;
     RECT  12.576 60.467 13.752 60.901 ;
     RECT  26.208 60.277 27.012 60.901 ;
     RECT  17.376 59.795 17.4 60.949 ;
     RECT  18.432 59.891 18.912 60.949 ;
     RECT  20.256 58.787 24.312 60.997 ;
     RECT  15.696 59.843 16.212 61.045 ;
     RECT  12.576 60.901 13.896 61.141 ;
     RECT  20.256 60.997 25.08 61.141 ;
     RECT  29.4 60.373 32.412 61.187 ;
     RECT  17.376 60.949 18.912 61.189 ;
     RECT  34.8 59.987 35.112 61.237 ;
     RECT  15.696 61.045 16.344 61.381 ;
     RECT  17.376 61.189 19.032 61.381 ;
     RECT  20.256 61.141 25.128 61.381 ;
     RECT  26.208 60.901 27.96 61.381 ;
     RECT  20.256 61.381 27.96 61.427 ;
     RECT  5.1 60.373 9.384 61.429 ;
     RECT  12.576 61.141 14.664 61.429 ;
     RECT  4.992 61.429 9.384 61.475 ;
     RECT  21.168 61.427 27.96 61.571 ;
     RECT  2.4 59.845 3.288 61.619 ;
     RECT  36.96 60.517 37.812 61.619 ;
     RECT  29.4 61.187 30.408 61.765 ;
     RECT  10.5 59.027 10.812 61.909 ;
     RECT  10.5 61.909 11.112 62.053 ;
     RECT  12.24 61.429 14.664 62.053 ;
     RECT  25.872 61.571 27.96 62.195 ;
     RECT  7.8 61.475 9.384 62.389 ;
     RECT  10.5 62.053 14.664 62.389 ;
     RECT  7.8 62.389 14.664 62.723 ;
     RECT  34.8 61.237 35.88 62.723 ;
     RECT  21.168 61.571 24.312 62.771 ;
     RECT  31.872 61.187 32.412 62.771 ;
     RECT  3.888 62.437 3.912 63.157 ;
     RECT  4.992 61.475 6.456 63.157 ;
     RECT  7.8 62.723 10.812 63.157 ;
     RECT  21.168 62.771 22.488 63.203 ;
     RECT  26.208 62.195 27.288 63.205 ;
     RECT  15.696 61.381 19.032 63.491 ;
     RECT  28.992 61.765 30.408 63.491 ;
     RECT  29.4 63.491 30.408 63.539 ;
     RECT  26.208 63.205 27.48 63.637 ;
     RECT  21.3 63.203 22.488 63.781 ;
     RECT  23.52 62.771 24.312 63.781 ;
     RECT  32.1 62.771 32.412 63.781 ;
     RECT  34.8 62.723 35.112 63.781 ;
     RECT  37.5 61.619 37.812 63.781 ;
     RECT  21.3 63.781 25.128 63.875 ;
     RECT  3.888 63.157 10.812 64.069 ;
     RECT  12.24 62.723 14.664 64.115 ;
     RECT  15.9 63.491 19.032 64.163 ;
     RECT  18.6 64.163 19.032 64.165 ;
     RECT  31.824 63.781 32.412 64.309 ;
     RECT  33.6 62.005 33.624 64.309 ;
     RECT  21.3 63.875 22.584 64.357 ;
     RECT  31.824 64.309 33.624 64.357 ;
     RECT  34.8 63.781 35.208 64.357 ;
     RECT  23.616 63.875 25.128 64.403 ;
     RECT  21.168 64.357 22.584 64.933 ;
     RECT  18.6 64.165 19.224 65.027 ;
     RECT  31.824 64.357 35.208 65.027 ;
     RECT  20.496 64.933 22.584 65.555 ;
     RECT  3.888 64.069 11.208 65.603 ;
     RECT  13.2 64.115 14.664 65.653 ;
     RECT  15.9 64.163 17.448 65.653 ;
     RECT  13.2 65.653 17.448 65.699 ;
     RECT  31.824 65.027 33.336 65.699 ;
     RECT  26.208 63.637 27.912 65.795 ;
     RECT  36.624 63.781 37.812 65.939 ;
     RECT  23.616 64.403 24.312 65.987 ;
     RECT  24 65.987 24.312 66.325 ;
     RECT  34.8 65.027 35.208 66.325 ;
     RECT  17.424 65.699 17.448 66.757 ;
     RECT  18.6 65.027 18.912 66.757 ;
     RECT  21.3 65.555 22.584 66.805 ;
     RECT  17.424 66.757 18.912 66.899 ;
     RECT  13.2 65.699 16.344 67.139 ;
     RECT  13.2 67.139 14.664 67.141 ;
     RECT  26.208 65.795 27.012 67.189 ;
     RECT  34.8 66.325 35.592 67.283 ;
     RECT  15.648 67.139 16.344 67.333 ;
     RECT  18.048 66.899 18.912 67.669 ;
     RECT  31.824 65.699 33.24 67.669 ;
     RECT  21.168 66.805 22.584 68.197 ;
     RECT  15.648 67.333 16.392 68.339 ;
     RECT  26.064 67.189 27.012 68.389 ;
     RECT  18.048 67.669 19.08 68.435 ;
     RECT  20.496 68.197 22.584 68.579 ;
     RECT  18.384 68.435 19.08 68.771 ;
     RECT  21.072 68.579 22.584 68.771 ;
     RECT  26.064 68.389 27.912 68.773 ;
     RECT  18.48 68.771 19.08 68.917 ;
     RECT  29.4 63.539 29.712 68.965 ;
     RECT  15.9 68.339 16.392 69.011 ;
     RECT  26.016 68.773 27.912 69.061 ;
     RECT  34.8 67.283 35.112 69.205 ;
     RECT  18.48 68.917 19.944 69.251 ;
     RECT  25.632 69.061 27.912 69.299 ;
     RECT  3.888 65.603 10.812 69.347 ;
     RECT  3.888 69.347 6.792 69.587 ;
     RECT  24 66.325 24.504 69.637 ;
     RECT  25.632 69.299 27.528 69.637 ;
     RECT  29.28 68.965 29.712 69.829 ;
     RECT  34.8 69.205 35.928 69.877 ;
     RECT  34.8 69.877 36.168 69.925 ;
     RECT  37.5 65.939 37.812 69.925 ;
     RECT  3.888 69.587 6.36 69.971 ;
     RECT  13.008 67.141 14.664 69.973 ;
     RECT  29.28 69.829 29.88 70.021 ;
     RECT  18.6 69.251 19.944 70.163 ;
     RECT  21.072 68.771 22.2 70.163 ;
     RECT  21.12 70.163 22.2 70.307 ;
     RECT  34.8 69.925 37.812 70.451 ;
     RECT  28.896 70.021 29.88 70.547 ;
     RECT  31.296 67.669 33.24 70.547 ;
     RECT  12.48 69.973 14.664 70.549 ;
     RECT  15.9 69.011 16.344 70.549 ;
     RECT  0.144 70.357 0.168 70.643 ;
     RECT  12.48 70.549 16.344 70.645 ;
     RECT  18.6 70.163 19.848 70.645 ;
     RECT  24 69.637 27.528 70.739 ;
     RECT  36.192 70.451 37.812 70.787 ;
     RECT  28.896 70.547 29.712 70.835 ;
     RECT  34.8 70.451 35.208 70.885 ;
     RECT  18.192 70.645 19.848 71.269 ;
     RECT  12.48 70.645 16.584 71.315 ;
     RECT  24 70.739 27.012 71.413 ;
     RECT  18.192 71.269 19.944 71.507 ;
     RECT  18.6 71.507 19.944 71.651 ;
     RECT  31.968 70.547 33.24 71.701 ;
     RECT  21.12 70.307 22.008 71.747 ;
     RECT  31.296 71.701 33.24 71.747 ;
     RECT  15.648 71.315 16.584 71.797 ;
     RECT  15.648 71.797 17.112 71.893 ;
     RECT  34.416 70.885 35.208 71.893 ;
     RECT  15.648 71.893 17.208 72.035 ;
     RECT  2.4 61.619 2.712 72.133 ;
     RECT  34.416 71.893 35.256 72.179 ;
     RECT  4.8 69.971 6.36 72.325 ;
     RECT  40.848 71.893 40.872 72.419 ;
     RECT  21.12 71.747 21.816 72.421 ;
     RECT  23.328 71.413 27.012 72.565 ;
     RECT  18.6 71.651 19.848 72.757 ;
     RECT  20.88 72.421 21.816 72.757 ;
     RECT  31.296 71.747 32.616 72.803 ;
     RECT  2.4 72.133 3.288 72.995 ;
     RECT  31.296 72.803 32.412 72.995 ;
     RECT  37.008 70.787 37.812 72.995 ;
     RECT  22.848 72.565 27.012 73.091 ;
     RECT  15.648 72.035 17.112 73.139 ;
     RECT  29.136 70.835 29.712 73.333 ;
     RECT  4.8 72.325 6.504 73.379 ;
     RECT  12.48 71.315 14.664 73.571 ;
     RECT  7.8 69.347 10.812 73.621 ;
     RECT  18.6 72.757 21.816 73.715 ;
     RECT  0.144 73.813 0.168 74.099 ;
     RECT  29.04 73.333 29.712 74.147 ;
     RECT  12.672 73.571 14.664 74.195 ;
     RECT  34.416 72.179 35.112 74.389 ;
     RECT  15.648 73.139 16.344 74.437 ;
     RECT  34.272 74.389 35.112 74.581 ;
     RECT  12.72 74.195 14.664 74.723 ;
     RECT  29.184 74.147 29.712 74.869 ;
     RECT  33.6 74.581 35.112 74.965 ;
     RECT  21.168 73.715 21.816 75.109 ;
     RECT  7.632 73.621 10.812 75.157 ;
     RECT  18.6 73.715 19.992 75.251 ;
     RECT  7.632 75.157 11.064 75.395 ;
     RECT  15.648 74.437 17.16 75.493 ;
     RECT  21.12 75.109 21.816 75.541 ;
     RECT  33.6 74.965 35.352 75.541 ;
     RECT  5.1 73.379 6.504 75.635 ;
     RECT  29.184 74.869 29.832 75.685 ;
     RECT  7.632 75.395 9.528 75.781 ;
     RECT  24 73.091 27.012 75.781 ;
     RECT  28.224 75.685 29.832 75.781 ;
     RECT  40.848 75.445 40.872 75.827 ;
     RECT  10.5 75.395 11.064 75.971 ;
     RECT  33.6 75.541 36.024 76.163 ;
     RECT  7.584 75.781 9.528 76.403 ;
     RECT  21.12 75.541 22.536 76.403 ;
     RECT  15.648 75.493 17.208 76.549 ;
     RECT  18.6 75.251 19.848 76.549 ;
     RECT  24 75.781 30.264 76.693 ;
     RECT  1.152 76.741 1.176 76.883 ;
     RECT  15.648 76.549 19.848 76.979 ;
     RECT  12.72 74.723 14.52 77.413 ;
     RECT  15.648 76.979 16.344 77.413 ;
     RECT  5.1 75.635 6.36 77.941 ;
     RECT  34.272 76.163 36.024 77.987 ;
     RECT  24 76.693 30.408 77.989 ;
     RECT  4.992 77.941 6.36 78.037 ;
     RECT  7.584 76.403 8.904 78.037 ;
     RECT  24 77.989 31.128 78.131 ;
     RECT  10.5 75.971 10.812 78.133 ;
     RECT  12.72 77.413 16.344 78.181 ;
     RECT  21.12 76.403 22.296 78.181 ;
     RECT  20.88 78.181 22.296 78.469 ;
     RECT  17.712 76.979 19.848 78.613 ;
     RECT  12.72 78.181 16.584 78.659 ;
     RECT  17.664 78.613 19.848 78.755 ;
     RECT  26.7 78.131 31.128 78.755 ;
     RECT  34.272 77.987 35.928 78.755 ;
     RECT  17.712 78.755 19.848 78.899 ;
     RECT  18 78.899 19.848 78.901 ;
     RECT  20.88 78.469 22.776 78.901 ;
     RECT  4.512 78.037 6.36 79.045 ;
     RECT  7.392 78.037 8.904 79.045 ;
     RECT  12.72 78.659 16.344 79.045 ;
     RECT  18 78.901 22.776 79.187 ;
     RECT  26.7 78.755 30.408 79.187 ;
     RECT  34.416 78.755 35.928 79.189 ;
     RECT  37.248 72.995 37.812 79.189 ;
     RECT  32.1 72.995 32.412 79.333 ;
     RECT  12.528 79.045 16.344 79.475 ;
     RECT  34.416 79.189 37.812 79.523 ;
     RECT  14.496 79.475 16.344 79.717 ;
     RECT  12.528 79.475 13.512 79.763 ;
     RECT  14.496 79.717 16.536 79.859 ;
     RECT  24 78.131 25.512 80.291 ;
     RECT  10.5 78.133 11.496 80.293 ;
     RECT  25.488 80.291 25.512 80.629 ;
     RECT  34.416 79.523 35.928 80.629 ;
     RECT  18 79.187 22.68 80.723 ;
     RECT  4.512 79.045 8.904 80.869 ;
     RECT  25.488 80.629 25.704 80.869 ;
     RECT  26.7 79.187 30.216 80.869 ;
     RECT  19.92 80.723 22.68 80.915 ;
     RECT  25.488 80.869 30.264 80.915 ;
     RECT  3.936 80.869 8.904 80.917 ;
     RECT  10.5 80.293 11.928 81.011 ;
     RECT  24 80.291 24.504 81.011 ;
     RECT  29.088 80.915 30.264 81.059 ;
     RECT  18 80.723 18.912 81.061 ;
     RECT  34.416 80.629 36.36 81.107 ;
     RECT  3.936 80.917 9.24 81.155 ;
     RECT  3.936 81.155 8.904 81.395 ;
     RECT  25.488 80.915 27.864 81.395 ;
     RECT  13.008 79.763 13.512 81.445 ;
     RECT  14.496 79.859 16.212 81.445 ;
     RECT  17.904 81.061 18.912 81.445 ;
     RECT  34.8 81.107 36.36 81.635 ;
     RECT  37.392 79.523 37.812 81.635 ;
     RECT  32.1 79.333 33.048 81.973 ;
     RECT  29.4 81.059 30.264 82.021 ;
     RECT  4.512 81.395 8.904 82.067 ;
     RECT  11.904 81.011 11.928 82.115 ;
     RECT  19.92 80.915 20.184 82.115 ;
     RECT  13.008 81.445 16.212 82.163 ;
     RECT  31.968 81.973 33.048 82.211 ;
     RECT  21.168 80.915 22.68 82.405 ;
     RECT  7.056 82.067 8.904 82.501 ;
     RECT  10.5 81.011 10.812 82.501 ;
     RECT  29.04 82.021 30.264 82.549 ;
     RECT  29.04 82.549 30.6 82.643 ;
     RECT  29.4 82.643 30.6 82.645 ;
     RECT  31.968 82.211 32.412 82.645 ;
     RECT  7.056 82.501 10.812 82.691 ;
     RECT  13.056 82.163 16.212 82.691 ;
     RECT  34.8 81.635 35.88 82.691 ;
     RECT  24 81.011 24.456 82.741 ;
     RECT  17.616 81.445 18.912 83.267 ;
     RECT  19.92 82.115 19.992 83.363 ;
     RECT  37.5 81.635 37.812 83.557 ;
     RECT  4.512 82.067 6.072 83.701 ;
     RECT  14.496 82.691 16.212 83.749 ;
     RECT  29.4 82.645 32.412 83.749 ;
     RECT  33.648 83.509 33.672 83.749 ;
     RECT  4.128 83.701 6.072 83.795 ;
     RECT  29.04 83.749 33.672 83.795 ;
     RECT  25.488 81.395 27.144 83.797 ;
     RECT  31.2 83.795 33.672 83.891 ;
     RECT  14.496 83.749 16.728 84.035 ;
     RECT  24 82.741 24.504 84.277 ;
     RECT  25.488 83.797 27.384 84.277 ;
     RECT  24 84.277 27.384 84.517 ;
     RECT  29.04 83.795 29.712 84.517 ;
     RECT  19.92 83.363 19.944 84.563 ;
     RECT  24 84.517 29.712 84.659 ;
     RECT  33.648 83.891 33.672 84.707 ;
     RECT  13.056 82.691 13.512 84.851 ;
     RECT  36.768 83.557 37.812 84.851 ;
     RECT  29.04 84.659 29.712 84.853 ;
     RECT  7.152 82.691 10.812 84.901 ;
     RECT  12 83.749 12.024 84.901 ;
     RECT  21.12 82.405 22.68 84.901 ;
     RECT  24 84.659 27.384 84.901 ;
     RECT  4.128 83.795 6.024 85.139 ;
     RECT  31.2 83.891 32.412 85.429 ;
     RECT  21.12 84.901 27.384 85.477 ;
     RECT  7.152 84.901 12.024 85.523 ;
     RECT  20.544 85.477 27.384 85.523 ;
     RECT  7.8 85.523 12.024 85.619 ;
     RECT  31.2 85.429 32.52 85.619 ;
     RECT  13.104 84.851 13.512 85.765 ;
     RECT  15.072 84.035 16.728 85.765 ;
     RECT  29.04 84.853 29.832 86.003 ;
     RECT  23.856 85.523 27.384 86.053 ;
     RECT  34.8 82.691 35.112 86.053 ;
     RECT  29.04 86.003 29.712 86.099 ;
     RECT  4.128 85.139 5.544 86.197 ;
     RECT  3.936 86.197 5.544 86.339 ;
     RECT  31.296 85.619 32.52 86.579 ;
     RECT  13.104 85.765 16.728 86.581 ;
     RECT  17.904 83.267 18.912 86.581 ;
     RECT  23.856 86.053 27.48 86.581 ;
     RECT  7.8 85.619 11.256 86.723 ;
     RECT  13.104 86.581 18.912 87.157 ;
     RECT  37.5 84.851 37.812 87.157 ;
     RECT  13.104 87.157 19.368 87.251 ;
     RECT  34.8 86.053 35.928 87.539 ;
     RECT  33.792 85.381 33.816 87.541 ;
     RECT  34.8 87.539 35.112 87.541 ;
     RECT  33.792 87.541 35.112 87.587 ;
     RECT  13.2 87.251 19.368 87.635 ;
     RECT  10.32 86.723 11.256 87.827 ;
     RECT  13.2 87.635 19.08 87.875 ;
     RECT  7.8 86.723 8.904 87.877 ;
     RECT  20.544 85.523 22.68 87.923 ;
     RECT  31.296 86.579 32.412 88.115 ;
     RECT  29.4 86.099 29.712 88.213 ;
     RECT  0.144 87.013 0.168 88.307 ;
     RECT  7.8 87.877 9.144 88.357 ;
     RECT  21.168 87.923 22.68 88.403 ;
     RECT  13.2 87.875 16.536 88.499 ;
     RECT  6.864 88.357 9.144 88.885 ;
     RECT  10.32 87.827 10.812 88.885 ;
     RECT  21.3 88.403 22.68 88.931 ;
     RECT  34.32 87.587 35.112 88.981 ;
     RECT  28.944 88.213 29.712 89.173 ;
     RECT  4.608 86.339 5.544 89.461 ;
     RECT  6.864 88.885 10.812 89.461 ;
     RECT  23.856 86.581 27.816 89.555 ;
     RECT  4.608 89.461 10.812 89.699 ;
     RECT  2.4 72.995 2.712 89.941 ;
     RECT  21.3 88.931 21.612 90.037 ;
     RECT  34.32 88.981 36.024 90.037 ;
     RECT  31.872 88.115 32.412 90.083 ;
     RECT  13.2 88.499 16.212 90.275 ;
     RECT  26.7 89.555 27.816 90.373 ;
     RECT  28.944 89.173 29.832 90.563 ;
     RECT  2.4 89.941 3.48 90.659 ;
     RECT  13.2 90.275 14.568 90.901 ;
     RECT  37.056 87.157 37.812 90.947 ;
     RECT  20.64 90.037 21.612 90.949 ;
     RECT  20.112 90.949 21.612 91.141 ;
     RECT  22.656 88.931 22.68 91.141 ;
     RECT  7.8 89.699 10.812 91.429 ;
     RECT  32.1 90.083 32.412 91.669 ;
     RECT  33.6 90.037 36.024 91.669 ;
     RECT  4.608 89.699 6.12 91.717 ;
     RECT  7.8 91.429 11.448 91.717 ;
     RECT  13.104 90.901 14.568 91.717 ;
     RECT  15.648 90.275 16.212 91.717 ;
     RECT  32.1 91.669 36.024 91.763 ;
     RECT  20.112 91.141 22.68 91.811 ;
     RECT  4.608 91.717 11.448 91.859 ;
     RECT  20.112 91.811 21.612 91.859 ;
     RECT  26.7 90.373 27.96 92.149 ;
     RECT  32.1 91.763 35.928 92.195 ;
     RECT  2.4 90.659 3.288 92.197 ;
     RECT  23.856 89.555 25.512 92.339 ;
     RECT  5.1 91.859 11.448 92.387 ;
     RECT  13.104 91.717 16.212 92.435 ;
     RECT  26.7 92.149 28.248 92.435 ;
     RECT  18 87.875 19.08 92.725 ;
     RECT  32.1 92.195 35.832 92.771 ;
     RECT  22.656 91.811 22.68 92.773 ;
     RECT  13.2 92.435 16.212 92.869 ;
     RECT  17.616 92.725 19.08 92.869 ;
     RECT  5.1 92.387 10.812 92.915 ;
     RECT  32.1 92.771 33.624 92.915 ;
     RECT  28.224 92.435 28.248 92.963 ;
     RECT  5.1 92.915 6.792 93.059 ;
     RECT  23.856 92.339 24.504 93.107 ;
     RECT  5.1 93.059 6.696 93.493 ;
     RECT  13.2 92.869 19.08 93.539 ;
     RECT  29.4 90.563 29.832 93.539 ;
     RECT  2.4 92.197 3.96 93.589 ;
     RECT  4.992 93.493 6.696 93.589 ;
     RECT  20.544 91.859 21.612 93.733 ;
     RECT  7.8 92.915 10.812 93.827 ;
     RECT  20.352 93.733 21.612 93.875 ;
     RECT  33.6 92.915 33.624 93.877 ;
     RECT  34.8 92.771 35.832 93.925 ;
     RECT  13.2 93.539 14.232 94.021 ;
     RECT  15.648 93.539 19.08 94.115 ;
     RECT  32.1 92.915 32.412 94.165 ;
     RECT  21.072 93.875 21.612 94.261 ;
     RECT  22.656 92.773 22.872 94.261 ;
     RECT  13.104 94.021 14.232 94.597 ;
     RECT  15.648 94.115 16.212 94.597 ;
     RECT  32.1 94.165 32.568 94.597 ;
     RECT  33.6 93.877 33.672 94.597 ;
     RECT  32.1 94.597 33.672 94.739 ;
     RECT  2.4 93.589 6.696 94.931 ;
     RECT  24 93.107 24.504 94.981 ;
     RECT  25.488 92.339 25.512 94.981 ;
     RECT  21.072 94.261 22.872 95.077 ;
     RECT  24 94.981 25.512 95.077 ;
     RECT  13.104 94.597 16.212 95.219 ;
     RECT  17.616 94.115 19.08 95.411 ;
     RECT  21.072 95.077 25.512 95.413 ;
     RECT  34.8 93.925 35.88 95.603 ;
     RECT  11.808 95.653 11.832 95.701 ;
     RECT  14.976 95.219 16.212 95.747 ;
     RECT  32.1 94.739 33.624 95.747 ;
     RECT  7.8 93.827 9.24 95.893 ;
     RECT  10.32 93.827 10.812 95.893 ;
     RECT  2.4 94.931 3.48 95.989 ;
     RECT  4.512 94.931 6.696 95.989 ;
     RECT  2.4 95.989 6.696 96.229 ;
     RECT  7.8 95.893 10.812 96.229 ;
     RECT  37.5 90.947 37.812 96.277 ;
     RECT  20.64 95.413 25.512 96.515 ;
     RECT  13.104 95.219 13.8 96.565 ;
     RECT  17.664 95.411 19.08 96.565 ;
     RECT  34.8 95.603 35.832 96.757 ;
     RECT  2.4 96.229 10.812 96.803 ;
     RECT  22.896 96.515 25.512 96.803 ;
     RECT  7.104 96.803 10.812 96.805 ;
     RECT  11.808 95.701 12.024 96.805 ;
     RECT  32.1 95.747 33.288 96.853 ;
     RECT  34.8 96.757 35.88 96.853 ;
     RECT  2.4 96.803 6.024 97.091 ;
     RECT  22.896 96.803 24.504 97.283 ;
     RECT  26.7 92.435 27.012 97.333 ;
     RECT  2.4 97.091 5.64 97.379 ;
     RECT  15.648 95.747 16.212 97.381 ;
     RECT  17.664 96.565 19.368 97.381 ;
     RECT  37.056 96.277 37.812 97.427 ;
     RECT  32.1 96.853 35.88 97.429 ;
     RECT  20.64 96.515 21.612 97.523 ;
     RECT  31.296 97.429 35.88 97.523 ;
     RECT  7.104 96.805 12.024 97.525 ;
     RECT  31.296 97.523 33.288 97.813 ;
     RECT  7.104 97.525 12.12 97.859 ;
     RECT  24 97.283 24.504 97.861 ;
     RECT  25.488 96.803 25.512 97.861 ;
     RECT  7.8 97.859 12.12 97.907 ;
     RECT  24 97.861 25.512 97.907 ;
     RECT  13.104 96.565 14.28 97.909 ;
     RECT  15.648 97.381 19.368 97.909 ;
     RECT  13.104 97.909 19.368 98.099 ;
     RECT  22.896 97.283 22.968 98.099 ;
     RECT  24 97.907 25.128 98.099 ;
     RECT  17.712 98.099 19.368 98.291 ;
     RECT  34.8 97.523 35.88 98.293 ;
     RECT  26.592 97.333 27.012 98.339 ;
     RECT  13.104 98.099 16.344 98.435 ;
     RECT  20.784 97.523 21.612 98.533 ;
     RECT  22.896 98.099 22.92 98.533 ;
     RECT  20.784 98.533 22.92 98.579 ;
     RECT  34.8 98.293 35.976 98.581 ;
     RECT  17.904 98.291 19.368 98.675 ;
     RECT  2.4 97.379 5.544 98.725 ;
     RECT  34.608 98.581 35.976 98.917 ;
     RECT  24 98.099 24.504 98.963 ;
     RECT  15.312 98.435 16.344 99.109 ;
     RECT  2.4 98.725 6.216 99.157 ;
     RECT  13.104 98.435 14.28 99.157 ;
     RECT  20.784 98.579 22.536 99.157 ;
     RECT  24 98.963 24.456 99.157 ;
     RECT  15.312 99.109 16.728 99.251 ;
     RECT  13.056 99.157 14.28 99.443 ;
     RECT  26.7 98.339 27.012 99.445 ;
     RECT  7.8 97.907 11.976 99.491 ;
     RECT  34.608 98.917 36.12 99.685 ;
     RECT  37.5 97.427 37.812 99.685 ;
     RECT  10.272 99.491 11.976 99.779 ;
     RECT  13.056 99.443 14.232 99.779 ;
     RECT  20.544 99.157 22.536 99.779 ;
     RECT  21.3 99.779 22.536 100.211 ;
     RECT  34.608 99.685 37.812 100.259 ;
     RECT  29.4 93.539 29.712 100.261 ;
     RECT  31.152 97.813 33.288 100.261 ;
     RECT  34.704 100.259 37.812 100.307 ;
     RECT  23.712 99.157 24.456 100.355 ;
     RECT  15.312 99.251 16.344 100.501 ;
     RECT  15.312 100.501 16.44 100.693 ;
     RECT  17.904 98.675 18.912 100.693 ;
     RECT  15.312 100.693 18.912 100.835 ;
     RECT  21.3 100.211 21.612 100.837 ;
     RECT  0.144 100.693 0.168 100.883 ;
     RECT  23.904 100.355 24.456 100.931 ;
     RECT  13.104 99.779 14.232 101.413 ;
     RECT  15.312 100.835 16.44 101.413 ;
     RECT  26.7 99.445 27.144 101.413 ;
     RECT  19.92 100.597 19.944 101.507 ;
     RECT  2.4 99.157 6.312 101.555 ;
     RECT  34.8 100.307 37.812 101.699 ;
     RECT  29.4 100.261 33.288 101.701 ;
     RECT  34.8 101.699 35.208 101.701 ;
     RECT  29.4 101.701 35.208 101.747 ;
     RECT  13.104 101.413 16.44 101.891 ;
     RECT  29.4 101.747 33.048 101.987 ;
     RECT  7.8 99.491 9.288 101.989 ;
     RECT  10.272 99.779 11.736 101.989 ;
     RECT  36.192 101.699 37.812 102.131 ;
     RECT  2.4 101.555 6.168 102.419 ;
     RECT  23.904 100.931 24.408 102.469 ;
     RECT  25.632 102.133 25.656 102.469 ;
     RECT  23.136 102.469 25.656 102.515 ;
     RECT  4.224 102.419 6.168 102.659 ;
     RECT  26.7 101.413 27.336 102.659 ;
     RECT  7.8 101.989 11.736 102.805 ;
     RECT  34.224 101.747 35.208 102.805 ;
     RECT  7.488 102.805 11.736 102.851 ;
     RECT  13.104 101.891 16.344 102.995 ;
     RECT  5.1 102.659 6.168 103.235 ;
     RECT  36.624 102.131 37.812 103.235 ;
     RECT  13.2 102.995 16.344 103.427 ;
     RECT  29.4 101.987 32.952 104.051 ;
     RECT  5.1 103.235 5.544 104.245 ;
     RECT  10.272 102.851 11.736 104.245 ;
     RECT  34.224 102.805 35.352 104.245 ;
     RECT  13.2 103.427 16.212 104.291 ;
     RECT  20.928 100.837 21.612 104.293 ;
     RECT  10.272 104.245 11.976 104.339 ;
     RECT  20.304 104.293 21.612 104.339 ;
     RECT  31.584 104.051 32.952 104.339 ;
     RECT  23.136 102.515 25.512 104.387 ;
     RECT  15.6 104.291 16.212 104.435 ;
     RECT  15.9 104.435 16.212 104.581 ;
     RECT  20.304 104.339 20.328 104.627 ;
     RECT  4.464 104.245 5.544 104.629 ;
     RECT  7.488 102.851 9.288 104.675 ;
     RECT  7.8 104.675 9.288 104.725 ;
     RECT  13.2 104.291 14.424 104.821 ;
     RECT  26.7 102.659 27.012 104.821 ;
     RECT  29.4 104.051 30.6 104.821 ;
     RECT  4.464 104.629 6.216 104.867 ;
     RECT  13.056 104.821 14.424 104.963 ;
     RECT  26.7 104.821 27.912 104.963 ;
     RECT  23.136 104.387 25.416 105.397 ;
     RECT  26.7 104.963 27.864 105.397 ;
     RECT  34.224 104.245 35.784 105.443 ;
     RECT  17.904 100.835 18.912 105.733 ;
     RECT  13.056 104.963 13.608 105.923 ;
     RECT  21.3 104.339 21.612 105.925 ;
     RECT  37.5 103.235 37.812 105.925 ;
     RECT  29.232 104.821 30.6 106.117 ;
     RECT  31.584 104.339 32.412 106.117 ;
     RECT  4.512 104.867 6.216 106.261 ;
     RECT  7.8 104.725 9.336 106.261 ;
     RECT  21.168 105.925 21.612 106.309 ;
     RECT  23.136 105.397 27.864 106.309 ;
     RECT  15.9 104.581 16.488 106.405 ;
     RECT  4.512 106.261 9.336 106.451 ;
     RECT  29.232 106.117 32.412 106.499 ;
     RECT  21.168 106.309 28.056 106.501 ;
     RECT  29.232 106.499 30.984 106.501 ;
     RECT  0.144 106.357 0.168 106.547 ;
     RECT  21.168 106.501 30.984 106.549 ;
     RECT  4.512 106.451 9.048 106.595 ;
     RECT  20.496 106.549 30.984 106.643 ;
     RECT  24 106.643 30.984 106.739 ;
     RECT  36.624 105.925 37.812 106.739 ;
     RECT  34.224 105.443 35.112 106.883 ;
     RECT  17.904 105.733 19.176 106.979 ;
     RECT  30.96 106.739 30.984 106.979 ;
     RECT  13.056 105.923 13.512 107.077 ;
     RECT  32.1 106.499 32.412 107.077 ;
     RECT  10.5 104.339 11.976 107.125 ;
     RECT  5.1 106.595 9.048 107.219 ;
     RECT  10.368 107.125 11.976 107.221 ;
     RECT  10.368 107.221 12.072 107.317 ;
     RECT  13.056 107.077 13.608 107.317 ;
     RECT  10.368 107.317 13.608 107.363 ;
     RECT  15.9 106.405 16.728 107.461 ;
     RECT  18.6 106.979 19.176 107.461 ;
     RECT  20.496 106.643 22.536 107.461 ;
     RECT  24 106.739 29.712 107.555 ;
     RECT  15.9 107.461 17.112 107.603 ;
     RECT  12.912 107.363 13.608 107.653 ;
     RECT  18.6 107.461 22.536 107.699 ;
     RECT  20.208 107.699 22.536 107.747 ;
     RECT  12.912 107.653 13.656 107.749 ;
     RECT  10.368 107.363 11.448 107.843 ;
     RECT  5.1 107.219 6.216 108.083 ;
     RECT  12.912 107.749 13.752 108.085 ;
     RECT  37.152 106.739 37.812 108.085 ;
     RECT  12.912 108.085 14.04 108.131 ;
     RECT  24 107.555 28.056 108.131 ;
     RECT  37.056 108.085 37.812 108.227 ;
     RECT  5.1 108.083 5.412 108.277 ;
     RECT  25.344 108.131 28.056 108.323 ;
     RECT  13.104 108.131 14.04 108.371 ;
     RECT  27.984 108.323 28.056 108.371 ;
     RECT  20.208 107.747 21.612 108.851 ;
     RECT  29.4 107.555 29.712 108.853 ;
     RECT  25.344 108.323 27.012 108.899 ;
     RECT  37.152 108.227 37.812 108.899 ;
     RECT  20.208 108.851 20.232 108.947 ;
     RECT  37.248 108.899 37.812 108.995 ;
     RECT  7.8 107.219 9.048 108.997 ;
     RECT  40.896 108.901 40.92 109.043 ;
     RECT  29.088 108.853 29.712 109.091 ;
     RECT  15.9 107.603 16.92 109.139 ;
     RECT  7.8 108.997 9.432 109.237 ;
     RECT  7.344 109.237 9.432 109.381 ;
     RECT  10.5 107.843 11.448 109.381 ;
     RECT  25.392 108.899 27.012 109.381 ;
     RECT  27.984 108.371 28.008 109.381 ;
     RECT  25.392 109.381 28.008 109.667 ;
     RECT  7.344 109.381 11.448 109.715 ;
     RECT  25.392 109.667 27.96 109.715 ;
     RECT  10.272 109.715 11.448 109.811 ;
     RECT  18.6 107.699 19.176 109.957 ;
     RECT  34.8 106.883 35.112 109.957 ;
     RECT  26.256 109.715 27.96 110.003 ;
     RECT  24 108.131 24.312 110.005 ;
     RECT  7.344 109.715 9 110.051 ;
     RECT  7.344 110.051 8.904 110.195 ;
     RECT  32.1 107.077 32.52 110.485 ;
     RECT  13.2 108.371 14.04 110.533 ;
     RECT  4.368 108.277 5.412 110.771 ;
     RECT  12.816 110.533 14.04 110.869 ;
     RECT  29.28 109.091 29.712 110.869 ;
     RECT  34.512 109.957 35.112 110.869 ;
     RECT  32.1 110.485 32.952 111.059 ;
     RECT  29.28 110.869 30.216 111.155 ;
     RECT  26.7 110.003 27.96 111.203 ;
     RECT  23.136 110.005 24.312 111.299 ;
     RECT  26.7 111.203 27.012 111.301 ;
     RECT  29.4 111.155 30.216 111.731 ;
     RECT  10.272 109.811 10.812 111.779 ;
     RECT  12.816 110.869 14.28 111.779 ;
     RECT  26.112 111.301 27.012 111.827 ;
     RECT  13.2 111.779 13.608 111.875 ;
     RECT  18.6 109.957 19.368 111.875 ;
     RECT  34.464 110.869 35.112 112.259 ;
     RECT  2.4 102.419 2.712 112.329 ;
     RECT  5.1 110.771 5.412 112.329 ;
     RECT  10.5 111.779 10.812 112.329 ;
     RECT  13.2 111.875 13.512 112.329 ;
     RECT  15.9 109.139 16.212 112.329 ;
     RECT  18.6 111.875 18.912 112.329 ;
     RECT  21.3 108.851 21.612 112.329 ;
     RECT  24 111.299 24.312 112.329 ;
     RECT  26.7 111.827 27.012 112.329 ;
     RECT  29.4 111.731 29.712 112.329 ;
     RECT  32.1 111.059 32.412 112.329 ;
     RECT  34.8 112.259 35.112 112.329 ;
     RECT  37.5 108.995 37.812 112.329 ;
     RECT  2.4 112.329 2.52 112.343 ;
     RECT  5.1 112.329 5.22 112.343 ;
     RECT  7.8 110.195 8.904 112.343 ;
     RECT  10.5 112.329 10.62 112.343 ;
     RECT  13.2 112.329 13.32 112.343 ;
     RECT  15.9 112.329 16.02 112.343 ;
     RECT  18.6 112.329 18.72 112.343 ;
     RECT  21.3 112.329 21.42 112.343 ;
     RECT  24 112.329 24.12 112.343 ;
     RECT  26.7 112.329 26.82 112.343 ;
     RECT  29.4 112.329 29.52 112.343 ;
     RECT  32.1 112.329 32.22 112.343 ;
     RECT  34.8 112.329 34.92 112.343 ;
     RECT  37.5 112.329 37.62 112.343 ;
     RECT  8.448 112.343 8.904 113.459 ;
     RECT  8.88 113.459 8.904 114.419 ;
  END
END dsfd_dvland_682
END LIBRARY
